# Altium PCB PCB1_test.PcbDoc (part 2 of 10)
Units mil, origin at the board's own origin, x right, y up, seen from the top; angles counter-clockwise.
Board outline 6690 x 6690 mil, 6 copper layers (Layer 1 - Top Layer, Layer 2 - GND, Layer 3 - PWR, Layer 4 - Signal, Layer 5 - GND, Layer 6 - Bottom Layer), stack 80.244 mil thick; 821 components, 458 nets, 3746 pads, 1527 vias.

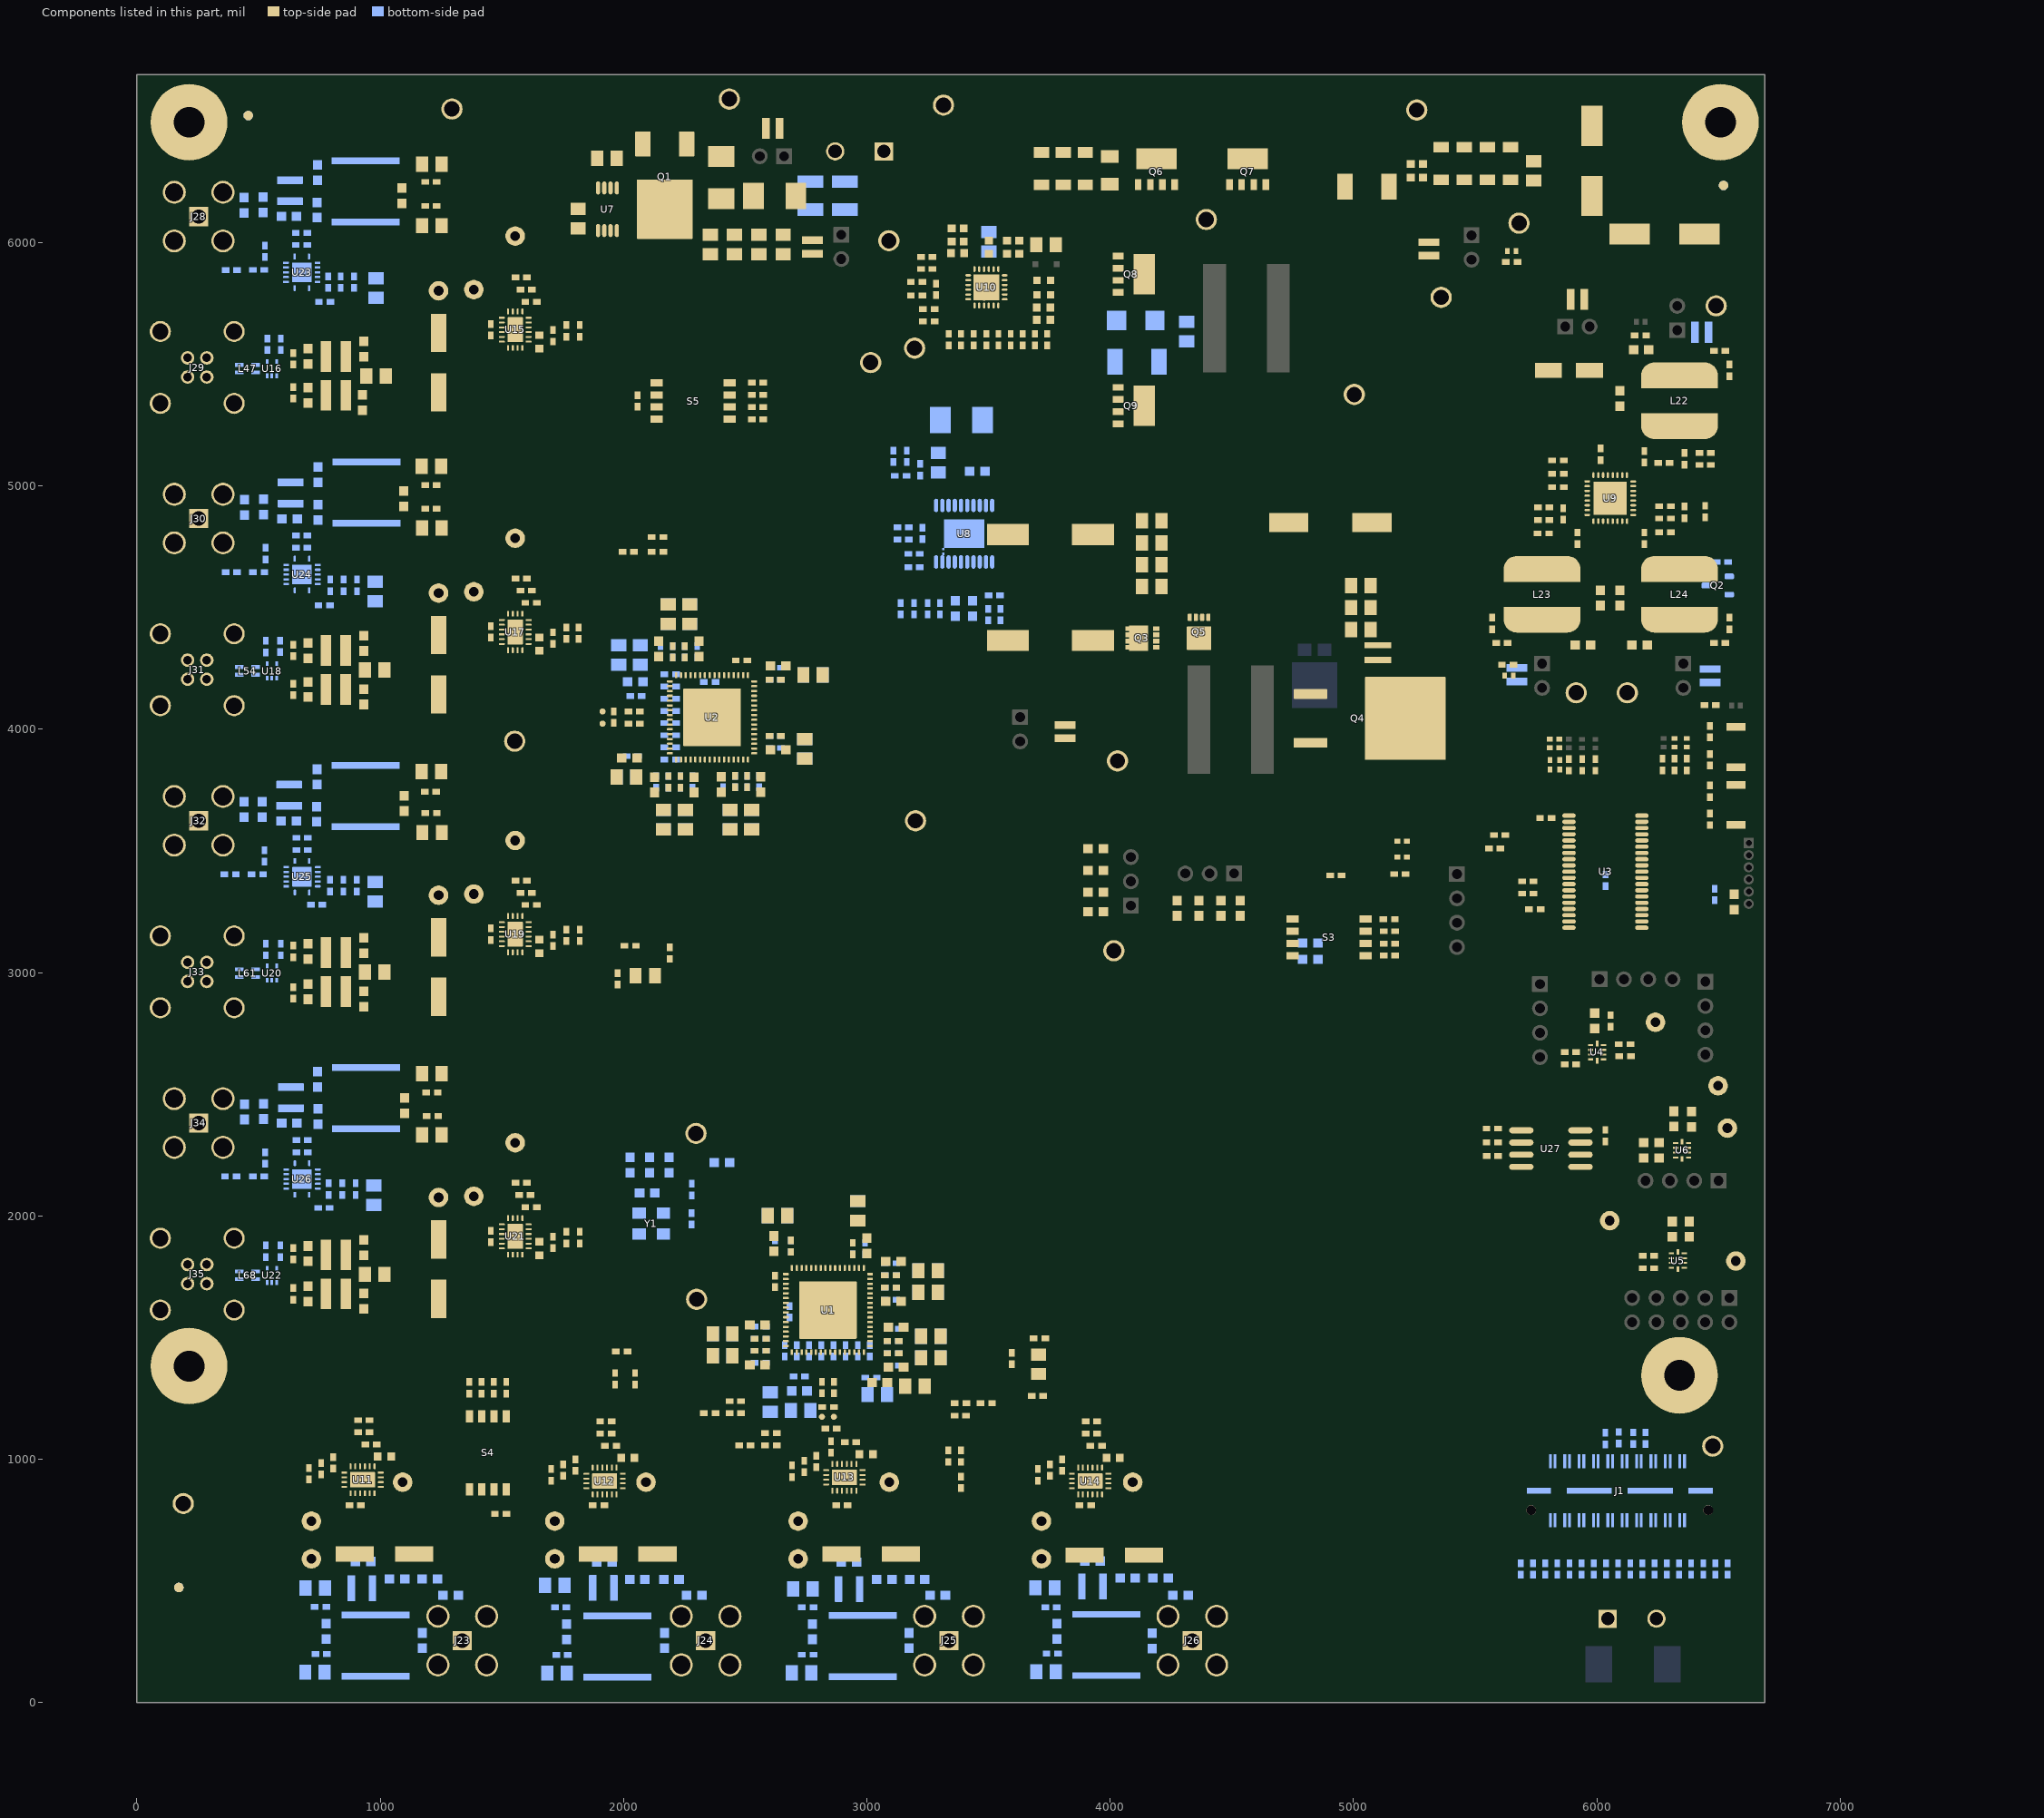
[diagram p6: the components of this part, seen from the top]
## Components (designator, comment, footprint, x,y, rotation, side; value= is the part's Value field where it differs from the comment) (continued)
L27 "MPZ1608S102ATA00" 0603 1766.93,291.41 r90 bottom value="1000 ohm"
L28 "LQH3NPZ100MJRL" LQH3NPZ_JR 925,470 r180 bottom value=10uH
L29 "LQH3NPZ100MJRL" LQH3NPZ_JR 1916.93,471.41 r180 bottom value=10uH
L30 "BLM18HE152SN1D" 0603 1069.95,508.45 r180 bottom value="1500 ohm"
L31 "BLM18HE152SN1D" 0603 2056.93,506.41 r180 bottom value="1500 ohm"
L32 "BLM18HE152SN1D" 0603 1203.94,508.45 r180 bottom value="1500 ohm"
L33 "BLM18HE152SN1D" 0603 2196.93,506.41 r180 bottom value="1500 ohm"
L34 "MPZ1608S102ATA00" 0603 2776.93,291.92 r90 bottom value="1000 ohm"
L35 "MPZ1608S102ATA00" 0603 3781.93,293.42 r90 bottom value="1000 ohm"
L36 "BLM18HE152SN1D" 0603 1290,441 r180 bottom value="1500 ohm"
L37 "BLM18HE152SN1D" 0603 2291,442 r180 bottom value="1500 ohm"
L38 "LQH3NPZ100MJRL" LQH3NPZ_JR 2926.93,466.92 r180 bottom value=10uH
L39 "LQH3NPZ100MJRL" LQH3NPZ_JR 3926.93,476.92 r180 bottom value=10uH
L40 "BLM18HE152SN1D" 0603 3071.93,506.92 r180 bottom value="1500 ohm"
L41 "BLM18HE152SN1D" 0603 4071.93,511.92 r180 bottom value="1500 ohm"
L42 "MPZ1608S102ATA00" 0603 1089,6192.5 r270 top value="1000 ohm"
L43 "BLM18HE152SN1D" 0603 3206.93,506.92 r180 bottom value="1500 ohm"
L44 "BLM18HE152SN1D" 0603 4206.93,511.92 r180 bottom value="1500 ohm"
L45 "EPL3012-103MLB" EPL3012 818,5372.38 r0 top value=10uH
L46 "EPL3012-103MLB" EPL3012 818,5532.38 r0 top value=10uH
L47 "DLW21HN900SQ2L" DLW21H 455,5482 r270 bottom
L48 "BLM18HE152SN1D" 0603 3291,441 r180 bottom value="1500 ohm"
L49 "MPZ1608S102ATA00" 0603 1097,4947.5 r270 top value="1000 ohm"
L50 "BLM18HE152SN1D" 0603 4289,442 r180 bottom value="1500 ohm"
L51 "LQH3NPZ100MJRL" LQH3NPZ_JR 629.28,6213.02 r90 bottom value=10uH
L52 "EPL3012-103MLB" EPL3012 817.91,4163.62 r0 top value=10uH
L53 "EPL3012-103MLB" EPL3012 817.91,4323.62 r0 top value=10uH
L54 "DLW21HN900SQ2L" DLW21H 455,4240 r270 bottom
L55 "BLM18HE152SN1D" 0603 625.28,6107.02 r0 bottom value="1500 ohm"
L56 "MPZ1608S102ATA00" 0603 1098.38,3695.62 r270 top value="1000 ohm"
L57 "BLM18HE152SN1D" 0603 519.28,6155.02 r270 bottom value="1500 ohm"
L58 "BLM18HE152SN1D" 0603 440.28,6154.02 r90 bottom value="1500 ohm"
L59 "EPL3012-103MLB" EPL3012 818,2922 r0 top value=10uH
L60 "EPL3012-103MLB" EPL3012 818,3082 r0 top value=10uH
L61 "DLW21HN900SQ2L" DLW21H 455,2998 r270 bottom
L62 "LQH3NPZ100MJRL" LQH3NPZ_JR 632,4970.97 r90 bottom value=10uH
L63 "MPZ1608S102ATA00" 0603 1101,2453 r270 top value="1000 ohm"
L64 "BLM18HE152SN1D" 0603 628,4864.97 r0 bottom value="1500 ohm"
L65 "BLM18HE152SN1D" 0603 521,4913.97 r270 bottom value="1500 ohm"
L66 "EPL3012-103MLB" EPL3012 818,1680 r0 top value=10uH
L67 "EPL3012-103MLB" EPL3012 818,1840 r0 top value=10uH
L68 "DLW21HN900SQ2L" DLW21H 455,1756 r270 bottom
L69 "BLM18HE152SN1D" 0603 442,4911.97 r90 bottom value="1500 ohm"
L70 "LQH3NPZ100MJRL" LQH3NPZ_JR 626.5,3729 r90 bottom value=10uH
L71 "BLM18HE152SN1D" 0603 624.5,3623 r0 bottom value="1500 ohm"
L72 "BLM18HE152SN1D" 0603 515.5,3671 r270 bottom value="1500 ohm"
L73 "BLM18HE152SN1D" 0603 441.5,3670 r90 bottom value="1500 ohm"
L74 "LQH3NPZ100MJRL" LQH3NPZ_JR 633,2486 r90 bottom value=10uH
L75 "BLM18HE152SN1D" 0603 627,2381 r0 bottom value="1500 ohm"
L76 "BLM18HE152SN1D" 0603 521,2430 r270 bottom value="1500 ohm"
L77 "BLM18HE152SN1D" 0603 442,2428 r90 bottom value="1500 ohm"
L78 "BLM18SG121TN1D" 0603 2404.92,2219.48 r0 bottom value="120 ohm"
L79 "MSS7341-104MLB" MSS7341 981,234 r270 bottom value=100uH
L80 "MSS7341-104MLB" MSS7341 1974,231 r270 bottom value=100uH
L81 "MSS7341-104MLB" MSS7341 2984,232 r270 bottom value=100uH
L82 "MSS7341-104MLB" MSS7341 3984,237 r270 bottom value=100uH
L83 "MSS7341-104MLB" MSS7341 940.28,6210.04 r90 bottom value=100uH
L84 "MSS7341-104MLB" MSS7341 944,4972.96 r90 bottom value=100uH
L85 "MSS7341-104MLB" MSS7341 939.5,3726 r90 bottom value=100uH
L86 "MSS7341-104MLB" MSS7341 943,2483.98 r90 bottom value=100uH
Logo1 "Texas Instruments" TI_Stacked_Overlay_Small 4157.12,2878.1 r0 top
Logo2 "RoHS Exempt" RoHS_Exempt 2731.09,2357.8 r0 top
Logo3 "FCC disclaimer" FCC_disclaimer 1268.88,2231.3 r0 top
NT1 "Net-Tie" Net-Tie_10mil 3481.38,5756.38 r270 top net-tie
NT2 "Net-Tie" Net-Tie_10mil 3313.84,4730.86 r90 bottom net-tie
Q1 "IPD90N04S304ATMA1" DPAK 2169.66,6271.35 r270 top value=40V
Q2 "BSS138" SOT-23 6496.55,4590.91 r180 bottom value=50V
Q3 "CSD17577Q3A" TRANS_NexFET_Q3A 4125,4375 r180 top value=30V
Q4 "CSD19536KTT" KTT0002A_N 5065,4045 r0 top value=100V
Q5 "CSD16340Q3" DQG0008A 4365,4400 r270 top value=25V
Q6 "BUK9Y21-40E,115" LFPAK56 4190,6345 r0 top value=40V
Q7 "BUK9Y21-40E,115" LFPAK56 4565,6345 r0 top value=40V
Q8 "BUK9Y21-40E,115" LFPAK56 4140,5870 r270 top value=40V
Q9 "BUK9Y21-40E,115" LFPAK56 4140,5330 r270 top value=40V
R1 "CRCW04020000Z0ED" 0402#1 5687.23,549.48 r90 bottom value=0
R2 "CRCW04020000Z0ED" 0402#1 5737.23,549.48 r270 bottom value=0
R3 "CRCW04020000Z0ED" 0402#1 5787.23,549.48 r90 bottom value=0
R4 "CRCW04020000Z0ED" 0402#1 5837.23,549.48 r270 bottom value=0
R5 "CRCW04020000Z0ED" 0402#1 5887.23,549.48 r90 bottom value=0
R6 "CRCW04020000Z0ED" 0402#1 5937.23,549.48 r270 bottom value=0
R7 "CRCW04020000Z0ED" 0402#1 5987.23,549.48 r90 bottom value=0
R8 "CRCW04020000Z0ED" 0402#1 6037.23,549.48 r270 bottom value=0
R9 "CRCW04020000Z0ED" 0402#1 6087.23,549.48 r90 bottom value=0
R10 "CRCW04020000Z0ED" 0402#1 6137.23,549.48 r270 bottom value=0
R11 "CRCW04020000Z0ED" 0402#1 6187.23,549.48 r90 bottom value=0
R12 "CRCW04020000Z0ED" 0402#1 6237.23,549.48 r270 bottom value=0
R13 "CRCW04020000Z0ED" 0402#1 6149.3,1086.63 r90 bottom value=0
R14 "CRCW04020000Z0ED" 0402#1 6199.3,1086.63 r270 bottom value=0
R15 "CRCW04020000Z0ED" 0402#1 6287.23,549.48 r90 bottom value=0
R16 "CRCW04020000Z0ED" 0402#1 6337.23,549.48 r270 bottom value=0
R17 "CRCW04020000Z0ED" 0402#1 6387.23,549.48 r90 bottom value=0
R18 "CRCW04020000Z0ED" 0402#1 6437.23,549.48 r270 bottom value=0
R19 "CRCW04020000Z0ED" 0402#1 6487.23,549.48 r90 bottom value=0
R20 "CRCW04020000Z0ED" 0402#1 6537.23,549.48 r270 bottom value=0
R21 "CRCW040213K3FKED" 0402#1 1992.56,1442.68 r0 top value=13.3k
R22 "CRCW0402487RFKED" 0402#1 3700.76,1260.96 r0 top value=487
R23 "CRCW040213K3FKED" 0402#1 1366,1293.87 r90 top value=13.3k
R24 "CRCW040282K5FKED" 0402#1 1416,1293.87 r90 top value=82.5k
R25 "CRCW040240K2FKED" 0402#1 2047.56,1330.87 r90 top value=40.2k
R26 "CRCW040210K0JNED" 0402#1 3595.36,1414.27 r90 top value=10k
R27 "CRCW040240K2FKED" 0402#1 1467.42,1293.87 r90 top value=40.2k
R28 "CRCW0402102KFKED" 0402#1 1518,1293.87 r90 top value=102k
R29 "CRCW0402100RFKED" 0402#1 2840.56,1214.49 r0 top value=100
R30 "CRCW040210K0JNED" 0402#1 3709.25,1497.08 r0 top value=10k
R31 "CRCW040210K0JNED" 0402#1 2280.09,1988.25 r90 bottom value=10k
R32 "CRCW06030000Z0EA" 0603 2027.79,2209.09 r90 bottom value=0
R33 "CRCW06030000Z0EA" 0603 2107.79,2209.09 r90 bottom value=0
R34 "CRCW0402113KFKED" 0402#1 2020,4730 r180 top value=113k
R35 "CRCW0402487RFKED" 0402#1 1976.09,2974.41 r270 top value=487
R36 "CRCW040213K3FKED" 0402#1 2551.31,5424.2 r0 top value=13.3k
R37 "CRCW040282K5FKED" 0402#1 2551.31,5374.2 r0 top value=82.5k
R38 "CRCW040288K7FKED" 0402#1 2140,4790 r180 top value=88.7k
R39 "CRCW040210K0JNED" 0402#1 2027.73,3110.22 r180 top value=10k
R40 "CRCW040240K2FKED" 0402#1 2551.31,5324.2 r0 top value=40.2k
R41 "CRCW0402102KFKED" 0402#1 2551.31,5274.2 r0 top value=102k
R42 "CRCW0402100RFKED" 0402#1 1960,4050 r270 top value=100
R43 "CRCW040210K0JNED" 0402#1 2190,3080 r90 top value=10k
R44 "CRCW0402200RJNED" 0402#1 5190,3405 r0 top value=200
R45 "CRCW0402200RJNED" 0402#1 5600,3565 r180 top value=200
R46 "CRCW0402200RJNED" 0402#1 5580,3510 r180 top value=200
R47 "CRCW0402200RJNED" 0402#1 6035,1085 r90 bottom value=200
R48 "CRCW0402200RJNED" 0402#1 6090,1088.62 r90 bottom value=200
R49 "CRCW0402200RJNED" 0402#2 5200,3475 r0 top value=200
R50 "CRCW0402200RJNED" 0402#2 5200,3540 r0 top value=200
R51 "CRCW0402220RJNED" 0402#1 5885,3853.62 r270 top value=220
R52 "CRCW040210K0JNED" 0402#1 6465,3990 r90 top value=10k
R53 "CRCW040210K0JNED" 0402#1 6465,3745 r90 top value=10k
R54 "CRCW04024K70JNED" 0402#1 6114.17,2706.06 r0 top value=4.7K
R55 "CRCW04024K70JNED" 0402#1 6115.98,2656.06 r0 top value=4.7K
R56 "CRCW04024K70JNED" 0402#1 5890.98,2672.86 r0 top value=4.7K
R57 "CRCW04024K70JNED" 0402#1 5890.98,2622.86 r0 top value=4.7K
R58 "CRCW0402487RFKED" 0402#2 5847,3854.62 r270 top value=487
R59 "CRCW0402487RFKED" 0402#2 5807,3854.62 r270 top value=487
R60 "CRCW0402220RJNED" 0402#1 5940,3853.62 r270 top value=220
R61 "CRCW0402220RJNED" 0402#1 5994,3853.62 r270 top value=220
R62 "CRCW06034K02FKEA" 0603 930,580 r180 bottom value=4.02k
R63 "CRCW04020000Z0ED" 0402#1 5716.22,3375 r0 top value=0
R64 "CRCW04020000Z0ED" 0402#1 5716.22,3325 r0 top value=0
R65 "CRCW040220K0JNED" 0402#1 6055.98,2801.56 r270 top value=20k
R66 "CRCW06030000Z0EA" 0603 6565,3290 r270 top value=0
R67 "CRCW04024K70JNED" 0402#1 6211.69,1836.33 r180 top value=4.7K
R68 "CRCW04024K70JNED" 0402#1 6211.69,1785.33 r180 top value=4.7K
R69 "CRCW06034K70JNEA" 0603 6379.69,1945.63 r270 top value=4.7k
R70 "CRCW06034K70JNEA" 0603 6389,2398 r270 top value=4.7k
R71 "CRCW06034K70JNEA" 0603 6224,2301 r180 top value=4.7k
R72 "CRCW06034K70JNEA" 0603 6223.37,2238.7 r180 top value=4.7k
R73 "CRCW0402100RFKED" 0402#1 3498.84,4470.86 r270 bottom value=100
R74 "CRCW0402100RFKED" 0402#1 3548.84,4470.86 r270 bottom value=100
R75 "CRCW06030000Z0EA" 0603 3433.84,4495.86 r270 bottom value=0
R76 "CRCW040249K9FKED" 0402#1 3300,4495 r270 bottom value=49.9k
R77 "CRCW040247K0JNED" 0402#1 3193.84,4665.86 r180 bottom value=47k
R78 "CRCW04020000Z0ED" 0402#1 3138.84,5041.69 r180 bottom value=0
R79 "CRCW040218K2FKED" 0402#1 3250,4495 r90 bottom value=18.2k
R80 "CRCW040228K7FKED" 0402#1 3138.84,4495.86 r90 bottom value=28.7k
R81 "CRCW0402107KFKED" 0402#1 3108.84,5121.69 r270 bottom value=107k
R82 "CRCW04025K23FKED" 0402#1 3193.84,4720.86 r0 bottom value=5.23k
R83 "CRCW04020000Z0ED" 0402#1 3163.84,5121.69 r270 bottom value=0
R84 "CRCW040228K0FKED" 0402#1 3148.84,4829.66 r180 bottom value=28.0k
R85 "CRCW040245K3FKED" 0402#1 6505,5555 r180 top value=45.3k
R86 "CRCW040214K0FKED" 0402#1 6444.77,5086.38 r180 top value=14.0k
R87 "CRCW040210K0JNED" 0402#1 6545,5475 r90 top value=10k
R88 "CRCW0402360RJNED" 0402#1 6179,5619 r180 top value=360
R89 "CRCW0402100KDHEDP" 0402#1 6515.59,4687.59 r180 bottom value=100k
R90 "CRCW040210R0JNED" 0402#1 5840,4995 r0 top value=10
R91 "CRCW040220K0JNED" 0402#1 5610,4355 r0 top value=20k
R92 "CRCW06034K02FKEA" 0603 1921.93,576.41 r180 bottom value=4.02k
R93 "CRCW06034K02FKEA" 0603 2926.93,576.92 r180 bottom value=4.02k
R94 "CRCW04026K98FKED" 0402#1 5861.22,4885 r270 top value=6.98k
R95 "CRCW040210K0JNED" 0402#1 5570,4435 r270 top value=10k
R96 "CRCW0402220RJNED" 0402#1 5633.35,4265 r0 top value=220
R97 "CRCW04028K25FKED" 0402#1 6505,4355 r180 top value=8.25k
R98 "CRCW04024K87FKED" 0402#1 6280,4916.65 r0 top value=4.87k
R99 "CRCW040210R0JNED" 0402#1 5840,5050 r0 top value=10
R100 "CRCW040221K5FKED" 0402#1 6445,4895 r90 top value=21.5k
R101 "CRCW040210K0JNED" 0402#1 6545,4435 r270 top value=10k
R102 "CRCW0402360RJNED" 0402#1 6465.31,4099.26 r0 top value=360
R103 "CRCW04020000Z0ED" 0402#1 3336.38,5601.38 r270 top value=0
R104 "CRCW04020000Z0ED" 0402#1 3690.95,5601.38 r270 top value=0
R105 "CRCW04020000Z0ED" 0402#1 3246.38,5941.38 r180 top value=0
R106 "CRCW04020000Z0ED" 0402#1 3640.95,5601.38 r270 top value=0
R107 "CRCW04020000Z0ED" 0402#1 3490.95,5601.38 r270 top value=0
R108 "CRCW06034R99FKEA" 0603L 3626.38,5981.38 r90 top value=4.99
R109 "CRCW06030000Z0EA" 0603L 3576.38,5981.38 r90 top value=0
R110 "CRCW04020000Z0ED" 0402#1 3386.38,5601.38 r90 top value=0
R111 "CRCW04020000Z0ED" 0402#1 3740.95,5601.38 r90 top value=0
R112 "CRCW04020000Z0ED" 0402#1 3246.38,5891.38 r0 top value=0
R113 "CRCW04020000Z0ED" 0402#1 3540.95,5601.38 r90 top value=0
R114 "CRCW06034R99FKEA" 0603L 3726.38,5682.68 r0 top value=4.99
R115 "CRCW06034R99FKEA" 0603L 3726.38,5732.68 r0 top value=4.99
R116 "CRCW06032R20JNEA" 0603L 3501.38,5981.38 r90 top value=2.2
R117 "PMR50HZPFV4L00" 2010 5055,6230 r0 top value=0.004
R118 "CRCW060349R9FKEA" 0603L 3348.03,6031.38 r90 top value=49.9
R119 "CRCW06030000Z0EA" 0603L 3398.03,6031.38 r90 top value=0
R120 "CRCW0805100KFKEA" 0805_HV 5740,6295 r270 top value=100k
R121 "CRCW04022K20JNED" 0402#1 5650,5920 r180 top value=2.2k
R122 "CRCW201010R0JNEF" 2010 4110,5510 r0 bottom value=10
R123 "CRCW040212K1FKED" 0402#1 3204.57,5783.03 r0 top value=12.1k
R124 "CRCW06034K02FKEA" 0603 3926.93,581.92 r180 bottom value=4.02k
R125 "CRCW06034K02FKEA" 0603 741.28,6134.02 r90 bottom value=4.02k
R126 "CRCW06034K02FKEA" 0603 744,4891.97 r90 bottom value=4.02k
R127 "CRCW06034K02FKEA" 0603 738.5,3651 r90 bottom value=4.02k
R128 "CRCW06030000Z0EA" 0603 4275,3265 r90 top value=0
R129 "CRCW06030000Z0EA" 0603 4365,3265 r90 top value=0
R130 "CRCW06030000Z0EA" 0603 4455,3265 r90 top value=0
R131 "CRCW06030000Z0EA" 0603 4535,3265 r90 top value=0
R132 "CRCW040249R9FKED" 0402#1 2354,1189 r0 top value=49.9
R133 "CRCW040249R9FKED" 0402#1 2499,1057 r0 top value=49.9
R134 "CRCW06032K00FKEA" 0603 1173,255 r270 bottom value=2.00k
R135 "CRCW06032K00FKEA" 0603 2169,255 r270 bottom value=2.00k
R136 "CRCW0402309KFKED" 0402#1 962.56,1060.87 r0 top value=309k
R137 "CRCW0402309KFKED" 0402#1 1947.56,1055.87 r0 top value=309k
R138 "CRCW0402100KDHEDP" 0402#1 897.56,810.87 r0 top value=100k
R139 "CRCW0402100KDHEDP" 0402#1 1897.56,810.87 r0 top value=100k
R140 "CRCW040269K8FKED" 0402#1 932.56,1110.87 r0 top value=69.8k
R141 "CRCW040269K8FKED" 0402#1 1927.56,1105.87 r0 top value=69.8k
R142 "CRCW040230K9FKED" 0402#1 932.56,1160.87 r180 top value=30.9k
R143 "CRCW040230K9FKED" 0402#1 1927.56,1155.87 r180 top value=30.9k
R144 "CRCW040244K2FKED" 0402#1 807.56,985.87 r270 top value=44.2k
R145 "CRCW040244K2FKED" 0402#1 1802.56,975.87 r270 top value=44.2k
R146 "CRCW040216K9FKED" 0402#1 707.56,940.87 r270 top value=16.9k
R147 "CRCW040216K9FKED" 0402#1 1702.56,935.87 r270 top value=16.9k
R148 "CRCW06034K02FKEA" 0603 744,2409 r90 bottom value=4.02k
R149 "CRCW040210K0JNED" 0402#1 5571,2247 r180 top value=10k
R150 "CRCW040210K0JNED" 0402#1 5570,2303 r180 top value=10k
R151 "CRCW040210K0JNED" 0402#1 5570,2359 r180 top value=10k
R152 "CRCW040249R9FKED" 0402#1 3387,905 r90 top value=49.9
R153 "CRCW040249R9FKED" 0402#1 3491,1230 r180 top value=49.9
R154 "CRCW06032K00FKEA" 0603 3173,255 r270 bottom value=2.00k
R155 "CRCW06032K00FKEA" 0603 4173,254 r270 bottom value=2.00k
R156 "CRCW0402309KFKED" 0402#1 2932.56,1070.87 r0 top value=309k
R157 "CRCW0402309KFKED" 0402#1 3942.56,1055.87 r0 top value=309k
R158 "CRCW0402100KDHEDP" 0402#1 2897.56,810.87 r0 top value=100k
R159 "CRCW0402100KDHEDP" 0402#1 3897.56,810.87 r0 top value=100k
R160 "CRCW040269K8FKED" 0402#1 2852.56,1050.87 r90 top value=69.8k
R161 "CRCW040269K8FKED" 0402#1 3922.56,1105.87 r0 top value=69.8k
R162 "CRCW040230K9FKED" 0402#1 2852.56,1125.87 r180 top value=30.9k
R163 "CRCW040230K9FKED" 0402#1 3922.56,1155.87 r180 top value=30.9k
R164 "CRCW040244K2FKED" 0402#1 2792.56,990.87 r270 top value=44.2k
R165 "CRCW040244K2FKED" 0402#1 3802.56,975.87 r270 top value=44.2k
R166 "CRCW040216K9FKED" 0402#1 2692.56,950.87 r270 top value=16.9k
R167 "CRCW040216K9FKED" 0402#1 3702.56,935.87 r270 top value=16.9k
R168 "CRCW06030000Z0EA" 0603 3940,3510 r0 top value=0
R169 "CRCW06030000Z0EA" 0603 3940,3420 r0 top value=0
R170 "CRCW06030000Z0EA" 0603 3940,3330 r0 top value=0
R171 "CRCW06030000Z0EA" 0603 3940,3250 r0 top value=0
R172 "KRL2012E-M-R010-F-T5" KRL2012 2776,5982 r270 top value=0.01
R173 "KRL2012E-M-R010-F-T5" KRL2012 2613,6470 r180 top value=0.01
R174 "CRCW06030000Z0EA" 0603 928,5342.38 r90 top value=0
R175 "CRCW06030000Z0EA" 0603 932.92,5562.38 r270 top value=0
R176 "CRCW0402309KFKED" 0402#1 1710,5617 r270 top value=309k
R177 "CRCW0402100KDHEDP" 0402#1 1455,5642 r270 top value=100k
R178 "CRCW040269K8FKED" 0402#1 1765,5637 r270 top value=69.8k
R179 "CRCW040230K9FKED" 0402#1 1820,5637 r90 top value=30.9k
R180 "CRCW040244K2FKED" 0402#1 1620,5757 r180 top value=44.2k
R181 "CRCW040216K9FKED" 0402#1 1580,5857 r180 top value=16.9k
R182 "CRCW040249R9FKED" 0402#1 643,5382.38 r90 top value=49.9
R183 "CRCW040249R9FKED" 0402#1 643,5522.38 r270 top value=49.9
R184 "CRCW040249R9FKED" 0402#1 388.28,5887.02 r0 bottom value=49.9
R185 "CRCW06032K00FKEA" 0603 743.28,6288.02 r90 bottom value=2.00k
R186 "CRCW040210K0JNED" 0402#1 6484.12,3321.27 r270 bottom value=10k
R187 "KRL2012E-M-R010-F-T5" KRL2012 3815,3990 r270 top value=0.01
R188 "CRCW06030000Z0EA" 0603 932.91,4133.62 r90 top value=0
R189 "CRCW06030000Z0EA" 0603 932.91,4353.62 r270 top value=0
R190 "CRCW0402309KFKED" 0402#1 1710,4375 r270 top value=309k
R191 "CRCW0402100KDHEDP" 0402#1 1455,4400 r270 top value=100k
R192 "CRCW040269K8FKED" 0402#1 1765,4395 r270 top value=69.8k
R193 "CRCW040230K9FKED" 0402#1 1815,4395 r90 top value=30.9k
R194 "CRCW040244K2FKED" 0402#1 1620,4520 r180 top value=44.2k
R195 "CRCW040249R9FKED" 0402#1 642.91,4163.62 r90 top value=49.9
R196 "CRCW040249R9FKED" 0402#1 642.91,4323.62 r270 top value=49.9
R197 "CRCW040216K9FKED" 0402#1 1580,4620 r180 top value=16.9k
R198 "CRCW040249R9FKED" 0402#1 389,4645.97 r0 bottom value=49.9
R199 "CRCW06032K00FKEA" 0603 745,5045.97 r90 bottom value=2.00k
R200 "KRL2012E-M-R010-F-T5" KRL2012 5920,5766.38 r0 top value=0.01
R201 "KRL2012E-M-R010-F-T5" KRL2012 6430.56,5632 r0 bottom value=0.01
R202 "CRCW06030000Z0EA" 0603 933,2892 r90 top value=0
R203 "CRCW06030000Z0EA" 0603 933,3112 r270 top value=0
R204 "CRCW0402309KFKED" 0402#1 1710,3133 r270 top value=309k
R205 "CRCW0402100KDHEDP" 0402#1 1455,3158 r270 top value=100k
R206 "CRCW040269K8FKED" 0402#1 1765,3153 r270 top value=69.8k
R207 "CRCW040230K9FKED" 0402#1 1820,3153 r90 top value=30.9k
R208 "CRCW040244K2FKED" 0402#1 1620,3278 r180 top value=44.2k
R209 "CRCW040216K9FKED" 0402#1 1580,3378 r180 top value=16.9k
R210 "CRCW040249R9FKED" 0402#1 643,2917 r90 top value=49.9
R211 "CRCW040249R9FKED" 0402#1 643,3087 r270 top value=49.9
R212 "CRCW040249R9FKED" 0402#1 383.5,3404 r0 bottom value=49.9
R213 "CRCW06032K00FKEA" 0603 741.5,3804 r90 bottom value=2.00k
R214 "KRL2012E-M-R010-F-T5" KRL2012 5671,4224.44 r270 bottom value=0.01
R215 "KRL2012E-M-R010-F-T5" KRL2012 6465,4220 r270 bottom value=0.01
R216 "CRCW06030000Z0EA" 0603 933,1650 r90 top value=0
R217 "CRCW06030000Z0EA" 0603 933,1870 r270 top value=0
R218 "CRCW0402309KFKED" 0402#1 1710,1891 r270 top value=309k
R219 "CRCW0402100KDHEDP" 0402#1 1455,1916 r270 top value=100k
R220 "CRCW040269K8FKED" 0402#1 1765,1911 r270 top value=69.8k
R221 "CRCW040230K9FKED" 0402#1 1820,1911 r90 top value=30.9k
R222 "CRCW040244K2FKED" 0402#1 1620,2036 r180 top value=44.2k
R223 "CRCW040249R9FKED" 0402#1 643,1680 r90 top value=49.9
R224 "CRCW040249R9FKED" 0402#1 643,1845 r270 top value=49.9
R225 "CRCW040216K9FKED" 0402#1 1580,2136 r180 top value=16.9k
R226 "CRCW040249R9FKED" 0402#1 386,2162 r0 bottom value=49.9
R227 "CRCW06032K00FKEA" 0603 743,2562 r90 bottom value=2.00k
R228 "CRCW0402200RJNED" 0402#1 4928,3399.49 r180 top value=200
R229 "CRCW04024K70JNED" 0402#1 676.94,6040.15 r180 bottom value=4.7k
R230 "CRCW06034K70JNEA" 0603 4822.69,3055 r180 bottom value=4.7k
R231 "CRCW04024K70JNED" 0402#1 676.94,5990.15 r0 bottom value=4.7k
R232 "CRCW04024K70JNED" 0402#1 771.94,5756.94 r180 bottom value=4.7k
R233 "CRCW06034K70JNEA" 0603 4822.69,3121.69 r180 bottom value=4.7k
R234 "CRCW04024K70JNED" 0402#1 677.56,4796.06 r180 bottom value=4.7k
R235 "CRCW0402200RJNED" 0402#1 5146.3,3220 r0 top value=200
R236 "CRCW04024K70JNED" 0402#1 677.56,4746.06 r0 bottom value=4.7k
R237 "CRCW04024K70JNED" 0402#1 770,4510 r180 bottom value=4.7k
R238 "CRCW04024K70JNED" 0402#1 5147.23,3170 r0 top value=4.7K
R239 "CRCW04024K70JNED" 0402#1 679,3554 r180 bottom value=4.7k
R240 "CRCW0402200RJNED" 0402#1 5147.67,3118.97 r0 top value=200
R241 "CRCW04024K70JNED" 0402#1 679,3504 r0 bottom value=4.7k
R242 "CRCW04024K70JNED" 0402#1 739,3279 r180 bottom value=4.7k
R243 "CRCW0402200RJNED" 0402#1 5147.67,3070 r0 top value=200
R244 "CRCW04024K70JNED" 0402#1 679,2312 r180 bottom value=4.7k
R245 "CRCW040210K0JNED" 0402#1 6035.44,3379.55 r270 bottom value=10k
R246 "CRCW04024K70JNED" 0402#1 679,2262 r0 bottom value=4.7k
R247 "CRCW04024K70JNED" 0402#1 769,2032.84 r180 bottom value=4.7k
R248 "CRCW0402487RFKED" 0402#1 6369.5,3855 r270 top value=487
R249 "CRCW0402487RFKED" 0402#1 6319.5,3855 r270 top value=487
R250 "CRCW0402220RJNED" 0402#1 6269.5,3855 r270 top value=220
R251 "CRCW06030000Z0EA" 0603 2187.79,2209.09 r90 bottom value=0
R252 "CRCW06030000Z0EA" 0603 2097.79,2094.09 r0 bottom value=0
R253 "KRL2012E-M-R010-F-T5" KRL2012 5310,5974 r270 top value=0.01
Rsense1 "PRL1632-R005-F-T1" 0612 5100,4315 r270 top value=0.005
S1 "SKRKAEE010" SW_SKRKAEE010 6570.98,3689.33 r270 top
S2 "SKRKAEE010" SW_SKRKAEE010 6570.98,3927.19 r270 top
S3 "218-4LPST" SW_218-4LPST 4899,3145.05 r0 top
S4 "218-4LPST" SW_218-4LPST 1442.56,1026.74 r90 top
S5 "218-4LPST" SW_218-4LPST 2286.31,5349.2 r0 top
TP1 "TP-025-SMT" TP_25MIL-SMT 2864.33,1174.49 r90 top value=STD
TP2 "TP-025-SMT" TP_25MIL-SMT 2815.51,1174.49 r90 top value=STD
TP3 "TP-025-SMT" TP_25MIL-SMT 1914,4023.19 r0 top value=STD
TP4 "TP-025-SMT" TP_25MIL-SMT 1914,4073.19 r0 top value=STD
TP5 "5004" Keystone5004 6240.62,2795.95 r0 top value=Yellow
TP6 "5004" Keystone5004 6536.38,2360.78 r0 top value=Yellow
TP7 "5004" Keystone5004 6571.03,1814.74 r0 top value=Yellow
TP8 "5004" Keystone5004 6052.78,1980.54 r0 top value=Yellow
TP9 "5004" Keystone5004 6498,2535 r0 top value=Yellow
TP10 "5012" Keystone5012 3015.75,5507 r0 top
TP11 "5012" Keystone5012 3196.38,5566.38 r0 top
TP12 "GND" Keystone5011 3315,6565 r0 top value=Black
TP13 "SW" Keystone5012 4395,6095 r0 top value=White
TP14 "+VOUT" Keystone5010 5680,6080 r0 top value=Red
TP15 "GND" Keystone5011 5260,6545 r0 top value=Black
TP16 "5000" Keystone5000 1092.56,905.87 r90 top value=Red
TP17 "5000" Keystone5000 2092.56,905.87 r0 top value=Red
TP18 "5004" Keystone5004 717.56,590.87 r90 top value=Yellow
TP19 "5004" Keystone5004 1717.56,590.87 r0 top value=Yellow
TP20 "5004" Keystone5004 717.56,745.87 r90 top value=Yellow
TP21 "5004" Keystone5004 1717.56,745.87 r0 top value=Yellow
TP22 "5000" Keystone5000 3092.56,905.87 r0 top value=Red
TP23 "5000" Keystone5000 4092.56,905.87 r0 top value=Red
TP24 "5004" Keystone5004 2717.56,590.87 r0 top value=Yellow
TP25 "5004" Keystone5004 3717.56,590.87 r0 top value=Yellow
TP26 "5004" Keystone5004 2717.56,745.87 r0 top value=Yellow
TP27 "5004" Keystone5004 3717.56,745.87 r0 top value=Yellow
TP28 "5000" Keystone5000 1240,5802 r0 top value=Red
TP29 "5004" Keystone5004 1385,5807 r0 top value=Yellow
TP30 "5004" Keystone5004 1555,6027 r0 top value=Yellow
TP31 "5000" Keystone5000 1240,4560 r0 top value=Red
TP32 "5004" Keystone5004 1385,4565 r0 top value=Yellow
TP33 "5004" Keystone5004 1555,4785 r0 top value=Yellow
TP34 "5000" Keystone5000 1240,3318 r0 top value=Red
TP35 "5004" Keystone5004 1385,3323 r0 top value=Yellow
TP36 "5004" Keystone5004 1555,3543 r0 top value=Yellow
TP37 "5000" Keystone5000 1240,2076 r0 top value=Red
TP38 "5004" Keystone5004 1385,2081 r0 top value=Yellow
TP39 "5004" Keystone5004 1555,2301 r0 top value=Yellow
TP40 "GND" Keystone5011 191,818 r90 top value=Black
TP41 "GND" Keystone5011 1295,6549 r90 top value=Black
TP42 "GND" Keystone5011 6476,1054 r90 top value=Black
TP43 "GND" Keystone5011 3200,3624 r90 top value=Black
TP44 "GND" Keystone5011 2300.43,1657.48 r90 top value=Black
TP45 "V_bat" Keystone5011 2435,6590 r90 top value=Black
TP46 "5V" Keystone5011 5360,5775 r90 top value=Black
TP47 "12V" Keystone5011 4030,3870 r90 top value=Black
TP48 "1V8" Keystone5011 5915,4150 r90 top value=Black
TP49 "3V3" Keystone5011 6490,5740 r90 top value=Black
TP50 "1V1" Keystone5011 6125,4150 r90 top value=Black
TP51 "Vin_protect" Keystone5011 3090.55,6007.87 r90 top value=Black
TP52 "GND" Keystone5011 1553,3951 r90 top value=Black
TP53 "GND" Keystone5011 5003,5376 r90 top value=Black
TP54 "GND" Keystone5011 4015,3090 r90 top value=Black
TP55 "CLK" Keystone5011 2297.79,2339.09 r90 top value=Black
U1 "DS90UB960TRGCRQ1" RGC0064G 2840.12,1613.31 r180 top
U2 "DS90UB960TRGCRQ1" RGC0064G 2364,4049 r90 top
U3 "MSP430F2272TDAQ1" DA0038A_N 6035,3415 r0 top
U4 "TS3USB221AQRSERQ1" RSE0010A 6000.98,2672.86 r0 top
U5 "TS3USB221AQRSERQ1" RSE0010A 6332.69,1816.63 r0 top
U6 "TS3USB221AQRSERQ1" RSE0010A 6350,2270 r0 top
U7 "LM74610QDGKRQ1" DGK0008A_N 1934.03,6137.11 r270 top
U8 "LM5121MH/NOPB" PWP0020A_N 3399.84,4803.86 r90 bottom
U9 "TPS65263QRHBRQ1" RHB0032E 6055,4950 r0 top
U10 "LM5141QRGERQ1" RGE0024H 3491.38,5816.38 r90 top
U11 "TPS25940ARVCR" RVC0020A 927.56,915.87 r90 top
U12 "TPS25940ARVCR" RVC0020A 1922.56,910.87 r90 top
U13 "TPS25940ARVCR" RVC0020A 2907.56,925.87 r90 top
U14 "TPS25940ARVCR" RVC0020A 3917.56,910.87 r90 top
U15 "TPS25940ARVCR" RVC0020A 1555,5642 r0 top
U16 "TPD2E001DRLR" DRL0005A 555,5482 r90 bottom
U17 "TPS25940ARVCR" RVC0020A 1555,4400 r0 top
U18 "TPD2E001DRLR" DRL0005A 555,4240 r90 bottom
U19 "TPS25940ARVCR" RVC0020A 1555,3158 r0 top
U20 "TPD2E001DRLR" DRL0005A 555,2998 r90 bottom
U21 "TPS25940ARVCR" RVC0020A 1555,1916 r0 top
U22 "TPD2E001DRLR" DRL0005A 555,1756 r90 bottom
U23 "HD3SS3411IRWARQ1" RWA0014A 678,5878 r180 bottom
U24 "HD3SS3411IRWARQ1" RWA0014A 678.94,4636.06 r180 bottom
U25 "HD3SS3411IRWARQ1" RWA0014A 679,3394 r180 bottom
U26 "HD3SS3411IRWARQ1" RWA0014A 679,2152 r180 bottom
U27 "CAT24C256WI-GT3" so8-25x75-295 5810.97,2276.71 r270 top
Y1 "7C-25.000MCB-T" TXC_7C 2114.1,1968.71 r90 bottom
ZZ1 "This Assembly Note is for PCB labels only" AssemblyNoteLabel -1465,7348 r0 top
ZZ2 "These assemblies are ESD sensitive, ESD precautions shall be observed." AssemblyNote -1465,7239.11 r0 top
ZZ3 "These assemblies must be clean and free from flux and all contaminants. Use of no clean flux is not acceptable." AssemblyNote -1465,7150.56 r0 top
ZZ4 "These assemblies must comply with workmanship standards IPC-A-610 Class 2, unless otherwise specified." AssemblyNote -1465,7062 r0 top

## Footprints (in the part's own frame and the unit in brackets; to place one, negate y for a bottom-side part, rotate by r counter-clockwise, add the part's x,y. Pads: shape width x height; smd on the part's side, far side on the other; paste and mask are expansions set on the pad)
0402#1 [mm] "0402 from SM-752 data"
  rect 0.8x0.6 smd: 1(-0.6,0) 2(0.6,0)
  silkscreen extent -1.22,-0.52 1.22,0.52, body extent -0.55,-0.3 0.55,0.3, height 0.6
0402#2 [mm] "Chip Capacitor, Body 1.0x0.5mm, IPC High Density"
  rect 0.6x0.5 smd: 1(-0.5,0) 2(0.5,0)
  body extent -0.55,-0.3 0.55,0.3, height 1.3
0603 [mm] "0603 from SM-752 data"
  rect 1x0.95 smd: 1(-0.8,0) 2(0.8,0)
  silkscreen extent -1.52,-0.69 1.52,0.69, body extent -0.87,-0.47 0.87,0.47, height 1
0603_HV [mil] "Ernesto recommended land pattern.  26 mil between pads."
  rect 30x30 smd: 1(-28,0) 2(28,0)
  silkscreen extent -52,-24 52,24, body extent -34,-19 34,19, height 39
0603L [mm] "0603 from SM-752 data"
  rect 0.8x0.85 smd: 1(-0.7,0) 2(0.7,0)
  silkscreen extent -0.07,-0.33 0.07,0.33, body extent -0.87,-0.47 0.87,0.47, height 1
0612 [mm] "Panasonic recommended land pattern, fb97d03ed01.pdf dated April 2008"
  rect 0.65x2.75 smd: 1(-0.775,0) 2(0.775,0)
  silkscreen extent -1.1,-1.9 1.1,1.9, body extent -0.9,-1.7 0.9,1.7, height 0.85
0805_HV [mil] "0805 with 30mil clearance between pads"
  rect 50x63 smd: 1(-40,0) 2(40,0)
  silkscreen extent -74,-40 74,40, body extent -43,-29 43,29, height 57
1206 [mm] "1206 from SM-752 data"
  rect 1.3x1.85 smd: 1(-1.45,0) 2(1.45,0)
  silkscreen extent -2.4,-1.21 2.4,1.21, body extent -1.7,-0.9 1.7,0.9, height 1.35
1206_180 [mm] "1206_180"
  rect 1.1x1.6 smd: 1(-1.7,0) 2(1.7,0)
  silkscreen extent -0.9,-1 0.9,1, body extent -1.75,-0.95 1.75,0.95, height 1.8
1206_190 [mm] "1206_190"
  rect 1.1x1.6 smd: 1(-1.7,0) 2(1.7,0)
  silkscreen extent -0.9,-1 0.9,1, body extent -1.75,-0.95 1.75,0.95, height 1.9
1210_220 [mm] "1210"
  rect 1.3x2.7 smd: 1(-1.45,0) 2(1.45,0)
  silkscreen extent -2.32,-1.57 2.32,1.57, body extent -1.7,-1.35 1.7,1.35, height 2.2
2010 [mm] "Chip Capacitor, Body 5.08x2.54mm, IPC Medium Density"
  rect 1.6x2.7 smd: 1(-2.3,0) 2(2.3,0)
  silkscreen extent -3.42,-1.65 3.42,1.65, body extent -2.73,-1.45 2.73,1.45, height 1.66
AssemblyNote [mil] "Assembly Note"
AssemblyNoteLabel [mil] "Assembly Note for PCB Labels"
CAPSMT_62_H70 [mm] "8 x 6.7mm:  Chemi-Con H70"
  rect 4.2x2.2 smd: 1(-3.638,0.012) 2(3.662,0.012)
  silkscreen extent -4.24,-4.24 4.26,4.26, body extent -4.24,-4.24 4.26,4.26, height 7
CAPSMT_62_JC0 [mm] "10 x 12.2mm:  Chemi-Con JC0"
  rect 4.4x2.2 smd: 1(-4.45,0) 2(4.45,0)
  silkscreen extent -5.25,-5.25 5.25,5.25, body extent -5.25,-5.25 5.25,5.25, height 12.7
DA0038A_N [mm] "TSOP, 38-Leads, Body 12.6x6.2mm (max), Pitch 0.65mm, IPC Medium Density"
  oval 1.4x0.45 smd: 1(-3.8,5.85) 2(-3.8,5.2) 3(-3.8,4.55) 4(-3.8,3.9) 5(-3.8,3.25) 6(-3.8,2.6) 7(-3.8,1.95) 8(-3.8,1.3) 9(-3.8,0.65) 10(-3.8,0) 11(-3.8,-0.65) 12(-3.8,-1.3) 13(-3.8,-1.95) 14(-3.8,-2.6) 15(-3.8,-3.25) 16(-3.8,-3.9) 17(-3.8,-4.55) 18(-3.8,-5.2) 19(-3.8,-5.85) 20(3.8,-5.85) 21(3.8,-5.2) 22(3.8,-4.55) 23(3.8,-3.9) 24(3.8,-3.25) 25(3.8,-2.6) 26(3.8,-1.95) 27(3.8,-1.3) 28(3.8,-0.65) 29(3.8,0) 30(3.8,0.65) 31(3.8,1.3) 32(3.8,1.95) 33(3.8,2.6) 34(3.8,3.25) 35(3.8,3.9) 36(3.8,4.55) 37(3.8,5.2) 38(3.8,5.85)
  silkscreen extent -4.45,-6.3 2.45,6.48, body extent -4.06,-6.25 4.06,6.25, height 1.2
DGK0008A_N [mm] "TSOP, 8-Leads, Body 3x3mm, Pitch 0.65mm, IPC Medium Density"
  oval 1.35x0.45 smd: 1(-2.225,0.975) 2(-2.225,0.325) 3(-2.225,-0.325) 4(-2.225,-0.975) 5(2.225,-0.975) 6(2.225,-0.325) 7(2.225,0.325) 8(2.225,0.975)
  silkscreen extent -2.75,-1.55 0.95,1.55, body extent -2.45,-1.5 2.45,1.5, height 0.96
DLW21H [mm] "muRata"
  rect 0.4x0.9 smd: 1(-0.4,0.85) 2(-0.4,-0.85) 3(0.4,-0.85) 4(0.4,0.85)
  silkscreen extent -0.96,0.88 -0.92,0.92, body extent -0.7,-1.1 0.7,1.1, height 1.41
DPAK [mm] "D-PAK, 3-Pads, Body 6.22x6.73mm (max), TO-252AA using nominal STEP model"
  rrect6% 2.6x1.6 smd: 1(-3.4,2.28) 3(-3.4,-2.28)
  rrect2% 6.2x5.8 smd paste-2.9: 4(3.4,0)
  silkscreen extent -4.5,-3.3 4.7,3.28, body extent -3.86,-3.29 5.84,3.29, height 2.48
DQG0008A [mm] "SMD, 8-Leads, Body 3.3x3.3mm, Pitch 0.65mm"
  rrect45% 0.75x0.44 smd paste-0.05 mask-0.05: 1(-1.525,0.975) 2(-1.525,0.325) 3(-1.525,-0.325) 4(-1.525,-0.975) 5(1.525,-0.975) 6(1.525,-0.325) 7(1.525,0.325) 8(1.525,0.975)
  rrect15% 0.676x1.125 on Top Paste: 9(-0.212,0.662) 9(-0.212,-0.662) 9(0.664,0.662) 9(0.664,-0.662)
  rrect6% 1.775x2.45 on Top Solder: 9(0.328,0)
  rrect8% 2.5x2.55 smd paste-1.5 mask-1.5: 9(0.65,0)
  rrect29% 0.5x0.34 on Top Solder: 9(1.175,0.975) 9(1.175,-0.325) 9(1.175,0.325) 9(1.175,-0.975)
  silkscreen extent -1.8,-1.8 1.8,1.8, body extent -1.65,-1.65 1.65,1.65, height 1.1
DRL0005A [mm] "SOTFL, 5-Flat Leads, Body 1.2x1.6x0.6mm, Pitch 0.5mm, TI recommended"
  rect 0.5x0.3 smd: 1(-0.75,0.5) 2(-0.75,0) 3(-0.75,-0.5) 4(0.75,-0.5) 5(0.75,0.5)
  silkscreen extent -0.9,-0.95 0.9,0.95, body extent -0.85,-0.85 0.85,0.85, height 0.62
EPL3012 [mm] "COILCRAFT"
  rect 1.12x3.2 smd: 1(-1.04,0) 2(1.04,0)
  silkscreen extent -0.22,-1.68 0.23,1.65, body extent -1.6,-1.6 1.6,1.6, height 1.3
FCC_disclaimer [mil]
Fiducial10-20 [mm]
  round 1 smd mask+0.5: 1(0,0)
  Layer 1 - Top Layer keep-out circle w1.178: c0,0 r0.5
Keystone5000 [mil] "For Keystone 500x miniature loop terminals"
  round 80 hole 40: 1(0,0)
  silkscreen extent -58,-58 58,58, body extent -49,-49 49,49, height 182
Keystone5004 [mil] "For Keystone 500x miniature loop terminals"
  round 80 hole 40: 1(0,0)
  silkscreen extent -58,-58 58,58, body extent -49,-49 49,49, height 182
Keystone5010 [mil] "Keystone Multipurpose loops"
  round 87 hole 63: 1(0,0)
  silkscreen extent -70,-70 70,70, body extent -63,-63 63,62, height 319
Keystone5011 [mil] "Keystone Multipurpose loops"
  round 87 hole 63: 1(0,0)
  silkscreen extent -70,-70 70,70, body extent -63,-63 63,62, height 319
Keystone5012 [mil] "Keystone Multipurpose loops"
  round 87 hole 63: 1(0,0)
  silkscreen extent -70,-70 70,70, body extent -63,-63 63,62, height 319
Keystone_1902C [mil] "Hex Standoff, 4-40 threaded, nylon"
  round 1 on Mech4: 0(0,0)
  body extent -145,-126 146,126, height 501
KRL2012 [mm] "SUSUMU"
  rect 0.8x2.2 smd: 1(-0.7,0) 2(0.7,0)
  silkscreen extent -0.2,-1.35 0.2,1.35, body extent -0.72,-1.1 0.72,1.1, height 0.7
KTT0002A_N [mm] "D2-PAK, 2-Leads, Body 9x10.1mm, Pitch 2.54mm, Lead Span 15.1mm, IPC Medium Density"
  rrect10% 3.5x1 smd: 1(-6.15,2.54) 3(-6.15,-2.54)
  rrect1% 8.4x8.65 smd paste-4.2: 2(3.75,0)
  silkscreen extent -7.75,-5.07 -1.78,5.07, body extent -6.68,-5.08 7.62,5.08, height 4.72
LED_SMLP12_ORANGE [mm] "Rohm Semiconductor"
  rect 0.5x0.6 smd mask+0.08: 1(-0.45,0) 2(0.45,0)
  silkscreen extent 0.93,-0.3 0.93,0.3, body extent -0.55,-0.35 0.55,0.35, height 0.25
LED_SMLP12_Yellow [mm] "Rohm Semiconductor"
  rect 0.5x0.6 smd mask+0.08: 1(-0.45,0) 2(0.45,0)
  silkscreen extent 0.93,-0.3 0.93,0.3, body extent -0.55,-0.35 0.55,0.35, height 0.25
LFPAK56 [mm] "NXP Semiconductor"
  rect 0.7x1.15 smd paste-0.05: 1(-1.905,-2.725) 2(-0.635,-2.725) 3(0.635,-2.725) 4(1.905,-2.725)
  rect 4.2x2.2 smd paste-1.52: 5(0,0)
  Layer 1 - Top Layer region: -2.1,0.65 2.1,0.65 2.1,2 -2.1,2
  Layer 1 - Top Layer region: -2.1,1.8 -2.1,2 -2.35,2 -2.35,3.5 2.35,3.5 2.35,2 2.1,2 2.1,1.8
  silkscreen extent -2.5,-3.3 -2.5,-1.8, body extent -2.43,-3.14 2.47,3.29, height 1.18
LQH3NPZ_JR [mm] "SMD, 2-Leads, Body 3x3mm"
  rrect12% 0.8x2.7 smd: 1(-1.1,0) 2(1.1,0)
  silkscreen extent -0.5,-1.6 0.5,1.6, body extent -1.6,-1.6 1.6,1.6, height 1.2
MSS7341 [mm] "Coilcraft recommended land pattern Document 383-2 1/3/11"
  rect 0.7x7.1 smd: 1(-3.2,0) 2(3.2,0)
  Layer 1 - Top Layer region: 1.05,3.55 3.55,3.55 3.55,-3.55 1.05,-3.55 1.05,-2.623 2.135,-1.85 2.745,-0.666 2.745,0.666 2.135,1.85 1.05,2.623 1.05,2.623
  Layer 1 - Top Layer region: -1.05,3.55 -3.55,3.55 -3.55,-3.55 -1.05,-3.55 -1.05,-2.623 -2.135,-1.85 -2.745,-0.666 -2.745,0.666 -2.135,1.85 -1.05,2.623 -1.05,2.623
  silkscreen extent -3.8,-3.8 3.8,3.8, body extent -3.78,-3.78 3.78,3.78, height 4.12
Net-Tie_10mil [mil] "10mil net tie, no solder mask opening, no solder paste"
  rect 10x10 smd paste-5 mask-5: 1(-10,0) 2(10,0)
  Layer 1 - Top Layer region: -6,5 6,5 6,-5 -6,-5
"NY PMS 440 0025 PH"#1 [mm] "4-40 nylon screw and mounting hole"
  round 8 hole 3.2: 1(-0.457,3.432)
  body extent -3.3,-3.3 3.3,3.3, height 2.69
"NY PMS 440 0025 PH"#2 [mm] "4-40 nylon screw and mounting hole"
  round 8 hole 3.2: 1(0.516,-0.835)
  body extent -3.3,-3.3 3.3,3.3, height 2.69
"NY PMS 440 0025 PH"#3 [mm] "4-40 nylon screw and mounting hole"
  round 8 hole 3.2: 1(1.467,3.435)
  body extent -3.3,-3.3 3.3,3.3, height 2.69
"NY PMS 440 0025 PH"#4 [mm] "4-40 nylon screw and mounting hole"
  round 8 hole 3.2: 1(0.502,-0.835)
  body extent -3.3,-3.3 3.3,3.3, height 2.69
Panasonic_G [mm] "SMD, 2-Leads, Dia 10mm"
  rect 4.1x2 smd: 1(-4.35,0) 2(4.35,0)
  silkscreen extent -5.25,-5.25 5.25,5.25, body extent -5.25,-5.25 5.25,5.25, height 10.51
PHOENIX_1757242 [mm] "Header, 5.08 mm, 2x1, R/A, TH"
  rect 1.9x1.9 hole 1.4: 1(0,0)
  round 1.9 hole 1.4: 2(-5.08,0)
  silkscreen extent -8.62,-2.47 3.54,10, body extent -8.64,-1.98 3.52,10.02, height 8.6
PWP0020A_N [mm] "TSOP, 20-Leads, Body 6.5x4.4mm, Pitch 0.65mm, Exposed Pad, IPC Medium Density"
  rrect100% 1.4x0.45 smd: 1(-2.95,2.925) 2(-2.95,2.275) 3(-2.95,1.625) 4(-2.95,0.975) 5(-2.95,0.325) 6(-2.95,-0.325) 7(-2.95,-0.975) 8(-2.95,-1.625) 9(-2.95,-2.275) 10(-2.95,-2.925) 11(2.95,-2.925) 12(2.95,-2.275) 13(2.95,-1.625) 14(2.95,-0.975) 15(2.95,-0.325) 16(2.95,0.325) 17(2.95,0.975) 18(2.95,1.625) 19(2.95,2.275) 20(2.95,2.925)
  rrect3% 3x4.2 smd: 21(0,0)
  silkscreen extent -3.55,-3.3 1.5,3.4, body extent -3.21,-3.25 3.21,3.25, height 1
RGC0064G [mm] "Texas Instruments"
  rrect42% 0.6x0.24 smd: 1(-4.4,3.75) 2(-4.4,3.25) 3(-4.4,2.75) 4(-4.4,2.25) 5(-4.4,1.75) 6(-4.4,1.25) 7(-4.4,0.75) 8(-4.4,0.25) 9(-4.4,-0.25) 10(-4.4,-0.75) 11(-4.4,-1.25) 12(-4.4,-1.75) 13(-4.4,-2.25) 14(-4.4,-2.75) 15(-4.4,-3.25) 16(-4.4,-3.75) 33(4.4,-3.75) 34(4.4,-3.25) 35(4.4,-2.75) 36(4.4,-2.25) 37(4.4,-1.75) 38(4.4,-1.25) 39(4.4,-0.75) 40(4.4,-0.25) 41(4.4,0.25) 42(4.4,0.75) 43(4.4,1.25) 44(4.4,1.75) 45(4.4,2.25) 46(4.4,2.75) 47(4.4,3.25) 48(4.4,3.75)
  rrect42% 0.24x0.6 smd: 17(-3.751,-4.4) 18(-3.251,-4.4) 19(-2.751,-4.4) 20(-2.251,-4.4) 21(-1.75,-4.4) 22(-1.25,-4.4) 23(-0.75,-4.4) 24(-0.25,-4.4) 25(0.25,-4.4) 26(0.75,-4.4) 27(1.25,-4.4) 28(1.75,-4.4) 29(2.251,-4.4) 30(2.751,-4.4) 31(3.251,-4.4) 32(3.751,-4.4) 49(3.751,4.4) 50(3.251,4.4) 51(2.751,4.4) 52(2.251,4.4) 53(1.75,4.4) 54(1.25,4.4) 55(0.75,4.4) 56(0.25,4.4) 57(-0.25,4.4) 58(-0.75,4.4) 59(-1.25,4.4) 60(-1.75,4.4) 61(-2.251,4.4) 62(-2.751,4.4) 63(-3.251,4.4) 64(-3.751,4.4)
  rrect2% 6x6 smd paste-3: 65(0,0)
  silkscreen extent -5.1,-5.1 5.1,5.1, body extent -4.57,-4.57 4.57,4.57, height 1.01
RGE0024H [mm] "QFN, 24-Leads, Body 4x4mm, Pitch 0.5mm, Thermal Pad 2.7x2.7mm, TI Recommended"
  oval 0.6x0.24 smd: 1(-1.9,1.25) 2(-1.9,0.75) 3(-1.9,0.25) 4(-1.9,-0.25) 5(-1.9,-0.75) 6(-1.9,-1.25) 13(1.9,-1.25) 14(1.9,-0.75) 15(1.9,-0.25) 16(1.9,0.25) 17(1.9,0.75) 18(1.9,1.25)
  oval 0.24x0.6 smd: 7(-1.25,-1.9) 8(-0.75,-1.9) 9(-0.25,-1.9) 10(0.25,-1.9) 11(0.75,-1.9) 12(1.25,-1.9) 19(1.25,1.9) 20(0.75,1.9) 21(0.25,1.9) 22(-0.25,1.9) 23(-0.75,1.9) 24(-1.25,1.9)
  rect 2.7x2.7 smd paste-1.35: 25(0,0)
  silkscreen extent -2.22,-2.22 2.22,2.22, body extent -2.07,-2.07 2.07,2.07, height 1.01
RHB0032E [mm] "QFN, 32-Leads, Body 5x5mm, Pitch 0.5mm, Thermal Pad 3.45x3.45mm, TI Recommended"
  oval 0.6x0.24 smd: 1(-2.4,1.75) 2(-2.4,1.25) 3(-2.4,0.75) 4(-2.4,0.25) 5(-2.4,-0.25) 6(-2.4,-0.75) 7(-2.4,-1.25) 8(-2.4,-1.75) 17(2.4,-1.75) 18(2.4,-1.25) 19(2.4,-0.75) 20(2.4,-0.25) 21(2.4,0.25) 22(2.4,0.75) 23(2.4,1.25) 24(2.4,1.75)
  oval 0.24x0.6 smd: 9(-1.75,-2.4) 10(-1.25,-2.4) 11(-0.75,-2.4) 12(-0.25,-2.4) 13(0.25,-2.4) 14(0.75,-2.4) 15(1.25,-2.4) 16(1.75,-2.4) 25(1.75,2.4) 26(1.25,2.4) 27(0.75,2.4) 28(0.25,2.4) 29(-0.25,2.4) 30(-0.75,2.4) 31(-1.25,2.4) 32(-1.75,2.4)
  rect 3.45x3.45 smd paste-1.725: 33(0,0)
  silkscreen extent -2.73,-2.73 2.73,2.73, body extent -2.57,-2.57 2.58,2.58, height 1.01
RoHS_Exempt [mil]
Rosenberger_59S20X-400L5 [mm] "Rosenberger"
  rect 2x2 hole 1.5 paste+0: 1(-4.55,0)
  round 2.4 hole 1.9 paste+0: MH1(-7.09,2.54) MH2(-2.01,2.54) MH3(-2.01,-2.54) MH4(-7.09,-2.54)
  silkscreen extent -8.3,-4.25 8.3,4.25, body extent -8.3,-4.25 8.3,4.25, height 11.61
Rosenberger_D4S20L-40MA5 [mm] "Rosenberger"
  round 1.4 hole 0.9: 1(-1,7.307) 2(-1,5.307) 3(1,5.307) 4(1,7.307)
  round 2.2 hole 1.7: MH(-3.75,10.157) MH(-3.75,2.457) MH(3.75,10.157) MH(3.75,2.457)
  Layer 1 - Top Layer region: 1.756,9.007 1.731,9.203 1.655,9.385 1.535,9.542 1.378,9.662 1.196,9.738 1,9.763 1,9.757 1,7.766 1.176,7.731 1.324,7.631 1.424,7.483 1.459,7.307 1.424,7.131 1.324,6.983 1.176,6.883 1,6.848 1,6.857 1,6.551 1.196,6.576 1.378,6.652 1.535,6.772 1.655,6.929 1.731,7.111 1.756,7.307 1.75,7.307
  Layer 1 - Top Layer region: 0.244,9.007 0.269,9.203 0.345,9.385 0.465,9.542 0.622,9.662 0.804,9.738 1,9.763 1,9.757 1,7.766 0.824,7.731 0.676,7.631 0.576,7.483 0.541,7.307 0.576,7.131 0.676,6.983 0.824,6.883 1,6.848 1,6.857 1,6.551 0.804,6.576 0.622,6.652 0.465,6.772 0.345,6.929 0.269,7.111 0.244,7.307 0.25,7.307
  Layer 1 - Top Layer region: 0.244,3.607 0.269,3.411 0.345,3.229 0.465,3.072 0.622,2.952 0.804,2.876 1,2.851 1,2.857 1,4.848 0.824,4.883 0.676,4.983 0.576,5.131 0.541,5.307 0.576,5.483 0.676,5.631 0.824,5.731 1,5.766 1,5.757 1,6.063 0.804,6.038 0.622,5.962 0.465,5.842 0.345,5.685 0.269,5.503 0.244,5.307 0.25,5.307
  Layer 1 - Top Layer region: 1.756,3.607 1.731,3.411 1.655,3.229 1.535,3.072 1.378,2.952 1.196,2.876 1,2.851 1,2.857 1,4.848 1.176,4.883 1.324,4.983 1.424,5.131 1.459,5.307 1.424,5.483 1.324,5.631 1.176,5.731 1,5.766 1,5.757 1,6.063 1.196,6.038 1.378,5.962 1.535,5.842 1.655,5.685 1.731,5.503 1.756,5.307 1.75,5.307
  Layer 1 - Top Layer region: -0.244,3.607 -0.269,3.411 -0.345,3.229 -0.465,3.072 -0.622,2.952 -0.804,2.876 -1,2.851 -1,2.857 -1,4.848 -0.824,4.883 -0.676,4.983 -0.576,5.131 -0.541,5.307 -0.576,5.483 -0.676,5.631 -0.824,5.731 -1,5.766 -1,5.757 -1,6.063 -0.804,6.038 -0.622,5.962 -0.465,5.842 -0.345,5.685 -0.269,5.503 -0.244,5.307 -0.25,5.307
  Layer 1 - Top Layer region: -1.756,3.607 -1.731,3.411 -1.655,3.229 -1.535,3.072 -1.378,2.952 -1.196,2.876 -1,2.851 -1,2.857 -1,4.848 -1.176,4.883 -1.324,4.983 -1.424,5.131 -1.459,5.307 -1.424,5.483 -1.324,5.631 -1.176,5.731 -1,5.766 -1,5.757 -1,6.063 -1.196,6.038 -1.378,5.962 -1.535,5.842 -1.655,5.685 -1.731,5.503 -1.756,5.307 -1.75,5.307
  Layer 1 - Top Layer region: -0.244,9.007 -0.269,9.203 -0.345,9.385 -0.465,9.542 -0.622,9.662 -0.804,9.738 -1,9.763 -1,9.757 -1,7.766 -0.824,7.731 -0.676,7.631 -0.576,7.483 -0.541,7.307 -0.576,7.131 -0.676,6.983 -0.824,6.883 -1,6.848 -1,6.857 -1,6.551 -0.804,6.576 -0.622,6.652 -0.465,6.772 -0.345,6.929 -0.269,7.111 -0.244,7.307 -0.25,7.307
  Layer 1 - Top Layer region: -1.756,9.007 -1.731,9.203 -1.655,9.385 -1.535,9.542 -1.378,9.662 -1.196,9.738 -1,9.763 -1,9.757 -1,7.766 -1.176,7.731 -1.324,7.631 -1.424,7.483 -1.459,7.307 -1.424,7.131 -1.324,6.983 -1.176,6.883 -1,6.848 -1,6.857 -1,6.551 -1.196,6.576 -1.378,6.652 -1.535,6.772 -1.655,6.929 -1.731,7.111 -1.756,7.307 -1.75,7.307
  Layer 1 - Top Layer region: 5.1,6.307 3.75,6.307 3.75,3.314 3.972,3.285 4.179,3.199 4.356,3.063 4.492,2.886 4.578,2.679 4.607,2.457 4.578,2.235 4.492,2.028 4.356,1.851 4.179,1.715 3.972,1.629 3.75,1.6 3.75,1.607 3.75,1.3 4.044,1.329 4.327,1.414 4.587,1.554 4.816,1.741 5.003,1.97 5.103,2.156 5.102,2.156 5.1,2.156
  Layer 1 - Top Layer region: 3.75,1.3 3.456,1.329 3.173,1.414 2.913,1.554 2.684,1.741 2.497,1.97 2.397,2.156 2.398,2.156 2.4,2.156 2.4,5.899 2.556,5.93 2.688,6.019 2.777,6.151 2.808,6.307 2.8,6.307 3.75,6.307 3.75,3.314 3.528,3.285 3.321,3.199 3.144,3.063 3.008,2.886 2.922,2.679 2.893,2.457 2.922,2.235 3.008,2.028 3.144,1.851 3.321,1.715 3.528,1.629 3.75,1.6 3.75,1.607
  Layer 1 - Top Layer region: -3.75,1.3 -3.456,1.329 -3.173,1.414 -2.913,1.554 -2.684,1.741 -2.497,1.97 -2.397,2.156 -2.398,2.156 -2.4,2.156 -2.4,5.899 -2.556,5.93 -2.688,6.019 -2.777,6.151 -2.808,6.307 -2.8,6.307 -3.75,6.307 -3.75,3.314 -3.528,3.285 -3.321,3.199 -3.144,3.063 -3.008,2.886 -2.922,2.679 -2.893,2.457 -2.922,2.235 -3.008,2.028 -3.144,1.851 -3.321,1.715 -3.528,1.629 -3.75,1.6 -3.75,1.607
  Layer 1 - Top Layer region: -5.1,6.307 -3.75,6.307 -3.75,3.314 -3.972,3.285 -4.179,3.199 -4.356,3.063 -4.492,2.886 -4.578,2.679 -4.607,2.457 -4.578,2.235 -4.492,2.028 -4.356,1.851 -4.179,1.715 -3.972,1.629 -3.75,1.6 -3.75,1.607 -3.75,1.3 -4.044,1.329 -4.327,1.414 -4.587,1.554 -4.816,1.741 -5.003,1.97 -5.103,2.156 -5.102,2.156 -5.1,2.156
  Layer 1 - Top Layer region: -3.75,11.314 -3.456,11.285 -3.173,11.2 -2.913,11.06 -2.684,10.873 -2.497,10.644 -2.397,10.458 -2.398,10.458 -2.4,10.458 -2.4,6.715 -2.556,6.684 -2.688,6.595 -2.777,6.463 -2.808,6.307 -2.8,6.307 -3.75,6.307 -3.75,9.3 -3.528,9.329 -3.321,9.415 -3.144,9.551 -3.008,9.728 -2.922,9.935 -2.893,10.157 -2.922,10.379 -3.008,10.586 -3.144,10.763 -3.321,10.899 -3.528,10.985 -3.75,11.014 -3.75,11.007
  Layer 1 - Top Layer region: -5.1,6.307 -3.75,6.307 -3.75,9.3 -3.972,9.329 -4.179,9.415 -4.356,9.551 -4.492,9.728 -4.578,9.935 -4.607,10.157 -4.578,10.379 -4.492,10.586 -4.356,10.763 -4.179,10.899 -3.972,10.985 -3.75,11.014 -3.75,11.007 -3.75,11.314 -4.044,11.285 -4.327,11.2 -4.587,11.06 -4.816,10.873 -5.003,10.644 -5.103,10.458 -5.102,10.458 -5.1,10.458
  Layer 1 - Top Layer region: 3.75,11.314 3.456,11.285 3.173,11.2 2.913,11.06 2.684,10.873 2.497,10.644 2.397,10.458 2.398,10.458 2.4,10.458 2.4,6.715 2.556,6.684 2.688,6.595 2.777,6.463 2.808,6.307 2.8,6.307 3.75,6.307 3.75,9.3 3.528,9.329 3.321,9.415 3.144,9.551 3.008,9.728 2.922,9.935 2.893,10.157 2.922,10.379 3.008,10.586 3.144,10.763 3.321,10.899 3.528,10.985 3.75,11.014 3.75,11.007
  Layer 1 - Top Layer region: 5.1,6.307 3.75,6.307 3.75,9.3 3.972,9.329 4.179,9.415 4.356,9.551 4.492,9.728 4.578,9.935 4.607,10.157 4.578,10.379 4.492,10.586 4.356,10.763 4.179,10.899 3.972,10.985 3.75,11.014 3.75,11.007 3.75,11.314 4.044,11.285 4.327,11.2 4.587,11.06 4.816,10.873 5.003,10.644 5.103,10.458 5.102,10.458 5.1,10.458
  silkscreen extent -4.5,0.2 4.5,11.51, body extent -6,-15.79 6,11.51, height 10.95
RSE0010A [mm] "QFN, 10-Leads, Body 1.5x2mm, Pitch 0.5mm, TI Recommended"
  rect 0.55x0.2 smd: 1(-0.675,0.75) 2(-0.675,0.25) 3(-0.675,-0.25) 4(-0.675,-0.75) 6(0.675,-0.75) 7(0.675,-0.25) 8(0.675,0.25) 9(0.675,0.75)
  rect 0.3x0.6 smd: 5(0,-0.9) 10(0,0.9)
  silkscreen extent -1.07,-1.18 0.78,1.18, body extent -0.77,-1.02 0.78,1.03, height 0.61
RVC0020A [mm] "TI"
  rrect50% 0.6x0.2 smd: 1(-1.4,1.25) 2(-1.4,0.75) 3(-1.4,0.25) 4(-1.4,-0.25) 5(-1.4,-0.75) 6(-1.4,-1.25) 11(1.4,-1.25) 12(1.4,-0.75) 13(1.4,-0.25) 14(1.4,0.25) 15(1.4,0.75) 16(1.4,1.25)
  rrect50% 0.2x0.6 smd: 7(-0.75,-1.9) 8(-0.25,-1.9) 9(0.25,-1.9) 10(0.75,-1.9) 17(0.75,1.9) 18(0.25,1.9) 19(-0.25,1.9) 20(-0.75,1.9)
  rrect9% 1.47x1.15 on Top Paste: 21(0,0.675) 21(0,-0.675)
  rrect6% 1.6x2.6 smd paste-1: 21(0,0)
  silkscreen extent -1.67,-2.15 1.65,2.18, body extent -1.55,-2.05 1.55,2.05, height 0.8
RWA0014A [mm] "QFN, 14-Leads, Body 3.5x3.5mm, Pitch 0.5mm, Thermal Pad 2.05x2.05mm, TI Recommended"
  rrect42% 0.24x0.6 smd: 1(-0.75,1.65) 7(-0.75,-1.65) 8(0.75,-1.65) 14(0.75,1.65)
  rrect42% 0.6x0.24 smd: 2(-1.65,1) 3(-1.65,0.5) 4(-1.65,0) 5(-1.65,-0.5) 6(-1.65,-1) 9(1.65,-1) 10(1.65,-0.5) 11(1.65,0) 12(1.65,0.5) 13(1.65,1)
  rrect5% 2.05x2.05 smd paste-1.025: 15(0,0)
  silkscreen extent -1.98,-1.97 1.98,1.97, body extent -1.83,-1.83 1.82,1.82, height 0.81
SAMTEC_QTH-020-01-L-D-DP-A [mm] "Receptacle, Differential, 0.5mm, 10x2, SMT"
  rect 0.3x1.45 smd: 1(7.245,-3.085) 2(7.245,3.085) 3(6.745,-3.085) 4(6.745,3.085) 5(5.745,-3.085) 6(5.745,3.085) 7(5.245,-3.085) 8(5.245,3.085) 9(4.245,-3.085) 10(4.245,3.085) 11(3.745,-3.085) 12(3.745,3.085) 13(2.745,-3.085) 14(2.745,3.085) 15(2.245,-3.085) 16(2.245,3.085) 17(1.245,-3.085) 18(1.245,3.085) 19(0.745,-3.085) 20(0.745,3.085) 21(-0.255,-3.085) 22(-0.255,3.085) 23(-0.755,-3.085) 24(-0.755,3.085) 25(-1.755,-3.085) 26(-1.755,3.085) 27(-2.255,-3.085) 28(-2.255,3.085) 29(-3.255,-3.085) 30(-3.255,3.085) 31(-3.755,-3.085) 32(-3.755,3.085) 33(-4.755,-3.085) 34(-4.755,3.085) 35(-5.255,-3.085) 36(-5.255,3.085) 37(-6.255,-3.085) 38(-6.255,3.085) 39(-6.755,-3.085) 40(-6.755,3.085)
  round 1.02 hole 1.02 unplated mask+0: MH1(9.235,-2.035) MH2(-9.235,-2.035)
  rect 2.54x0.64 smd: MP1(8.435,-0.005) MP4(-8.455,-0.005)
  rect 4.7x0.64 smd: MP2(3.165,-0.005) MP3(-3.185,-0.005)
  silkscreen extent -10,-3.31 10,2.98, body extent -10.01,-3.56 10,3.55, height 4.32
SDR0805 [mm] "Bourns recommended land pattern"
  oval 2.7x8 smd: 1(-2.65,0) 2(2.65,0)
  rect 1.5x1.5 smd: 1(-2.05,3.25) 1(-2.05,-3.25) 2(2.05,3.25) 2(2.05,-3.25)
  silkscreen extent -4.3,-4.35 4.3,4.35, body extent -3.88,-3.9 3.89,3.89, height 5.3
SM_RADIAL_C [mm] "5 x 5.8mm:  Panasonic C"
  rect 2.8x1.6 smd: 1(-2.15,0) 2(2.15,0)
  silkscreen extent -2.75,-2.75 2.75,2.75, body extent -2.75,-2.75 2.75,2.75, height 6.1
SM_RADIAL_E [mm] "8 x 6.2mm:  Panasonic E"
  rect 4x1.6 smd: 1(-3.1,0) 2(3.1,0)
  silkscreen extent -4.25,-4.25 4.25,4.25, body extent -4.25,-4.25 4.25,4.25, height 6.5
SMA [mm] "Molded Diode, 2-Leads, Body 4.3x2.6mm, IPC Medium Density, based on OnSemi component dimensions and land pattern"
  rect 2x2 smd: 1(-2,0) 2(2,0)
  silkscreen extent -3.66,-1.57 2.79,1.57, body extent -2.6,-1.3 2.6,1.3, height 2.42
SMB [mil] "Molded Diode, 2-Leads, Body 5.4x3.6mm, IPC Medium Density, based on OnSemi component dimensions"
  rect 85x107.99 smd: 1(-87.01,0) 2(87.01,0)
  silkscreen extent -155,-82 125,82, body extent -106,-71 106,71, height 91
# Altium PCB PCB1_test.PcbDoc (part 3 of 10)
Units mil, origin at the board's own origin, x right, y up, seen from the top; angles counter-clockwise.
Board outline 6690 x 6690 mil, 6 copper layers (Layer 1 - Top Layer, Layer 2 - GND, Layer 3 - PWR, Layer 4 - Signal, Layer 5 - GND, Layer 6 - Bottom Layer), stack 80.244 mil thick; 821 components, 458 nets, 3746 pads, 1527 vias.

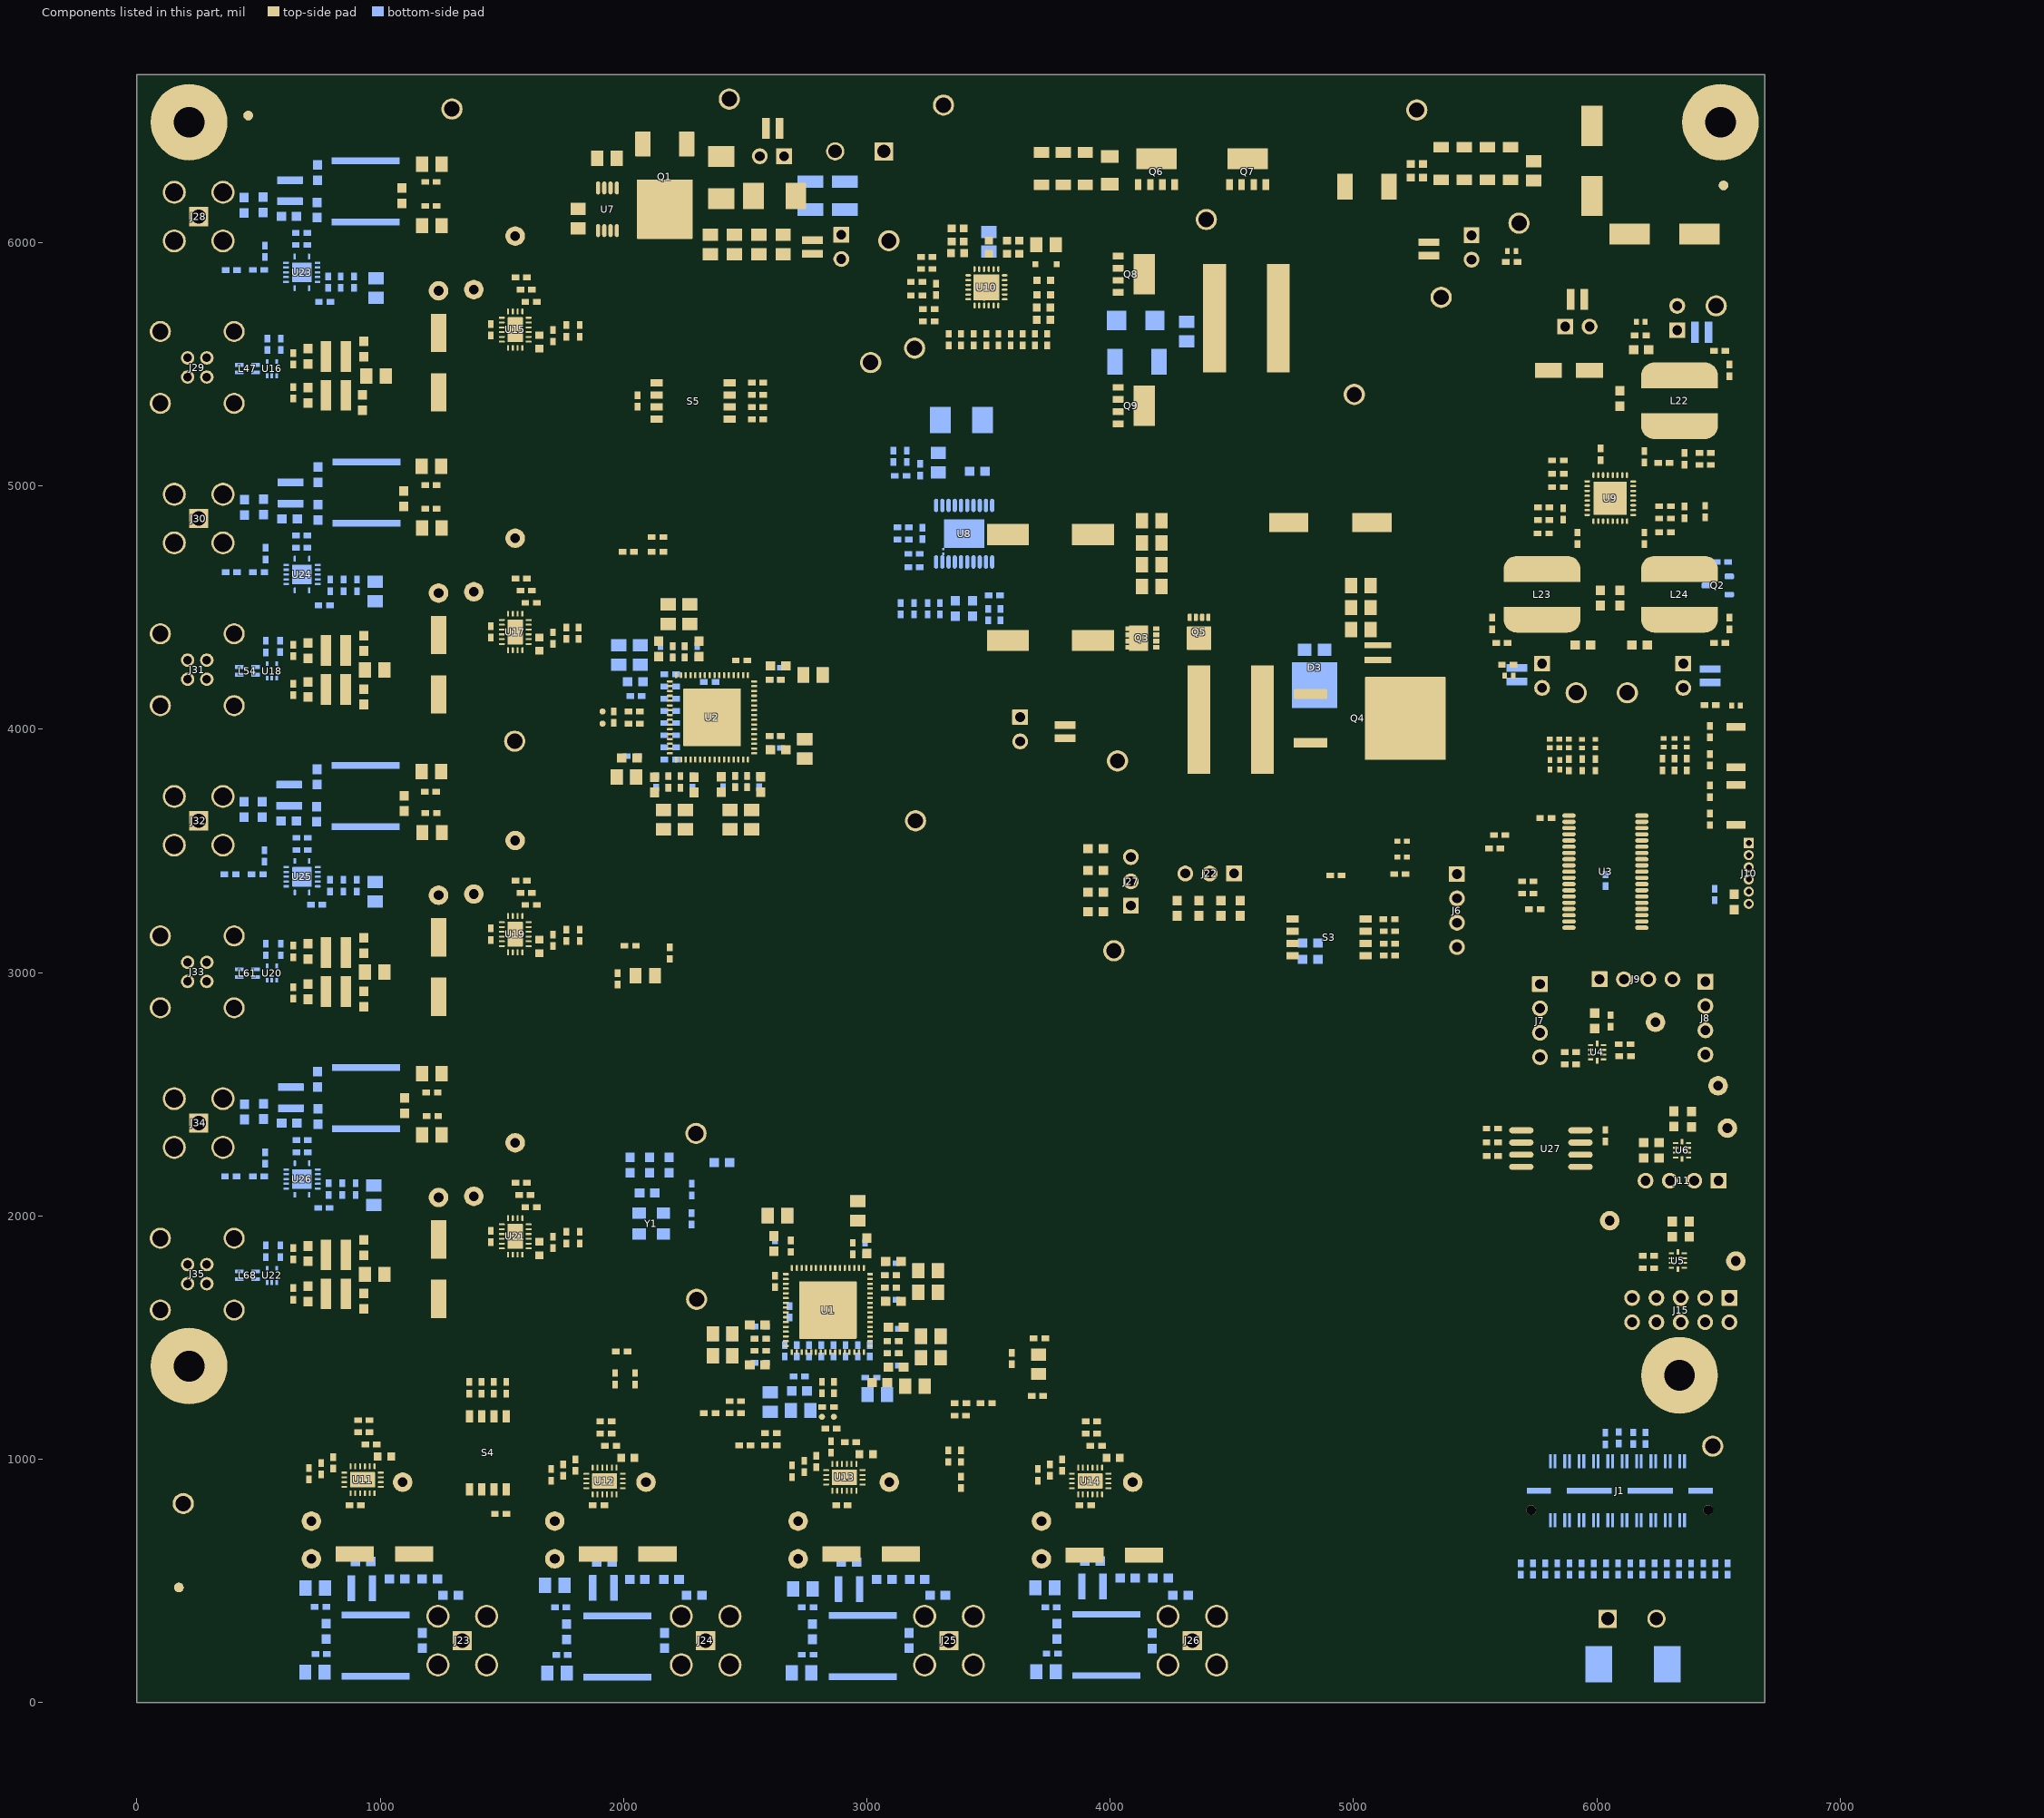
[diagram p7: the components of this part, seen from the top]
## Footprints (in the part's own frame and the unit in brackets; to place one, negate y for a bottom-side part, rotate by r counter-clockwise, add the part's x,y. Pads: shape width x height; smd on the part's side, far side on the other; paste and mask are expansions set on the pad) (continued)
SMC [mil] "Molded Diode, 2-Leads, Body 6.9x5.8mm, IPC Medium Density, based on OnSemi component dimensions and land patterns"
  rect 110x150 smd: 1(-140.49,0) 2(140.49,0)
  silkscreen extent -221,-123 189,124, body extent -156,-116 156,116, height 91
SML-P1_GREEN [mm] "ROHM"
  rect 0.5x0.6 smd: 1(-0.45,0) 2(0.45,0)
  silkscreen extent -0.95,-0.3 -0.95,0.3, body extent -0.53,-0.33 0.53,0.33, height 0.25
SML-P1_YELLOW-GREEN [mm] "Rohm Semiconductor"
  rect 0.5x0.6 smd: 1(-0.45,0) 2(0.45,0)
  silkscreen extent -0.62,-0.61 1.33,0.61, body extent -0.55,-0.35 0.55,0.35, height 0.25
so8-25x75-295 [mil] "SO8-25X75-295"
  oval 25x100 smd: 1(-75,-121.5) 2(-25,-121.5) 3(25,-121.5) 4(75,-121.5) 5(75,121.5) 6(25,121.5) 7(-25,121.5) 8(-75,121.5)
  silkscreen extent -125,-60 125,60, body extent -135,-190 135,200, height 150
SOD-323F [mm] "NXP recommended land pattern"
  rect 0.6x0.6 smd paste-0.05: 1(-1.1,0) 2(1.1,0)
  silkscreen extent -2.06,-0.86 1.53,0.86, body extent -1.35,-0.67 1.35,0.68, height 0.79
SOT-23 [mm] "SOT23, 3-Leads, Body 2.9x1.3mm, Pitch 0.95mm, Lead Span 2.5mm, IPC Medium Density"
  rrect50% 1x0.6 smd: 1(-1.2,0.95) 2(-1.2,-0.95) 3(1.2,0)
  silkscreen extent -1.62,-1.5 0.7,1.5, body extent -1.16,-1.45 1.21,1.45, height 1
SULLINS_LPPB061NGCN-RC [mm] "SULLINS"
  rect 1.05x1.05 hole 0.61: 1(3.175,2.54)
  round 1.05 hole 0.61: 2(1.905,2.54) 3(0.635,2.54) 4(-0.635,2.54) 5(-1.905,2.54) 6(-3.175,2.54)
  silkscreen extent -4,-2.37 4.03,2, body extent -4,-2.36 4,2.59, height 2.16
SW_218-4LPST [mil] "CTS Components"
  rect 50x30 smd: 1(-150,75) 2(-150,25) 3(-150,-25) 4(-150,-75) 5(150,-75) 6(150,-25) 7(150,25) 8(150,75)
  silkscreen extent -114,-123 114,123, body extent -166,-123 166,123, height 104
SW_SKRKAEE010 [mm] "Alps recommended land pattern"
  rect 0.8x2 smd: 1(-2.1,0) 2(2.1,0)
  silkscreen extent -1.9,-1.44 1.92,1.44, body extent -2.4,-1.45 2.4,1.45, height 1.96
TI_Stacked_Overlay_Small [mil]
  silkscreen extent -418,-98 418,98
TO-277A [mm] "Vishay"
  rect 1.4x1.27 smd: 1(-1.04,1.83) 2(1.04,1.83)
  rect 4.72x4.8 smd: 3(0,-1.883)
  silkscreen extent -2.7,1.45 -2.4,1.75, body extent -2.35,-4.2 2.4,2.45, height 1.2
TP_25MIL-SMT [mil]
  round 25 smd mask-2.5: 1(0,0)
TRANS_NexFET_Q3A [mm] "TI"
  rect 0.68x0.5 smd paste-1 mask+0.076: 1(-1.625,0.975) 2(-1.625,0.325) 3(-1.625,-0.325) 4(-1.625,-0.975)
  rect 0.41x0.5 smd paste-1 mask+0.076: 5(1.385,-0.975) 6(1.385,-0.325) 7(1.385,0.325) 8(1.385,0.975)
  rect 1.96x2.65 smd paste-3 mask+0.076: 9(0.205,0)
  Layer 1 - Top Layer region: 1,-1.325 1.24,-1.325 1.24,-1.1 1,-1.1
  Layer 1 - Top Layer region: 1,1.1 1.24,1.1 1.24,1.325 1,1.325
  silkscreen extent -1.82,-1.7 1.42,1.7, body extent -1.85,-1.65 1.45,1.66, height 0.91
TSW-102-07-G-S [mm] "Samtec 100mil, 1x2, 230 mil above insulator"
  rrect6% 1.65x1.65 hole 1.016: 1(-1.27,0)
  round 1.65 hole 1.016: 2(1.27,0)
  silkscreen extent -2.54,-1.27 2.54,1.65, body extent -2.54,-1.27 2.54,1.27, height 8.38
TSW-103-07-G-S [mm] "Samtec 100mil, 1x3, 230 mil above insulator"
  rect 1.65x1.65 hole 1.016: 1(-2.54,0)
  round 1.65 hole 1.016: 2(0,0) 3(2.54,0)
  silkscreen extent -3.81,-1.27 3.81,1.65, body extent -3.81,-1.27 3.81,1.27, height 8.38
TSW-104-07-G-S [mm] "Samtec 100mil, 1x4, 230 mil above insulator"
  rrect6% 1.65x1.65 hole 1.016: 1(-3.81,0)
  round 1.65 hole 1.016: 2(-1.27,0) 3(1.27,0) 4(3.81,0)
  silkscreen extent -5.16,-1.27 5.08,1.65, body extent -5.08,-1.27 5.08,1.27, height 8.38
TSW-105-07-G-D [mm] "Samtec 100mil, 2x5, 230 mil above insulator"
  rrect6% 1.65x1.65 hole 1.016: 1(-5.08,-1.27)
  round 1.65 hole 1.016: 2(-5.08,1.27) 3(-2.54,-1.27) 4(-2.54,1.27) 5(0,-1.27) 6(0,1.27) 7(2.54,-1.27) 8(2.54,1.27) 9(5.08,-1.27) 10(5.08,1.27)
  silkscreen extent -7.38,-2.54 6.35,2.54, body extent -6.35,-2.54 6.35,2.54, height 8.38
TXC_7C [mm] "TXC"
  rect 1.2x1.4 smd: 1(-1.1,1.27) 2(-1.1,-1.27) 3(1.1,-1.27) 4(1.1,1.27)
  silkscreen extent -2.32,-2.62 1.73,2.62, body extent -1.7,-2.6 1.7,2.6, height 1.4
XAL1010 [mm] "COILCRAFT"
  rect 2.38x11.31 smd: 1(-3.325,0) 2(3.325,0)
  silkscreen extent -5.3,-6 5.3,6, body extent -5.25,-5.9 5.25,5.9, height 10

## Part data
C1 C2 C7 C8 C13 C14 C21 C22 C27 C28 C36 C37 C42 C43 C47 C48 C52 C53 C57 C58 C62 C63 C68 C69 C74 C75 C80 C81 C87 C88 C96 C97 C103 C104 C108 C109 C113 C114 C118 C119 C243 C258 C273 C288 C296 C300 C304 C308: "CAP, CERM, 10 µF, 25 V, +/- 10%, X5R, 0805", Cap_Case=0805, Manufacturer=Samsung, Supplier Part Number 1=1276-2890-1-ND, TempCo=X5R, Tolerance_%=10, Value1=Unknown, Value2=25V, ValueDisplayed=10µF
C3 C9 C15 C23 C29 C38 C44 C49 C54 C59 C64 C70 C76 C82 C89 C98 C105 C110 C115 C120 C167 C297 C301 C305 C309 C_VIN1: "CAP, CERM, 1 µF, 35 V, +/- 10%, JB, 0402", Cap_Case=0402, Manufacturer=TDK, Supplier Part Number 1=445-11014-1-ND, TempCo=JB, Tolerance_%=10, Value1=Unknown, Value2=35V, ValueDisplayed=1µF
C4 C10 C16 C19 C24 C26 C30 C39 C45 C50 C55 C60 C65 C71 C77 C83 C85 C90 C95 C99 C106 C111 C116 C121 C126 C150 C176 C196 C198 C200 C202 C204 C205 C216 C218 C220 C222 C224 C225 C236 C238 C241 C244 C245 C251 C253 C256 C259 C260 C266 C268 C271 C274 C275 C281 C283 C286 C289 C290 C298 C302 C306 C310 C312 C313: "CAP, CERM, 0.1 µF, 50 V, +/- 10%, X7R, AEC-Q200 Grade 1, 0402", Cap_Case=0402, Manufacturer=MuRata, Supplier Part Number 1=490-10672-1-ND, TempCo=X7R, Tolerance_%=10, Value1=Unknown, Value2=50V, ValueDisplayed=0.1µF
C5 C6 C11 C12 C17 C18 C25 C31 C32 C33 C34 C40 C46 C51 C56 C61 C66 C67 C72 C73 C78 C79 C84 C91 C92 C93 C94 C100 C107 C112 C117 C122 C193 C299 C303 C307 C311: "CAP, CERM, 0.01uF, 50V, +/-10%, C0G/NP0, 0402", Cap_Case=0402, Manufacturer=MuRata, Supplier Part Number 1=490-4762-1-ND, TempCo=C0G/NP0, Tolerance_%=10, Value1=Unknown, Value2=50V, ValueDisplayed=0.01µF
C20 C86 C144 C145 C146 C147: "CAP, CERM, 10 µF, 25 V, +/- 10%, X5R, 0805", Cap_Case=0805, Manufacturer="Samsung Electro-Mechanics", TempCo=X5R, Tolerance_%=10, Value1=Unknown, Value2=25V, ValueDisplayed=10µF
C35 C41 C101 C102: "CAP, CERM, 0.033 µF, 50 V, +/- 10%, X7R, AEC-Q200 Grade 1, 0402", Cap_Case=0402, Manufacturer=TDK, Supplier Part Number 1=445-6896-1-ND, TempCo=X7R, Tolerance_%=10, Value1=Unknown, Value2=50V, ValueDisplayed=0.033µF
C123 C128 C129: "CAP, CERM, 0.1uF, 16V, +/-5%, X7R, 0603", Cap_Case=0603, Manufacturer=AVX, Supplier Part Number 1=478-3726-1-ND, TempCo=X7R, Tolerance_%=5, Value1="0.039 ohm", Value2=16V, ValueDisplayed=0.1µF
C124 C127 C162: "CAP, CERM, 2200 pF, 10 V, +/- 10%, X5R, 0402", Cap_Case=0402, Manufacturer=MuRata, Supplier Part Number 1=GRM155R61A222KA01D-ND, TempCo=X5R, Tolerance_%=10, Value1=Unknown, Value2=10V, ValueDisplayed=2200pF
C125: "CAP, CERM, 4.7 µF, 10 V, +/- 20%, X5R, 0402", Cap_Case=0402, Manufacturer=MuRata, TempCo=X5R, Tolerance_%=20, Value1=Unknown, Value2=10V, ValueDisplayed=4.7µF
C130 C131: "CAP, CERM, 4.7 µF, 100 V, +/- 10%, X7S, 1210", Cap_Case=1210_220, Manufacturer=TDK, Supplier Part Number 1=445-6042-1-ND, TempCo=X7S, Tolerance_%=10, Value1="0.004236 ohm", Value2=100V, ValueDisplayed=4.7µF
C132: "CAP, CERM, 100 pF, 50 V, +/- 5%, C0G/NP0, 0805", Cap_Case=0805, Manufacturer=AVX, Supplier Part Number 1=478-1316-1-ND, TempCo=C0G/NP0, Tolerance_%=5, Value1="0.356 ohm", Value2=50V, ValueDisplayed=100pF
C133: "CAP, CERM, 1 µF, 50 V, +/- 10%, X7R, 0805", Cap_Case=0805, Manufacturer=MuRata, Supplier Part Number 1=490-4736-1-ND, TempCo=X7R, Tolerance_%=10, Value1=Unknown, Value2=50V, ValueDisplayed=1µF
C134 C135 C136 C152: "CAP, CERM, 4.7 µF, 50 V, +/- 10%, X7S, 0805", Cap_Case=0805, Manufacturer=MuRata, Supplier Part Number 1=GRM21BC71H475KE11K-ND, TempCo=X7S, Tolerance_%=10, Value1=Unknown, Value2=50V, ValueDisplayed=4.7µF
C137: "CAP, CERM, 2.2 µF, 50 V, +/- 10%, X5R, 0805", Cap_Case=0805, Manufacturer=TDK, Supplier Part Number 1=445-5976-1-ND, TempCo=X5R, Tolerance_%=10, Value1=Unknown, Value2=50V, ValueDisplayed=2.2µF
C138: "CAP, AL, 560 µF, 25 V, +/- 20%, 0.08 ohm, AEC-Q200 Grade 2, SMD", Cap_Case=10x10.2mm, Manufacturer=Panasonic, Supplier Part Number 1=PCE4441CT-ND, Tolerance_%=20, Value1="0.08 ohm", Value2=25V, ValueDisplayed=560µF
C139 C140 C141: "CAP, CERM, 3.3 µF, 25 V, +/- 10%, X6S, 0805", Cap_Case=0805, Manufacturer=MuRata, Supplier Part Number 1=GRM21BC81E335KA73L-ND, TempCo=X6S, Tolerance_%=10, Value1=Unknown, Value2=25V, ValueDisplayed=3.3µF
C142 C143: "CAP, Aluminum Polymer, 470 µF, 16 V, +/- 20%, 0.01 ohm, JC0 SMD", Manufacturer=Panasonic, Tolerance_%=20, Value1="0.01 ohm", Value2=16V, ValueDisplayed=470µF
C148: "CAP, CERM, 4.7 µF, 25 V, +/- 10%, X5R, 0603", Cap_Case=0603, Manufacturer=MuRata, Supplier Part Number 1=490-7203-1-ND, TempCo=X5R, Tolerance_%=10, Value1=Unknown, Value2=25V, ValueDisplayed=4.7µF
C149: "CAP, CERM, 100 pF, 50 V, +/- 5%, C0G/NP0, 0402", Cap_Case=0402, Manufacturer=MuRata, Supplier Part Number 1=81-GRM1555C1H101JA1D, TempCo=C0G/NP0, Tolerance_%=5, Value1=Unknown, Value2=50V, ValueDisplayed=100pF
C151: "CAP, CERM, 0.15 µF, 10 V, +/- 10%, X5R, 0402", Cap_Case=0402, Manufacturer=MuRata, Supplier Part Number 1=GRM155R61A154KE19-ND, TempCo=X5R, Tolerance_%=10, Value1=Unknown, Value2=10V, ValueDisplayed=0.15µF
C153 C157: "CAP, CERM, 1500 pF, 50 V, +/- 10%, X7R, 0402", Cap_Case=0402, Manufacturer=MuRata, Supplier Part Number 1=490-3245-1-ND, TempCo=X7R, Tolerance_%=10, Value1=Unknown, Value2=50V, ValueDisplayed=1500pF
C154: "CAP, CERM, 0.015 µF, 50 V, +/- 10%, X7R, AEC-Q200 Grade 1, 0402", Cap_Case=0402, Manufacturer=TDK, Supplier Part Number 1=445-6894-1-ND, TempCo=X7R, Tolerance_%=10, Value1="0.2162 ohm", Value2=50V, ValueDisplayed=0.015µF
C155 C160 C164: "CAP, CERM, 0.047 µF, 6.3 V, +/- 10%, X5R, 0402", Cap_Case=0402, Manufacturer=MuRata, Supplier Part Number 1=GRM155R60J473KA01D-ND, TempCo=X5R, Tolerance_%=10, Value1=Unknown, Value2=6.3V, ValueDisplayed=0.047µF
C156 C161 C165: "CAP, CERM, 22 µF, 10 V, +/- 20%, X5R, 0603", Cap_Case=0603, Manufacturer=MuRata, Supplier Part Number 1=490-10476-1-ND, TempCo=X5R, Tolerance_%=20, Value1=Unknown, Value2=10V, ValueDisplayed=22µF
C158: "CAP, AL, 47 µF, 6.3 V, +/- 20%, 1.8 ohm, SMD", Cap_Case=C, Manufacturer=Panasonic, Supplier Part Number 1=PCE3987CT-ND, Tolerance_%=20, Value1="1.8 ohm", Value2=6.3V, ValueDisplayed=47µF
C159: "CAP, CERM, 18 pF, 50 V, +/- 5%, C0G/NP0, 0402", Cap_Case=0402, Manufacturer=MuRata, Supplier Part Number 1=81-GRM1555C1H180JA1D, TempCo=C0G/NP0, Tolerance_%=5, Value1=Unknown, Value2=50V, ValueDisplayed=18pF
C163: "CAP, CERM, 51 pF, 50 V, +/- 5%, C0G/NP0, 0402", Cap_Case=0402, Manufacturer=MuRata, Supplier Part Number 1=81-GRM1555C1H510JA1D, TempCo=C0G/NP0, Tolerance_%=5, Value1=Unknown, Value2=50V
C166: "CAP, CERM, 2700 pF, 50 V, +/- 10%, X7R, 0402", Cap_Case=0402, Manufacturer=MuRata, Supplier Part Number 1=490-1306-1-ND, TempCo=X7R, Tolerance_%=10, Value1=Unknown, Value2=50V, ValueDisplayed=2700pF
C168 C169 C170: "Cap, Cer-X7R, 10000pF, 16V, 10%, 0402", Cap_Case=0402, Manufacturer=MuRata, Supplier Part Number 1=490-1313-1-ND, TempCo=X7R, Tolerance_%=10, Value1=Unknown, Value2=16V, ValueDisplayed=0.01µF
C171: "CAP, CERM, 91 pF, 50 V, +/- 5%, C0G/NP0, 0402", Cap_Case=0402, Manufacturer=MuRata, Supplier Part Number 1=81-GRM1555C1H910JA1D, TempCo=C0G/NP0, Tolerance_%=5, Value1=Unknown, Value2=50V, ValueDisplayed=91pF
C172 C173 C174: "CAP, CERM, 10 µF, 50 V, +/- 10%, X5R, 1206_190", Cap_Case=1206, Manufacturer=TDK, Supplier Part Number 1=445-7886-1-ND, TempCo=X5R, Tolerance_%=10, Value1=Unknown, Value2=50V, ValueDisplayed=10µF
C175: library part CL31B225KCHSNNE, "CAP CER 2.2UF 100V 10% X7R 1206", Alternate Manufacturer=-, Manufacturer="Samsung Electro-Mechanics America, Inc", Operating Temperature="-55°C ~ 125°C", Supplier Part Number=1276-3138-1-ND, TempCo=X7R, Tolerance_%=±10%
C177: "CAP, CERM, 47 pF, 25 V, +/- 5%, C0G/NP0, 0402", Cap_Case=0402, Manufacturer=MuRata, Supplier Part Number 1=81-GRM1555C1E470JA1D, TempCo=C0G/NP0, Tolerance_%=5, Value1=Unknown, Value2=25V, ValueDisplayed=47pF
C178: "CAP, CERM, 0.33 µF, 100 V, +/- 10%, X7R, 0805", Cap_Case=0805, Manufacturer=MuRata, Supplier Part Number 1=GRM21AR72A334KAC5-ND, TempCo=X7R, Tolerance_%=10, Value1=Unknown, Value2=100V, ValueDisplayed=0.33µF
C179: "CAP, CERM, 0.47uF, 100V, +/-10%, X7R, 0805", Cap_Case=0805, Manufacturer=MuRata, Supplier Part Number 1=490-3326-1-ND, TempCo=X7R, Tolerance_%=10, Value1=Unknown, Value2=100V, ValueDisplayed=0.47µF
C180 C181: "CAP, CERM, 2.2 µF, 10 V, +/- 20%, X5R, 0603", Cap_Case=0603, Manufacturer=Kemet, Supplier Part Number 1=399-4912-1-ND, TempCo=X5R, Tolerance_%=20, Value1=Unknown, Value2=10V, ValueDisplayed=2.2µF
C182: "CAP, CERM, 470 pF, 100 V, +/- 5%, C0G/NP0, 0805", Cap_Case=0805, Manufacturer=AVX, Supplier Part Number 1=478-1288-1-ND, TempCo=C0G/NP0, Tolerance_%=5, Value1="0.159 ohm", Value2=100V, ValueDisplayed=470pF
C183 C187 C188 C189: "CAP, CERM, 47 µF, 10 V, +/- 10%, X5R, 1206", Cap_Case=1206, Manufacturer=MuRata, Supplier Part Number 1=81-GRM31CR61A476KE5L, TempCo=X5R, Tolerance_%=10, Value1=Unknown, Value2=10V, ValueDisplayed=47µF
C184 C185: "CAP, AL, 220 µF, 6.3 V, +/- 20%, 0.025 ohm, SMD", Cap_Case=H70, Manufacturer=Chemi-Con, Supplier Part Number 1=565-3114-1-ND, Tolerance_%=20, Value1="0.025 ohm", Value2=6.3V, ValueDisplayed=220µF
C186 C190 C210 C211 C230 C231 C240 C255 C270 C285: "CAP, CERM, 0.1uF, 100V, +/-10%, X7R, 0603", Cap_Case=0603, Manufacturer=MuRata, Supplier Part Number 1=490-3285-1-ND, TempCo=X7R, Tolerance_%=10, Value1=Unknown, Value2=100V, ValueDisplayed=0.1µF
C191: "CAP, CERM, 33 pF, 100 V, +/- 5%, C0G/NP0, 0603", Cap_Case=0603, Manufacturer=AVX, Supplier Part Number 1=478-1143-1-ND, TempCo=C0G/NP0, Tolerance_%=5, Value1="0.209 ohm", Value2=100V, ValueDisplayed=33pF
C192: "CAP, CERM, 0.22 µF, 10 V, +/- 10%, X5R, 0402", Cap_Case=0402, Manufacturer=MuRata, Supplier Part Number 1=490-3910-1-ND, TempCo=X5R, Tolerance_%=10, Value1=Unknown, Value2=10V, ValueDisplayed=0.22µF
C194: "CAP, CERM, 470 pF, 25 V, +/- 5%, C0G/NP0, 0402", Cap_Case=0402, Manufacturer=MuRata, Supplier Part Number 1=GRM1555C1E471JA01D-ND, TempCo=C0G/NP0, Tolerance_%=5, Value1=Unknown, Value2=25V, ValueDisplayed=470pF
C195: "CAP, CERM, 0.022 µF, 16 V, +/- 10%, X7R, 0402", Cap_Case=0402, Manufacturer=MuRata, Supplier Part Number 1=490-3256-1-ND, TempCo=X7R, Tolerance_%=10, Value1=Unknown, Value2=16V, ValueDisplayed=0.022µF
C197 C199 C201 C203 C217 C219 C221 C223 C237 C239 C252 C254 C267 C269 C282 C284: "CAP, CERM, 10 µF, 25 V, +/- 10%, X5R, 0805", Cap_Case=0805, Manufacturer="Taiyo Yuden", Supplier Part Number 1=587-2985-1-ND, TempCo=X5R, Tolerance_%=10, Value1=Unknown, Value2=25V, ValueDisplayed=10µF
C206 C207 C226 C227 C249 C264 C279 C294: "CAP, CERM, 0.047 µF, 50 V, +/- 10%, X7R, AEC-Q200 Grade 1, 0402", Cap_Case=0402, Manufacturer=TDK, Supplier Part Number 1=445-6897-1-ND, TempCo=X7R, Tolerance_%=10, Value1="0.06407 ohm", Value2=50V, ValueDisplayed=0.047µF
C212 C213 C232 C233 C242 C257 C272 C287: "CAP, AL, 100 µF, 16 V, +/- 20%, 0.4 ohm, SMD", Cap_Case=E, Manufacturer=Panasonic, Supplier Part Number 1=PCE3996CT-ND, Tolerance_%=20, Value1="0.4 ohm", Value2=16V, ValueDisplayed=100µF
C214 C215 C234 C235 C246 C261 C276 C291: "CAP, CERM, 1000 pF, 50 V, +/- 10%, X7R, AEC-Q200 Grade 1, 0402", Cap_Case=0402, Manufacturer=MuRata, Supplier Part Number 1=490-4761-1-ND, TempCo=X7R, Tolerance_%=10, Value1=Unknown, Value2=50V, ValueDisplayed=1000pF
C247 C248 C262 C263 C277 C278 C292 C293 Cbst1: "CAP, CERM, 0.1 µF, 100 V, +/- 10%, X7R, 0603", Cap_Case=0603, Manufacturer=MuRata, Supplier Part Number 1=490-3285-1-ND, TempCo=X7R, Tolerance_%=10, Value1=Unknown, Value2=100V, ValueDisplayed=0.1µF
C_PVIN1 C_PVIN2 C_PVIN3: "CAP, CERM, 10 µF, 10 V, +/- 20%, X6S, AEC-Q200 Grade 2, 0603", Cap_Case=0603, Manufacturer=MuRata, Supplier Part Number 1=490-12283-1-ND, TempCo=X6S, Tolerance_%=20, Value1=Unknown, Value2=10V, ValueDisplayed=10µF
D1: "Diode, TVS, Uni, 28 V, 600 W, SMB", Manufacturer="Diodes Inc.", Power_W=5, Supplier Part Number 1=SMBJ28A-FDICT-ND, Value1=5W
D2: "Diode, TVS, Uni, 14 V, 600 W, SMB", Manufacturer="Diodes Inc.", Power_W=5, Supplier Part Number 1=SMBJ14A-FDICT-ND, Value1=5W
D3: "Diode, Schottky, 100 V, 20 A, AEC-Q101, TO-277A", Manufacturer="Fairchild Semiconductor", Supplier Part Number 1=FSV20100VCT-ND, Value1=20A, Value2=0.66V
D4: "Diode, Schottky, 30 V, 2 A, SMB", Manufacturer="Diodes Inc.", Supplier Part Number 1=B230-FDICT-ND, Value1=2A, Value2=0.5V
D5: "LED, Yellow/green, SMD", Color=yellow/green, Manufacturer=Rohm, Supplier Part Number 1=511-1591-1-ND, Value1=W, Value2=2.2V
D6 D11 D16: "LED, Yellow, SMD", Color=yellow, Manufacturer=Rohm, Supplier Part Number 1=511-1595-1-ND, Value1=W, Value2=2.1V
D7 D13 D15 D18 D19: "LED, Green, SMD", Color=green, Manufacturer=Rohm, Supplier Part Number 1=511-1592-1-ND, Value1=W, Value2=2.2V
D8: "Diode, Schottky, 70V, 1A, SMA", Manufacturer="Diodes Inc.", Supplier Part Number 1=B170-FDICT-ND, Value1=1A, Value2=0.79V
D9: "Diode, Schottky, 60 V, 1 A, SOD-323F", Manufacturer="NXP Semiconductor", Supplier Part Number 1=568-4138-1-ND, Value1=1A, Value2=0.66V
D10 D12 D17: "LED, Orange, SMD", Color=orange, Manufacturer=Rohm, Supplier Part Number 1=511-1590-1-ND, Value1=W, Value2=2.1V
D14: "Diode, Schottky, 100 V, 3 A, AEC-Q101, SMC", Manufacturer=Vishay-Semiconductor, Supplier Part Number 1=VS-30BQ100HM3/9AT-ND, Value1=3A, Value2=0.79V
FID1 FID2 FID3 FID4 FID5 FID6: "Fiducial mark.  There is nothing to buy or mount.", Manufacturer=N/A
H1 H2 H3 H4: "Machine Screw, Round, #4-40 x 1/4, Nylon, Philips panhead", DigiKeyPartNumber=H542-ND, Manufacturer="B&F Fastener Supply"
H5 H6 H7 H8: "Standoff, Hex, 0.5\"L #4-40 Nylon", Alternate Manufacturer=-, Manufacturer=Keystone, Supplier Part Number 1=1902CK-ND
J1: "Male, Differential, 0.5mm, 10 pair x2, Gold, SMT", Manufacturer=Samtec, Supplier Part Number 1=QTH-020-01-L-D-DP-A-ND
J6 J7 J8 J9 J11: "Header, 100mil, 4x1, Gold, TH", Manufacturer=Samtec, Supplier Part Number 1=SAM1029-04-ND
J10: "Receptacle, 50mil, 6x1, Gold, R/A, TH", Manufacturer="Sullins Connector Solutions", Supplier Part Number 1=S9010E-06-ND
J12 J13 J16 J17 J18 J19 J20 J21: "Header, 100mil, 2x1, Gold, TH", Color=Black, Current_A=6.3, Manufacturer=Samtec, Supplier Part Number 1=SAM1029-02-ND, Voltage_V=550
J14 J40: "Header (Shrouded), 5.08 mm, 2x1, Tin, R/A, TH", Manufacturer="Phoenix Contact", Supplier Part Number 1=277-1106-ND
J15: "Header, 100mil, 5x2, Gold, TH", Manufacturer=Samtec, Supplier Part Number 1=SAM1028-05-ND
J22 J27: "Header, 100mil, 3x1, Gold, TH", Color=Black, Current_A=6.3, Manufacturer=Samtec, Supplier Part Number 1=SAM1029-03-ND, Voltage_V=550
J23 J24 J25 J26 J28 J30 J32 J34: "RIGHT ANGLE PLUG FOR PCB", Manufacturer=Rosenberger
J29 J31 J33 J35: "Right Angle Plug for PCB, TH", Manufacturer=Rosenberger
L1 L2 L3 L5 L6 L7 L8 L9 L11 L12 L13 L15 L16 L17 L18 L19 L78: library part BLM18SG331TN1D, "1.5A Ferrite Bead, 330 ohm @ 100MHz, SMD", Manufacturer=MuRata, Supplier Part Number 1=490-3996-1-ND, Value1="25 milliohm", Value2=3A
L4 L10 L14 L20: "Ferrite Bead, 120 ohm @ 100 MHz, 3 A, 0603", Manufacturer=MuRata, Supplier Part Number 1=490-3996-1-ND, Value1="0.025 ohm", Value2=3A
L21: "Inductor, Shielded, Composite, 6.8 µH, 18.5 A, 0.01 ohm, SMD", Manufacturer=Coilcraft, Supplier Part Number 1=994-XAL1010-682MEB, Value1="0.01 ohm", Value2=18.5A, ValueDisplayed=6.8µH
L22 L23 L24: "Inductor, Drum Core, Ferrite, 4.7 µH, 3.7 A, 0.03 ohm, SMD", Manufacturer=Bourns, Supplier Part Number 1=652-SDR0805-4R7ML, Value1="0.03 ohm", Value2=3.7A, ValueDisplayed=4.7µH
L25: "Inductor, Shielded, Composite, 2.2 µH, 32 A, 0.00255 ohm, SMD", Manufacturer=Coilcraft, Supplier Part Number 1=994-XAL1010-222MEB, Value1="0.00255 ohm", Value2=32A, ValueDisplayed=2.2µH
L26 L27 L34 L35 L42 L49 L56 L63: "Ferrite Bead, 1000 ohm @ 100 MHz, 0.8 A, 0603", Manufacturer=TDK, Supplier Part Number 1=445-8694-1-ND, Value1="0.3 ohm", Value2=0.8A
L28 L29 L38 L39 L51 L62 L70 L74: "Inductor, Wirewound, Ferrite, 10 µH, 0.81 A, 0.288 ohm, AEC-Q200 Grade 1, SMD", Manufacturer=MuRata, Supplier Part Number 1=81-LQH3NPZ100MJRL, Value1="0.288 ohm", Value2=0.81A, ValueDisplayed=10µH
L30 L31 L32 L33 L36 L37 L40 L41 L43 L44 L48 L50 L55 L57 L58 L64 L65 L69 L71 L72 L73 L75 L76 L77: "Ferrite Bead, 1500 ohm @ 100 MHz, 0.5 A, 0603", Manufacturer=MuRata, Supplier Part Number 1=490-5216-1-ND, Value1="0.5 ohm", Value2=0.5A, ValueDisplayed="1500 ohm"
L45 L46 L52 L53 L59 L60 L66 L67: "Inductor, Shielded, Ferrite, 10 µH, 0.79 A, 0.32 ohm, SMD", Manufacturer=Coilcraft, Value1="0.32 ohm", Value2=0.79A, ValueDisplayed=10µH
L47 L54 L61 L68: "Coupled inductor, 0.33 A, 0.35 ohm, SMD", Manufacturer=MuRata, Supplier Part Number 1=490-1064-1-ND
L79 L80 L81 L82 L83 L84 L85 L86: "Inductor, Shielded Drum Core, Ferrite, 100 µH, 0.71 A, 0.36 ohm, SMD", Manufacturer=Coilcraft, Value1="0.36 ohm", Value2=0.71A, ValueDisplayed=100µH
Logo1: library part TI_Logo, "Texas Instrument Corporate Signature"
Logo2: library part RoHS_Exempt, "RoHS_Exempt"
Logo3: library part FCC_disclaimer, "FCC_disclaimer"
NT1 NT2: "Single point connection between nets."
Q1: "MOSFET, N-CH, 40 V, 90 A, AEC-Q101, DPAK", Alternate Manufacturer=None, Manufacturer="Infineon Technologies", Supplier Part Number 1=IPD90N04S304ATMA1TR-ND, Value1="? ohm", Value2="60 nC"
Q2: "MOSFET, N-CH, 50 V, 0.22 A, SOT-23", Alternate Manufacturer=None, Manufacturer="Fairchild Semiconductor", Supplier Part Number 1=BSS138CT-ND, Value1="6 ohm", Value2="1.7 nC"
Q3: "MOSFET, N-CH, 30 V, 19 A, SON 3.3x3.3mm", Alternate Manufacturer=None, Manufacturer="Texas Instruments", Supplier Part Number 1=296-39995-1-ND, Value1="0.0064 ohm", Value2="13 nC"
Q4: "MOSFET, N-CH, 100 V, 200 A, TO-263-2", Alternate Manufacturer=None, Manufacturer="Texas Instruments", Supplier Part Number 1=296-41136-1-ND, Value1="? ohm", Value2="118 nC"
Q5: "MOSFET, N-CH, 25 V, 60 A, DQG0008A", Alternate Manufacturer=None, Manufacturer="Texas Instruments", Supplier Part Number 1=296-25646-1-ND, Value1="0.0043 ohm", Value2="6.5 nC"
Q6 Q7 Q8 Q9: "MOSFET, N-CH, 40 V, 33 A, AEC-Q101, SOT669", Alternate Manufacturer=None, Manufacturer="NXP Semiconductor", Supplier Part Number 1=568-10278-1-ND, Value1="? ohm", Value2="7 nC"
R1 R2 R3 R4 R5 R6 R7 R8 R9 R10 R11 R12 R13 R14 R15 R16 R17 R18 R19 R20 R78 R83 R103 R104 R105 R106 R107 R110 R111 R112 R113: "RES, 0, 5%, 0.063 W, 0402", Manufacturer=Vishay-Dale, Power_W=0.063, Supplier Part Number 1=541-0.0JCT-ND, TempCo="200 ppm/C", Tolerance_%=5, Value1=5%, Value2=0.063W, Value_Code=0000, ValueDisplayed=0
R21 R23 R36: "RES, 13.3 k, 1%, 0.063 W, 0402", Manufacturer=Vishay-Dale, Power_W=0.063, Supplier Part Number 1=541-13.3KLCT-ND, TempCo="100 ppm/C", Tolerance_%=1, Value1=1%, Value2=0.063W, Value_Code=13k3, ValueDisplayed=13.3k
R22 R35: "RES, 487, 1%, 0.063 W, 0402", Manufacturer=Vishay-Dale, Power_W=0.063, Supplier Part Number 1=541-487LCT-ND, TempCo="100 ppm/C", Tolerance_%=1, Value1=1%, Value2=0.063W, Value_Code=487R, ValueDisplayed=487
R24 R37: "RES, 82.5 k, 1%, 0.063 W, 0402", Manufacturer=Vishay-Dale, Power_W=0.063, Supplier Part Number 1=541-82.5KLCT-ND, TempCo="100 ppm/C", Tolerance_%=1, Value1=1%, Value2=0.063W, Value_Code=82k5, ValueDisplayed=82.5k
R25 R27 R40: "RES, 40.2 k, 1%, 0.063 W, 0402", Manufacturer=Vishay-Dale, Power_W=0.063, Supplier Part Number 1=541-40.2KLCT-ND, TempCo="100 ppm/C", Tolerance_%=1, Value1=1%, Value2=0.063W, Value_Code=40k2, ValueDisplayed=40.2k
R26 R30 R31 R39 R43 R52 R53 R87 R95 R101 R149 R150 R151 R186 R245: "RES, 10 k, 5%, 0.063 W, 0402", Manufacturer=Vishay-Dale, Power_W=0.063, Supplier Part Number 1=541-10KJCT-ND, TempCo="200 ppm/C", Tolerance_%=5, Value1=5%, Value2=0.063W, Value_Code=10k0, ValueDisplayed=10k
R28 R41: "RES, 102 k, 1%, 0.063 W, 0402", Manufacturer=Vishay-Dale, Power_W=0.063, Supplier Part Number 1=541-102KLCT-ND, TempCo="100 ppm/C", Tolerance_%=1, Value1=1%, Value2=0.063W, Value_Code=102k
R29 R42 R73 R74: "RES, 100, 1%, 0.063 W, 0402", Manufacturer=Vishay-Dale, Power_W=0.063, Supplier Part Number 1=541-100LCT-ND, TempCo="100 ppm/C", Tolerance_%=1, Value1=1%, Value2=0.063W, Value_Code=100R, ValueDisplayed=100
R32 R33 R75 R109 R119 R174 R175 R188 R189 R202 R203 R216 R217 R251 R252: "RES, 0, 5%, 0.1 W, 0603", Manufacturer=Vishay-Dale, Power_W=0.1, Supplier Part Number 1=541-0.0GCT-ND, TempCo="200 ppm/C", Tolerance_%=5, Value1=5%, Value2=0.1W, Value_Code=0000, ValueDisplayed=0
R34: "RES, 113 k, 1%, 0.063 W, 0402", Manufacturer=Vishay-Dale, Power_W=0.063, Supplier Part Number 1=541-113KLCT-ND, TempCo="100 ppm/C", Tolerance_%=1, Value1=1%, Value2=0.063W, Value_Code=113k
R38: "RES, 88.7 k, 1%, 0.063 W, 0402", Manufacturer=Vishay-Dale, Power_W=0.063, Supplier Part Number 1=541-88.7KLCT-ND, TempCo="100 ppm/C", Tolerance_%=1, Value1=1%, Value2=0.063W, Value_Code=88k7, ValueDisplayed=88.7k
R44 R45 R46 R47 R48 R49 R50 R228 R235 R240 R243: "RES, 200, 5%, 0.063 W, 0402", Manufacturer=Vishay-Dale, Power_W=0.063, Supplier Part Number 1=541-200JCT-ND, TempCo="200 ppm/C", Tolerance_%=5, Value1=5%, Value2=0.063W, Value_Code=200R, ValueDisplayed=200
R51 R60 R61 R96 R250: "RES, 220, 5%, 0.063 W, 0402", Manufacturer=Vishay-Dale, Power_W=0.063, Supplier Part Number 1=541-220JCT-ND, TempCo="200 ppm/C", Tolerance_%=5, Value1=5%, Value2=0.063W, Value_Code=220R, ValueDisplayed=220
R54 R55 R56 R57 R67 R68 R238: "Res, Chip, 4.7K, 1/16W, 5%, 0402", Manufacturer=Vishay-Dale, PART Name=SCH_LIB\RES, Power_W=0.063, Supplier Part Number 1=71-CRCW0402J-4.7K-E3, TempCo="200 ppm/C", Tolerance_%=5, Value1=5%, Value2=0.063W, Value_Code=4k70
R58 R59 R248 R249: "RES, 487 ohm, 1%, 0.063W, 0402", Alternate Manufacturer=Any, Alternate PartNumber=Equivalent, Manufacturer=Vishay-Dale, Power_W=0.063, Supplier Part Number 1=541-487LCT-ND, TempCo="100 ppm/C", Tolerance_%=1, Value1=1%, Value2=0.063W, Value_Code=487R
R62 R92 R93 R124 R125 R126 R127 R148: "RES, 4.02 k, 1%, 0.1 W, 0603", Manufacturer=Vishay-Dale, Power_W=0.1, Supplier Part Number 1=541-4.02KHCT-ND, TempCo="100 ppm/C", Tolerance_%=1, Value1=1%, Value2=0.1W, Value_Code=4k02, ValueDisplayed=4.02k
R63 R64: "RES, 0 ohm, 5%, 0.063W, 0402", Manufacturer=Vishay-Dale, Power_W=0.063, Supplier Part Number 1=541-0.0JCT-ND, TempCo="200 ppm/C", Tolerance_%=5, Value1=5%, Value2=0.063W, Value_Code=0000
R65 R91: "RES, 20 k, 5%, 0.063 W, 0402", Manufacturer=Vishay-Dale, Power_W=0.063, Supplier Part Number 1=541-20KJCT-ND, TempCo="200 ppm/C", Tolerance_%=5, Value1=5%, Value2=0.063W, Value_Code=20k0, ValueDisplayed=20k
R66 R128 R129 R130 R131 R168 R169 R170 R171: "RES, 0 ohm, 5%, 0.1W, 0603", Manufacturer=Vishay-Dale, Power_W=0.1, Supplier Part Number 1=541-0.0GCT-ND, TempCo="200 ppm/C", Tolerance_%=5, Value1=5%, Value2=0.1W, Value_Code=0000
R69 R70 R71 R72 R230 R233: "RES, 4.7k ohm, 5%, 0.1W, 0603", Manufacturer=Vishay-Dale, Power_W=0.1, Supplier Part Number 1=71-CRCW0603J-4.7K-E3, TempCo="200 ppm/C", Tolerance_%=5, Value1=5%, Value2=0.1W, Value_Code=4k70
R76: "RES, 49.9 k, 1%, 0.063 W, 0402", Manufacturer=Vishay-Dale, Power_W=0.063, Supplier Part Number 1=541-49.9KLCT-ND, TempCo="100 ppm/C", Tolerance_%=1, Value1=1%, Value2=0.063W, Value_Code=49k9, ValueDisplayed=49.9k
R77: "RES, 47 k, 5%, 0.063 W, 0402", Manufacturer=Vishay-Dale, Power_W=0.063, Supplier Part Number 1=541-47KJCT-ND, TempCo="200 ppm/C", Tolerance_%=5, Value1=5%, Value2=0.063W, Value_Code=47k0, ValueDisplayed=47k
R79: "RES, 18.2 k, 1%, 0.063 W, 0402", Manufacturer=Vishay-Dale, Power_W=0.063, Supplier Part Number 1=541-18.2KLCT-ND, TempCo="100 ppm/C", Tolerance_%=1, Value1=1%, Value2=0.063W, Value_Code=18k2, ValueDisplayed=18.2k
R80: "RES, 28.7 k, 1%, 0.063 W, 0402", Manufacturer=Vishay-Dale, Power_W=0.063, Supplier Part Number 1=541-28.7KLCT-ND, TempCo="100 ppm/C", Tolerance_%=1, Value1=1%, Value2=0.063W, Value_Code=28k7, ValueDisplayed=28.7k
R81: "RES, 107 k, 1%, 0.063 W, 0402", Manufacturer=Vishay-Dale, Power_W=0.063, Supplier Part Number 1=541-107KLCT-ND, TempCo="100 ppm/C", Tolerance_%=1, Value1=1%, Value2=0.063W, Value_Code=107k
R82: "RES, 5.23 k, 1%, 0.063 W, 0402", Manufacturer=Vishay-Dale, Power_W=0.063, Supplier Part Number 1=541-5.23KLCT-ND, TempCo="100 ppm/C", Tolerance_%=1, Value1=1%, Value2=0.063W, Value_Code=5k23, ValueDisplayed=5.23k
R84: "RES, 28.0 k, 1%, 0.063 W, 0402", Manufacturer=Vishay-Dale, Power_W=0.063, Supplier Part Number 1=541-28.0KLCT-ND, TempCo="100 ppm/C", Tolerance_%=1, Value1=1%, Value2=0.063W, Value_Code=28k0, ValueDisplayed=28.0k
R85: "RES, 45.3 k, 1%, 0.063 W, 0402", Manufacturer=Vishay-Dale, Power_W=0.063, Supplier Part Number 1=541-45.3KLCT-ND, TempCo="100 ppm/C", Tolerance_%=1, Value1=1%, Value2=0.063W, Value_Code=45k3, ValueDisplayed=45.3k
R86: "RES, 14.0 k, 1%, 0.063 W, 0402", Manufacturer=Vishay-Dale, Power_W=0.063, Supplier Part Number 1=541-14.0KLCT-ND, TempCo="100 ppm/C", Tolerance_%=1, Value1=1%, Value2=0.063W, Value_Code=14k0, ValueDisplayed=14.0k
R88 R102: "RES, 360, 5%, 0.063 W, 0402", Manufacturer=Vishay-Dale, Power_W=0.063, Supplier Part Number 1=541-360JCT-ND, TempCo="200 ppm/C", Tolerance_%=5, Value1=5%, Value2=0.063W, Value_Code=360R, ValueDisplayed=360
R89 R138 R139 R158 R159 R177 R191 R205 R219: "RES, 100 k, 0.5%, 0.063 W, 0402", Manufacturer=Vishay-Dale, Power_W=0.063, Supplier Part Number 1=541-100KAVCT-ND, TempCo="50 ppm/C", Tolerance_%=0.5, Value1=0.5%, Value2=0.063W, Value_Code=100k
R90 R99: "RES, 10, 5%, 0.063 W, 0402", Manufacturer=Vishay-Dale, Power_W=0.063, Supplier Part Number 1=541-10JCT-ND, TempCo="200 ppm/C", Tolerance_%=5, Value1=5%, Value2=0.063W, Value_Code=10R0, ValueDisplayed=10
R94: "RES, 6.98 k, 1%, 0.063 W, 0402", Manufacturer=Vishay-Dale, Power_W=0.063, Supplier Part Number 1=541-6.98KLCT-ND, TempCo="100 ppm/C", Tolerance_%=1, Value1=1%, Value2=0.063W, Value_Code=6k98, ValueDisplayed=6.98k
R97: "RES, 8.25 k, 1%, 0.063 W, 0402", Manufacturer=Vishay-Dale, Power_W=0.063, Supplier Part Number 1=541-8.25KLCT-ND, TempCo="100 ppm/C", Tolerance_%=1, Value1=1%, Value2=0.063W, Value_Code=8k25, ValueDisplayed=8.25k
R98: "RES, 4.87 k, 1%, 0.063 W, 0402", Manufacturer=Vishay-Dale, Power_W=0.063, Supplier Part Number 1=541-4.87KLCT-ND, TempCo="100 ppm/C", Tolerance_%=1, Value1=1%, Value2=0.063W, Value_Code=4k87, ValueDisplayed=4.87k
R100: "RES, 21.5 k, 1%, 0.063 W, 0402", Manufacturer=Vishay-Dale, Power_W=0.063, Supplier Part Number 1=541-21.5KLCT-ND, TempCo="100 ppm/C", Tolerance_%=1, Value1=1%, Value2=0.063W, Value_Code=21k5, ValueDisplayed=21.5k
R108 R114 R115: "RES, 4.99, 1%, 0.1 W, 0603", Manufacturer=Vishay-Dale, Power_W=0.1, Supplier Part Number 1=541-4.99HHCT-ND, TempCo="100 ppm/C", Tolerance_%=1, Value1=1%, Value2=0.1W, Value_Code=4R99, ValueDisplayed=4.99
R116: "RES, 2.2, 5%, 0.1 W, 0603", Manufacturer=Vishay-Dale, Power_W=0.1, Supplier Part Number 1=541-2.2GCT-ND, TempCo="200 ppm/C", Tolerance_%=5, Value1=5%, Value2=0.1W, Value_Code=2R20, ValueDisplayed=2.2
R117: library part Resistor, "RES, 0.004 ohm, 1%, 1W, 2010, AEC-Q200 Qualified", Manufacturer="Rohm Semiconductor"
R118: "RES, 49.9, 1%, 0.1 W, 0603", Manufacturer=Vishay-Dale, Power_W=0.1, Supplier Part Number 1=541-49.9HCT-ND, TempCo="100 ppm/C", Tolerance_%=1, Value1=1%, Value2=0.1W, Value_Code=49R9, ValueDisplayed=49.9
R120: "RES, 100 k, 1%, 0.125 W, 0805", Manufacturer=Vishay-Dale, Power_W=0.125, Supplier Part Number 1=541-100KCCT-ND, TempCo="100 ppm/C", Tolerance_%=1, Value1=1%, Value2=0.125W, Value_Code=100k
R121: "RES, 2.2 k, 5%, 0.063 W, 0402", Manufacturer=Vishay-Dale, Power_W=0.063, Supplier Part Number 1=541-2.2KJCT-ND, TempCo="200 ppm/C", Tolerance_%=5, Value1=5%, Value2=0.063W, Value_Code=2k20, ValueDisplayed=2.2k
R122: "RES, 10, 5%, 0.75 W, 2010", Manufacturer=Vishay-Dale, Power_W=0.75, Supplier Part Number 1=541-10.0WCT-ND, TempCo="200 ppm/C", Tolerance_%=5, Value1=5%, Value2=0.75W, Value_Code=10R0, ValueDisplayed=10
R123: "RES, 12.1 k, 1%, 0.063 W, 0402", Manufacturer=Vishay-Dale, Power_W=0.063, Supplier Part Number 1=541-12.1KLCT-ND, TempCo="100 ppm/C", Tolerance_%=1, Value1=1%, Value2=0.063W, Value_Code=12k1, ValueDisplayed=12.1k
R132 R133 R152 R153 R182 R183 R184 R195 R196 R198 R210 R211 R212 R223 R224 R226: "RES, 49.9, 1%, 0.063 W, 0402", Manufacturer=Vishay-Dale, Power_W=0.063, Supplier Part Number 1=541-49.9LCT-ND, TempCo="100 ppm/C", Tolerance_%=1, Value1=1%, Value2=0.063W, Value_Code=49R9, ValueDisplayed=49.9
R134 R135 R154 R155 R185 R199 R213 R227: "RES, 2.00 k, 1%, 0.1 W, 0603", Manufacturer=Vishay-Dale, Power_W=0.1, Supplier Part Number 1=541-2.00KHCT-ND, TempCo="100 ppm/C", Tolerance_%=1, Value1=1%, Value2=0.1W, Value_Code=2k00, ValueDisplayed=2.00k
R136 R137 R156 R157 R176 R190 R204 R218: "RES, 309 k, 1%, 0.063 W, 0402", Manufacturer=Vishay-Dale, Power_W=0.063, Supplier Part Number 1=541-309KLCT-ND, TempCo="100 ppm/C", Tolerance_%=1, Value1=1%, Value2=0.063W, Value_Code=309k
R140 R141 R160 R161 R178 R192 R206 R220: "RES, 69.8 k, 1%, 0.063 W, 0402", Manufacturer=Vishay-Dale, Power_W=0.063, Supplier Part Number 1=541-69.8KLCT-ND, TempCo="100 ppm/C", Tolerance_%=1, Value1=1%, Value2=0.063W, Value_Code=69k8, ValueDisplayed=69.8k
R142 R143 R162 R163 R179 R193 R207 R221: "RES, 30.9 k, 1%, 0.063 W, 0402", Manufacturer=Vishay-Dale, Power_W=0.063, Supplier Part Number 1=541-30.9KLCT-ND, TempCo="100 ppm/C", Tolerance_%=1, Value1=1%, Value2=0.063W, Value_Code=30k9, ValueDisplayed=30.9k
R144 R145 R164 R165 R180 R194 R208 R222: "RES, 44.2 k, 1%, 0.063 W, 0402", Manufacturer=Vishay-Dale, Power_W=0.063, Supplier Part Number 1=541-44.2KLCT-ND, TempCo="100 ppm/C", Tolerance_%=1, Value1=1%, Value2=0.063W, Value_Code=44k2, ValueDisplayed=44.2k
R146 R147 R166 R167 R181 R197 R209 R225: "RES, 16.9 k, 1%, 0.063 W, 0402", Manufacturer=Vishay-Dale, Power_W=0.063, Supplier Part Number 1=541-16.9KLCT-ND, TempCo="100 ppm/C", Tolerance_%=1, Value1=1%, Value2=0.063W, Value_Code=16k9, ValueDisplayed=16.9k
R172 R173 R187 R200 R201 R214 R215 R253: "RES, 0.01, 1%, 1 W, AEC-Q200 Grade 0, 0508", Manufacturer="Susumu Co Ltd", Power_W=1, TempCo="25 ppm/C", Value1=1%, Value2=1W, Value_Code=R010, ValueDisplayed=0.01
R229 R231 R232 R234 R236 R237 R239 R241 R242 R244 R246 R247: "RES, 4.7 k, 5%, 0.063 W, 0402", Manufacturer=Vishay-Dale, Power_W=0.063, Supplier Part Number 1=541-4.7KJCT-ND, TempCo="200 ppm/C", Tolerance_%=5, Value1=5%, Value2=0.063W, Value_Code=4k70, ValueDisplayed=4.7k
Rsense1: "RES, 0.005, 1%, 1 W, 0612", Manufacturer="Susumu Co Ltd", Power_W=1, Supplier Part Number 1=PRL1632.005FCT-ND, TempCo="350 ppm/C", Value1=1%, Value2=1W, Value_Code=5L000, ValueDisplayed=0.005
S1 S2: "Switch, Push Button, SMD", CurrentRating_mA=50, Manufacturer=Alps, Supplier Part Number 1=688-SKRKAE
S3 S4 S5: "Switch, Slide, SPST 4 poles, SMT", CurrentRating_mA=25, Manufacturer="CTS Electrocomponents", Supplier Part Number 1=CT2184LPST-ND
TP1 TP2 TP3 TP4: "Test Point, O.025\"", Manufacturer=STD
TP5 TP6 TP7 TP8 TP9 TP18 TP19 TP20 TP21 TP24 TP25 TP26 TP27 TP29 TP30 TP32 TP33 TP35 TP36 TP38 TP39: "Test Point, Miniature, Yellow, TH", Manufacturer=Keystone, Supplier Part Number 1=5004K-ND
TP10 TP11: "Test Point, Multipurpose, White, TH", Color=White, Manufacturer=Keystone, Supplier Part Number 1=36-5012-ND
TP12 TP15 TP40 TP41 TP42 TP43 TP44 TP45 TP46 TP47 TP48 TP49 TP50 TP51 TP52 TP53 TP54 TP55: library part 5011, "Test Point, Multipurpose, Black, TH", Manufacturer=Keystone, Supplier Part Number 1=5011K-ND
TP13: library part 5012, "Test Point, Multipurpose, White, TH", Manufacturer=Keystone, Supplier Part Number 1=5012K-ND
TP14: library part 5010, "Test Point, Multipurpose, Red, TH", Manufacturer=Keystone, Supplier Part Number 1=5010K-ND
TP16 TP17 TP22 TP23 TP28 TP31 TP34 TP37: "Test Point, Miniature, Red, TH", Manufacturer=Keystone, Supplier Part Number 1=5000K-ND
U1 U2: "FPD-Link III Camera Hub Deserializer, RGC0064G", Alternate Manufacturer="Texas Instruments", Alternate PartNumber=DS90UB960TRGCTQ1
U3: "16 MHz Mixed Signal Microcontroller with 32 KB Flash, 1024 B SARM and 32 GPIOs, -40 to 105 degC, 38-pin SOP (DA)", Alternate Manufacturer="Texas Instruments", Alternate PartNumber=Equivalent, Frequency(MHz)=16, Pin/Package="38TSSOP, 40VQFN", Temp Sensor=Yes
U4 U5 U6: "Automotive Catalog ESD Protected, High-Speed USB 2.0 (480-Mbps) 1:2 Multiplexer / Demultiplexer Switch, 16 ohm RON, 2.5 to 3.3V, -40 to 125 degC, 10-Pin UQFN (RSE), Green (RoHS & no Sb/Br)", Alternate Manufacturer="Texas Instruments", Alternate PartNumber=Equivalent, Supplier Part Number 1=296-27719-2-ND
U7: "Smart Diode Controller, DGK0008A", Alternate Manufacturer="Texas Instruments"
U8: "Wide Input Synchronous Boost Controller with Disconnection Switch Control, PWP0020A", Alternate Manufacturer="Texas Instruments"
U9: library part TPS65263RHBR-Q1, "4.5V to 18V Input Voltage, 3A/2A/2A Output Current Step-Down Converter with I2C controlled DVS., RHB0032E (VQFN-32)", Alternate Manufacturer="Texas Instruments", Alternate PartNumber=TPS65263QRHBTQ1
U10: "Wide Input Range Buck Controller, RGE0024H", Alternate Manufacturer="Texas Instruments"
U11 U12 U13 U14 U15 U17 U19 U21: "2.7 – 18V eFuse with True Reverse Blocking and DevSleep Support for SSDs, RVC0020A", Alternate Manufacturer="Texas Instruments", Alternate PartNumber=TPS25940ARVCT
U16 U18 U20 U22: "Low-Capacitance + / - 15 kV ESD-Protection Array for High-Speed Data Interfaces, 2 Channels, -40 to +85 degC, 5-pin SOT (DRL), Green (RoHS & no Sb/Br)", Alternate Manufacturer="Texas Instruments", Alternate PartNumber=Equivalent, Breakdown Voltage(Min)(V)=11, IO Capacitance(Typ)(pF)=1.5, IO Leakage Current(nA)=1, Supplier Part Number 1=296-21883-2-ND
U23 U24 U25 U26: "One Channel Differential 2:1 Mux/Demux, RWA0014A", Alternate Manufacturer="Texas Instruments", Alternate PartNumber=HD3SS3411IRWAQ1
U27: library part 24WC256, Manufacturer="Catalyst Semiconductor"
Y1: "XO, 25.000MHz, 2.5V, SMD", Frequency=25MHz, Frequency Stability=±50ppm, Manufacturer="TXC Corporation"
ZZ1: library part AssemblyNoteLabel, Alternate Manufacturer=-
ZZ2 ZZ3 ZZ4: library part AssemblyNote, Alternate Manufacturer=-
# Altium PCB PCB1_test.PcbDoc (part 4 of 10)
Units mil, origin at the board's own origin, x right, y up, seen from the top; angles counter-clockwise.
Board outline 6690 x 6690 mil, 6 copper layers (Layer 1 - Top Layer, Layer 2 - GND, Layer 3 - PWR, Layer 4 - Signal, Layer 5 - GND, Layer 6 - Bottom Layer), stack 80.244 mil thick; 821 components, 458 nets, 3746 pads, 1527 vias.

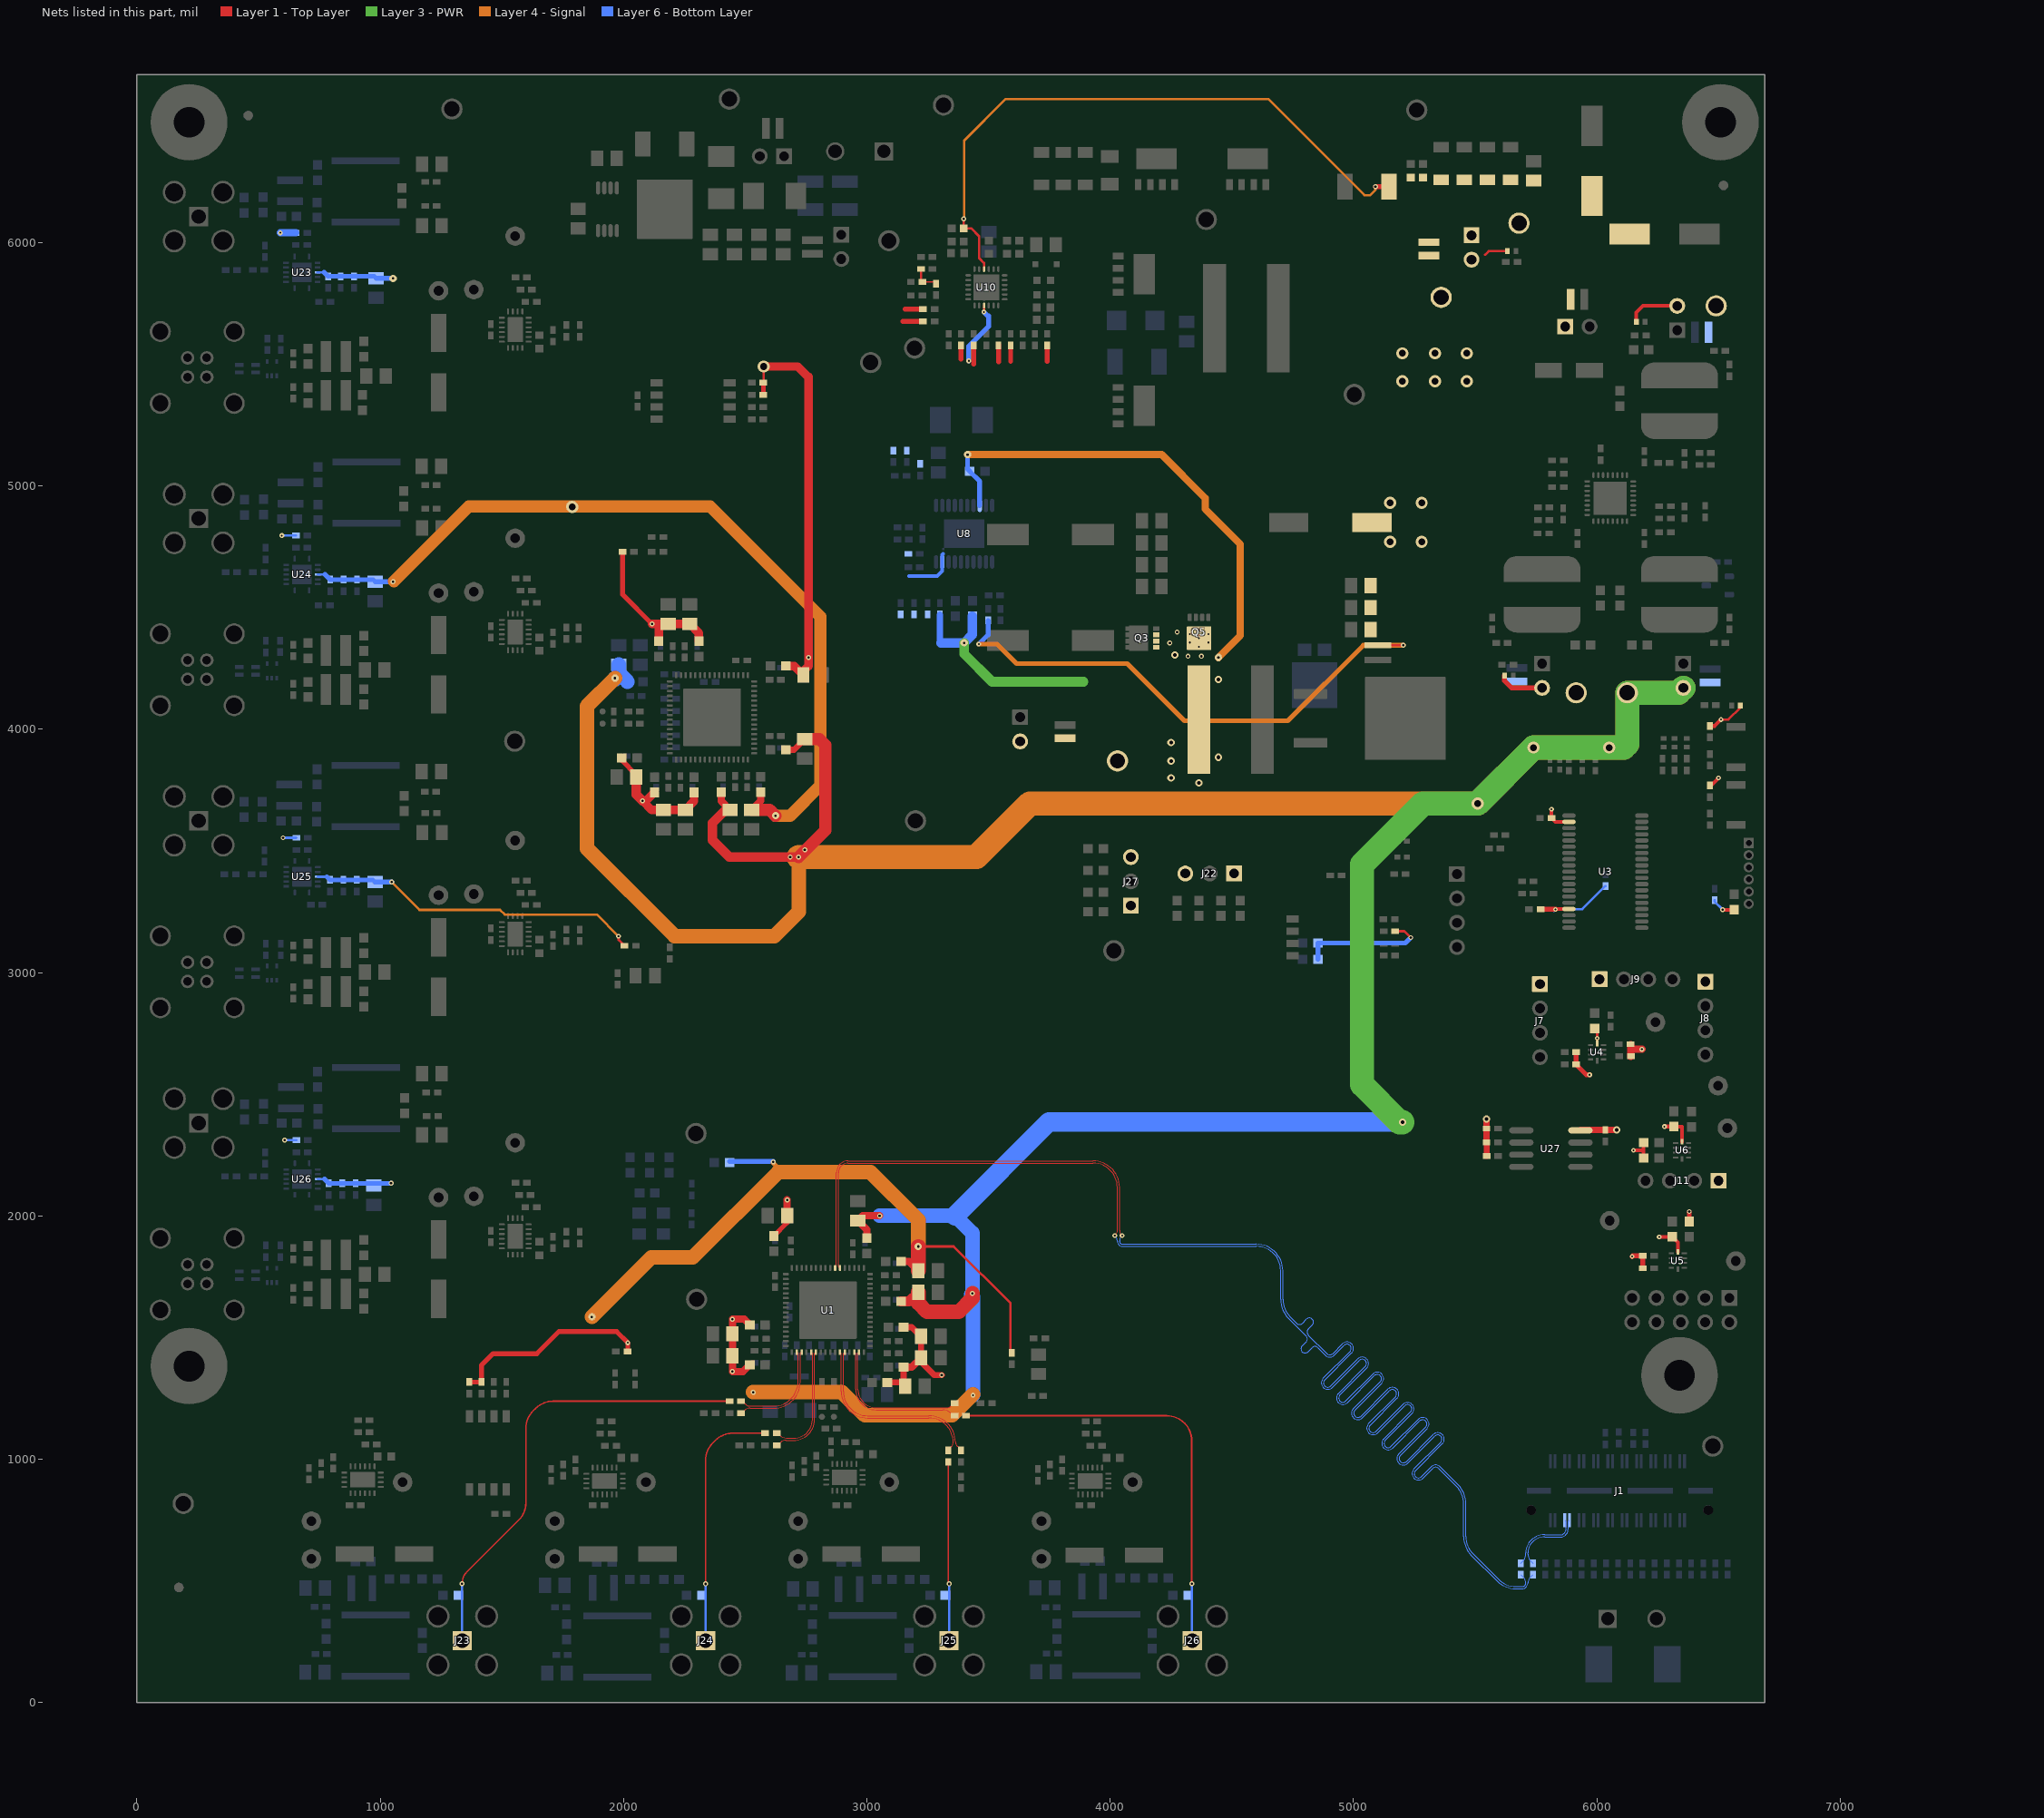
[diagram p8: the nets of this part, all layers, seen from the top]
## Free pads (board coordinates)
  round 40 on Mech16: 1(74.88,530) 1(74.88,650) 1(104.88,530) 1(104.88,650) 1(359.88,250) 1(359.88,370) 1(389.88,250) 1(389.88,370)
  round 54 on Mech16: 1(89.88,590) 1(374.88,310) 1(1910.88,1264.1) 1(3974.88,4905) 1(4224.88,5705)
  round 25 on Mech16: 1(274.88,1776) 1(274.88,1851) 1(274.88,2019) 1(274.88,2094) 1(324.88,1776) 1(324.88,1851) 1(324.88,2019) 1(324.88,2094) 1(374.88,1776) 1(374.88,1851) 1(374.88,2019) 1(374.88,2094) 1(424.88,1776) 1(424.88,1851) 1(424.88,2019) 1(424.88,2094)
  round 70 on Mech16: 1(437.71,6468.15) 1(437.71,6528.15) 1(574.88,6222.56) 1(589.38,6458.78) 1(640.38,6458.78) 1(654.88,6222.56) 1(792.05,6468.15) 1(792.05,6528.15)
  round 35 on Mech16: 1(592.38,4267) 1(592.38,4343) 1(617.38,4267) 1(617.38,4343) 1(654.88,4120) 1(654.88,4180) 1(664.88,4120) 1(664.88,4180) 1(854.88,290) 1(854.88,350) 1(864.88,290) 1(864.88,350) 1(904.88,4350) 1(904.88,4360) 1(954.88,4120) 1(954.88,4180) 1(964.88,4120) 1(964.88,4180) 1(964.88,4350) 1(964.88,4360) 1(1739.88,3575) 1(1739.88,3585) 1(1799.88,3575) 1(1799.88,3585) 1(1879.88,3640) 1(1879.88,3650) 1(1879.88,3720) 1(1879.88,3780) 1(1889.88,3720) 1(1889.88,3780) 1(1939.88,3640) 1(1939.88,3650) 1(2459.88,80) 1(2459.88,90) 1(2519.88,80) 1(2519.88,90) 1(2759.88,80) 1(2759.88,90) 1(2819.88,80) 1(2819.88,90) 1(2854.88,5620) 1(2854.88,5680) 1(2864.88,5620) 1(2864.88,5680) 1(2929.88,5620) 1(2929.88,5680) 1(2939.88,5620) 1(2939.88,5680) 1(3009.88,5620) 1(3009.88,5680) 1(3009.88,5790) 1(3009.88,5850) 1(3019.88,5620) 1(3019.88,5680) 1(3019.88,5790) 1(3019.88,5850) 1(3024.88,80) 1(3024.88,90) 1(3084.88,80) 1(3084.88,90) 1(3324.88,80) 1(3324.88,90) 1(3384.88,80) 1(3384.88,90) 1(3414.88,4715) 1(3414.88,4725) 1(3414.88,5065) 1(3414.88,5075) 1(3474.88,4715) 1(3474.88,4725) 1(3474.88,5065) 1(3474.88,5075) 1(3664.88,5515) 1(3664.88,5525) 1(3664.88,5865) 1(3664.88,5875) 1(3724.88,5515) 1(3724.88,5525) 1(3724.88,5865) 1(3724.88,5875) 1(4439.88,5780) 1(4439.88,5790) 1(4439.88,5905) 1(4439.88,5915) 1(4499.88,5780) 1(4499.88,5790) 1(4499.88,5905) 1(4499.88,5915) 1(4629.88,5325) 1(4629.88,5335) 1(4639.88,5210) 1(4639.88,5220) 1(4689.88,5325) 1(4689.88,5335) 1(4699.88,5210) 1(4699.88,5220) 1(5469.88,6485) 1(5469.88,6545) 1(5479.88,6485) 1(5479.88,6545) 1(6239.88,4295) 1(6239.88,4305) 1(6239.88,4360) 1(6239.88,4370) 1(6239.88,4425) 1(6239.88,4435) 1(6239.88,4495) 1(6239.88,4505) 1(6239.88,4565) 1(6239.88,4575) 1(6239.88,4630) 1(6239.88,4640) 1(6299.88,4295) 1(6299.88,4305) 1(6299.88,4360) 1(6299.88,4370) 1(6299.88,4425) 1(6299.88,4435) 1(6299.88,4495) 1(6299.88,4505) 1(6299.88,4565) 1(6299.88,4575) 1(6299.88,4630) 1(6299.88,4640) 1(6474.88,5355) 1(6474.88,5365) 1(6519.88,3885) 1(6519.88,3945) 1(6524.88,4720) 1(6524.88,4780) 1(6529.88,3885) 1(6529.88,3945) 1(6534.88,4720) 1(6534.88,4780) 1(6534.88,5355) 1(6534.88,5365) 1(6589.88,4110) 1(6589.88,4170) 1(6589.88,4720) 1(6589.88,4780) 1(6599.88,4110) 1(6599.88,4170) 1(6599.88,4720) 1(6599.88,4780) 1(6634.88,3895) 1(6634.88,3955) 1(6644.88,3895) 1(6644.88,3955) 1(6659.88,4720) 1(6659.88,4780) 1(6669.88,4720) 1(6669.88,4780) 1(6884.88,4245) 1(6884.88,4255) 1(6884.88,4310) 1(6884.88,4320) 1(6884.88,4550) 1(6884.88,4560) 1(6884.88,4610) 1(6884.88,4620) 1(6889.88,6575) 1(6889.88,6585) 1(6944.88,4245) 1(6944.88,4255) 1(6944.88,4310) 1(6944.88,4320) 1(6944.88,4550) 1(6944.88,4560) 1(6944.88,4610) 1(6944.88,4620) 1(6949.88,6575) 1(6949.88,6585) 1(7519.88,985) 1(7519.88,995) 1(7554.88,915) 1(7554.88,925) 1(7579.88,985) 1(7579.88,995) 1(7614.88,915) 1(7614.88,925) 1(7644.88,660) 1(7644.88,720) 1(7654.88,660) 1(7654.88,720)
  round 14 on Mech16: 1(1796.88,1009.2) 1(1796.88,1034.8) 1(1796.88,1060.4) 1(1796.88,1086) 1(1796.88,1111.6) 1(1796.88,1137.2) 1(1796.88,1162.8) 1(1796.88,1188.4) 1(1796.88,1214) 1(1796.88,1239.6) 1(1796.88,1265.2) 1(1796.88,1290.8) 1(1852.88,1009.2) 1(1852.88,1034.8) 1(1852.88,1060.4) 1(1852.88,1086) 1(1852.88,1111.6) 1(1852.88,1137.2) 1(1852.88,1162.8) 1(1852.88,1188.4) 1(1852.88,1214) 1(1852.88,1239.6) 1(1852.88,1265.2) 1(1852.88,1290.8) 1(2026.88,1009.2) 1(2026.88,1034.8) 1(2026.88,1060.4) 1(2026.88,1086) 1(2026.88,1111.6) 1(2026.88,1137.2) 1(2026.88,1162.8) 1(2026.88,1188.4) 1(2026.88,1214) 1(2026.88,1239.6) 1(2026.88,1265.2) 1(2026.88,1290.8) 1(2082.88,1009.2) 1(2082.88,1034.8) 1(2082.88,1060.4) 1(2082.88,1086) 1(2082.88,1111.6) 1(2082.88,1137.2) 1(2082.88,1162.8) 1(2082.88,1188.4) 1(2082.88,1214) 1(2082.88,1239.6) 1(2082.88,1265.2) 1(2082.88,1290.8) 1(2194.28,1175.4) 1(2194.28,1201) 1(2194.28,1226.6) 1(2194.28,1252.2) 1(2194.28,1277.8) 1(2194.28,1303.4) 1(2194.28,1329) 1(2194.28,1354.6) 1(2194.28,1415.4) 1(2194.28,1441) 1(2194.28,1466.6) 1(2194.28,1492.2) 1(2194.28,1517.8) 1(2194.28,1543.4) 1(2194.28,1569) 1(2194.28,1594.6) 1(2194.28,1655.4) 1(2194.28,1681) 1(2194.28,1706.6) 1(2194.28,1732.2) 1(2194.28,1757.8) 1(2194.28,1783.4) 1(2194.28,1809) 1(2194.28,1834.6) 1(2237.38,2000) 1(2237.38,2056) 1(2237.38,2214) 1(2237.38,2270) 1(2250.28,1175.4) 1(2250.28,1201) 1(2250.28,1226.6) 1(2250.28,1252.2) 1(2250.28,1277.8) 1(2250.28,1303.4) 1(2250.28,1329) 1(2250.28,1354.6) 1(2250.28,1415.4) 1(2250.28,1441) 1(2250.28,1466.6) 1(2250.28,1492.2) 1(2250.28,1517.8) 1(2250.28,1543.4) 1(2250.28,1569) 1(2250.28,1594.6) 1(2250.28,1655.4) 1(2250.28,1681) 1(2250.28,1706.6) 1(2250.28,1732.2) 1(2250.28,1757.8) 1(2250.28,1783.4) 1(2250.28,1809) 1(2250.28,1834.6) 1(2262.38,2000) 1(2262.38,2056) 1(2262.38,2214) 1(2262.38,2270) 1(2287.38,2000) 1(2287.38,2056) 1(2287.38,2214) 1(2287.38,2270) 1(2312.38,2000) 1(2312.38,2056) 1(2312.38,2214) 1(2312.38,2270) 1(2337.38,2000) 1(2337.38,2056) 1(2337.38,2214) 1(2337.38,2270) 1(2362.38,2000) 1(2362.38,2056) 1(2362.38,2214) 1(2362.38,2270) 1(2387.38,2000) 1(2387.38,2056) 1(2387.38,2214) 1(2387.38,2270) 1(2412.38,2000) 1(2412.38,2056) 1(2412.38,2214) 1(2412.38,2270) 1(2429.48,1175.4) 1(2429.48,1201) 1(2429.48,1226.6) 1(2429.48,1252.2) 1(2429.48,1277.8) 1(2429.48,1303.4) 1(2429.48,1329) 1(2429.48,1354.6) 1(2429.48,1415.4) 1(2429.48,1441) 1(2429.48,1466.6) 1(2429.48,1492.2) 1(2429.48,1517.8) 1(2429.48,1543.4) 1(2429.48,1569) 1(2429.48,1594.6) 1(2429.48,1655.4) 1(2429.48,1681) 1(2429.48,1706.6) 1(2429.48,1732.2) 1(2429.48,1757.8) 1(2429.48,1783.4) 1(2429.48,1809) 1(2429.48,1834.6) 1(2437.38,2000) 1(2437.38,2056) 1(2437.38,2214) 1(2437.38,2270) 1(2462.38,2000) 1(2462.38,2056) 1(2462.38,2214) 1(2462.38,2270) 1(2485.48,1175.4) 1(2485.48,1201) 1(2485.48,1226.6) 1(2485.48,1252.2) 1(2485.48,1277.8) 1(2485.48,1303.4) 1(2485.48,1329) 1(2485.48,1354.6) 1(2485.48,1415.4) 1(2485.48,1441) 1(2485.48,1466.6) 1(2485.48,1492.2) 1(2485.48,1517.8) 1(2485.48,1543.4) 1(2485.48,1569) 1(2485.48,1594.6) 1(2485.48,1655.4) 1(2485.48,1681) 1(2485.48,1706.6) 1(2485.48,1732.2) 1(2485.48,1757.8) 1(2485.48,1783.4) 1(2485.48,1809) 1(2485.48,1834.6) 1(4841.48,5154.5) 1(4841.48,5210.5) 1(4841.48,5299.6) 1(4841.48,5355.6) 1(4867.08,5154.5) 1(4867.08,5210.5) 1(4867.08,5299.6) 1(4867.08,5355.6) 1(4892.68,5154.5) 1(4892.68,5210.5) 1(4892.68,5299.6) 1(4892.68,5355.6) 1(4918.28,5154.5) 1(4918.28,5210.5) 1(4918.28,5299.6) 1(4918.28,5355.6) 1(5350.28,3834.4) 1(5350.28,3890.4) 1(5350.28,4069.6) 1(5350.28,4125.6) 1(5375.88,3834.4) 1(5375.88,3890.4) 1(5375.88,4069.6) 1(5375.88,4125.6) 1(5401.48,3834.4) 1(5401.48,3890.4) 1(5401.48,4069.6) 1(5401.48,4125.6) 1(5427.08,3834.4) 1(5427.08,3890.4) 1(5427.08,4069.6) 1(5427.08,4125.6) 1(5452.68,3834.4) 1(5452.68,3890.4) 1(5452.68,4069.6) 1(5452.68,4125.6) 1(5478.28,3834.4) 1(5478.28,3890.4) 1(5478.28,4069.6) 1(5478.28,4125.6) 1(5503.88,3834.4) 1(5503.88,3890.4) 1(5503.88,4069.6) 1(5503.88,4125.6) 1(5529.48,3834.4) 1(5529.48,3890.4) 1(5529.48,4069.6) 1(5529.48,4125.6) 1(5809.28,1785.4) 1(5809.28,1811) 1(5809.28,1836.6) 1(5809.28,1862.2) 1(5809.28,1887.8) 1(5809.28,1913.4) 1(5809.28,1939) 1(5809.28,1964.6) 1(5865.28,1785.4) 1(5865.28,1811) 1(5865.28,1836.6) 1(5865.28,1862.2) 1(5865.28,1887.8) 1(5865.28,1913.4) 1(5865.28,1939) 1(5865.28,1964.6) 1(6044.48,1785.4) 1(6044.48,1811) 1(6044.48,1836.6) 1(6044.48,1862.2) 1(6044.48,1887.8) 1(6044.48,1913.4) 1(6044.48,1939) 1(6044.48,1964.6) 1(6100.48,1785.4) 1(6100.48,1811) 1(6100.48,1836.6) 1(6100.48,1862.2) 1(6100.48,1887.8) 1(6100.48,1913.4) 1(6100.48,1939) 1(6100.48,1964.6) 1(7299.68,1424.4) 1(7299.68,1480.4) 1(7299.68,1659.6) 1(7299.68,1715.6) 1(7325.28,1424.4) 1(7325.28,1480.4) 1(7325.28,1659.6) 1(7325.28,1715.6) 1(7350.88,1424.4) 1(7350.88,1480.4) 1(7350.88,1659.6) 1(7350.88,1715.6) 1(7376.48,1424.4) 1(7376.48,1480.4) 1(7376.48,1659.6) 1(7376.48,1715.6) 1(7402.08,1424.4) 1(7402.08,1480.4) 1(7402.08,1659.6) 1(7402.08,1715.6) 1(7427.68,1424.4) 1(7427.68,1480.4) 1(7427.68,1659.6) 1(7427.68,1715.6) 1(7453.28,1424.4) 1(7453.28,1480.4) 1(7453.28,1659.6) 1(7453.28,1715.6) 1(7478.88,1424.4) 1(7478.88,1480.4) 1(7478.88,1659.6) 1(7478.88,1715.6) 1(7504.48,1424.4) 1(7504.48,1480.4) 1(7504.48,1659.6) 1(7504.48,1715.6) 1(7530.08,1424.4) 1(7530.08,1480.4) 1(7530.08,1659.6) 1(7530.08,1715.6)
  round 16 on Mech16: 1(1939.88,3585) 1(1944.88,3585) 1(2874.88,5730) 1(2879.88,5730) 1(3254.88,2725) 1(3259.88,2725) 1(4524.88,6115) 1(4529.88,6115) 1(4714.88,5540) 1(4719.88,5540) 1(6314.88,3970) 1(6314.88,3975)
  round 26 on Mech16: 1(1944.88,3585) 1(2874.88,5730) 1(3254.88,2725) 1(3259.88,2725) 1(4529.88,6115) 1(4719.88,5540) 1(6314.88,3975)
  round 12 on Mech16: 1(2024.18,2558) 1(2024.18,2626) 1(2024.18,2844) 1(2024.18,2912) 1(2024.18,3278) 1(2024.18,3346) 1(2024.18,3564) 1(2024.18,3632) 1(2024.18,3943) 1(2024.18,4011) 1(2024.18,4229) 1(2024.18,4297) 1(2043.88,2558) 1(2043.88,2626) 1(2043.88,2844) 1(2043.88,2912) 1(2043.88,3278) 1(2043.88,3346) 1(2043.88,3564) 1(2043.88,3632) 1(2043.88,3943) 1(2043.88,4011) 1(2043.88,4229) 1(2043.88,4297) 1(2063.58,2558) 1(2063.58,2626) 1(2063.58,2844) 1(2063.58,2912) 1(2063.58,3278) 1(2063.58,3346) 1(2063.58,3564) 1(2063.58,3632) 1(2063.58,3943) 1(2063.58,4011) 1(2063.58,4229) 1(2063.58,4297) 1(2083.28,2558) 1(2083.28,2626) 1(2083.28,2844) 1(2083.28,2912) 1(2083.28,3278) 1(2083.28,3346) 1(2083.28,3564) 1(2083.28,3632) 1(2083.28,3943) 1(2083.28,4011) 1(2083.28,4229) 1(2083.28,4297) 1(2095.88,4984.3) 1(2095.88,5004) 1(2095.88,5023.7) 1(2095.88,5043.4) 1(2095.88,5063) 1(2095.88,5082.7) 1(2095.88,5102.4) 1(2095.88,5122.1) 1(2095.88,5141.8) 1(2095.88,5161.4) 1(2095.88,5181.1) 1(2095.88,5200.8) 1(2095.88,5220.5) 1(2095.88,5240.2) 1(2095.88,5259.8) 1(2095.88,5279.5) 1(2095.88,5299.2) 1(2095.88,5318.9) 1(2095.88,5338.6) 1(2095.88,5358.2) 1(2095.88,5377.9) 1(2095.88,5397.6) 1(2095.88,5417.3) 1(2095.88,5437) 1(2095.88,5456.6) 1(2095.88,5476.3) 1(2095.88,5496) 1(2095.88,5515.7) 1(2102.88,2558) 1(2102.88,2626) 1(2102.88,2844) 1(2102.88,2912) 1(2102.88,3278) 1(2102.88,3346) 1(2102.88,3564) 1(2102.88,3632) 1(2102.88,3943) 1(2102.88,4011) 1(2102.88,4229) 1(2102.88,4297) 1(2122.58,2558) 1(2122.58,2626) 1(2122.58,2844) 1(2122.58,2912) 1(2122.58,3278) 1(2122.58,3346) 1(2122.58,3564) 1(2122.58,3632) 1(2122.58,3943) 1(2122.58,4011) 1(2122.58,4229) 1(2122.58,4297) 1(2142.28,2558) 1(2142.28,2626) 1(2142.28,2844) 1(2142.28,2912) 1(2142.28,3278) 1(2142.28,3346) 1(2142.28,3564) 1(2142.28,3632) 1(2142.28,3943) 1(2142.28,4011) 1(2142.28,4229) 1(2142.28,4297) 1(2158.88,4984.3) 1(2158.88,5004) 1(2158.88,5023.7) 1(2158.88,5043.4) 1(2158.88,5063) 1(2158.88,5082.7) 1(2158.88,5102.4) 1(2158.88,5122.1) 1(2158.88,5141.8) 1(2158.88,5161.4) 1(2158.88,5181.1) 1(2158.88,5200.8) 1(2158.88,5220.5) 1(2158.88,5240.2) 1(2158.88,5259.8) 1(2158.88,5279.5) 1(2158.88,5299.2) 1(2158.88,5318.9) 1(2158.88,5338.6) 1(2158.88,5358.2) 1(2158.88,5377.9) 1(2158.88,5397.6) 1(2158.88,5417.3) 1(2158.88,5437) 1(2158.88,5456.6) 1(2158.88,5476.3) 1(2158.88,5496) 1(2158.88,5515.7) 1(2161.98,2558) 1(2161.98,2626) 1(2161.98,2844) 1(2161.98,2912) 1(2161.98,3278) 1(2161.98,3346) 1(2161.98,3564) 1(2161.98,3632) 1(2161.98,3943) 1(2161.98,4011) 1(2161.98,4229) 1(2161.98,4297) 1(2181.68,2558) 1(2181.68,2626) 1(2181.68,2844) 1(2181.68,2912) 1(2181.68,3278) 1(2181.68,3346) 1(2181.68,3564) 1(2181.68,3632) 1(2181.68,3943) 1(2181.68,4011) 1(2181.68,4229) 1(2181.68,4297) 1(2201.28,2558) 1(2201.28,2626) 1(2201.28,2844) 1(2201.28,2912) 1(2201.28,3278) 1(2201.28,3346) 1(2201.28,3564) 1(2201.28,3632) 1(2201.28,3943) 1(2201.28,4011) 1(2201.28,4229) 1(2201.28,4297) 1(2220.98,2558) 1(2220.98,2626) 1(2220.98,2844) 1(2220.98,2912) 1(2220.98,3278) 1(2220.98,3346) 1(2220.98,3564) 1(2220.98,3632) 1(2220.98,3943) 1(2220.98,4011) 1(2220.98,4229) 1(2220.98,4297) 1(2240.68,2558) 1(2240.68,2626) 1(2240.68,2844) 1(2240.68,2912) 1(2240.68,3278) 1(2240.68,3346) 1(2240.68,3564) 1(2240.68,3632) 1(2240.68,3943) 1(2240.68,4011) 1(2240.68,4229) 1(2240.68,4297) 1(2260.38,2558) 1(2260.38,2626) 1(2260.38,2844) 1(2260.38,2912) 1(2260.38,3278) 1(2260.38,3346) 1(2260.38,3564) 1(2260.38,3632) 1(2260.38,3943) 1(2260.38,4011) 1(2260.38,4229) 1(2260.38,4297) 1(2280.08,2558) 1(2280.08,2626) 1(2280.08,2844) 1(2280.08,2912) 1(2280.08,3278) 1(2280.08,3346) 1(2280.08,3564) 1(2280.08,3632) 1(2280.08,3943) 1(2280.08,4011) 1(2280.08,4229) 1(2280.08,4297) 1(2299.68,2558) 1(2299.68,2626) 1(2299.68,2844) 1(2299.68,2912) 1(2299.68,3278) 1(2299.68,3346) 1(2299.68,3564) 1(2299.68,3632) 1(2299.68,3943) 1(2299.68,4011) 1(2299.68,4229) 1(2299.68,4297) 1(2319.38,2558) 1(2319.38,2626) 1(2319.38,2844) 1(2319.38,2912) 1(2319.38,3278) 1(2319.38,3346) 1(2319.38,3564) 1(2319.38,3632) 1(2319.38,3943) 1(2319.38,4011) 1(2319.38,4229) 1(2319.38,4297) 1(2339.08,2558) 1(2339.08,2626) 1(2339.08,2844) 1(2339.08,2912) 1(2339.08,3278) 1(2339.08,3346) 1(2339.08,3564) 1(2339.08,3632) 1(2339.08,3943) 1(2339.08,4011) 1(2339.08,4229) 1(2339.08,4297) 1(2358.78,2558) 1(2358.78,2626) 1(2358.78,2844) 1(2358.78,2912) 1(2358.78,3278) 1(2358.78,3346) 1(2358.78,3564) 1(2358.78,3632) 1(2358.78,3943) 1(2358.78,4011) 1(2358.78,4229) 1(2358.78,4297) 1(2378.48,2558) 1(2378.48,2626) 1(2378.48,2844) 1(2378.48,2912) 1(2378.48,3278) 1(2378.48,3346) 1(2378.48,3564) 1(2378.48,3632) 1(2378.48,3943) 1(2378.48,4011) 1(2378.48,4229) 1(2378.48,4297) 1(2398.08,2558) 1(2398.08,2626) 1(2398.08,2844) 1(2398.08,2912) 1(2398.08,3278) 1(2398.08,3346) 1(2398.08,3564) 1(2398.08,3632) 1(2398.08,3943) 1(2398.08,4011) 1(2398.08,4229) 1(2398.08,4297) 1(2417.78,2558) 1(2417.78,2626) 1(2417.78,2844) 1(2417.78,2912) 1(2417.78,3278) 1(2417.78,3346) 1(2417.78,3564) 1(2417.78,3632) 1(2417.78,3943) 1(2417.78,4011) 1(2417.78,4229) 1(2417.78,4297) 1(2437.48,2558) 1(2437.48,2626) 1(2437.48,2844) 1(2437.48,2912) 1(2437.48,3278) 1(2437.48,3346) 1(2437.48,3564) 1(2437.48,3632) 1(2437.48,3943) 1(2437.48,4011) 1(2437.48,4229) 1(2437.48,4297) 1(2457.18,2558) 1(2457.18,2626) 1(2457.18,2844) 1(2457.18,2912) 1(2457.18,3278) 1(2457.18,3346) 1(2457.18,3564) 1(2457.18,3632) 1(2457.18,3943) 1(2457.18,4011) 1(2457.18,4229) 1(2457.18,4297) 1(2476.88,2558) 1(2476.88,2626) 1(2476.88,2844) 1(2476.88,2912) 1(2476.88,3278) 1(2476.88,3346) 1(2476.88,3564) 1(2476.88,3632) 1(2476.88,3943) 1(2476.88,4011) 1(2476.88,4229) 1(2476.88,4297) 1(2496.48,2558) 1(2496.48,2626) 1(2496.48,2844) 1(2496.48,2912) 1(2496.48,3278) 1(2496.48,3346) 1(2496.48,3564) 1(2496.48,3632) 1(2496.48,3943) 1(2496.48,4011) 1(2496.48,4229) 1(2496.48,4297) 1(2516.18,2558) 1(2516.18,2626) 1(2516.18,2844) 1(2516.18,2912) 1(2516.18,3278) 1(2516.18,3346) 1(2516.18,3564) 1(2516.18,3632) 1(2516.18,3943) 1(2516.18,4011) 1(2516.18,4229) 1(2516.18,4297) 1(2535.88,2558) 1(2535.88,2626) 1(2535.88,2844) 1(2535.88,2912) 1(2535.88,3278) 1(2535.88,3346) 1(2535.88,3564) 1(2535.88,3632) 1(2535.88,3943) 1(2535.88,4011) 1(2535.88,4229) 1(2535.88,4297) 1(2555.58,2558) 1(2555.58,2626) 1(2555.58,2844) 1(2555.58,2912) 1(2555.58,3278) 1(2555.58,3346) 1(2555.58,3564) 1(2555.58,3632) 1(2555.58,3943) 1(2555.58,4011) 1(2555.58,4229) 1(2555.58,4297) 1(2870.88,4984.3) 1(2870.88,5004) 1(2870.88,5023.7) 1(2870.88,5043.4) 1(2870.88,5063) 1(2870.88,5082.7) 1(2870.88,5102.4) 1(2870.88,5122.1) 1(2870.88,5141.8) 1(2870.88,5161.4) 1(2870.88,5181.1) 1(2870.88,5200.8) 1(2870.88,5220.5) 1(2870.88,5240.2) 1(2870.88,5259.8) 1(2870.88,5279.5) 1(2870.88,5299.2) 1(2870.88,5318.9) 1(2870.88,5338.6) 1(2870.88,5358.2) 1(2870.88,5377.9) 1(2870.88,5397.6) 1(2870.88,5417.3) 1(2870.88,5437) 1(2870.88,5456.6) 1(2870.88,5476.3) 1(2870.88,5496) 1(2870.88,5515.7) 1(2933.88,4984.3) 1(2933.88,5004) 1(2933.88,5023.7) 1(2933.88,5043.4) 1(2933.88,5063) 1(2933.88,5082.7) 1(2933.88,5102.4) 1(2933.88,5122.1) 1(2933.88,5141.8) 1(2933.88,5161.4) 1(2933.88,5181.1) 1(2933.88,5200.8) 1(2933.88,5220.5) 1(2933.88,5240.2) 1(2933.88,5259.8) 1(2933.88,5279.5) 1(2933.88,5299.2) 1(2933.88,5318.9) 1(2933.88,5338.6) 1(2933.88,5358.2) 1(2933.88,5377.9) 1(2933.88,5397.6) 1(2933.88,5417.3) 1(2933.88,5437) 1(2933.88,5456.6) 1(2933.88,5476.3) 1(2933.88,5496) 1(2933.88,5515.7) 1(3149.18,3268) 1(3149.18,3336) 1(3149.18,3554) 1(3149.18,3622) 1(3168.88,3268) 1(3168.88,3336) 1(3168.88,3554) 1(3168.88,3622) 1(3188.58,3268) 1(3188.58,3336) 1(3188.58,3554) 1(3188.58,3622) 1(3208.28,3268) 1(3208.28,3336) 1(3208.28,3554) 1(3208.28,3622) 1(3227.88,3268) 1(3227.88,3336) 1(3227.88,3554) 1(3227.88,3622) 1(3247.58,3268) 1(3247.58,3336) 1(3247.58,3554) 1(3247.58,3622) 1(3267.28,3268) 1(3267.28,3336) 1(3267.28,3554) 1(3267.28,3622) 1(3286.98,3268) 1(3286.98,3336) 1(3286.98,3554) 1(3286.98,3622) 1(3306.68,3268) 1(3306.68,3336) 1(3306.68,3554) 1(3306.68,3622) 1(3326.28,3268) 1(3326.28,3336) 1(3326.28,3554) 1(3326.28,3622) 1(3345.98,3268) 1(3345.98,3336) 1(3345.98,3554) 1(3345.98,3622) 1(3365.68,3268) 1(3365.68,3336) 1(3365.68,3554) 1(3365.68,3622) 1(3385.38,3268) 1(3385.38,3336) 1(3385.38,3554) 1(3385.38,3622) 1(3405.08,3268) 1(3405.08,3336) 1(3405.08,3554) 1(3405.08,3622) 1(3424.68,3268) 1(3424.68,3336) 1(3424.68,3554) 1(3424.68,3622) 1(3444.38,3268) 1(3444.38,3336) 1(3444.38,3554) 1(3444.38,3622) 1(3464.08,3268) 1(3464.08,3336) 1(3464.08,3554) 1(3464.08,3622) 1(3483.78,3268) 1(3483.78,3336) 1(3483.78,3554) 1(3483.78,3622) 1(3503.48,3268) 1(3503.48,3336) 1(3503.48,3554) 1(3503.48,3622) 1(3523.08,3268) 1(3523.08,3336) 1(3523.08,3554) 1(3523.08,3622) 1(3542.78,3268) 1(3542.78,3336) 1(3542.78,3554) 1(3542.78,3622) 1(3562.48,3268) 1(3562.48,3336) 1(3562.48,3554) 1(3562.48,3622) 1(3582.18,3268) 1(3582.18,3336) 1(3582.18,3554) 1(3582.18,3622) 1(3584.88,4622.4) 1(3584.88,4642.08) 1(3584.88,4661.76) 1(3584.88,4681.44) 1(3584.88,4701.12) 1(3584.88,4720.8) 1(3584.88,4740.48) 1(3584.88,4760.16) 1(3584.88,4779.84) 1(3584.88,4799.52) 1(3584.88,4819.2) 1(3584.88,4838.88) 1(3584.88,4858.56) 1(3584.88,4878.24) 1(3584.88,4897.92) 1(3584.88,4917.6) 1(3601.88,3268) 1(3601.88,3336) 1(3601.88,3554) 1(3601.88,3622) 1(3621.48,3268) 1(3621.48,3336) 1(3621.48,3554) 1(3621.48,3622) 1(3641.18,3268) 1(3641.18,3336) 1(3641.18,3554) 1(3641.18,3622) 1(3642.88,4622.4) 1(3642.88,4642.08) 1(3642.88,4661.76) 1(3642.88,4681.44) 1(3642.88,4701.12) 1(3642.88,4720.8) 1(3642.88,4740.48) 1(3642.88,4760.16) 1(3642.88,4779.84) 1(3642.88,4799.52) 1(3642.88,4819.2) 1(3642.88,4838.88) 1(3642.88,4858.56) 1(3642.88,4878.24) 1(3642.88,4897.92) 1(3642.88,4917.6) 1(3660.88,3268) 1(3660.88,3336) 1(3660.88,3554) 1(3660.88,3622) 1(3680.58,3268) 1(3680.58,3336) 1(3680.58,3554) 1(3680.58,3622) 1(3692.28,4515) 1(3692.28,4573) 1(3692.28,4967) 1(3692.28,5025) 1(3711.96,4515) 1(3711.96,4573) 1(3711.96,4967) 1(3711.96,5025) 1(3731.64,4515) 1(3731.64,4573) 1(3731.64,4967) 1(3731.64,5025) 1(3751.32,4515) 1(3751.32,4573) 1(3751.32,4967) 1(3751.32,5025) 1(3771,4515) 1(3771,4573) 1(3771,4967) 1(3771,5025) 1(3790.68,4515) 1(3790.68,4573) 1(3790.68,4967) 1(3790.68,5025) 1(3799.18,3268) 1(3799.18,3336) 1(3799.18,3554) 1(3799.18,3622) 1(3810.36,4515) 1(3810.36,4573) 1(3810.36,4967) 1(3810.36,5025) 1(3818.88,3268) 1(3818.88,3336) 1(3818.88,3554) 1(3818.88,3622) 1(3830.04,4515) 1(3830.04,4573) 1(3830.04,4967) 1(3830.04,5025) 1(3834.88,5422.4) 1(3834.88,5442.08) 1(3834.88,5461.76) 1(3834.88,5481.44) 1(3834.88,5501.12) 1(3834.88,5520.8) 1(3834.88,5540.48) 1(3834.88,5560.16) 1(3834.88,5579.84) 1(3834.88,5599.52) 1(3834.88,5619.2) 1(3834.88,5638.88) 1(3834.88,5658.56) 1(3834.88,5678.24) 1(3834.88,5697.92) 1(3834.88,5717.6) 1(3838.58,3268) 1(3838.58,3336) 1(3838.58,3554) 1(3838.58,3622) 1(3849.72,4515) 1(3849.72,4573) 1(3849.72,4967) 1(3849.72,5025) 1(3858.28,3268) 1(3858.28,3336) 1(3858.28,3554) 1(3858.28,3622) 1(3869.4,4515) 1(3869.4,4573) 1(3869.4,4967) 1(3869.4,5025) 1(3877.88,3268) 1(3877.88,3336) 1(3877.88,3554) 1(3877.88,3622) 1(3889.08,4515) 1(3889.08,4573) 1(3889.08,4967) 1(3889.08,5025) 1(3892.88,5422.4) 1(3892.88,5442.08) 1(3892.88,5461.76) 1(3892.88,5481.44) 1(3892.88,5501.12) 1(3892.88,5520.8) 1(3892.88,5540.48) 1(3892.88,5560.16) 1(3892.88,5579.84) 1(3892.88,5599.52) 1(3892.88,5619.2) 1(3892.88,5638.88) 1(3892.88,5658.56) 1(3892.88,5678.24) 1(3892.88,5697.92) 1(3892.88,5717.6) 1(3897.58,3268) 1(3897.58,3336) 1(3897.58,3554) 1(3897.58,3622) 1(3908.76,4515) 1(3908.76,4573) 1(3908.76,4967) 1(3908.76,5025) 1(3917.28,3268) 1(3917.28,3336) 1(3917.28,3554) 1(3917.28,3622) 1(3928.44,4515) 1(3928.44,4573) 1(3928.44,4967) 1(3928.44,5025) 1(3936.98,3268) 1(3936.98,3336) 1(3936.98,3554) 1(3936.98,3622) 1(3942.28,5315) 1(3942.28,5373) 1(3942.28,5767) 1(3942.28,5825) 1(3948.12,4515) 1(3948.12,4573) 1(3948.12,4967) 1(3948.12,5025) 1(3956.68,3268) 1(3956.68,3336) 1(3956.68,3554) 1(3956.68,3622) 1(3961.96,5315) 1(3961.96,5373) 1(3961.96,5767) 1(3961.96,5825) 1(3967.8,4515) 1(3967.8,4573) 1(3967.8,4967) 1(3967.8,5025) 1(3976.28,3268) 1(3976.28,3336) 1(3976.28,3554) 1(3976.28,3622) 1(3981.64,5315) 1(3981.64,5373) 1(3981.64,5767) 1(3981.64,5825) 1(3987.48,4515) 1(3987.48,4573) 1(3987.48,4967) 1(3987.48,5025) 1(3995.98,3268) 1(3995.98,3336) 1(3995.98,3554) 1(3995.98,3622) 1(4001.32,5315) 1(4001.32,5373) 1(4001.32,5767) 1(4001.32,5825) 1(4015.68,3268) 1(4015.68,3336) 1(4015.68,3554) 1(4015.68,3622) 1(4021,5315) 1(4021,5373) 1(4021,5767) 1(4021,5825) 1(4035.38,3268) 1(4035.38,3336) 1(4035.38,3554) 1(4035.38,3622) 1(4036.88,4622.4) 1(4036.88,4642.08) 1(4036.88,4661.76) 1(4036.88,4681.44) 1(4036.88,4701.12) 1(4036.88,4720.8) 1(4036.88,4740.48) 1(4036.88,4760.16) 1(4036.88,4779.84) 1(4036.88,4799.52) 1(4036.88,4819.2) 1(4036.88,4838.88) 1(4036.88,4858.56) 1(4036.88,4878.24) 1(4036.88,4897.92) 1(4036.88,4917.6) 1(4040.68,5315) 1(4040.68,5373) 1(4040.68,5767) 1(4040.68,5825) 1(4055.08,3268) 1(4055.08,3336) 1(4055.08,3554) 1(4055.08,3622) 1(4060.36,5315) 1(4060.36,5373) 1(4060.36,5767) 1(4060.36,5825) 1(4074.68,3268) 1(4074.68,3336) 1(4074.68,3554) 1(4074.68,3622) 1(4080.04,5315) 1(4080.04,5373) 1(4080.04,5767) 1(4080.04,5825) 1(4094.38,3268) 1(4094.38,3336) 1(4094.38,3554) 1(4094.38,3622) 1(4094.88,4622.4) 1(4094.88,4642.08) 1(4094.88,4661.76) 1(4094.88,4681.44) 1(4094.88,4701.12) 1(4094.88,4720.8) 1(4094.88,4740.48) 1(4094.88,4760.16) 1(4094.88,4779.84) 1(4094.88,4799.52) 1(4094.88,4819.2) 1(4094.88,4838.88) 1(4094.88,4858.56) 1(4094.88,4878.24) 1(4094.88,4897.92) 1(4094.88,4917.6) 1(4099.72,5315) 1(4099.72,5373) 1(4099.72,5767) 1(4099.72,5825) 1(4114.08,3268) 1(4114.08,3336) 1(4114.08,3554) 1(4114.08,3622) 1(4119.4,5315) 1(4119.4,5373) 1(4119.4,5767) 1(4119.4,5825) 1(4133.78,3268) 1(4133.78,3336) 1(4133.78,3554) 1(4133.78,3622) 1(4139.08,5315) 1(4139.08,5373) 1(4139.08,5767) 1(4139.08,5825) 1(4153.48,3268) 1(4153.48,3336) 1(4153.48,3554) 1(4153.48,3622) 1(4158.76,5315) 1(4158.76,5373) 1(4158.76,5767) 1(4158.76,5825) 1(4173.08,3268) 1(4173.08,3336) 1(4173.08,3554) 1(4173.08,3622) 1(4178.44,5315) 1(4178.44,5373) 1(4178.44,5767) 1(4178.44,5825) 1(4192.78,3268) 1(4192.78,3336) 1(4192.78,3554) 1(4192.78,3622) 1(4198.12,5315) 1(4198.12,5373) 1(4198.12,5767) 1(4198.12,5825) 1(4212.48,3268) 1(4212.48,3336) 1(4212.48,3554) 1(4212.48,3622) 1(4217.8,5315) 1(4217.8,5373) 1(4217.8,5767) 1(4217.8,5825) 1(4232.18,3268) 1(4232.18,3336) 1(4232.18,3554) 1(4232.18,3622) 1(4237.48,5315) 1(4237.48,5373) 1(4237.48,5767) 1(4237.48,5825) 1(4251.88,3268) 1(4251.88,3336) 1(4251.88,3554) 1(4251.88,3622) 1(4271.48,3268) 1(4271.48,3336) 1(4271.48,3554) 1(4271.48,3622) 1(4286.88,5422.4) 1(4286.88,5442.08) 1(4286.88,5461.76) 1(4286.88,5481.44) 1(4286.88,5501.12) 1(4286.88,5520.8) 1(4286.88,5540.48) 1(4286.88,5560.16) 1(4286.88,5579.84) 1(4286.88,5599.52) 1(4286.88,5619.2) 1(4286.88,5638.88) 1(4286.88,5658.56) 1(4286.88,5678.24) 1(4286.88,5697.92) 1(4286.88,5717.6) 1(4291.18,3268) 1(4291.18,3336) 1(4291.18,3554) 1(4291.18,3622) 1(4310.88,3268) 1(4310.88,3336) 1(4310.88,3554) 1(4310.88,3622) 1(4330.58,3268) 1(4330.58,3336) 1(4330.58,3554) 1(4330.58,3622) 1(4344.88,5422.4) 1(4344.88,5442.08) 1(4344.88,5461.76) 1(4344.88,5481.44) 1(4344.88,5501.12) 1(4344.88,5520.8) 1(4344.88,5540.48) 1(4344.88,5560.16) 1(4344.88,5579.84) 1(4344.88,5599.52) 1(4344.88,5619.2) 1(4344.88,5638.88) 1(4344.88,5658.56) 1(4344.88,5678.24) 1(4344.88,5697.92) 1(4344.88,5717.6)
  round 36 on Mech16: 1(3259.88,2725)
  round 20 on Mech16: 1(4474.88,6450) 1(7539.88,3170)
  round 42 on Mech16: 1(5531.52,3345) 1(5531.52,3395) 1(5531.52,3495) 1(5531.52,3545) 1(5549.52,3345) 1(5549.52,3395) 1(5549.52,3495) 1(5549.52,3545) 1(5590.88,3295) 1(5590.88,3445) 1(5590.88,3595) 1(5608.88,3295) 1(5608.88,3445) 1(5608.88,3595)

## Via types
v1: diameter 20, hole 10, Layer 1 - Top Layer to Layer 6 - Bottom Layer, tented both sides, 491 vias
v2: diameter 20, hole 10, Layer 1 - Top Layer to Layer 6 - Bottom Layer, 310 vias
v3: diameter 19.68, hole 7.87, Layer 1 - Top Layer to Layer 6 - Bottom Layer, 282 vias
v4: diameter 19.68, hole 7.87, Layer 1 - Top Layer to Layer 6 - Bottom Layer, tented both sides, 211 vias
v5: diameter 50, hole 28, Layer 1 - Top Layer to Layer 6 - Bottom Layer, 101 vias
v6: diameter 30, hole 15, Layer 1 - Top Layer to Layer 6 - Bottom Layer, 73 vias
v7: diameter 22, hole 10, Layer 1 - Top Layer to Layer 6 - Bottom Layer, 36 vias
v8: diameter 30, hole 10, Layer 1 - Top Layer to Layer 6 - Bottom Layer, 14 vias
v9: diameter 19.68, hole 7.87, Layer 1 - Top Layer to Layer 6 - Bottom Layer, tented bottom, 4 vias
v10: diameter 30, hole 10, Layer 1 - Top Layer to Layer 6 - Bottom Layer, tented both sides, 2 vias
v11: diameter 40, hole 10, Layer 1 - Top Layer to Layer 6 - Bottom Layer, 1 vias
v12: diameter 23.62, hole 7.87, Layer 1 - Top Layer to Layer 6 - Bottom Layer, tented both sides, 1 vias
v13: diameter 23.62, hole 7.87, Layer 1 - Top Layer to Layer 6 - Bottom Layer, 1 vias

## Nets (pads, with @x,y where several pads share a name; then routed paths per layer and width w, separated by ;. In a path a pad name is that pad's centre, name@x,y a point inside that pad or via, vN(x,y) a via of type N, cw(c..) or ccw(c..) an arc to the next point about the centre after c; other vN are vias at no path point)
1V1: C1.1 C7.1 C13.1 C62.1 C68.1 C74.1 J20.2 L1.1 L2.1 L3.1 L11.1 L12.1 L13.1 R215.2 TP50.1 | length 15185.5
  Layer 1 - Top Layer w25: L12.1@2667.5,3916 2701,3916 C68.1@2745,3960
  Layer 1 - Top Layer w30: L11.1@2402,3741.5 2402,3705 C62.1@2438,3669 C62.1@2419.41,3669 ; L2.1@2999.56,1909.36 2999.56,1943.87 C7.1@2962.56,1980.87 2982.56,2000.87 v2(3052.56,2000.87)
  Layer 1 - Top Layer w40: C62.1@2419.41,3669 2365,3614.59 2365,3545 2435,3475 v2(2685,3475) v2(2720,3475) ; L1.1@3141.05,1648.87 3173.56,1648.87 C1.1@3211.56,1686.87
  Layer 1 - Top Layer w50: v2(2720,3475) 2830,3585 2830,3935 2805,3960 C68.1@2745,3960
  Layer 1 - Top Layer w60: C1.1@3211.56,1686.87 3211.56,1641.87 3247.56,1605.87 3377.56,1605.87 3433.78,1662.09 v2(3433.78,1682.09)
  Layer 3 - PWR w100: v6(5200.79,2385.83) 5189.17,2385.83 5035,2540 5035,3445 5285,3695 v5(5510,3695) v5(5740,3925) v5(6050,3925) 6110,3925 6125,3940 TP50.1@6125,4150 6335,4150 J20.2@6355,4170
  Layer 4 - Signal w60: v8(1965,4210) 1850,4095 1850,3510 2210,3150 2620,3150 2720,3250 v2(2720,3475) ; v2(2532.56,1275.87) 2897.56,1275.87 2992.56,1180.87 3350.16,1180.87 v4@3436.02,1266.73
  Layer 4 - Signal w100: v2(2720,3475) 3450,3475 3670,3695 v5(5510,3695) v5(5740,3925) v5(6050,3925) 6110,3925 6125,3940 TP50.1@6125,4150 6335,4150 J20.2@6355,4170
  Layer 6 - Bottom Layer w30: v2(2532.56,1275.87) C13.1@2602.56,1275.87 ; C13.1@2607.56,1280.87 L3.1@2691.06,1280.87
  Layer 6 - Bottom Layer w60: v8@1965,4205 v8(1965,4210) ; C74.1@1980,4266 1980,4232.5 1983.75,4228.75 ; 1986.25,4226.25 L13.1@2016.5,4196 ; v2(3052.56,2000.87) 3362.56,2000.87 3433.78,1929.65 v2(3433.78,1682.09) 3428.15,1676.46 3436.02,1668.58 v4(3436.02,1263.78)
  Layer 6 - Bottom Layer w80: 3362.56,2000.87 3747.71,2386.02 3747.91,2385.83 v6(5200.79,2385.83)
  other v2: 2745,3505
1V8: C21.1 C27.1 C36.1 C42.1 C47.1 C52.1 C80.1 C87.1 C96.1 C103.1 C108.1 C113.1 D6.1 J19.2 L4.1 L5.1 L6.1 L7.1 L8.1 L9.1 L14.1 L15.1 L16.1 L17.1 L18.1 L19.1 R21.2 R23.2 R24.2 R34.2 R36.2 R37.2 R214.2 TP48.1 | length 4933.8
  Layer 1 - Top Layer w10: R21.2@2016.18,1442.68 ccw(c2016.18,1444.05) R21.2@2017.56,1444.05 ; R36.2@2572.44,5417.12 2574.93,5419.62 2576.16,5420.85 v5(2576.16,5490.89)
  Layer 1 - Top Layer w20: R23.2@1366,1317.49 R24.2@1416,1317.49 1416,1385.87 1464.13,1434 1644,1434 1735,1525 1971.45,1525 v4(2017.56,1478.9) R21.2@2017.56,1444.05 ; L15.1@1992.85,3882.7 1992.85,3872.15 2052,3813 C87.1@2052,3804 ; R34.2@1996.76,4731.38 1996.76,4553.24 v2(2117,4433) ; R37.2@2574.93,5374.2 R36.2@2574.93,5419.62 ; L4.1@2617.56,1917.36 2672.56,1972.36 C21.1@2672.56,2000.87 ; D6.1@5620.63,4220 5620.63,4199.37 5650,4170 J19.2@5775,4170
  Layer 1 - Top Layer w25: L5.1@3084.05,1315.87 3142.56,1315.87 3151.05,1324.36 L8.1@3151.05,1378.87 ; L9.1@3151.05,1542.87 3184.56,1542.87 C52.1@3222.56,1504.87 C47.1@3222.56,1416.87 3222.56,1400.87 3277.56,1345.87 v2(3307.56,1345.87)
  Layer 1 - Top Layer w30: L6.1@2519.06,1388.87 2491.06,1360.87 v2(2447.56,1360.87) C42.1@2447.56,1425.87 C36.1@2447.56,1515.87 v2(2447.56,1575.87) 2496.06,1575.87 L7.1@2519.06,1552.87 ; C21.1@2672.56,2000.87 v2(2672.56,2065.87) ; L8.1@3151.05,1378.87 3184.56,1378.87 C47.1@3222.56,1416.87
  Layer 1 - Top Layer w35: v2(2117,4433) C96.1@2183,4433 C103.1@2272,4433 2310,4395 L17.1@2310,4361.5 ; L18.1@2127,3740.5 2092.5,3706 v2(2078,3706) 2115,3669 C113.1@2164,3669 C108.1@2254,3669 2290,3705 L19.1@2290,3740.5 ; L16.1@2145,4361.5 2145,4428.55 ; v5(2576.16,5490.89) 2715.51,5490.89 2757.24,5449.16 ; L14.1@2667.5,4260 2702,4260 C80.1@2739,4223 2739,4239 2760,4260 v2(2760,4295) 2760,5449.16
  Layer 1 - Top Layer w40: C87.1@2052,3804 2052,3732 v2(2078,3706)
3V3: C57.1 C118.1 C123.1 C125.1 C126.1 C128.1 C129.1 C296.1 C297.1 C298.1 C299.1 C300.1 C301.1 C302.1 C303.1 C304.1 C305.1 C306.1 C307.1 C308.1 C309.1 C310.1 C311.1 C312.1 D5.1 D7.2 J7.1 J8.1 J9.1 J11.1 J18.2 L10.1 L20.1 L78.2 R26.2 R39.2 R52.2 R53.2 R54.2 R55.2 R56.2 R57.2 R66.2 R67.2 R68.2 R69.1 R71.2 R72.2 R149.2 R150.2 R151.2 R186.2 R201.2 R229.2 R230.1 R233.1 R234.2 R238.2 R239.2 R244.2 R245.2 TP49.1 U3.2 U3.16 U4.10 U5.10 U6.10 U23.4 U24.4 U25.4 U26.4 U27.8 | length 11152.8
  Layer 1 - Top Layer w10: v4@1980.26,3139.93 1980.26,3134.07 R39.2@2004.11,3110.22 ; v8(3211.56,1874.87) 3356.96,1874.87 3590.46,1641.37 3590.46,1451.93 R26.2@3594.8,1447.59 ; R238.2@5170.85,3170 5209,3170 v2(5235,3144) ; U4.10@6000.98,2708.29 v4(6000.98,2730) C123.1@6000.98,2760.06 ; v3(6510,4040) 6540.26,4040 D7.2@6590.03,4089.76
  Layer 1 - Top Layer w15: v4(5813.62,3671.38) C125.1@5813.62,3635 5828.9,3619.72 U3.2@5885.39,3619.72 ; v3(5830,3260) 5831.46,3261.46 U3.16@5885.39,3261.46 ; v4(6150,2270) 6191.87,2270 ; D5.1@6162.28,5674.76 6162.28,5712.28 6190,5740 J18.2@6330,5740 ; R72.2@6191.87,2238.7 6191.87,2270 ; R71.2@6191.87,2303.7 6191.87,2270 ; v3(6256.19,1914.14) C128.1@6309.69,1914.14 6332.69,1891.14 U5.10@6332.69,1852.07 ; R53.2@6465,3768.62 6468.62,3768.62 v3(6500,3800) ; R52.2@6465,4013.62 6483.62,4013.62 v3(6510,4040) ; v3(6516.5,3258.5) R66.2@6565,3258.5
  Layer 1 - Top Layer w16: v3(6277.82,2367.18) 6277.87,2367.13 C129.1@6316,2367.13 6316.51,2366.62 6350,2366.62 U6.10@6350,2305.43
  Layer 1 - Top Layer w20: C126.1@5768.62,3260 v3(5830,3260) ; R56.2@5914.6,2672.86 R57.2@5914.6,2622.86 5957.46,2580 v3(5970,2580) ; v4(6144.69,1833.33) 6147.69,1836.33 R67.2@6188.07,1836.33 R68.2@6188.07,1785.33 ; R69.1@6379.69,1977.13 v2(6379.69,2018.33)
  Layer 1 - Top Layer w25: R150.2@5546.38,2303 R151.2@5546.38,2359 v6(5546.38,2398.62) ; R149.2@5547.38,2247 R150.2@5547.38,2302 ; U27.8@5932.12,2353.62 C312.1@6035,2353.62 v6(6081.38,2353.62)
  Layer 1 - Top Layer w30: C118.1@2527,3669 2564,3706 L20.1@2564,3741.5 ; L10.1@3141.05,1812.87 3173.56,1812.87 C57.1@3211.56,1774.87 ; R55.2@6139.6,2656.06 6139.6,2680.16 ; R54.2@6139.6,2704.25 6139.6,2680.16 ; v3(6185,2685) 6144.44,2685 6139.6,2680.16
  Layer 1 - Top Layer w50: C118.1@2527,3669 2601,3669 v8(2625,3645)
  Layer 1 - Top Layer w60: C57.1@3211.56,1774.87 v8(3211.56,1874.87)
  Layer 4 - Signal w10: v2@1044.55,3375 1161.66,3257.89 1492.5,3257.89 1511.82,3238.57 1890.48,3238.57 v4(1979.34,3149.7) ; v2@2615.15,2217.42 v2(2615.15,2222.82)
  Layer 4 - Signal w20: v2@2615.15,2217.42 2630.01,2202.56
  Layer 4 - Signal w50: v2@1056.12,4607.94 1311.59,4863.41 1364.19,4916 1789.75,4916 2355.73,4916 2809.25,4462.48 2809.25,3769.25 2685,3645 v8(2625,3645)
  Layer 4 - Signal w60: v8(1870,1585) 2115,1830 2285,1830 2635,2180 3015,2180 3211.56,1983.44 v8(3211.56,1874.87)
  Layer 6 - Bottom Layer w10: v4(596.06,4796.06) R234.2@653.94,4796.06 ; v2(601,3554) R239.2@655.38,3554 ; v2(608,2312) R244.2@655.38,2312 ; U23.4@742.96,5878 769.63,5878 ; U24.4@743.9,4636.06 773.94,4636.06 ; U26.4@743.96,2152 770.93,2152 ; U25.4@743.96,3394 780.93,3394 ; v3@5823.7,3254.09 5830.42,3260.81 5940.31,3260.81 R245.2@6035.44,3355.93 ; R186.2@6484.12,3297.65 6484.12,3291.51 v3@6517.01,3258.63
  Layer 6 - Bottom Layer w20: 769.63,5878 C299.1@786,5861.62 ; 770.93,2152 C311.1@789,2133.93 C310.1@844,2133.93 C309.1@899,2133.93 1043.93,2133.93 v2(1045,2135) ; 773.94,4636.06 C303.1@795,4615 C302.1@850,4615 C301.1@905,4615 C300.1@971.38,4615 ; 780.93,3394 C307.1@794,3380.93 C306.1@849,3380.93 C305.1@904,3380.93 C304.1@970.38,3380.93 ; 798,5861.62 C298.1@838,5861.62 C297.1@893,5861.62 C296.1@974.38,5861.62 ; C304.1@979,3372.31 v2(1047.31,3372.31) ; C300.1@980,4606.38 v2(1053.62,4606.38) ; C296.1@983,5853 v8(1053,5853) ; L78.2@2436.06,2223.47 v2@2615.37,2223.47 ; R230.1@4854.19,3055 R233.1@4854.19,3121.69 5212.69,3121.69 v2(5235,3144)
  Layer 6 - Bottom Layer w30: v4(590.15,6040.15) R229.2@653.32,6040.15
  other v5: 1789.75,4913.48
5V: C138.1 C139.1 C140.1 C141.1 D10.1 J17.1 J21.2 J22.1 J27.1 R73.2 R75.2 R76.2 R200.1 R253.2 Rsense1.1 TP46.1 | length 3271.8
  Layer 1 - Top Layer w10: Rsense1.1@5060.51,4345.51 Rsense1.1@5100,4345.51 v2(5204.49,4345.51) ; 5540,5950 5555,5965 D10.1@5632.28,5965
  Layer 3 - PWR w40: v8(3400,4355) 3400,4310 3515,4195 3890,4195
  Layer 4 - Signal w20: v4(3460,4350) 3535,4350 3615,4270 4070,4270 4305,4035 4730,4035 5040.51,4345.51 v2(5204.49,4345.51)
  Layer 6 - Bottom Layer w20: v4(3460,4350) 3498.84,4388.84 R73.2@3498.84,4447.24
  Layer 6 - Bottom Layer w25: 3300,4360 R76.2@3300,4471.38
  Layer 6 - Bottom Layer w40: 3305,4355 v8(3400,4355) 3433.84,4388.84 R75.2@3433.84,4464.36
  other v5: 5150,4770 5280,4770 5150,4930 5280,4930 5200,5430 5335,5430 5465,5430 5200,5545 5335,5545 5465,5545
5V_OUT: C183.1 C184.1 C185.1 C186.2 C187.1 C188.1 C189.1 C190.2 J21.1 R117.2 R119.2 R120.2 R253.1 TP14.1 U10.16 | length 2581.6
  Layer 1 - Top Layer w10: v2(3398.03,6098.03) R119.2@3398.03,6058.94 3428.82,6058.94 3461.38,6026.38 3461.38,5936.38 3481.54,5916.22 U10.16@3481.54,5891.18
  Layer 1 - Top Layer w20: v2(5090,6230) R117.2@5145.55,6230
  Layer 4 - Signal w10: v2@3400,6100 3400,6420 3570,6590 4649.72,6590 5044.72,6195 5068.8,6195 5090,6216.2 v2(5090,6230)
12V: J16.2 J22.3 J27.3 R187.2 TP47.1
AGND: C176.2 C177.1 C192.2 C193.2 C194.1 C195.2 NT1.2 R110.1 R111.1 R112.1 R113.1 U10.3 | length 865.5
  Layer 1 - Top Layer w5: C195.2@3228.19,5838.03 C194.1@3278.19,5838.03
  Layer 1 - Top Layer w10: R112.1@3212.01,5891.38 R112.1@3222.76,5891.38 C195.2@3222.76,5843.47 ; v4@3481.54,5716.54 U10.3@3481.54,5741.57
  Layer 1 - Top Layer w20: 3148.62,5676.38 C193.2@3230.94,5676.38 ; 3157.38,5726.38 C192.2@3230.94,5726.38 ; 3386.38,5521.29 R110.1@3386.38,5577.76 ; 3439.57,5500.02 C176.2@3439.57,5577.76 ; 3540.95,5511.05 R113.1@3540.95,5577.76 ; 3590.95,5512.05 C177.1@3590.95,5577.76 ; 3740.95,5512.05 R111.1@3740.95,5577.76
  Layer 6 - Bottom Layer w20: v4(3419,5514) 3419,5574 3500,5655 3500,5698.07 3497.93,5698.07 v4(3481,5715)
AGND2: C150.2 C151.2 NT2.1 R79.1 R80.1 R81.1 R82.1 R83.1 U8.9 | length 216.7
  Layer 6 - Bottom Layer w15: 3173.84,4629.48 3288.84,4629.48 3310.28,4650.91 U8.9@3310.28,4687.72 3310.28,4717.29 NT2.1@3313.84,4720.86
BOOST_SW: Cbst1.1 L21.2 Q3.1 Q3.2 Q3.3 Q5.5 Q5.6 Q5.7 Q5.8 Q5.9@4365,4374.41 U8.18 | length 2032.1
  Layer 4 - Signal w30: v8(3413.84,5128.84) 4211.16,5128.84 4390,4950 4390,4905 4535,4760 4535,4385 v10(4445,4295)
  Layer 6 - Bottom Layer w20: v8(3413.84,5128.84) 3413.84,5069.36 Cbst1.1@3422.35,5060.86 3463.82,5019.39 U8.18@3463.82,4920
  other v2: 4320,4300 4375,4300 4245,4355 4275,4400
  other v3: 4326.61,4356.61 4403.39,4356.61 4365,4373.86 4326.61,4391.1 4403.39,4391.1 4365,4408.35
  other v4: 4365,4339.37
  other v6: 4365,3780 4250,3800 4250,3870 4445,3885 4250,3945 4445,4205 4265,4305
CAM_0_N: C206.2 U1.51 | length 419.5
  Layer 1 - Top Layer w3.94: C206.2@2497,1200 2497.83,1200.83 cw(c2520,1178.66) 2520,1210.01 2617.45,1209.92 ccw(c2617.45,1318.98) 2726.5,1318.98 2726.5,1438.11 2727.07,1438.11 ccw(c2727.07,1444.83) U1.51@2731.82,1440.08
CAM_0_P: C204.1 U1.50 | length 405.2
  Layer 1 - Top Layer w3.94: C204.1@2498,1230 2503.06,1224.94 ccw(c2517.45,1239.32) 2517.45,1218.98 2617.45,1218.98 ccw(c2617.45,1318.98) 2717.45,1318.98 2717.45,1438.11 2716.88,1438.11 cw(c2716.88,1444.83) U1.50@2712.13,1440.08
cam_0_se: C204.2 J23.1 L36.1 | length 1885.4
  Layer 1 - Top Layer w3.94: v2@1338,484 v2@1338,493.66
  Layer 1 - Top Layer w6.2: v2@1338,493.66 cw(c1399.18,493.66) 1355.92,536.92 1569.71,750.71 ccw(c1499,821.42) 1599,821.42 1599,1127.58 cw(c1699,1127.58) 1628.29,1198.29 1639.71,1209.71 cw(c1710.42,1139) 1710.42,1239 C204.2@2436.38,1239
  Layer 6 - Bottom Layer w10: J23.1@1332,255 1337,260 v2(1337,489) ; J23.1@1335,247 ccw(c1330.17,251.83) J23.1@1337,251.83
CAM_1_N: C207.2 U1.54 | length 473.9
  Layer 1 - Top Layer w3.94: C207.2@2642,1067 cw(c2667.68,1041.32) 2667.68,1077.64 2698.97,1077.64 ccw(c2698.97,1164.24) 2785.57,1164.24 2785.57,1434.76 U1.54@2790.89,1440.08
CAM_1_P: C205.1 U1.53 | length 468.5
  Layer 1 - Top Layer w3.94: C205.1@2635,1104 ccw(c2676.78,1145.78) 2676.78,1086.69 2698.97,1086.69 ccw(c2698.97,1164.24) 2776.52,1164.24 2776.52,1434.76 U1.53@2771.2,1440.08
cam_1_se: C205.2 J24.1 L37.1 | length 1047.2
  Layer 1 - Top Layer w6.2: v2@2337,490 2337,995.58 cw(c2437,995.58) 2366.29,1066.29 2377.71,1077.71 cw(c2448.42,1007) 2448.42,1107 C205.2@2582.38,1107
  Layer 6 - Bottom Layer w10: J24.1@2337,254 2338,255 v2(2338,488)
CAM_2_N: C226.2 U1.60 | length 773.2
  Layer 1 - Top Layer w3.94: U1.60@2909.03,1440.08 2903.71,1434.76 2903.71,1278.82 ccw(c3003.71,1278.82) 3003.71,1178.82 3255.03,1178.82 cw(c3255.03,1069.76) 3364.08,1069.76 ccw(c3380.62,1069.76) 3368.93,1058.07 C226.2@3381,1046
CAM_2_P: C224.1 U1.59 | length 774.6
  Layer 1 - Top Layer w3.94: U1.59@2889.34,1440.08 2894.66,1434.76 2894.66,1278.82 ccw(c3003.71,1278.82) 3003.71,1169.76 3255.03,1169.76 cw(c3255.03,1069.76) 3355.03,1069.76 cw(c3331.53,1069.76) 3348.15,1053.15 C224.1@3339,1044
cam_2_se: C224.2 J25.1 L48.1 | length 753.9
  Layer 1 - Top Layer w3.94: v2@3334.56,493.73 ccw(c3349.73,493.73) v2@3339,483
  Layer 1 - Top Layer w6.2: v2@3334.56,493.73 C224.2@3334.56,989.24
  Layer 6 - Bottom Layer w10: J25.1@3331,249 J25.1@3338,256 ; J25.1@3336,253 3338,255 J25.1@3338,256 ; v2(3338,488) J25.1@3338,256 ; J25.1@3338.56,256.56 J25.1@3338,256
CAM_3_N: C227.2 U1.63 | length 582.6
  Layer 1 - Top Layer w3.94: U1.63@2968.1,1440.08 2962.78,1434.76 2962.78,1288.27 ccw(c3038.97,1288.27) 3038.97,1212.08 3329.3,1212.08 ccw(c3329.3,1235.7) C227.2@3346,1219
CAM_3_P: C225.1 U1.62 | length 598.7
  Layer 1 - Top Layer w3.94: U1.62@2948.41,1440.08 2953.73,1434.76 2953.73,1288.27 ccw(c3038.97,1288.27) 3038.97,1203.03 3312.13,1203.03 cw(c3312.13,1155.13) C225.1@3346,1189
cam_3_se: C225.2 J26.1 L50.1 | length 1806
  Layer 1 - Top Layer w3.94: 4304.29,1149.71 4305.71,1148.29
  Layer 1 - Top Layer w6.2: C225.2@3407.62,1179 4233.58,1179 cw(c4233.58,1079) 4304.29,1149.71 ; 4305.71,1148.29 cw(c4235,1077.58) 4335,1077.58 v2@4335,491
  Layer 6 - Bottom Layer w10: v2(4336,489) 4336,256 J26.1@4337,255
CAM_CLK_N: J1.7 R2.1 | length 308.7
  Layer 6 - Bottom Layer w3.94: R2.1@5737.23,573.1 5728.38,581.96 cw(c5756.42,610) 5716.76,610 5716.76,615.97 cw(c5779.03,615.97) 5735,660 cw(c5785.57,609.43) 5785.57,680.94 5852.93,680.94 ccw(c5852.93,707.07) 5871.4,688.6 5871.92,689.11 ccw(c5847.42,713.61) 5882.07,713.61 5882.07,744.23 J1.7@5887.38,749.54
CAM_CLK_P: J1.5 R1.2 | length 308.7
  Layer 6 - Bottom Layer w3.94: R1.2@5687.23,573.1 5696.09,581.96 ccw(c5668.05,610) 5707.71,610 5707.71,615.97 cw(c5779.03,615.97) 5728.6,666.4 cw(c5785.57,609.43) 5785.57,690 5852.93,690 ccw(c5852.93,707.07) 5865,695 5865.52,695.52 ccw(c5847.42,713.61) 5873.01,713.61 5873.01,744.23 J1.5@5867.7,749.54
CAM_CSI0_CLK_N: R2.2 U1.22 | length 7007.2
  Layer 1 - Top Layer w3.94: U1.22@2889.34,1786.53 2884.02,1791.85 2884.02,2178.43 cw(c2922.6,2178.43) 2922.6,2217 3929.53,2217 cw(c3929.53,2117) 4029.53,2117 4029.53,1938.01 cw(c4005.73,1938.01) 4022.57,1921.19 v3@4020.67,1919.29
  Layer 6 - Bottom Layer w3.94: v3@4020.67,1919.29 cw(c3999.7,1898.36) 4029.33,1898.36 4029.33,1896.65 ccw(c4050.98,1896.65) 4050.98,1875 4600.59,1875 cw(c4600.59,1775) 4700.59,1775 4700.59,1656.59 ccw(c4809.65,1656.59) 4732.53,1579.48 4805.49,1506.51 cw(c4793.49,1494.52) 4805.49,1482.52 4788.92,1465.95 ccw(c4800.92,1453.95) 4788.92,1441.95 ccw(c4800.92,1453.95) 4812.92,1441.95 4829.49,1458.52 cw(c4841.49,1446.52) 4853.49,1458.52 4883.87,1428.14 ccw(c4902.59,1446.89) 4921.32,1428.14 4960.97,1467.79 cw(c4973.3,1455.46) 4985.64,1467.79 cw(c4973.3,1455.46) 4990.75,1455.46 cw(c4973.3,1455.46) 4985.64,1443.13 4875.28,1332.77 ccw(c4894.02,1314.04) 4875.28,1295.3 ccw(c4894.02,1314.04) 4912.75,1295.3 5023.11,1405.66 cw(c5035.44,1393.32) 5047.77,1405.66 cw(c5035.44,1393.32) 5052.88,1393.32 cw(c5035.44,1393.32) 5047.77,1380.99 4937.41,1270.63 ccw(c4956.16,1251.9) 4937.42,1233.17 ccw(c4956.16,1251.9) 4974.88,1233.16 5085.24,1343.52 cw(c5097.58,1331.19) 5109.91,1343.52 cw(c5097.58,1331.19) 5115.02,1331.19 cw(c5097.58,1331.19) 5109.91,1318.85 4999.55,1208.49 ccw(c5018.29,1189.77) 4999.56,1171.03 ccw(c5018.29,1189.77) 5037.02,1171.02 5147.38,1281.38 cw(c5159.71,1269.05) 5172.05,1281.38 cw(c5159.71,1269.05) 5177.15,1269.05 cw(c5159.71,1269.05) 5172.05,1256.72 5061.69,1146.36 ccw(c5080.43,1127.63) 5061.69,1108.89 ccw(c5080.43,1127.63) 5099.16,1108.89 5209.52,1219.25 cw(c5221.85,1206.91) 5234.18,1219.25 cw(c5221.85,1206.91) 5239.29,1206.91 cw(c5221.85,1206.91) 5234.18,1194.58 5123.82,1084.22 ccw(c5142.56,1065.49) 5123.83,1046.76 ccw(c5142.56,1065.49) 5161.29,1046.75 5271.65,1157.11 cw(c5283.99,1144.78) 5296.32,1157.11 cw(c5283.99,1144.78) 5301.43,1144.78 cw(c5283.99,1144.78) 5296.32,1132.45 5185.96,1022.09 ccw(c5204.7,1003.36) 5185.97,984.62 ccw(c5204.7,1003.36) 5223.43,984.61 5333.79,1094.97 cw(c5346.12,1082.64) 5358.45,1094.97 cw(c5346.12,1082.64) 5363.56,1082.64 cw(c5346.12,1082.64) 5358.45,1070.31 5248.09,959.95 ccw(c5266.84,941.22) 5248.1,922.48 ccw(c5266.84,941.22) 5285.57,922.48 5325.22,962.13 cw(c5337.55,949.79) 5349.88,962.13 5423.27,888.74 cw(c5352.56,818.03) 5452.56,818.03 5452.56,682.17 ccw(c5561.61,682.17) 5484.5,605.06 5589.31,500.25 ccw(c5666.42,577.36) 5666.42,468.31 5692.94,468.31 ccw(c5692.94,492.13) 5716.76,492.13 cw(c5748.77,492.13) 5726.13,514.76 R2.2@5737.23,525.86
  other v3: 4019,1919
CAM_CSI0_CLK_P: R1.1 U1.23 | length 7007
  Layer 1 - Top Layer w3.94: U1.23@2869.65,1786.53 2874.97,1791.85 2874.97,2178.43 cw(c2922.6,2178.43) 2922.6,2226.06 3929.53,2226.06 cw(c3929.53,2117) 4038.58,2117 4038.58,1940.2 ccw(c4068.15,1940.2) v3@4047.24,1919.29
  Layer 6 - Bottom Layer w3.94: v3@4047.24,1919.29 ccw(c4068.63,1897.91) 4038.39,1897.91 4038.39,1896.65 ccw(c4050.98,1896.65) 4050.98,1884.06 4600.59,1884.06 cw(c4600.59,1775) 4709.65,1775 4709.65,1656.59 ccw(c4809.65,1656.59) 4738.94,1585.88 4765.76,1559.06 ccw(c4777.76,1571.05) 4789.76,1559.06 4806.37,1575.67 cw(c4818.37,1563.67) 4830.37,1575.67 cw(c4818.37,1563.67) 4830.37,1551.67 4813.75,1535.06 ccw(c4825.75,1523.06) 4813.75,1511.06 4890.26,1434.55 ccw(c4902.59,1446.89) 4914.93,1434.55 4954.57,1474.2 cw(c4973.3,1455.46) 4992.04,1474.2 cw(c4973.3,1455.46) 4999.8,1455.46 cw(c4973.3,1455.46) 4992.04,1436.72 4881.69,1326.37 ccw(c4894.02,1314.04) 4881.69,1301.71 ccw(c4894.02,1314.04) 4906.35,1301.71 5016.71,1412.06 cw(c5035.44,1393.32) 5054.18,1412.06 cw(c5035.44,1393.32) 5061.94,1393.32 cw(c5035.44,1393.32) 5054.18,1374.59 4943.82,1264.23 ccw(c4956.16,1251.9) 4943.82,1239.57 ccw(c4956.16,1251.9) 4968.49,1239.57 5078.85,1349.93 cw(c5097.58,1331.19) 5116.31,1349.92 cw(c5097.58,1331.19) 5124.07,1331.19 cw(c5097.58,1331.19) 5116.31,1312.45 5005.96,1202.1 ccw(c5018.29,1189.77) 5005.96,1177.43 ccw(c5018.29,1189.77) 5030.62,1177.43 5140.98,1287.79 cw(c5159.71,1269.05) 5178.45,1287.79 cw(c5159.71,1269.05) 5186.21,1269.05 cw(c5159.71,1269.05) 5178.45,1250.32 5068.1,1139.96 ccw(c5080.43,1127.63) 5068.1,1115.3 ccw(c5080.43,1127.63) 5092.76,1115.3 5203.12,1225.66 cw(c5221.85,1206.91) 5240.59,1225.65 cw(c5221.85,1206.91) 5248.35,1206.91 cw(c5221.85,1206.91) 5240.59,1188.18 5130.23,1077.83 ccw(c5142.56,1065.49) 5130.23,1053.16 ccw(c5142.56,1065.49) 5154.9,1053.16 5265.26,1163.52 cw(c5283.99,1144.78) 5302.72,1163.51 cw(c5283.99,1144.78) 5310.48,1144.78 cw(c5283.99,1144.78) 5302.72,1126.04 5192.37,1015.69 ccw(c5204.7,1003.36) 5192.37,991.02 ccw(c5204.7,1003.36) 5217.03,991.02 5327.39,1101.38 cw(c5346.12,1082.64) 5364.86,1101.38 cw(c5346.12,1082.64) 5372.62,1082.64 cw(c5346.12,1082.64) 5364.86,1063.91 5254.5,953.55 ccw(c5266.84,941.22) 5254.5,928.89 ccw(c5266.84,941.22) 5279.17,928.89 5318.82,968.54 cw(c5337.55,949.79) 5356.28,968.54 5429.67,895.14 cw(c5352.56,818.03) 5461.61,818.03 5461.61,682.17 ccw(c5561.61,682.17) 5490.9,611.46 5595.71,506.65 ccw(c5666.42,577.36) 5666.42,477.36 5692.94,477.36 ccw(c5692.94,492.13) 5707.71,492.13 ccw(c5675.7,492.13) 5698.33,514.76 R1.1@5687.23,525.86
  other v3: 4049,1919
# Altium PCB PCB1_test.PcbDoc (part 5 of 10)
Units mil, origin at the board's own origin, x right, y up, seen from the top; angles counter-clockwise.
Board outline 6690 x 6690 mil, 6 copper layers (Layer 1 - Top Layer, Layer 2 - GND, Layer 3 - PWR, Layer 4 - Signal, Layer 5 - GND, Layer 6 - Bottom Layer), stack 80.244 mil thick; 821 components, 458 nets, 3746 pads, 1527 vias.

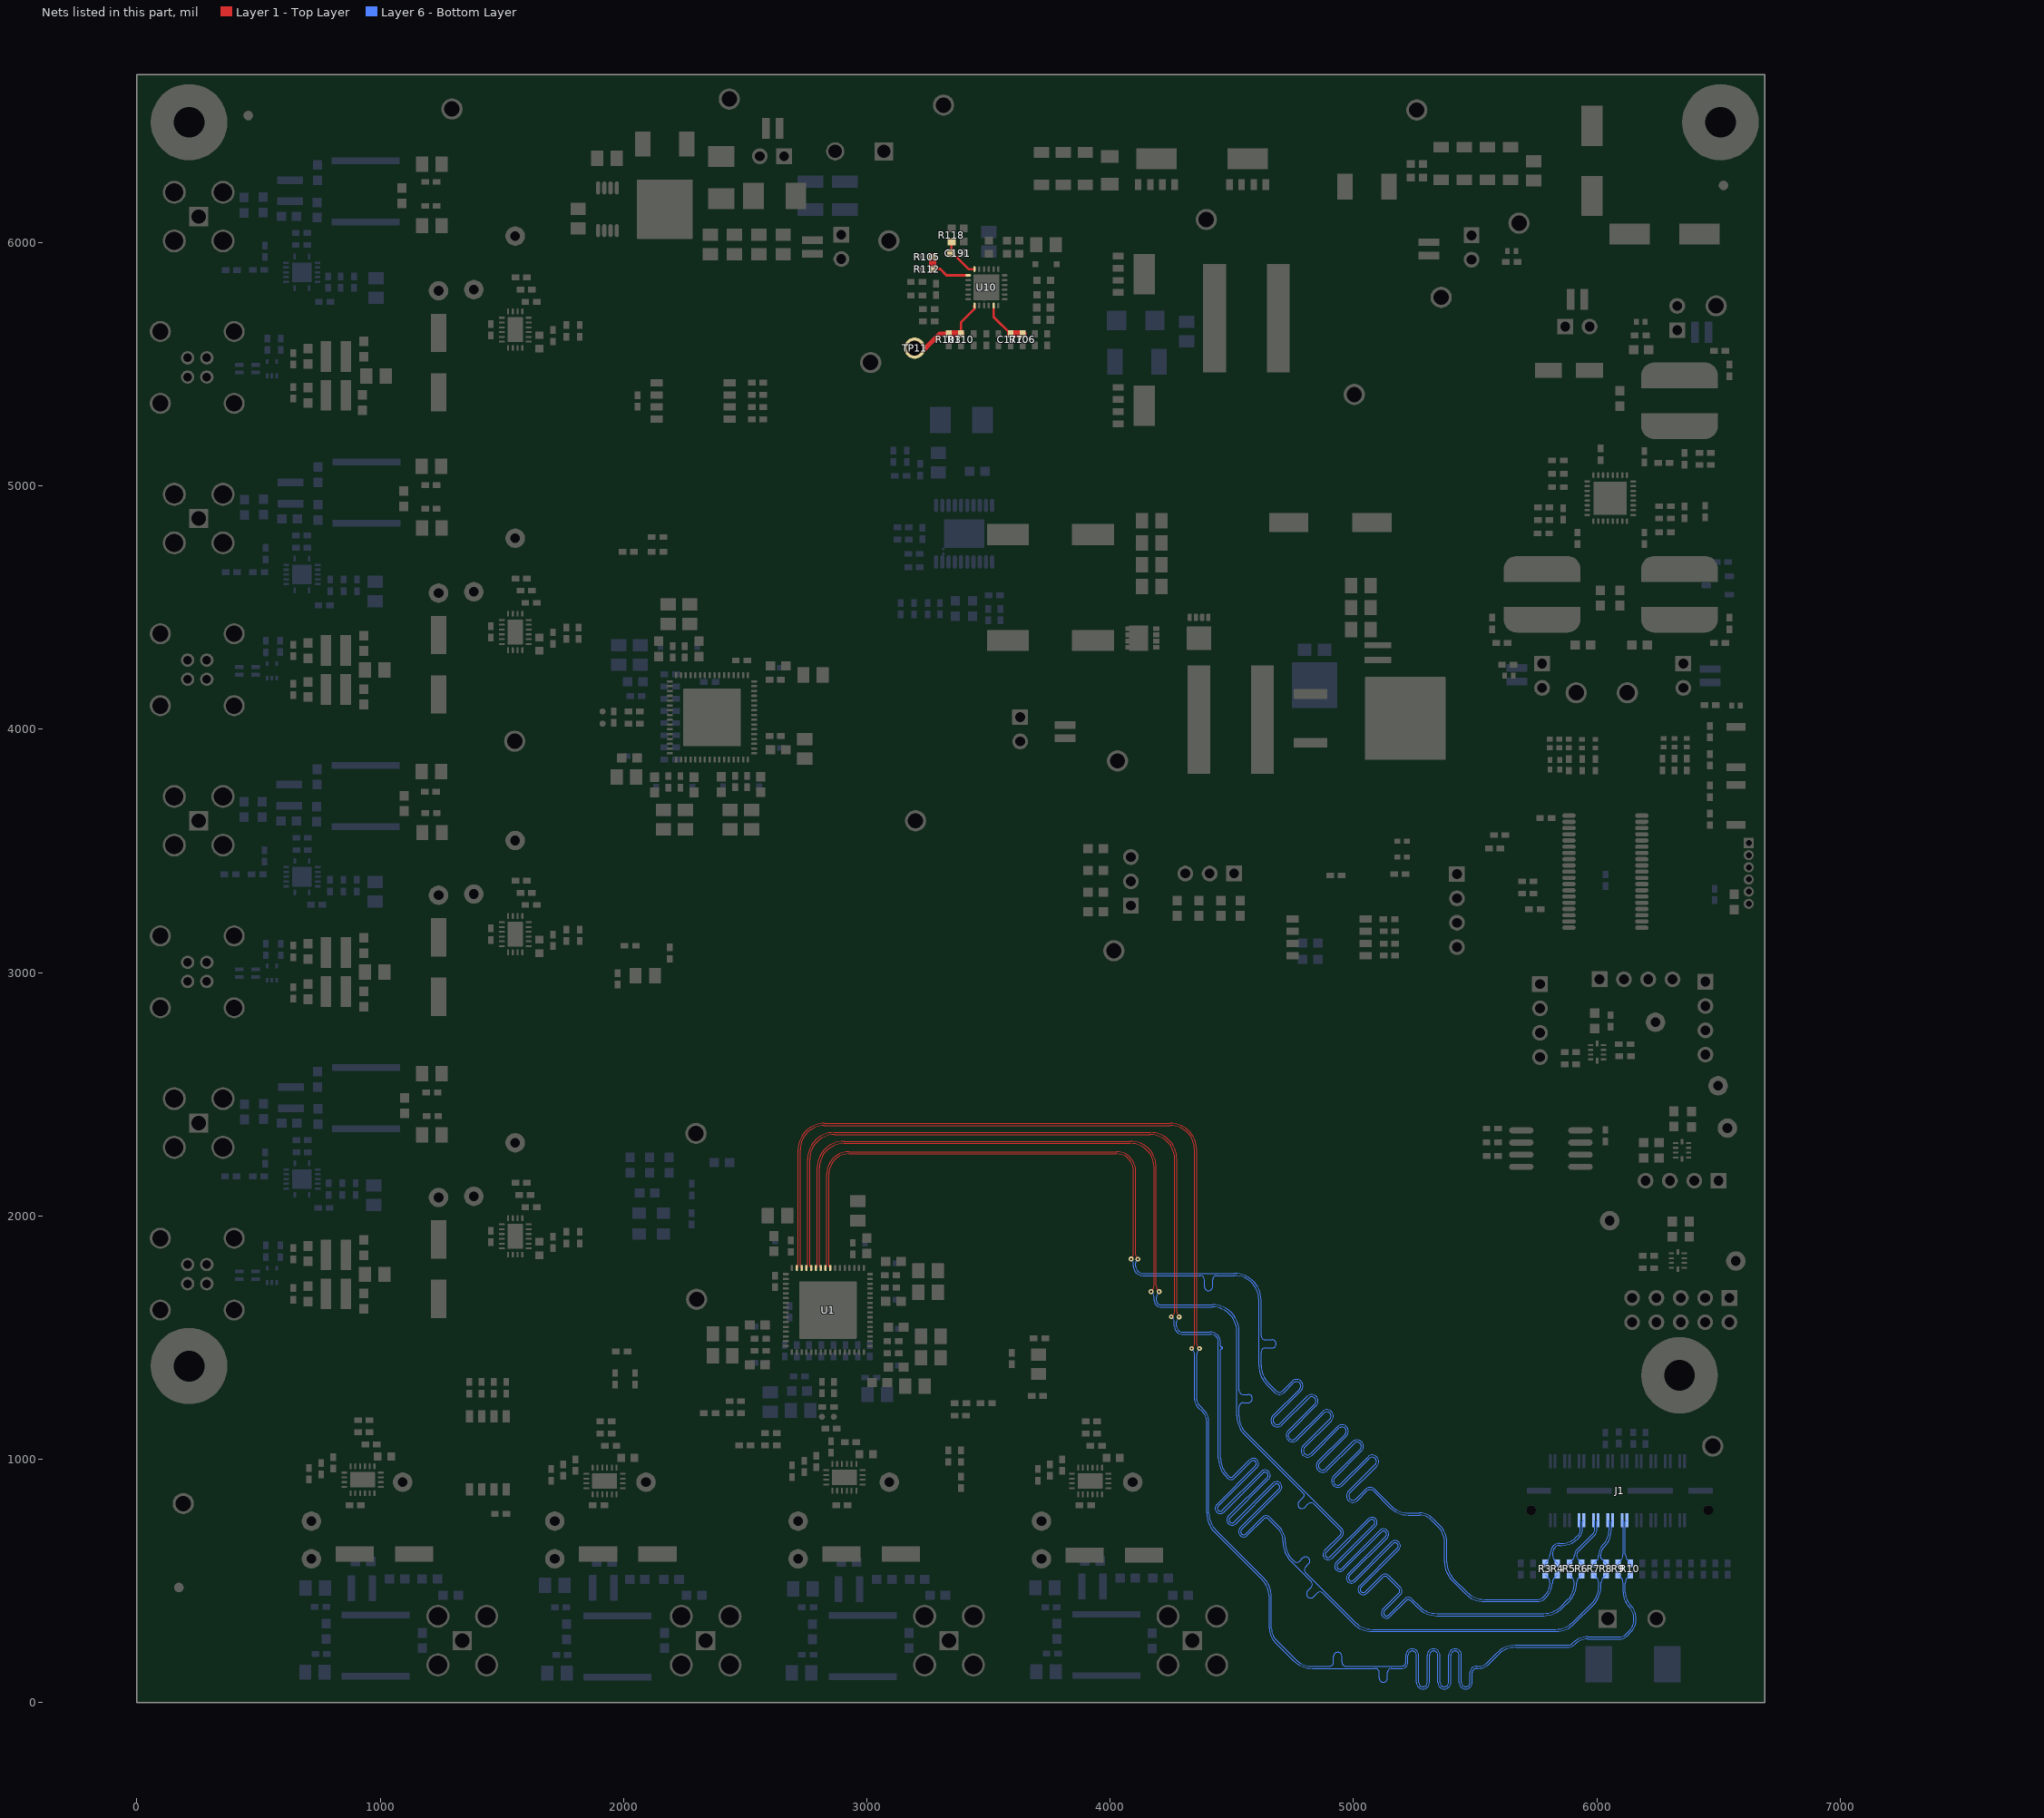
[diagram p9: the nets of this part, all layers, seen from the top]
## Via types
v1: diameter 20, hole 10, Layer 1 - Top Layer to Layer 6 - Bottom Layer, tented both sides, 491 vias
v2: diameter 20, hole 10, Layer 1 - Top Layer to Layer 6 - Bottom Layer, 310 vias
v3: diameter 19.68, hole 7.87, Layer 1 - Top Layer to Layer 6 - Bottom Layer, 282 vias
v4: diameter 19.68, hole 7.87, Layer 1 - Top Layer to Layer 6 - Bottom Layer, tented both sides, 211 vias
v5: diameter 50, hole 28, Layer 1 - Top Layer to Layer 6 - Bottom Layer, 101 vias
v6: diameter 30, hole 15, Layer 1 - Top Layer to Layer 6 - Bottom Layer, 73 vias
v7: diameter 22, hole 10, Layer 1 - Top Layer to Layer 6 - Bottom Layer, 36 vias
v8: diameter 30, hole 10, Layer 1 - Top Layer to Layer 6 - Bottom Layer, 14 vias
v9: diameter 19.68, hole 7.87, Layer 1 - Top Layer to Layer 6 - Bottom Layer, tented bottom, 4 vias
v10: diameter 30, hole 10, Layer 1 - Top Layer to Layer 6 - Bottom Layer, tented both sides, 2 vias
v11: diameter 40, hole 10, Layer 1 - Top Layer to Layer 6 - Bottom Layer, 1 vias
v12: diameter 23.62, hole 7.87, Layer 1 - Top Layer to Layer 6 - Bottom Layer, tented both sides, 1 vias
v13: diameter 23.62, hole 7.87, Layer 1 - Top Layer to Layer 6 - Bottom Layer, 1 vias

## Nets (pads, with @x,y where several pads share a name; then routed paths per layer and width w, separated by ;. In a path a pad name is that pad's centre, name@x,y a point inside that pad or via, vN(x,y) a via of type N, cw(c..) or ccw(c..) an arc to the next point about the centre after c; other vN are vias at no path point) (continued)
CAM_CSI0_D0_N: R4.2 U1.24 | length 7029.1
  Layer 1 - Top Layer w3.94: U1.24@2849.96,1786.53 2844.64,1791.85 2844.64,2173.64 cw(c2926,2173.64) 2926,2255 4026.3,2255 cw(c4026.3,2186.02) 4095.28,2186.02 4095.28,1840.55 cw(c4073.41,1840.55) 4088.87,1825.09 v3@4086.61,1822.83
  Layer 6 - Bottom Layer w3.94: v3@4086.61,1822.83 v3@4089.57,1819.88 ; v3@4089.57,1819.87 cw(c4075.79,1806.1) 4095.28,1806.1 4095.28,1794.29 ccw(c4134.65,1794.29) 4134.65,1754.92 4370.12,1754.92 cw(c4370.12,1737.95) 4387.09,1737.95 4387.09,1709.84 ccw(c4404.06,1709.84) 4404.06,1692.87 ccw(c4404.06,1709.84) 4421.02,1709.84 4421.02,1737.95 cw(c4437.99,1737.95) 4437.99,1754.92 4511.02,1754.92 cw(c4511.02,1654.92) 4611.02,1654.92 4611.02,1384.93 ccw(c4720.08,1384.93) 4642.97,1307.81 4676.67,1274.1 ccw(c4695.4,1292.84) 4714.13,1274.1 4753.78,1313.75 cw(c4766.11,1301.42) 4778.45,1313.75 cw(c4766.11,1301.42) 4783.56,1301.42 cw(c4766.11,1301.42) 4778.45,1289.09 4668.09,1178.73 ccw(c4686.83,1160) 4668.09,1141.26 ccw(c4686.83,1160) 4705.56,1141.26 4815.92,1251.62 cw(c4828.25,1239.28) 4840.58,1251.62 cw(c4828.25,1239.28) 4845.69,1239.28 cw(c4828.25,1239.28) 4840.58,1226.95 4730.22,1116.59 ccw(c4748.97,1097.86) 4730.23,1079.13 ccw(c4748.97,1097.86) 4767.69,1079.12 4878.05,1189.48 cw(c4890.39,1177.15) 4902.72,1189.48 cw(c4890.39,1177.15) 4907.83,1177.15 cw(c4890.39,1177.15) 4902.72,1164.81 4792.36,1054.45 ccw(c4811.1,1035.72) 4792.37,1016.99 ccw(c4811.1,1035.72) 4829.83,1016.98 4940.19,1127.34 cw(c4952.52,1115.01) 4964.86,1127.34 cw(c4952.52,1115.01) 4969.96,1115.01 cw(c4952.52,1115.01) 4964.86,1102.68 4854.5,992.32 ccw(c4873.24,973.59) 4854.5,954.85 ccw(c4873.24,973.59) 4891.97,954.85 5002.33,1065.21 cw(c5014.66,1052.87) 5026.99,1065.21 cw(c5014.66,1052.87) 5032.1,1052.87 cw(c5014.66,1052.87) 5026.99,1040.54 4916.63,930.18 ccw(c4935.37,911.45) 4916.64,892.72 ccw(c4935.37,911.45) 4954.1,892.71 5064.46,1003.07 cw(c5076.8,990.74) 5089.13,1003.07 cw(c5076.8,990.74) 5094.24,990.74 cw(c5076.8,990.74) 5089.13,978.4 4978.77,868.04 ccw(c4997.51,849.32) 4978.78,830.58 ccw(c4997.51,849.32) 5016.24,830.57 5055.89,870.22 cw(c5068.22,857.89) 5080.55,870.22 5148.17,802.61 ccw(c5225.28,879.72) 5225.28,770.67 5271.37,770.67 cw(c5271.37,703.46) 5318.9,750.98 5347.93,721.95 cw(c5285.42,659.45) 5373.82,659.45 5373.82,578.82 ccw(c5482.87,578.82) 5405.76,501.71 5460.37,447.1 ccw(c5537.48,524.21) 5537.48,415.16 5758.55,415.16 ccw(c5758.55,451.1) 5783.96,425.68 5793.67,435.39 ccw(c5737.92,491.14) 5816.76,491.14 cw(c5851.15,491.14) 5826.83,515.46 R4.2@5837.23,525.86
  other v3: 4086,1823
CAM_CSI0_D0_P: R3.1 U1.25 | length 7029.1
  Layer 1 - Top Layer w3.94: U1.25@2830.27,1786.53 2835.59,1791.85 2835.59,2173.64 cw(c2926,2173.64) 2926,2264.06 4026.3,2264.06 cw(c4026.3,2186.02) 4104.33,2186.02 4104.33,1840.55 ccw(c4128.09,1840.55) 4111.29,1823.75 v3@4113.19,1821.85
  Layer 6 - Bottom Layer w3.94: v3@4113.19,1821.85 4109.2,1817.86 ccw(c4120.96,1806.1) 4104.33,1806.1 4104.33,1794.29 ccw(c4134.65,1794.29) 4134.65,1763.98 4511.02,1763.98 cw(c4511.02,1654.92) 4620.08,1654.92 4620.08,1508.07 ccw(c4637.05,1508.07) 4637.05,1491.1 4665.1,1491.1 cw(c4665.1,1474.13) 4682.07,1474.13 cw(c4665.1,1474.13) 4665.1,1457.17 4637.05,1457.17 ccw(c4637.05,1440.2) 4620.08,1440.2 4620.08,1384.93 ccw(c4720.08,1384.93) 4649.37,1314.21 4683.07,1280.51 ccw(c4695.4,1292.84) 4707.74,1280.51 4747.38,1320.15 cw(c4766.11,1301.42) 4784.85,1320.15 cw(c4766.11,1301.42) 4792.61,1301.42 cw(c4766.11,1301.42) 4784.85,1282.68 4674.5,1172.33 ccw(c4686.83,1160) 4674.5,1147.66 ccw(c4686.83,1160) 4699.16,1147.66 4809.52,1258.02 cw(c4828.25,1239.28) 4846.99,1258.02 cw(c4828.25,1239.28) 4854.75,1239.28 cw(c4828.25,1239.28) 4846.99,1220.55 4736.63,1110.19 ccw(c4748.97,1097.86) 4736.63,1085.53 ccw(c4748.97,1097.86) 4761.3,1085.53 4871.66,1195.89 cw(c4890.39,1177.15) 4909.12,1195.88 cw(c4890.39,1177.15) 4916.88,1177.15 cw(c4890.39,1177.15) 4909.12,1158.41 4798.77,1048.06 ccw(c4811.1,1035.72) 4798.77,1023.39 ccw(c4811.1,1035.72) 4823.43,1023.39 4933.79,1133.75 cw(c4952.52,1115.01) 4971.26,1133.75 cw(c4952.52,1115.01) 4979.02,1115.01 cw(c4952.52,1115.01) 4971.26,1096.27 4860.91,985.92 ccw(c4873.24,973.59) 4860.91,961.26 ccw(c4873.24,973.59) 4885.57,961.26 4995.93,1071.62 cw(c5014.66,1052.87) 5033.39,1071.61 cw(c5014.66,1052.87) 5041.16,1052.87 cw(c5014.66,1052.87) 5033.39,1034.14 4923.04,923.78 ccw(c4935.37,911.45) 4923.04,899.12 ccw(c4935.37,911.45) 4947.71,899.12 5058.07,1009.48 cw(c5076.8,990.74) 5095.53,1009.47 cw(c5076.8,990.74) 5103.29,990.74 cw(c5076.8,990.74) 5095.53,972 4985.18,861.65 ccw(c4997.51,849.32) 4985.18,836.98 ccw(c4997.51,849.32) 5009.84,836.98 5049.49,876.63 cw(c5068.22,857.89) 5086.95,876.63 5154.57,809.01 ccw(c5225.28,879.72) 5225.28,779.72 5271.37,779.72 cw(c5271.37,703.46) 5325.3,757.39 5354.33,728.36 cw(c5285.42,659.45) 5382.87,659.45 5382.87,578.82 ccw(c5482.87,578.82) 5412.16,508.11 5466.77,453.5 ccw(c5537.48,524.21) 5537.48,424.21 5758.55,424.21 ccw(c5758.55,451.1) 5777.56,432.09 5787.27,441.79 ccw(c5737.92,491.14) 5807.71,491.14 ccw(c5773.32,491.14) 5797.63,515.46 R3.1@5787.23,525.86
  other v3: 4114,1822
CAM_CSI0_D1_N: R6.2 U1.26 | length 7046.8
  Layer 1 - Top Layer w3.94: U1.26@2810.58,1786.53 2805.26,1791.85 2805.26,2198 cw(c2905.26,2198) 2905.26,2298 4082.91,2298 cw(c4082.91,2200.79) 4180.12,2200.79 4180.12,1715.11 cw(c4143.15,1715.11) v3@4169.29,1688.98
  Layer 6 - Bottom Layer w3.94: v3@4169.29,1688.98 cw(c4141.25,1660.94) 4180.91,1660.94 4180.91,1651.57 ccw(c4206.5,1651.57) 4206.5,1625.98 4420.47,1625.98 cw(c4420.47,1525.98) 4520.47,1525.98 4520.47,1178.23 ccw(c4629.53,1178.23) 4552.41,1101.12 4794.29,859.25 cw(c4786.97,851.94) 4794.29,844.62 4776.07,826.41 ccw(c4788.07,814.41) 4776.07,802.41 ccw(c4788.07,814.41) 4800.07,802.41 4813.6,815.94 cw(c4825.59,803.94) 4837.59,815.94 4946.28,707.25 cw(c4937.48,698.45) 4949.93,698.45 cw(c4937.48,698.45) 4946.28,689.66 4880.55,623.93 ccw(c4895.75,608.73) 4910.95,593.53 5066.41,748.98 cw(c5075.2,740.18) 5084,748.98 ; 5084.02,748.96 cw(c5075.2,740.18) 5087.64,740.18 cw(c5075.2,740.18) 5084,731.39 4928.55,575.94 ccw(c4943.75,560.74) 4958.95,545.54 5114.4,700.99 cw(c5123.2,692.19) 5131.98,701.01 cw(c5123.2,692.19) 5135.64,692.19 cw(c5123.2,692.19) 5131.99,683.39 4976.54,527.94 ccw(c4991.74,512.74) 5006.94,497.54 5162.39,652.99 cw(c5171.19,644.2) 5179.99,652.99 ; 5180.01,652.97 cw(c5171.19,644.2) 5183.63,644.2 cw(c5171.19,644.2) 5179.99,635.4 5024.54,479.95 ccw(c5039.74,464.75) 5054.94,449.55 5120.66,515.27 cw(c5129.46,506.48) 5138.26,515.27 5186.25,467.28 cw(c5177.46,458.48) 5189.9,458.48 cw(c5177.46,458.48) 5186.25,449.69 5120.53,383.96 ccw(c5135.73,368.76) 5150.93,353.56 5216.65,419.29 cw(c5225.45,410.49) 5234.25,419.29 5264.5,389.03 ccw(c5341.62,466.14) 5341.62,357.09 5781.41,357.09 ccw(c5781.41,466.14) 5858.53,389.03 5885.73,416.24 ccw(c5810.83,491.14) 5916.76,491.14 cw(c5951.15,491.14) 5926.83,515.46 R6.2@5937.23,525.86
  other v3: 4168,1689
CAM_CSI0_D1_P: R5.1 U1.27 | length 7046.8
  Layer 1 - Top Layer w3.94: U1.27@2790.89,1786.53 2796.21,1791.85 2796.21,2198 cw(c2905.26,2198) 2905.26,2307.06 4082.91,2307.06 cw(c4082.91,2200.79) 4189.17,2200.79 4189.17,1714.64 ccw(c4225.47,1714.64) v3@4199.8,1688.98
  Layer 6 - Bottom Layer w3.94: v3@4199.8,1688.98 ccw(c4223.56,1665.21) 4189.96,1665.21 4189.96,1651.57 ccw(c4206.5,1651.57) 4206.5,1635.04 4420.47,1635.04 cw(c4420.47,1525.98) 4529.53,1525.98 4529.53,1283.46 ccw(c4546.5,1283.46) 4546.5,1266.5 4567.34,1266.5 cw(c4567.34,1249.53) 4584.31,1249.53 cw(c4567.34,1249.53) 4567.34,1232.56 4546.5,1232.56 ccw(c4546.5,1215.59) 4529.53,1215.59 4529.53,1178.23 ccw(c4629.53,1178.23) 4558.82,1107.52 4952.68,713.65 cw(c4937.48,698.45) 4958.98,698.45 cw(c4937.48,698.45) 4952.68,683.25 4886.96,617.53 ccw(c4895.75,608.73) 4886.94,599.95 ccw(c4895.75,608.73) 4904.55,599.93 5060,755.38 cw(c5075.2,740.18) 5096.7,740.18 cw(c5075.2,740.18) 5090.4,724.98 4934.95,569.53 ccw(c4943.75,560.74) 4934.95,551.94 ; 4934.97,551.92 ccw(c4943.75,560.74) 4952.55,551.94 5108,707.39 cw(c5123.2,692.19) 5144.69,692.19 cw(c5123.2,692.19) 5138.4,676.99 4982.95,521.54 ccw(c4991.74,512.74) 4982.95,503.94 ccw(c4991.74,512.74) 5000.54,503.94 5155.99,659.4 cw(c5171.19,644.2) 5192.69,644.2 cw(c5171.19,644.2) 5186.39,629 5030.94,473.54 ccw(c5039.74,464.75) 5030.94,455.95 ccw(c5039.74,464.75) 5048.53,455.95 5114.26,521.68 cw(c5129.46,506.48) 5144.66,521.68 5192.66,473.68 cw(c5177.46,458.48) 5198.95,458.48 cw(c5177.46,458.48) 5192.66,443.28 5126.93,377.56 ccw(c5135.73,368.76) 5126.93,359.96 ccw(c5135.73,368.76) 5144.52,359.96 5210.25,425.69 cw(c5225.45,410.49) 5240.65,425.69 5270.91,395.43 ccw(c5341.62,466.14) 5341.62,366.14 5781.41,366.14 ccw(c5781.41,466.14) 5852.12,395.43 5879.33,422.64 ccw(c5810.83,491.14) 5907.71,491.14 ccw(c5873.32,491.14) 5897.63,515.46 R5.1@5887.23,525.86
  other v3: 4201,1689
CAM_CSI0_D2_N: R8.2 U1.28 | length 7062.6
  Layer 1 - Top Layer w3.94: U1.28@2771.2,1786.53 2765.88,1791.85 2765.88,2234 cw(c2865.88,2234) 2865.88,2334 4164.76,2334 cw(c4164.76,2234) 4264.76,2234 4264.76,1606.3 cw(c4245.75,1606.3) 4259.2,1592.86 v3@4251.97,1585.63
  Layer 6 - Bottom Layer w3.94: v3@4251.97,1585.63 4257.18,1580.42 cw(c4241.72,1564.96) 4263.58,1564.96 4263.58,1548.23 ccw(c4298.03,1548.23) 4298.03,1513.78 4411.22,1513.78 cw(c4411.22,1480.32) 4444.69,1480.32 4444.69,1005.01 ccw(c4553.74,1005.01) 4476.63,927.9 4481.22,923.31 ccw(c4496.42,938.51) 4511.62,923.31 4579.55,991.24 cw(c4588.35,982.44) 4597.14,991.24 ; 4597.16,991.22 cw(c4588.35,982.44) 4600.79,982.44 cw(c4588.35,982.44) 4597.14,973.64 4437.29,813.79 ccw(c4452.49,798.59) 4467.69,783.39 4627.54,943.24 cw(c4636.34,934.44) 4645.14,943.24 ; 4645.16,943.22 cw(c4636.34,934.44) 4648.78,934.44 cw(c4636.34,934.44) 4645.14,925.65 4485.28,765.79 ccw(c4500.48,750.59) 4515.68,735.39 4675.54,895.25 cw(c4684.33,886.45) 4693.13,895.25 cw(c4684.33,886.45) 4696.77,886.45 cw(c4684.33,886.45) 4693.13,877.65 4533.28,717.8 ccw(c4548.48,702.6) 4563.68,687.4 4631.61,755.33 cw(c4640.4,746.53) 4649.2,755.33 4688.72,715.81 cw(c4636.3,663.39) 4710.43,663.39 4710.43,658.55 ccw(c4819.49,658.55) 4742.37,581.43 4826.15,497.66 cw(c4814.15,485.66) 4826.15,473.66 4811.62,459.12 ccw(c4823.62,447.13) 4811.62,435.13 ccw(c4823.62,447.13) 4835.61,435.13 4850.15,449.66 cw(c4862.15,437.66) 4874.15,449.66 4999.74,324.07 ccw(c5076.85,401.18) 5076.85,292.13 5830.63,292.13 ccw(c5830.63,401.18) 5907.74,324.07 5984.82,401.15 ccw(c5907.71,478.26) 6016.76,478.26 6016.76,492.13 cw(c6048.77,492.13) 6026.14,514.76 R8.2@6037.23,525.86
  other v3: 4251,1586
CAM_CSI0_D2_P: R7.1 U1.29 | length 7062.6
  Layer 1 - Top Layer w3.94: U1.29@2751.51,1786.53 2756.83,1791.85 2756.83,2234 cw(c2865.88,2234) 2865.88,2343.06 4164.76,2343.06 cw(c4164.76,2234) 4273.82,2234 4273.82,1605.56 ccw(c4303.39,1605.56) v3@4282.48,1584.65
  Layer 6 - Bottom Layer w3.94: v3@4282.48,1584.65 4279.6,1581.76 ccw(c4296.4,1564.96) 4272.64,1564.96 4272.64,1548.23 ccw(c4298.03,1548.23) 4298.03,1522.83 4411.22,1522.83 cw(c4411.22,1480.32) 4453.74,1480.32 4453.74,1465.55 ccw(c4457.68,1465.55) 4457.68,1461.61 cw(c4457.68,1457.68) 4461.61,1457.68 cw(c4457.68,1457.68) 4457.68,1453.74 ccw(c4457.68,1449.8) 4453.74,1449.8 4453.74,1005.01 ccw(c4553.74,1005.01) 4483.03,934.3 4487.62,929.71 ccw(c4496.42,938.51) 4505.22,929.71 4573.15,997.64 cw(c4588.35,982.44) 4609.84,982.44 cw(c4588.35,982.44) 4603.55,967.24 4443.69,807.39 ccw(c4452.49,798.59) 4443.67,789.81 ; 4443.69,789.79 ccw(c4452.49,798.59) 4461.29,789.79 4621.14,949.64 cw(c4636.34,934.44) 4657.84,934.44 cw(c4636.34,934.44) 4651.54,919.24 4491.69,759.39 ccw(c4500.48,750.59) 4491.69,741.8 ccw(c4500.48,750.59) 4509.28,741.8 4669.13,901.65 cw(c4684.33,886.45) 4705.83,886.45 cw(c4684.33,886.45) 4699.53,871.25 4539.68,711.4 ccw(c4548.48,702.6) 4539.66,693.82 ; 4539.68,693.8 ccw(c4548.48,702.6) 4557.27,693.8 4625.2,761.73 cw(c4640.4,746.53) 4655.6,761.73 4695.12,722.21 cw(c4636.3,663.39) 4719.49,663.39 4719.49,658.55 ccw(c4819.49,658.55) 4748.78,587.84 4754.92,581.69 ccw(c4766.92,593.69) 4778.92,581.69 4791.33,594.1 cw(c4803.33,582.11) 4815.33,594.1 cw(c4803.33,582.11) 4815.33,570.11 4802.92,557.7 ccw(c4814.91,545.7) 4802.92,533.7 5006.14,330.47 ccw(c5076.85,401.18) 5076.85,301.18 5830.63,301.18 ccw(c5830.63,401.18) 5901.34,330.47 5978.42,407.55 ccw(c5907.71,478.26) 6007.71,478.26 6007.71,492.13 ccw(c5975.7,492.13) 5998.33,514.76 R7.1@5987.23,525.86
  other v3: 4283,1585
CAM_CSI0_D3_N: R10.2 U1.30 | length 7072.8
  Layer 1 - Top Layer w3.94: U1.30@2731.82,1786.53 2726.5,1791.85 2726.5,2272 cw(c2826.5,2272) 2826.5,2372 4246.46,2372 cw(c4246.46,2272) 4346.46,2272 4346.46,1474.41 cw(c4325.07,1474.41) 4340.19,1459.29 v3@4335.63,1454.72
  Layer 6 - Bottom Layer w3.94: v3@4335.63,1454.72 cw(c4307.59,1426.69) 4347.24,1426.69 4347.24,1245.93 ccw(c4391.6,1245.93) 4360.23,1214.58 ; 4360.24,1214.57 4380.31,1194.49 cw(c4341.33,1155.51) 4396.46,1155.51 4396.46,778.63 ccw(c4505.51,778.63) 4428.4,701.51 4624.25,505.66 cw(c4553.54,434.95) 4653.54,434.95 4653.54,306.1 ccw(c4734.36,306.1) 4677.21,248.96 4753.68,172.49 ccw(c4830.79,249.61) 4830.79,140.55 5088.62,140.55 cw(c5088.62,123.58) 5105.59,123.58 5105.59,100.46 ccw(c5122.56,100.46) 5122.56,83.49 ccw(c5122.56,100.46) 5139.53,100.46 5139.53,123.58 cw(c5156.5,123.58) 5156.5,140.55 5197.41,140.55 ccw(c5197.41,167.05) 5223.9,167.05 5223.9,194.7 cw(c5241.35,194.7) 5258.79,194.7 5258.79,82.46 ccw(c5285.28,82.46) 5311.78,82.46 5311.78,194.7 cw(c5329.22,194.7) 5346.66,194.7 5346.66,82.46 ccw(c5373.16,82.46) 5399.65,82.46 5399.65,194.7 cw(c5417.09,194.7) 5434.53,194.7 5434.53,82.46 ccw(c5461.03,82.46) 5487.53,82.46 5487.53,123.11 cw(c5504.97,123.11) 5504.97,140.55 5511.46,140.55 ccw(c5511.46,205.07) 5557.08,159.44 5595.51,197.88 cw(c5666.22,127.17) 5666.22,227.17 5879.48,227.17 ccw(c5879.48,268.16) 5908.46,239.17 cw(c5962.64,185) 5962.64,261.61 6094.35,261.61 ccw(c6094.35,304.27) 6124.51,274.11 6140.58,290.17 ; R10.2@6137.23,525.86 6126.83,515.46 ccw(c6151.15,491.14) 6116.76,491.14 6116.76,453.75 ccw(c6191.94,453.75) 6138.78,400.59 cw(c6086.03,347.84) 6160.63,347.84 6160.63,338.58 cw(c6092.17,338.58) 6140.59,290.18
  other v3: 4335,1455
CAM_CSI0_D3_P: R9.1 U1.31 | length 7072.8
  Layer 1 - Top Layer w3.94: U1.31@2712.13,1786.53 2717.45,1791.85 2717.45,2272 cw(c2826.5,2272) 2826.5,2381.06 4246.46,2381.06 cw(c4246.46,2272) 4355.51,2272 4355.51,1474.41 ccw(c4377.37,1474.41) 4361.91,1458.96 v3@4366.14,1454.72
  Layer 6 - Bottom Layer w3.94: v3@4366.14,1454.72 ccw(c4389.9,1430.96) 4356.3,1430.96 4356.3,1245.93 ccw(c4391.6,1245.93) 4366.64,1220.97 4386.71,1200.9 cw(c4341.33,1155.51) 4405.51,1155.51 4405.51,778.63 ccw(c4505.51,778.63) 4434.8,707.92 4630.66,512.06 cw(c4553.54,434.95) 4662.6,434.95 4662.6,306.1 ccw(c4734.36,306.1) 4683.62,255.36 4760.08,178.9 ccw(c4830.79,249.61) 4830.79,149.61 4901.1,149.61 ccw(c4901.1,166.57) 4918.07,166.57 4918.07,190 cw(c4935.04,190) 4935.04,206.97 cw(c4935.04,190) 4952.01,190 4952.01,166.57 ccw(c4968.98,166.57) 4968.98,149.61 5002.91,149.61 5036.5,149.61 5197.41,149.61 ccw(c5197.41,167.05) 5214.85,167.05 5214.85,194.7 cw(c5241.35,194.7) 5267.84,194.7 5267.84,82.46 ccw(c5285.28,82.46) 5302.72,82.46 5302.72,194.7 cw(c5329.22,194.7) 5355.72,194.7 5355.72,82.46 ccw(c5373.16,82.46) 5390.6,82.46 5390.6,194.7 cw(c5417.09,194.7) 5443.59,194.7 5443.59,82.46 ccw(c5461.03,82.46) 5478.47,82.46 5478.47,123.11 cw(c5504.97,123.11) 5504.97,149.61 5511.46,149.61 ccw(c5511.46,205.07) 5550.68,165.85 5589.11,204.28 cw(c5666.22,127.17) 5666.22,236.22 5879.48,236.22 ccw(c5879.48,268.16) 5902.06,245.58 cw(c5962.64,185) 5962.64,270.67 6094.35,270.67 ccw(c6094.35,304.27) 6118.11,280.51 6134.18,296.58 ccw(c6092.17,338.58) 6151.57,338.58 6151.57,347.84 ccw(c6086.03,347.84) 6132.38,394.19 cw(c6191.94,453.75) 6107.71,453.75 6107.71,491.14 ccw(c6073.32,491.14) 6097.63,515.46 R9.1@6087.23,525.86
  other v3: 4367,1455
CAM_D0_N: J1.11 R4.1 | length 262.5
  Layer 6 - Bottom Layer w3.94: R4.1@5837.23,573.1 5828.38,581.96 cw(c5856.42,610) 5816.76,610 cw(c5857.23,610) 5828.61,638.61 cw(c5846.31,620.91) 5846.31,645.94 5854.67,645.94 ccw(c5854.67,740.31) 5921.39,673.58 5931.4,683.59 ccw(c5907.91,707.08) 5941.12,707.08 5941.12,744.23 J1.11@5946.44,749.54
CAM_D0_P: J1.9 R3.2 | length 262.8
  Layer 6 - Bottom Layer w3.94: R3.2@5787.23,573.1 5796.09,581.96 ccw(c5768.05,610) 5807.71,610 cw(c5857.23,610) 5822.21,645.02 cw(c5846.31,620.91) 5846.31,655 5857.39,655 ccw(c5857.39,733.72) 5913.06,678.06 5925,690 ccw(c5907.94,707.06) 5932.07,707.06 5932.07,744.23 J1.9@5926.75,749.54
CAM_D1_N: J1.15 R6.1 | length 218.2
  Layer 6 - Bottom Layer w3.94: R6.1@5937.23,573.1 5924.84,585.5 cw(c5944.34,605) 5916.76,605 cw(c5938.38,605) 5923.09,620.29 5991.11,688.31 ccw(c5969.22,710.19) 6000.18,710.19 6000.18,744.23 J1.15@6005.49,749.54
CAM_D1_P: J1.13 R5.2 | length 218.2
  Layer 6 - Bottom Layer w3.94: R5.2@5887.23,573.1 5899.63,585.5 ccw(c5880.12,605) 5907.71,605 cw(c5938.38,605) 5916.68,626.68 5984.71,694.71 ccw(c5969.22,710.19) 5991.12,710.19 5991.12,744.23 J1.13@5985.81,749.54
CAM_D2_N: J1.19 R8.1 | length 198.9
  Layer 6 - Bottom Layer w3.94: 6018.36,591.97 R8.1@6037.23,573.1 ; 6018.36,591.98 cw(c6025.09,598.69) 6015.58,598.69 6015.58,603.31 cw(c6070.64,603.31) 6031.71,642.25 ccw(c5965.26,708.7) 6059.23,708.7 6059.23,744.23 J1.19@6064.55,749.54
CAM_D2_P: J1.17 R7.2 | length 197.6
  Layer 6 - Bottom Layer w3.94: R7.2@5987.23,573.1 6002.07,587.94 ccw(c5991.31,598.69) 6006.52,598.69 6006.52,603.31 cw(c6070.64,603.31) 6025.31,648.65 ccw(c5965.26,708.7) 6050.18,708.7 6050.18,744.23 J1.17@6044.86,749.54
CAM_D3_N: J1.23 R10.1 | length 186
  Layer 6 - Bottom Layer w3.94: J1.23@6123.6,749.54 6116.76,742.7 6116.76,610 ccw(c6156.42,610) 6128.38,581.96 R10.1@6137.23,573.1
CAM_D3_P: J1.21 R9.2 | length 184.8
  Layer 6 - Bottom Layer w3.94: R9.2@6087.23,573.1 6096.09,581.96 ccw(c6068.05,610) 6107.71,610 6107.71,745.76 J1.21@6103.92,749.54
CS: C191.2 R118.1 U10.18 | length 167.1
  Layer 1 - Top Layer w10: R118.1@3348.03,6003.82 3348.03,5958.94 3350.51,5958.94 3418.27,5891.18 U10.18@3442.17,5891.18
DEMB: R103.1 R110.2 TP11.1 U10.1 | length 354
  Layer 1 - Top Layer w10: R110.2@3386.38,5625 3386.38,5671.38 3442.17,5727.17 U10.1@3442.17,5741.57
  Layer 1 - Top Layer w20: TP11.1@3196.38,5566.38 3241.38,5566.38 3300,5625 R103.1@3336.38,5625
  Layer 1 - Top Layer w30: R103.1@3336.38,5625 R110.2@3386.38,5625
DITH: C177.2 R106.1 U10.5 | length 195.6
  Layer 1 - Top Layer w10: U10.5@3520.91,5741.57 3520.91,5695.04 C177.2@3590.95,5625
  Layer 1 - Top Layer w30: C177.2@3590.95,5625 R106.1@3640.95,5625
FB: R105.1 R112.2 U10.19 | length 207.3
  Layer 1 - Top Layer w10: R112.2@3270,5891.38 3301.38,5891.38 3327.17,5865.59 U10.19@3416.57,5865.59
  Layer 1 - Top Layer w30: R112.2@3270,5891.38 R105.1@3270,5941.38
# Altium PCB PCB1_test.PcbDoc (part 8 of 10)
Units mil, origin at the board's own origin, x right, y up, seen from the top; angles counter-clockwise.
Board outline 6690 x 6690 mil, 6 copper layers (Layer 1 - Top Layer, Layer 2 - GND, Layer 3 - PWR, Layer 4 - Signal, Layer 5 - GND, Layer 6 - Bottom Layer), stack 80.244 mil thick; 821 components, 458 nets, 3746 pads, 1527 vias.

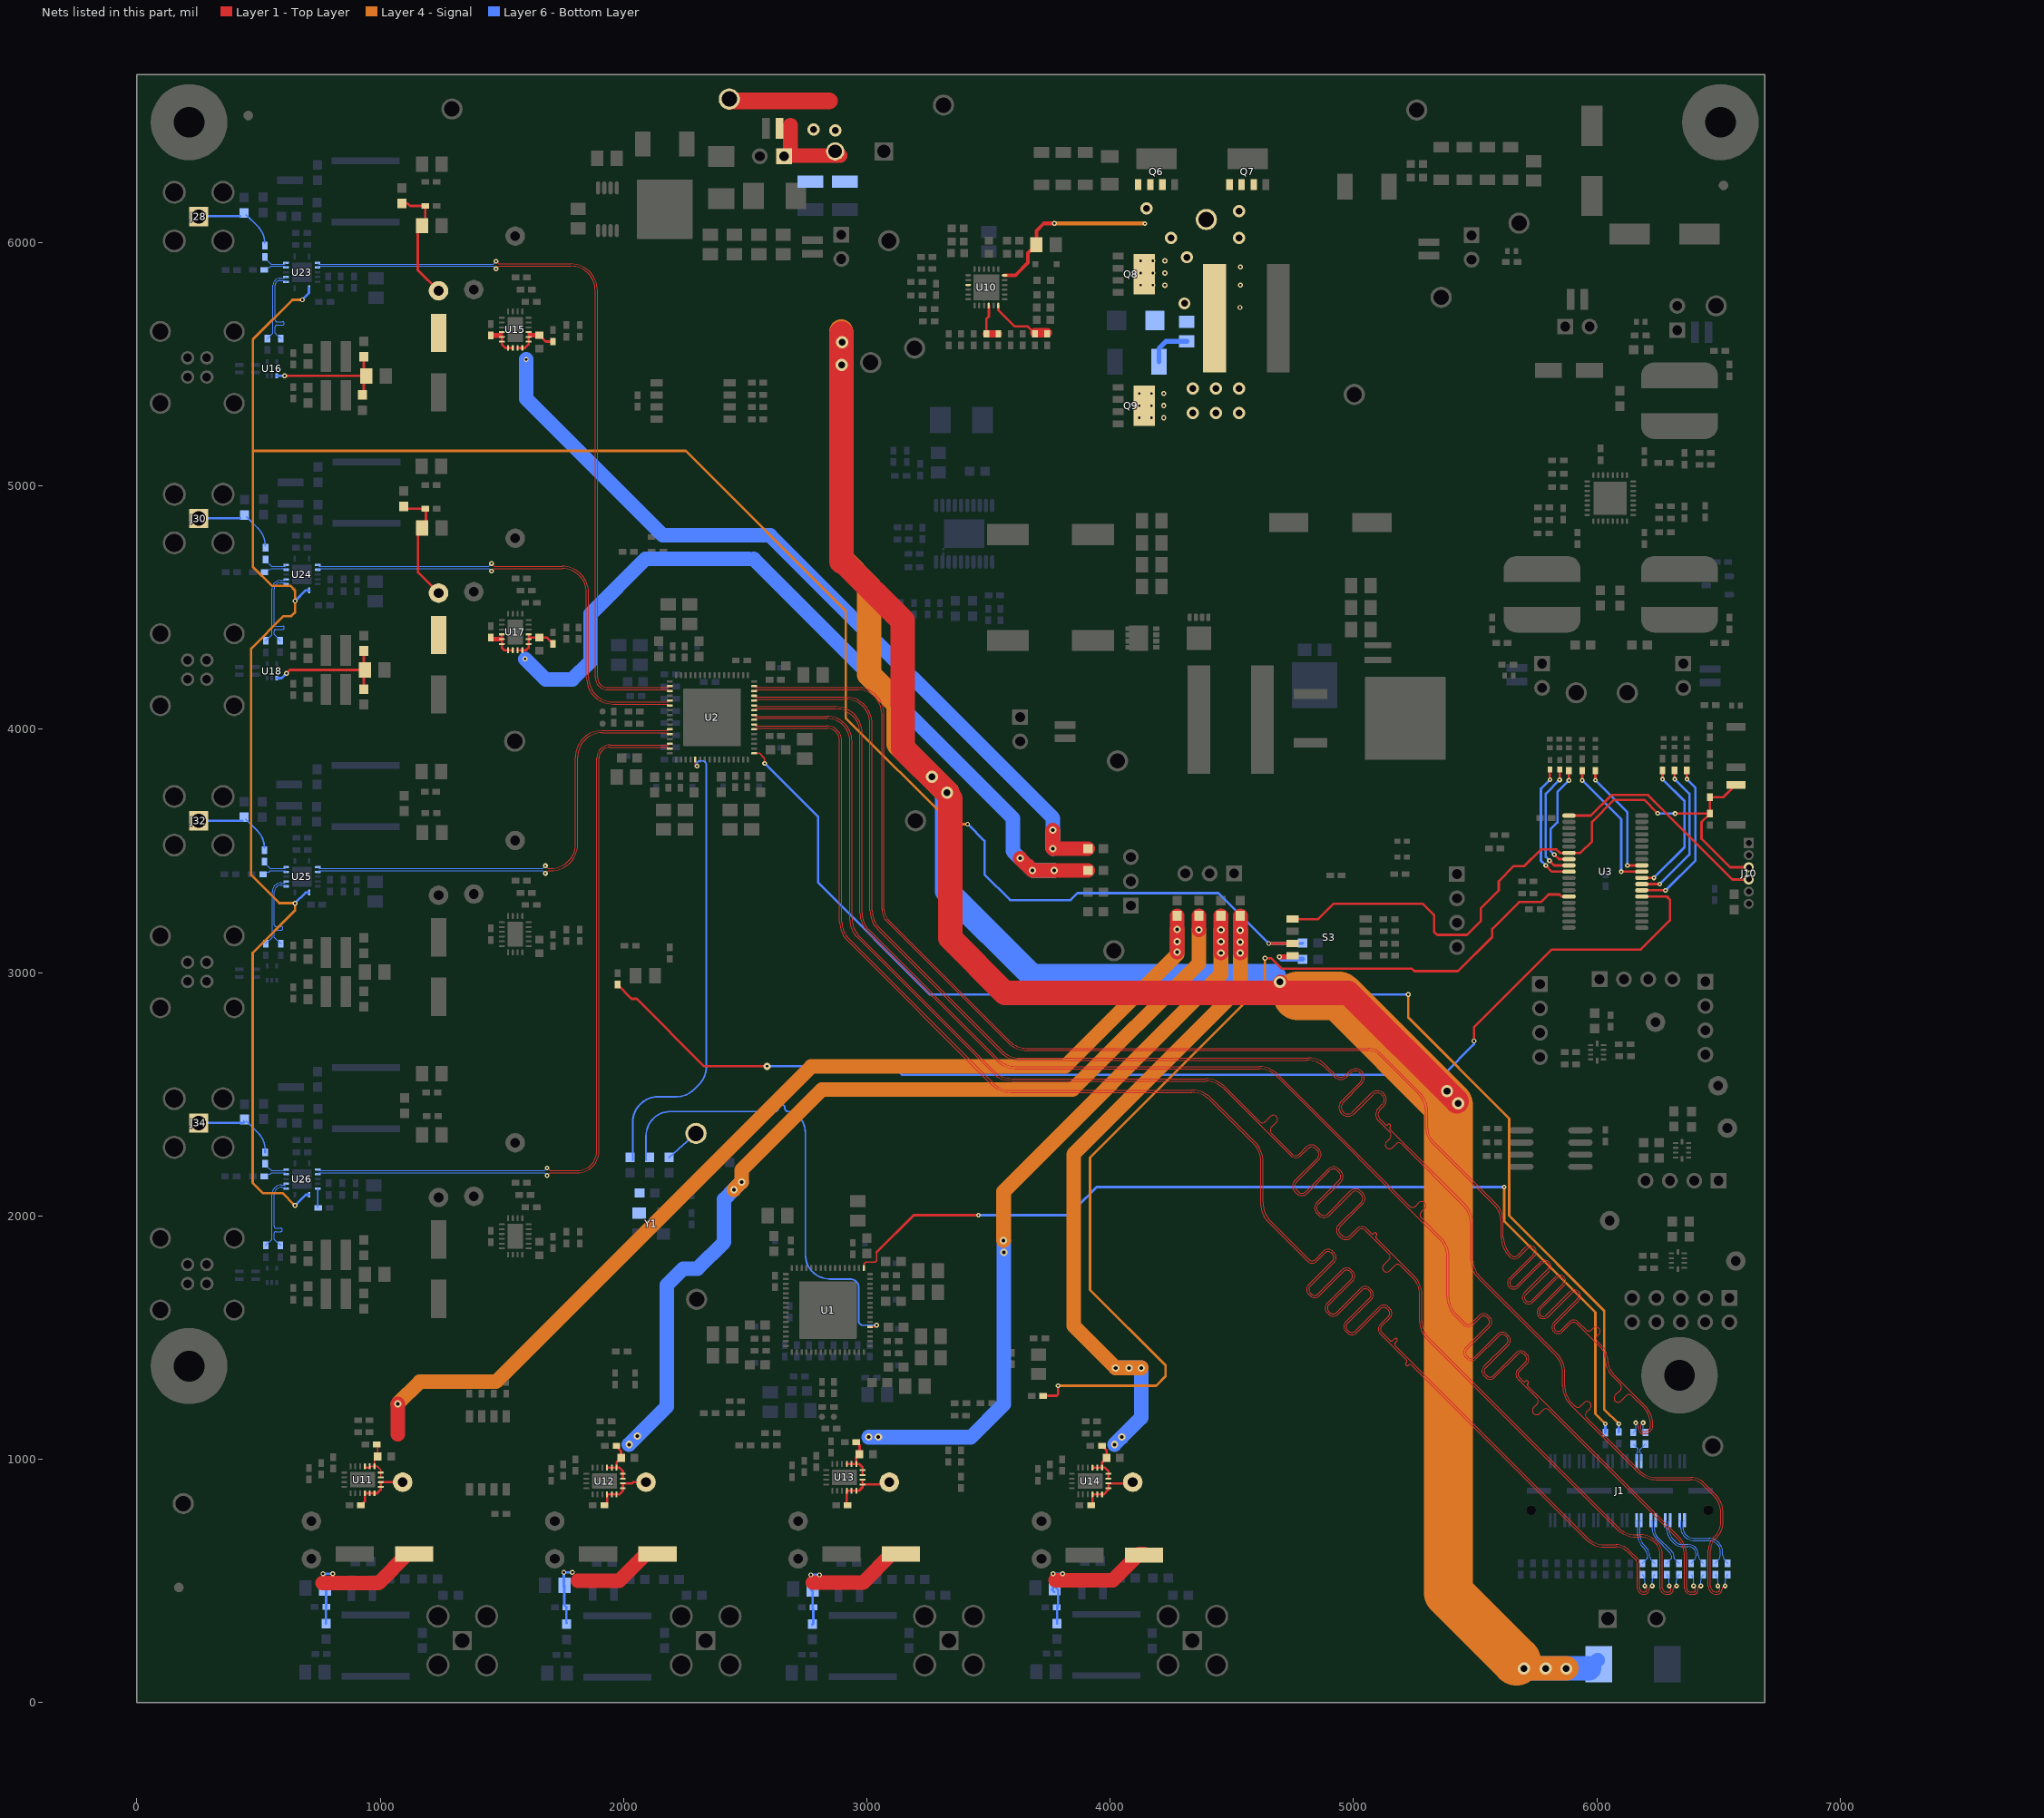
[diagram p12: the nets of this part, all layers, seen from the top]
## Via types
v1: diameter 20, hole 10, Layer 1 - Top Layer to Layer 6 - Bottom Layer, tented both sides, 491 vias
v2: diameter 20, hole 10, Layer 1 - Top Layer to Layer 6 - Bottom Layer, 310 vias
v3: diameter 19.68, hole 7.87, Layer 1 - Top Layer to Layer 6 - Bottom Layer, 282 vias
v4: diameter 19.68, hole 7.87, Layer 1 - Top Layer to Layer 6 - Bottom Layer, tented both sides, 211 vias
v5: diameter 50, hole 28, Layer 1 - Top Layer to Layer 6 - Bottom Layer, 101 vias
v6: diameter 30, hole 15, Layer 1 - Top Layer to Layer 6 - Bottom Layer, 73 vias
v7: diameter 22, hole 10, Layer 1 - Top Layer to Layer 6 - Bottom Layer, 36 vias
v8: diameter 30, hole 10, Layer 1 - Top Layer to Layer 6 - Bottom Layer, 14 vias
v9: diameter 19.68, hole 7.87, Layer 1 - Top Layer to Layer 6 - Bottom Layer, tented bottom, 4 vias
v10: diameter 30, hole 10, Layer 1 - Top Layer to Layer 6 - Bottom Layer, tented both sides, 2 vias
v11: diameter 40, hole 10, Layer 1 - Top Layer to Layer 6 - Bottom Layer, 1 vias
v12: diameter 23.62, hole 7.87, Layer 1 - Top Layer to Layer 6 - Bottom Layer, tented both sides, 1 vias
v13: diameter 23.62, hole 7.87, Layer 1 - Top Layer to Layer 6 - Bottom Layer, 1 vias

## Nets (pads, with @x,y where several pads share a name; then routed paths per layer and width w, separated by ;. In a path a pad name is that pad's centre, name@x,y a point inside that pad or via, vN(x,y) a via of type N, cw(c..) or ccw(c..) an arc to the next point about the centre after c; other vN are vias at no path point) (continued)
NetR247_2: R247.2 U26.6 | length 78.4
  Layer 6 - Bottom Layer w5.9: R247.2@743.96,2034.26 U26.6@743.96,2112.63
NetR251_2: R251.2 TP55.1 | length 147.7
  Layer 6 - Bottom Layer w7: R251.2@2187.79,2240.59 TP55.1@2297.79,2339.09
NetR252_1: R252.1 Y1.3
OSC: R104.1 R111.2 U10.6 | length 260
  Layer 1 - Top Layer w10: U10.6@3540.59,5741.57 3540.59,5722.17 3606.38,5656.38 3659.57,5656.38 R104.1@3690.95,5625
  Layer 1 - Top Layer w40: R104.1@3691,5630 R111.2@3741,5630
PDB_UB960_CAM: R22.2 U3.14 | length 4123.9
  Layer 1 - Top Layer w10: R22.2@3724.86,1261.51 3779.79,1261.51 3786,1267.72 v3(3786,1302.08) ; v2@4637.07,3058.97 4662.33,3058.97 4704.49,3016.81 5239.02,3016.81 5250.04,3005.79 5429.02,3005.79 5570,3146.77 5570,3180 5680,3290 5770,3290 5801.41,3321.41 5846.58,3321.41 5855.35,3312.64 U3.14@5885.39,3312.64
  Layer 4 - Signal w10: v3(3786,1302.08) 4188.77,1302.08 4227.56,1340.87 4227.56,1385.87 3917.32,1696.1 3917.32,2239.3 4635.32,2957.3 v2@4635.32,3058.97
  other v2: 4636.49,3058.97
PDB_UB960_RADAR: R35.2 U3.25 | length 4985.4
  Layer 1 - Top Layer w10: R35.2@1976.42,2949.41 2033.42,2892.41 2054.31,2892.41 2331.72,2615 v8(2590,2615) ; v2(5495,2719.12) 5495,2775 5815,3095 6180,3095 6300,3215 6300,3300 6287.36,3312.64 U3.25@6184.61,3312.64
  Layer 6 - Bottom Layer w10: v8(2590,2615) 3110,2615 3143.75,2581.25 3145.25,2581.25 ; 3145,2580 5369,2580 5495,2706 v2(5495,2719.12)
PG: U10.21
RAD_CLK_N: J1.27 R12.1 | length 197.9
  Layer 6 - Bottom Layer w3.94: J1.27@6182.66,749.54 6177.34,744.23 6177.34,686.83 ccw(c6233.56,686.83) 6193.81,647.08 6200.79,640.09 cw(c6159.39,598.69) 6217.94,598.69 ccw(c6233.15,598.69) 6222.4,587.94 R12.1@6237.23,573.1
RAD_CLK_P: J1.25 R11.2 | length 199.1
  Layer 6 - Bottom Layer w3.94: J1.25@6162.97,749.54 6168.29,744.23 6168.29,686.83 ccw(c6233.56,686.83) 6187.41,640.68 6194.39,633.69 cw(c6159.39,598.69) 6208.89,598.69 cw(c6199.39,598.69) 6206.1,591.97 R11.2@6187.23,573.1
RAD_D0_N: J1.31 R16.1 | length 216.5
  Layer 6 - Bottom Layer w3.94: J1.31@6241.71,749.54 6236.4,744.23 6236.4,711.19 ccw(c6278.85,711.19) 6248.83,681.17 6305.67,624.33 cw(c6278.81,597.48) 6316.79,597.48 ccw(c6326.28,597.48) 6319.57,590.77 R16.1@6337.23,573.1
RAD_D0_P: J1.29 R15.2 | length 216.6
  Layer 6 - Bottom Layer w3.94: J1.29@6222.03,749.54 6227.34,744.23 6227.34,711.19 ccw(c6278.85,711.19) 6242.43,674.76 6299.26,617.93 cw(c6278.81,597.48) 6307.73,597.48 cw(c6298.37,597.48) 6304.99,590.86 R15.2@6287.23,573.1
RAD_D1_N: J1.35 R18.1 | length 262.4
  Layer 6 - Bottom Layer w3.94: J1.35@6300.77,749.54 6295.45,744.23 6295.45,714.8 ccw(c6356.41,714.8) 6313.31,671.69 6325,660 ccw(c6349.14,684.14) 6349.14,650 6375,650 cw(c6375,607.01) 6405.4,637.41 cw(c6377.96,609.97) 6416.76,609.97 6416.76,605 ccw(c6444.34,605) 6424.84,585.5 R18.1@6437.23,573.1
RAD_D1_P: J1.33 R17.2 | length 262.4
  Layer 6 - Bottom Layer w3.94: J1.33@6281.08,749.54 6286.4,744.23 6286.4,714.8 ccw(c6356.41,714.8) 6306.91,665.29 6318.6,653.6 ccw(c6349.14,684.14) 6349.14,640.94 6375,640.94 cw(c6375,607.01) 6398.99,631.01 cw(c6377.96,609.97) 6407.71,609.97 6407.71,605 cw(c6380.12,605) 6399.63,585.5 R17.2@6387.23,573.1
RAD_D2_N: J1.39 R20.1 | length 304.5
  Layer 6 - Bottom Layer w3.94: J1.39@6359.82,749.54 6354.51,744.23 6354.51,715.33 ccw(c6390.33,715.33) 6365,690 ccw(c6401.21,726.21) 6401.21,675 6459.43,675 cw(c6459.43,618.58) 6499.33,658.47 6501.4,656.4 cw(c6463.94,618.94) 6516.92,618.94 6516.92,606.45 ccw(c6556.42,610) 6528.38,581.96 R20.1@6537.23,573.1
RAD_D2_P: J1.37 R19.2 | length 304.4
  Layer 6 - Bottom Layer w3.94: J1.37@6340.14,749.54 6345.45,744.23 6345.45,715.33 ccw(c6390.33,715.33) 6358.6,683.6 ccw(c6401.21,726.21) 6401.21,665.94 6459.43,665.94 cw(c6459.43,618.58) 6492.93,652.07 6495,650 cw(c6464.32,619.32) 6507.71,619.32 6507.71,610.01 cw(c6468.07,610.01) R19.2@6496.1,581.98 ; R19.2@6487.23,573.1 R19.2@6496.11,581.97
RAD_D3_N: J1.28 R14.2 | length 81.8
  Layer 6 - Bottom Layer w3.94: J1.28@6182.66,992.46 6182.66,1022.97 6177.34,1028.28 6177.34,1041.06 R14.2@6199.3,1063.01
RAD_D3_P: J1.26 R13.1 | length 80.6
  Layer 6 - Bottom Layer w3.94: R13.1@6149.3,1063.01 6168.29,1044.02 6168.29,1028.28 6162.97,1022.97 J1.26@6162.97,992.46
RADAR_0_COAX_N: C249.2 U23.12 | length 80.3
  Layer 6 - Bottom Layer w3.94: C249.2@537,5898 546,5898 551,5903 607.73,5903 U23.12@613.04,5897.68
RADAR_0_COAX_P: C245.1 U23.13 | length 84
  Layer 6 - Bottom Layer w3.94: C245.1@537,5926 550.95,5912.05 607.73,5912.05 U23.13@613.04,5917.37
radar_0_coax_se: C245.2 J28.1 L58.1 | length 332.2
  Layer 6 - Bottom Layer w5: J28.1@254.13,6093.66 J28.1@255.79,6092
  Layer 6 - Bottom Layer w6.2: L58.1@449,6115 496.71,6067.29 cw(c426,5996.58) C245.2@526,5996.58
  Layer 6 - Bottom Layer w10: J28.1@240.41,6109.02 L58.1@424.28,6109.02
RADAR_0_HSD_N: C241.2 U23.9 | length 348.6
  Layer 6 - Bottom Layer w3.94: C241.2@591.81,5605.62 568.84,5628.59 568.84,5654.09 cw(c575.81,5654.09) 575.81,5661.06 598.92,5661.06 ccw(c598.92,5668.03) 605.88,5668.03 ccw(c598.92,5668.03) 598.92,5675 575.81,5675 cw(c575.81,5681.97) 568.84,5681.97 568.84,5825.77 cw(c587.01,5825.77) 587.01,5843.94 607.72,5843.94 U23.9@613.04,5838.63
RADAR_0_HSD_P: C244.2 U23.10 | length 300.7
  Layer 6 - Bottom Layer w3.94: C244.2@536.81,5605.62 559.78,5628.59 559.78,5825.77 cw(c587.01,5825.77) 587.01,5853 607.72,5853 U23.10@613.04,5858.31
RADAR_0_N: U2.51 U23.3 | length 3137.1
  Layer 1 - Top Layer w3.94: v4(1476.18,5892.22) 1487.15,5903.2 1783.86,5903.2 cw(c1783.86,5803.2) 1883.86,5803.2 1883.86,4213.39 ccw(c1934.63,4213.39) 1934.63,4162.61 2185.45,4162.61 U2.51@2190.77,4157.3
  Layer 6 - Bottom Layer w3.94: U23.3@742.96,5897.68 748.27,5903 1465.4,5903 v4(1476.18,5892.22)
RADAR_0_P: U2.50 U23.2 | length 3137.3
  Layer 1 - Top Layer w3.94: v4(1476.18,5923.22) 1487.15,5912.25 1783.86,5912.25 cw(c1783.86,5803.2) 1892.91,5803.2 1892.91,4213.39 ccw(c1934.63,4213.39) 1934.63,4171.67 2185.45,4171.67 U2.50@2190.77,4176.99
  Layer 6 - Bottom Layer w3.94: U23.2@742.96,5917.37 748.27,5912.05 1465,5912.05 v4(1476.18,5923.22)
RADAR_1_COAX_N: C264.2 U24.12 | length 92.3
  Layer 6 - Bottom Layer w3.94: C264.2@539,4655.97 548,4655.97 553,4660.97 608.73,4660.97 ; 595.67,4661.06 608.66,4661.06 U24.12@613.98,4655.74
RADAR_1_COAX_P: C260.1 U24.13 | length 96
  Layer 6 - Bottom Layer w3.94: C260.1@539,4683.97 552.95,4670.02 608.73,4670.02 ; 595.67,4670.11 608.66,4670.11 U24.13@613.98,4675.43
radar_1_coax_se: C260.2 J30.1 L69.1 | length 329.9
  Layer 6 - Bottom Layer w6.2: L69.1@451,4872.97 498.71,4825.26 cw(c428,4754.55) C260.2@528,4754.55
  Layer 6 - Bottom Layer w10: J30.1@240.13,4866.97 L69.1@424,4866.97
RADAR_1_HSD_N: C256.2 U24.9 | length 361.2
  Layer 6 - Bottom Layer w3.94: C256.2@589,4364.62 564.03,4389.59 564.03,4403.53 cw(c571,4403.53) 571,4410.5 599.3,4410.5 ccw(c599.3,4417.47) 606.27,4417.47 ccw(c599.3,4417.47) 599.3,4424.44 571,4424.44 cw(c571,4431.41) 564.03,4431.41 564.03,4575.87 cw(c590.16,4575.87) 590.16,4602 608.66,4602 U24.9@613.98,4596.69
RADAR_1_HSD_P: C259.2 U24.10 | length 303.9
  Layer 6 - Bottom Layer w3.94: C259.2@530,4363.62 554.97,4388.59 554.97,4575.87 cw(c590.16,4575.87) 590.16,4611.06 608.66,4611.06 U24.10@613.98,4616.37
RADAR_1_N: U2.54 U24.3 | length 1928.3
  Layer 1 - Top Layer w3.94: v4(1457.45,4650.29) 1468.42,4661.26 1747.64,4661.26 cw(c1747.64,4561.26) 1847.64,4561.26 1847.64,4212.6 ccw(c1956.69,4212.6) 1956.69,4103.54 2185.45,4103.54 U2.54@2190.77,4098.23
  Layer 6 - Bottom Layer w3.94: U24.3@743.9,4655.74 749.21,4661.06 1446.68,4661.06 v4(1457.45,4650.29)
RADAR_1_P: U2.53 U24.2 | length 1928.4
  Layer 1 - Top Layer w3.94: v4(1457.45,4681.29) 1468.42,4670.31 1747.64,4670.31 cw(c1747.64,4561.26) 1856.69,4561.26 1856.69,4212.6 ccw(c1956.69,4212.6) 1956.69,4112.6 2185.45,4112.6 U2.53@2190.77,4117.92
  Layer 6 - Bottom Layer w3.94: U24.2@743.9,4675.43 749.21,4670.11 1446.28,4670.11 v4(1457.45,4681.29)
RADAR_2_COAX_N: C279.2 U25.12 | length 83.8
  Layer 6 - Bottom Layer w3.94: C279.2@534.5,3414 543.5,3414 548.5,3419 608.73,3419 U25.12@614.04,3413.68
RADAR_2_COAX_P: C275.1 U25.13 | length 87.5
  Layer 6 - Bottom Layer w3.94: C275.1@534.5,3442 548.45,3428.05 608.73,3428.05 U25.13@614.04,3433.37
radar_2_coax_se: C275.2 J32.1 L73.1 | length 329.9
  Layer 6 - Bottom Layer w6.2: L73.1@447.79,3630.71 495.5,3583 cw(c424.79,3512.29) C275.2@524.79,3512.29
  Layer 6 - Bottom Layer w10: J32.1@249.63,3624 L73.1@433.5,3624
RADAR_2_HSD_N: C271.2 U25.9 | length 350.3
  Layer 6 - Bottom Layer w3.94: C271.2@592,3118.62 565.53,3145.09 565.53,3168.27 cw(c572.5,3168.27) 572.5,3175.24 594.05,3175.24 ccw(c594.05,3182.2) 601.01,3182.2 ccw(c594.05,3182.2) 594.05,3189.17 572.5,3189.17 cw(c572.5,3196.14) 565.53,3196.14 565.53,3332.56 cw(c592.91,3332.56) 592.91,3359.94 608.72,3359.94 U25.9@614.04,3354.63
RADAR_2_HSD_P: C274.2 U25.10 | length 305.5
  Layer 6 - Bottom Layer w3.94: C274.2@530,3118.62 556.47,3145.09 556.47,3332.56 cw(c592.91,3332.56) 592.91,3369 608.72,3369 U25.10@614.04,3374.31
RADAR_2_N: U2.60 U25.3 | length 1936.7
  Layer 1 - Top Layer w3.94: v4(1679.1,3408.22) 1690.07,3419.2 1702.76,3419.2 ccw(c1702.76,3528.25) 1811.81,3528.25 1811.81,3885.4 cw(c1911.81,3885.4) 1911.81,3985.4 2185.45,3985.4 U2.60@2190.77,3980.09
  Layer 6 - Bottom Layer w3.94: U25.3@743.96,3413.68 749.27,3419 1668.33,3419 v4(1679.1,3408.22)
RADAR_2_P: U2.59 U25.2 | length 1936.9
  Layer 1 - Top Layer w3.94: v4(1679.1,3439.22) 1690.07,3428.25 1702.76,3428.25 ccw(c1702.76,3528.25) 1802.76,3528.25 1802.76,3885.4 cw(c1911.81,3885.4) 1911.81,3994.46 2185.45,3994.46 U2.59@2190.77,3999.78
  Layer 6 - Bottom Layer w3.94: U25.2@743.96,3433.37 749.27,3428.05 1667.93,3428.05 v4(1679.1,3439.22)
RADAR_3_COAX_N: C294.2 U26.12 | length 79.3
  Layer 6 - Bottom Layer w3.94: C294.2@539,2172 548,2172 553,2177 608.73,2177 U26.12@614.04,2171.68
RADAR_3_COAX_P: C290.1 U26.13 | length 83
  Layer 6 - Bottom Layer w3.94: C290.1@539,2200 552.95,2186.05 608.73,2186.05 U26.13@614.04,2191.37
radar_3_coax_se: C290.2 J34.1 L77.1 | length 351.5
  Layer 6 - Bottom Layer w3.94: L77.1@440,2384.35 L77.1@440,2393
  Layer 6 - Bottom Layer w6.2: L77.1@451,2389 498.71,2341.29 cw(c428,2270.58) C290.2@528,2270.58
  Layer 6 - Bottom Layer w10: J34.1@254.13,2382 L77.1@438,2382 ; L77.1@440,2384.35 ccw(c432.34,2395.66) 440.95,2385.05 ccw(c432.34,2395.66) L77.1@442,2386 ; C290.2@528,2261.62 C290.2@528,2270.58
  Layer 6 - Bottom Layer w30: J34.1@254.13,2382 J34.1@255.13,2383
RADAR_3_HSD_N: C286.2 U26.9 | length 344.3
  Layer 6 - Bottom Layer w3.94: C286.2@590,1878.62 564.53,1904.09 564.53,1928.9 cw(c571.5,1928.9) 571.5,1935.87 591.17,1935.87 ccw(c591.17,1942.83) 598.13,1942.83 ccw(c591.17,1942.83) 591.17,1949.8 571.5,1949.8 cw(c571.5,1956.77) 564.53,1956.77 564.53,2088.77 cw(c593.7,2088.77) 593.7,2117.94 608.72,2117.94 U26.9@614.04,2112.63
RADAR_3_HSD_P: C289.2 U26.10 | length 303.3
  Layer 6 - Bottom Layer w3.94: C289.2@530,1878.62 555.47,1904.1 555.47,2088.77 cw(c593.7,2088.77) 593.7,2127 608.72,2127 U26.10@614.04,2132.31
RADAR_3_N: U2.63 U26.3 | length 3151.6
  Layer 1 - Top Layer w3.94: v4(1686.28,2166.22) 1697.25,2177.2 1809.87,2177.2 ccw(c1809.87,2266.93) 1899.61,2266.93 1899.61,3881.5 cw(c1944.44,3881.5) 1944.44,3926.33 2185.45,3926.33 U2.63@2190.77,3921.02
  Layer 6 - Bottom Layer w3.94: U26.3@743.96,2171.68 749.27,2177 1675.5,2177 v4(1686.28,2166.22)
RADAR_3_P: U2.62 U26.2 | length 3151.8
  Layer 1 - Top Layer w3.94: v4(1686.28,2197.22) 1697.25,2186.25 1809.87,2186.25 ccw(c1809.87,2266.93) 1890.55,2266.93 1890.55,3881.5 cw(c1944.44,3881.5) 1944.44,3935.39 2185.45,3935.39 U2.62@2190.77,3940.71
  Layer 6 - Bottom Layer w3.94: U26.2@743.96,2191.37 749.27,2186.05 1675.1,2186.05 v4(1686.28,2197.22)
RADAR_COAX_SEL: R233.2 S3.3 U23.7 U24.7 U25.7 U26.7 | length 10244.9
  Layer 1 - Top Layer w10: v2(4651.51,3120) S3.3@4749.14,3120
  Layer 4 - Signal w10: v2(650,2043) 598.91,2094.09 517.91,2094.09 476,2136 476,3081 650,3255 v2(650,3285) 649,3286 585.36,3286 470,3401.36 470,4331.96 603.04,4465 635.02,4465 650.39,4480.38 v2(650.39,4527.26) 650.39,4570.12 630.52,4590 554.88,4590 477.12,4667.76 477.12,5143.97 ; v2(680,5765) 639.53,5765 477.12,5602.59 477.12,5143.97 ; v2(3413.84,3610) 3350,3610 2912.99,4047.01 2912.99,4487.01 2256.03,5143.97 477.12,5143.97
  Layer 6 - Bottom Layer w10: v2(650,2043) 694.04,2087.04 U26.7@708.53,2087.04 ; v2(650,3285) 694.04,3329.04 U25.7@708.53,3329.04 ; v2(650.39,4527.26) 694.43,4571.3 U24.7@708.93,4571.3 ; v2(680,5765) 707.53,5792.53 U23.7@707.53,5813.04 ; v2@3413.84,3609.88 v2(3413.84,3610) ; v2@3415.52,3609.88 3483.61,3541.8 3483.61,3403.43 3589.03,3298.01 3837.21,3298.01 3865.76,3326.56 4444.95,3326.56 v2(4651.51,3120) 4787.46,3120 4788.48,3118.97 R233.2@4791.2,3121.69
RADAR_CSI0_CLK_N: R12.2 U2.22 | length 7063.5
  Layer 1 - Top Layer w3.94: U2.22@2537.23,3999.78 2542.55,4005.09 2834.65,4005.09 cw(c2834.65,3951.55) 2888.19,3951.55 2888.19,3209.18 ccw(c2997.24,3209.18) 2920.13,3132.06 3512.31,2539.89 ccw(c3589.42,2617) 3589.42,2507.94 4336.46,2507.94 cw(c4336.46,2407.94) 4407.17,2478.66 4589.81,2296.02 cw(c4519.09,2225.31) 4619.09,2225.31 4619.09,2047.33 ccw(c4719.09,2047.33) 4648.38,1976.62 4811.39,1813.61 ccw(c4829.85,1832.06) 4848.31,1813.61 4883.32,1848.62 cw(c4895.37,1836.57) 4907.43,1848.62 4915.06,1840.99 cw(c4903,1828.94) 4920.05,1828.94 cw(c4903,1828.94) 4915.06,1816.88 4814.52,1716.35 ccw(c4832.98,1697.89) 4814.52,1679.43 4822.15,1671.8 ccw(c4840.6,1690.26) 4859.06,1671.8 4959.6,1772.34 cw(c4971.65,1760.29) 4983.71,1772.34 4991.33,1764.71 cw(c4979.28,1752.66) 4996.33,1752.66 cw(c4979.28,1752.66) 4991.33,1740.61 4890.8,1640.07 ccw(c4909.25,1621.61) 4890.8,1603.15 4898.43,1595.53 ccw(c4916.88,1613.98) 4935.34,1595.53 5035.88,1696.06 cw(c5047.93,1684.01) 5059.99,1696.06 5067.61,1688.44 cw(c5055.56,1676.38) 5072.61,1676.38 cw(c5055.56,1676.38) 5067.61,1664.33 4967.08,1563.79 ccw(c4985.53,1545.33) 4967.08,1526.88 4974.7,1519.25 ccw(c4993.16,1537.7) 5011.62,1519.25 5112.15,1619.78 cw(c5124.21,1607.73) 5136.26,1619.78 5143.89,1612.16 cw(c5131.84,1600.1) 5148.88,1600.1 cw(c5131.84,1600.1) 5143.89,1588.05 5108.88,1553.04 ccw(c5127.34,1534.58) 5108.88,1516.12 5217.53,1407.47 cw(c5212.6,1402.54) 5217.53,1397.61 5216.12,1396.2 ccw(c5221.05,1391.28) 5216.12,1386.35 ccw(c5221.05,1391.28) 5225.98,1386.35 5227.39,1387.76 cw(c5232.31,1382.83) 5237.24,1387.76 5953.49,671.51 ccw(c6030.61,748.62) 6030.61,639.57 6077.76,639.57 cw(c6077.76,570.18) 6126.82,619.24 6159.45,586.61 cw(c6144.65,571.81) 6165.58,571.81 6165.58,472.02 ccw(c6191.65,472.02) 6191.65,445.94 6195,445.94 ccw(c6195,465) 6214.06,465 6214.06,466.55 cw(c6227.23,466.55) v3(6227.23,479.73)
  Layer 6 - Bottom Layer w3.94: v3(6227.23,479.73) 6227.23,501.72 cw(c6261.38,501.72) R12.2@6237.23,525.86
RADAR_CSI0_CLK_P: R11.1 U2.23 | length 7063.5
  Layer 1 - Top Layer w3.94: U2.23@2537.23,4019.47 2542.55,4014.15 2834.65,4014.15 cw(c2834.65,3951.55) 2897.24,3951.55 2897.24,3209.18 ccw(c2997.24,3209.18) 2926.53,3138.47 3518.71,2546.29 ccw(c3589.42,2617) 3589.42,2517 4336.46,2517 cw(c4336.46,2407.94) 4413.57,2485.06 4596.21,2302.42 cw(c4519.09,2225.31) 4628.15,2225.31 4628.15,2054.83 ccw(c4737.2,2054.83) 4660.09,1977.71 4817.8,1820.01 ccw(c4829.85,1832.06) 4841.9,1820.01 4876.92,1855.02 cw(c4895.37,1836.57) 4913.83,1855.02 4921.46,1847.4 cw(c4903,1828.94) 4929.1,1828.94 cw(c4903,1828.94) 4921.46,1810.48 4820.92,1709.94 ccw(c4832.98,1697.89) 4820.92,1685.84 4828.55,1678.21 ccw(c4840.6,1690.26) 4852.66,1678.21 4953.2,1778.74 cw(c4971.65,1760.29) 4990.11,1778.74 4997.74,1771.12 cw(c4979.28,1752.66) 5005.38,1752.66 cw(c4979.28,1752.66) 4997.74,1734.2 4897.2,1633.67 ccw(c4909.25,1621.61) 4897.2,1609.56 4904.83,1601.93 ccw(c4916.88,1613.98) 4928.94,1601.93 5029.47,1702.47 cw(c5047.93,1684.01) 5066.39,1702.47 5074.02,1694.84 cw(c5055.56,1676.38) 5081.66,1676.38 cw(c5055.56,1676.38) 5074.02,1657.92 4973.48,1557.39 ccw(c4985.53,1545.33) 4973.48,1533.28 4981.11,1525.65 ccw(c4993.16,1537.7) 5005.21,1525.65 5105.75,1626.19 cw(c5124.21,1607.73) 5142.67,1626.19 5150.29,1618.56 cw(c5131.84,1600.1) 5157.94,1600.1 cw(c5131.84,1600.1) 5150.29,1581.65 5115.28,1546.63 ccw(c5127.34,1534.58) 5115.28,1522.52 5150.59,1487.22 ccw(c5155.52,1492.14) 5160.45,1487.22 5168.25,1495.01 cw(c5173.17,1490.09) 5178.1,1495.01 cw(c5173.17,1490.09) 5178.1,1485.16 5170.3,1477.36 ccw(c5175.23,1472.43) 5170.3,1467.51 5959.89,677.91 ccw(c6030.6,748.62) 6030.6,648.62 6077.76,648.62 cw(c6077.76,570.18) 6133.22,625.65 6165.85,593.02 cw(c6144.65,571.81) 6174.64,571.81 6174.64,472.02 ccw(c6191.65,472.02) 6191.65,455 6195,455 ccw(c6195,465) 6205,465 6205,471.96 ccw(c6197.23,471.96) v3(6197.23,479.73)
  Layer 6 - Bottom Layer w3.94: R11.1@6187.23,525.86 cw(c6163.09,501.72) 6197.23,501.72 v3(6197.23,479.73)
RADAR_CSI0_D0_N: R16.2 U2.24 | length 7049
  Layer 1 - Top Layer w3.94: U2.24@2537.23,4039.16 2542.55,4044.47 2836.22,4044.47 cw(c2836.22,3950.77) 2929.92,3950.77 2929.92,3216.69 ccw(c3029.92,3216.69) 2959.21,3145.98 3518.31,2586.89 ccw(c3595.42,2664) 3595.42,2554.94 4392.81,2554.94 cw(c4392.81,2454.94) 4463.52,2525.66 4741.23,2247.94 ccw(c4762.52,2269.23) 4783.8,2247.94 4812.64,2276.78 cw(c4827.52,2261.89) 4842.41,2276.78 4851.45,2267.73 cw(c4836.57,2252.85) 4857.61,2252.85 cw(c4836.57,2252.85) 4851.45,2237.97 4757.61,2144.13 ccw(c4778.89,2122.84) 4757.61,2101.56 4766.65,2092.51 ccw(c4787.94,2113.8) 4809.22,2092.51 4903.06,2186.36 cw(c4917.94,2171.47) 4932.83,2186.36 4941.87,2177.31 cw(c4926.99,2162.43) 4948.03,2162.43 cw(c4926.99,2162.43) 4941.87,2147.55 4848.03,2053.71 ccw(c4869.31,2032.42) 4848.03,2011.14 4857.07,2002.09 ccw(c4878.36,2023.38) 4899.64,2002.09 4993.48,2095.94 cw(c5008.36,2081.05) 5023.25,2095.94 5032.29,2086.89 cw(c5017.41,2072.01) 5038.45,2072.01 cw(c5017.41,2072.01) 5032.29,2057.13 4938.45,1963.29 ccw(c4959.73,1942) 4938.45,1920.72 4947.49,1911.67 ccw(c4968.78,1932.96) 4990.06,1911.67 5018.9,1940.51 cw(c5033.78,1925.63) 5048.66,1940.51 5145.06,1844.11 cw(c5133.06,1832.11) 5145.06,1820.12 5123.87,1798.92 ccw(c5135.87,1786.93) 5123.87,1774.93 ccw(c5135.87,1786.93) 5147.87,1774.93 5169.06,1796.12 cw(c5181.06,1784.12) 5193.05,1796.12 5242.17,1747.01 cw(c5171.46,1676.3) 5271.46,1676.3 5271.46,1568.72 ccw(c5380.51,1568.72) 5303.4,1491.6 6082.11,712.89 ccw(c6159.23,790) 6159.23,680.94 6177.36,680.94 cw(c6177.36,592.36) 6240,655 6242.32,652.68 cw(c6199.64,610) 6260,610 6260,470.94 ccw(c6285,470.94) 6285,445.94 6295,445.94 ccw(c6295,465) 6314.06,465 6314.06,466.55 cw(c6327.23,466.55) v3(6327.23,479.73)
  Layer 6 - Bottom Layer w3.94: v3(6327.23,479.73) 6327.23,501.72 cw(c6361.38,501.72) R16.2@6337.23,525.86
RADAR_CSI0_D0_P: R15.1 U2.25 | length 7049
  Layer 1 - Top Layer w3.94: U2.25@2537.23,4058.85 2542.55,4053.53 2836.22,4053.53 cw(c2836.22,3950.77) 2938.98,3950.77 2938.98,3224.2 ccw(c3048.03,3224.2) 2970.92,3147.08 3524.71,2593.29 ccw(c3595.42,2664) 3595.42,2564 4392.81,2564 cw(c4392.81,2454.94) 4469.92,2532.06 4614.18,2387.8 ccw(c4626.18,2399.79) 4638.18,2387.8 4658.94,2408.56 cw(c4670.94,2396.56) 4682.94,2408.56 cw(c4670.94,2396.56) 4682.94,2384.56 4662.18,2363.8 ccw(c4674.18,2351.8) 4662.18,2339.8 4747.64,2254.34 ccw(c4762.52,2269.23) 4777.4,2254.34 4806.24,2283.18 cw(c4827.52,2261.89) 4848.81,2283.18 4857.85,2274.14 cw(c4836.57,2252.85) 4866.67,2252.85 cw(c4836.57,2252.85) 4857.85,2231.57 4764.01,2137.72 ccw(c4778.89,2122.84) 4764.01,2107.96 4773.05,2098.92 ccw(c4787.94,2113.8) 4802.82,2098.92 4896.66,2192.76 cw(c4917.94,2171.47) 4939.23,2192.76 4948.27,2183.72 cw(c4926.99,2162.43) 4957.09,2162.43 cw(c4926.99,2162.43) 4948.27,2141.15 4854.43,2047.3 ccw(c4869.31,2032.42) 4854.43,2017.54 4863.47,2008.5 ccw(c4878.36,2023.38) 4893.24,2008.5 4987.08,2102.34 cw(c5008.36,2081.05) 5029.65,2102.34 5038.69,2093.3 cw(c5017.41,2072.01) 5047.51,2072.01 cw(c5017.41,2072.01) 5038.69,2050.72 4944.85,1956.88 ccw(c4959.73,1942) 4944.85,1927.12 4953.89,1918.08 ccw(c4968.78,1932.96) 4983.66,1918.08 5012.5,1946.91 cw(c5033.78,1925.63) 5055.07,1946.91 5073.82,1928.15 5074.81,1927.17 ccw(c5078.75,1931.11) 5082.69,1927.17 5085.02,1929.5 cw(c5088.96,1925.55) 5092.9,1929.5 5094.88,1927.53 ; 5094.88,1927.53 cw(c5090.93,1923.58) 5094.88,1919.64 5092.55,1917.31 ccw(c5096.49,1913.37) 5092.55,1909.43 5186.03,1815.95 5248.57,1753.41 cw(c5171.46,1676.3) 5280.51,1676.3 5280.51,1568.72 ccw(c5380.51,1568.72) 5309.8,1498 6088.52,719.29 ccw(c6159.23,790) 6159.23,690 6177.36,690 cw(c6177.36,592.36) 6246.4,661.4 6248.73,659.08 cw(c6199.64,610) 6269.06,610 6269.06,470.94 ccw(c6285,470.94) 6285,455 6295,455 ccw(c6295,465) 6305,465 6305,471.96 ccw(c6297.23,471.96) v3(6297.23,479.73)
  Layer 6 - Bottom Layer w3.94: R15.1@6287.23,525.86 cw(c6263.09,501.72) 6297.23,501.72 v3(6297.23,479.73)
RADAR_CSI0_D1_N: R18.2 U2.26 | length 7031.9
  Layer 1 - Top Layer w3.94: U2.26@2537.23,4078.54 2542.55,4083.85 2871.65,4083.85 cw(c2871.65,3983.85) 2971.65,3983.85 2971.65,3244.71 ccw(c3080.71,3244.71) 3003.6,3167.6 3534.13,2637.06 ccw(c3611.25,2714.17) 3611.25,2605.12 4611.33,2605.12 cw(c4611.33,2505.12) 4682.05,2575.83 5354.37,1903.5 cw(c5283.66,1832.79) 5383.66,1832.79 5383.66,1666.51 ccw(c5492.72,1666.51) 5415.6,1589.4 5453.21,1551.79 ccw(c5471.67,1570.25) 5490.12,1551.79 5522.68,1584.35 cw(c5534.74,1572.29) 5546.79,1584.35 5554.42,1576.72 cw(c5542.36,1564.67) 5559.41,1564.67 cw(c5542.36,1564.67) 5554.42,1552.61 5458.79,1456.99 ccw(c5477.25,1438.53) 5458.79,1420.07 5466.42,1412.44 ccw(c5484.88,1430.9) 5503.33,1412.44 5598.96,1508.07 cw(c5611.01,1496.02) 5623.07,1508.07 5630.7,1500.44 cw(c5618.64,1488.39) 5635.69,1488.39 cw(c5618.64,1488.39) 5630.7,1476.33 5535.07,1380.71 ccw(c5553.53,1362.25) 5535.07,1343.79 5542.7,1336.16 ccw(c5561.15,1354.62) 5579.61,1336.16 5675.24,1431.79 cw(c5687.29,1419.74) 5699.35,1431.79 5706.97,1424.16 cw(c5694.92,1412.11) 5711.97,1412.11 cw(c5694.92,1412.11) 5706.97,1400.06 5674.42,1367.5 ccw(c5692.87,1349.04) 5674.42,1330.58 5754.39,1250.61 cw(c5742.39,1238.61) 5754.39,1226.61 5739.96,1212.18 ccw(c5751.96,1200.18) 5739.96,1188.19 ccw(c5751.96,1200.18) 5763.96,1188.19 5778.39,1202.62 cw(c5790.39,1190.62) 5802.38,1202.62 6330.71,674.29 cw(c6260,603.58) 6360,603.58 6360,470.94 ccw(c6385,470.94) 6385,445.94 6400,445.94 ccw(c6400,460) 6414.06,460 6414.06,466.55 cw(c6423.69,466.55) 6423.69,476.18 v3(6427.23,479.73)
  Layer 6 - Bottom Layer w3.94: v3(6427.23,479.73) 6427.23,501.72 cw(c6461.38,501.72) R18.2@6437.23,525.86
RADAR_CSI0_D1_P: R17.1 U2.27 | length 7031.9
  Layer 1 - Top Layer w3.94: U2.27@2537.23,4098.23 2542.55,4092.91 2871.65,4092.91 cw(c2871.65,3983.85) 2980.71,3983.85 2980.71,3244.71 ccw(c3080.71,3244.71) 3010,3174 3540.54,2643.46 ccw(c3611.25,2714.17) 3611.25,2614.17 4611.33,2614.17 cw(c4611.33,2505.12) 4688.45,2582.23 5230.32,2040.36 ccw(c5242.32,2052.36) 5254.32,2040.36 5268.32,2054.36 cw(c5280.32,2042.36) 5292.31,2054.36 cw(c5280.32,2042.36) 5292.31,2030.36 5278.31,2016.36 ccw(c5290.31,2004.36) 5278.31,1992.37 5360.78,1909.9 cw(c5283.66,1832.79) 5392.72,1832.79 5392.72,1666.51 ccw(c5492.72,1666.51) 5422.01,1595.8 5459.61,1558.19 ccw(c5471.67,1570.25) 5483.72,1558.19 5516.28,1590.75 cw(c5534.74,1572.29) 5553.19,1590.75 5560.82,1583.12 cw(c5542.36,1564.67) 5568.47,1564.67 cw(c5542.36,1564.67) 5560.82,1546.21 5465.19,1450.58 ccw(c5477.25,1438.53) 5465.19,1426.47 5472.82,1418.85 ccw(c5484.88,1430.9) 5496.93,1418.85 5592.56,1514.47 cw(c5611.01,1496.02) 5629.47,1514.47 5637.1,1506.85 cw(c5618.64,1488.39) 5644.74,1488.39 cw(c5618.64,1488.39) 5637.1,1469.93 5541.47,1374.3 ccw(c5553.53,1362.25) 5541.47,1350.2 5549.1,1342.57 ccw(c5561.15,1354.62) 5573.21,1342.57 5668.84,1438.2 cw(c5687.29,1419.74) 5705.75,1438.2 5713.38,1430.57 cw(c5694.92,1412.11) 5721.02,1412.11 cw(c5694.92,1412.11) 5713.38,1393.65 5680.82,1361.09 ccw(c5692.87,1349.04) 5680.82,1336.99 5697.93,1319.88 ; 5697.93,1319.88 ccw(c5701.87,1323.82) 5705.81,1319.88 5707.66,1321.74 cw(c5711.61,1317.79) 5715.55,1321.74 5717.52,1319.76 cw(c5713.58,1315.82) 5717.52,1311.88 5715.66,1310.03 ccw(c5719.61,1306.08) 5715.66,1302.14 5774.44,1243.36 6337.11,680.69 cw(c6260,603.58) 6369.06,603.58 6369.06,470.94 ccw(c6385,470.94) 6385,455 6400,455 ccw(c6400,460) 6405,460 6405,471.96 ccw(c6397.23,471.96) v3(6397.23,479.73)
  Layer 6 - Bottom Layer w3.94: R17.1@6387.23,525.86 cw(c6363.09,501.72) 6397.23,501.72 v3(6397.23,479.73)
RADAR_CSI0_D2_N: R20.2 U2.28 | length 7010.9
  Layer 1 - Top Layer w3.94: U2.28@2537.23,4117.92 2542.55,4123.23 2912.99,4123.23 cw(c2912.99,4023.23) 3012.99,4023.23 3012.99,3254.37 ccw(c3122.05,3254.37) 3044.93,3177.26 3550.31,2671.89 ccw(c3627.42,2749) 3627.42,2639.94 4807.99,2639.94 cw(c4807.99,2530.89) 4885.11,2608 4921.26,2571.85 ccw(c4947.07,2597.66) 4972.87,2571.85 4988.36,2587.34 cw(c5007.77,2567.94) 5027.17,2587.34 ; 5027.19,2587.32 cw(c5007.77,2567.94) 5035.21,2567.94 cw(c5007.77,2567.94) 5027.17,2548.53 4950.98,2472.34 ccw(c4976.79,2446.54) 5002.59,2420.73 5078.78,2496.92 cw(c5098.19,2477.52) 5117.59,2496.92 cw(c5098.19,2477.52) 5125.63,2477.52 cw(c5098.19,2477.52) 5117.59,2458.11 5102.1,2442.62 ccw(c5127.91,2416.82) 5102.1,2391.01 5149.84,2343.27 cw(c5137.84,2331.27) 5149.84,2319.27 5135.39,2304.82 ccw(c5147.39,2292.82) 5135.39,2280.83 ccw(c5147.39,2292.82) 5159.39,2280.83 5173.84,2295.28 cw(c5185.84,2283.28) 5197.83,2295.28 5449.36,2043.75 cw(c5372.24,1966.64) 5481.3,1966.64 5481.3,1820.75 ccw(c5590.35,1820.75) 5513.24,1743.64 5829.96,1426.92 cw(c5759.25,1356.21) 5859.25,1356.21 5859.25,1301.42 ccw(c5968.31,1301.42) 5891.19,1224.31 6167.61,947.89 ccw(c6244.73,1025) 6244.73,915.94 6385,915.94 cw(c6385,845.8) 6434.6,895.4 6480.71,849.29 cw(c6410,778.58) 6510,778.58 6510,741.42 cw(c6434.14,741.42) 6487.78,687.78 6479.99,679.99 ccw(c6533.89,626.11) 6457.68,626.11 6457.68,478.27 ccw(c6490,478.27) 6490,445.94 6495,445.94 ccw(c6495,465) 6514.06,465 6514.06,466.55 cw(c6527.23,466.55) v3(6527.23,479.73)
  Layer 6 - Bottom Layer w3.94: v3(6527.23,479.73) 6527.23,501.72 cw(c6561.38,501.72) R20.2@6537.23,525.86
RADAR_CSI0_D2_P: R19.1 U2.29 | length 7010.9
  Layer 1 - Top Layer w3.94: U2.29@2537.23,4137.61 2542.55,4132.29 2912.99,4132.29 cw(c2912.99,4023.23) 3022.05,4023.23 3022.05,3254.37 ccw(c3122.05,3254.37) 3051.34,3183.66 3556.71,2678.29 ccw(c3627.42,2749) 3627.42,2649 4815.49,2649 cw(c4815.49,2549) 4886.21,2619.71 4891.51,2614.41 4927.66,2578.25 ccw(c4947.07,2597.66) 4966.47,2578.25 4981.96,2593.74 cw(c5007.77,2567.94) 5044.26,2567.94 cw(c5007.77,2567.94) 5033.57,2542.13 4957.38,2465.94 ccw(c4976.79,2446.54) 4957.36,2427.15 ; 4957.38,2427.13 ccw(c4976.79,2446.54) 4996.19,2427.13 5072.38,2503.32 cw(c5098.19,2477.52) 5134.68,2477.52 cw(c5098.19,2477.52) 5124,2451.71 5108.5,2436.22 ccw(c5127.91,2416.82) 5108.5,2397.41 5130.91,2375.01 ccw(c5135.84,2379.93) 5140.77,2375.01 5141.14,2375.38 cw(c5146.07,2370.45) 5151,2375.38 cw(c5146.07,2370.45) 5151,2365.53 5150.62,2365.15 ccw(c5155.55,2360.22) 5150.62,2355.3 5306.11,2199.81 5455.76,2050.16 5461.06,2044.85 cw(c5390.35,1974.14) 5490.35,1974.14 5490.35,1820.75 ccw(c5590.35,1820.75) 5519.64,1750.04 5836.37,1433.32 cw(c5759.25,1356.21) 5868.31,1356.21 5868.31,1301.42 ccw(c5968.31,1301.42) 5897.6,1230.71 5909.45,1218.86 ccw(c5921.45,1230.86) 5933.45,1218.86 5947.44,1232.85 cw(c5959.44,1220.85) 5971.44,1232.85 cw(c5959.44,1220.85) 5971.44,1208.85 5957.36,1194.78 ccw(c5969.28,1182.86) 5957.36,1170.94 6174.02,954.29 ccw(c6244.73,1025) 6244.73,925 6385,925 cw(c6385,845.8) 6441,901.8 6487.11,855.69 cw(c6410,778.58) 6519.06,778.58 6519.06,741.42 cw(c6434.14,741.42) 6494.18,681.38 6486.4,673.6 ccw(c6533.89,626.11) 6466.73,626.11 6466.73,478.27 ccw(c6490,478.27) 6490,455 6495,455 ccw(c6495,465) 6505,465 6505,471.96 ccw(c6497.23,471.96) v3(6497.23,479.73)
  Layer 6 - Bottom Layer w3.94: R19.1@6487.23,525.86 cw(c6463.09,501.72) 6497.23,501.72 v3(6497.23,479.73)
RADAR_CSI0_D3_N: R14.1 U2.30 | length 7148.2
  Layer 1 - Top Layer w3.94: U2.30@2537.23,4157.3 2542.55,4162.61 2961.81,4162.61 cw(c2961.81,4062.61) 3061.81,4062.61 3061.81,3260 ccw(c3133.31,3260) 3082.75,3209.44 3580.31,2711.89 ccw(c3657.42,2789) 3657.42,2679.94 5060.63,2679.94 cw(c5060.63,2616.8) 5105.28,2661.45 5266.97,2499.76 cw(c5196.26,2429.05) 5296.26,2429.05 5296.26,2361.22 ccw(c5379.45,2361.22) 5320.63,2302.4 5577.01,2046.01 cw(c5506.3,1975.3) 5606.3,1975.3 5606.3,1913.27 ccw(c5715.35,1913.27) 5638.24,1836.16 5642.83,1831.56 ccw(c5661.24,1849.97) 5679.64,1831.56 5712.88,1864.8 cw(c5724.88,1852.81) 5736.85,1864.82 cw(c5724.88,1852.81) 5741.84,1852.81 cw(c5724.88,1852.81) 5736.87,1840.81 5639.99,1743.93 ccw(c5658.4,1725.53) 5639.99,1707.13 ccw(c5658.4,1725.53) 5676.8,1707.13 5773.68,1804 cw(c5785.68,1792.01) 5797.65,1804.02 cw(c5785.68,1792.01) 5802.64,1792.01 cw(c5785.68,1792.01) 5797.67,1780.01 5700.79,1683.13 ccw(c5719.2,1664.73) 5700.79,1646.33 ccw(c5719.2,1664.73) 5737.6,1646.33 5834.48,1743.2 cw(c5846.48,1731.21) 5858.45,1743.22 cw(c5846.48,1731.21) 5863.44,1731.21 cw(c5846.48,1731.21) 5858.47,1719.21 5761.59,1622.33 ccw(c5780,1603.93) 5761.59,1585.53 ccw(c5780,1603.93) 5798.4,1585.53 5895.28,1682.4 cw(c5907.28,1670.41) 5919.27,1682.4 cw(c5907.28,1670.41) 5924.24,1670.41 cw(c5907.28,1670.41) 5919.27,1658.41 5822.39,1561.53 ccw(c5840.8,1543.13) 5822.39,1524.73 ccw(c5840.8,1543.13) 5859.2,1524.73 5892.44,1557.96 cw(c5904.44,1545.97) 5916.43,1557.96 6018.52,1455.88 cw(c5982.92,1420.28) 6033.27,1420.28 6033.27,1416.9 ccw(c6142.32,1416.9) 6065.21,1339.79 6096.32,1308.68 cw(c6084.32,1296.68) 6096.32,1284.68 6075.18,1263.54 ccw(c6087.18,1251.54) 6075.18,1239.54 ccw(c6087.18,1251.54) 6099.18,1239.54 6120.32,1260.69 cw(c6132.32,1248.69) 6144.31,1260.69 6191.66,1213.34 cw(c6120.95,1142.63) 6220.95,1142.63 6220.95,1135.84 cw(c6209.14,1135.84) 6217.49,1127.49 6205,1115 6185,1115 cw(c6199.98,1129.98) 6178.8,1129.98 6178.8,1134.63 cw(c6188.86,1134.63) 6181.74,1141.74 v3(6190,1150)
  Layer 6 - Bottom Layer w3.94: v3(6190,1150) 6190,1119.55 R14.1@6199.3,1110.25
RADAR_CSI0_D3_P: R13.2 U2.31 | length 7148.2
  Layer 1 - Top Layer w3.94: U2.31@2537.23,4176.99 2542.55,4171.67 2961.81,4171.67 cw(c2961.81,4062.61) 3070.87,4062.61 3070.87,3260 ccw(c3133.31,3260) 3089.16,3215.84 3586.71,2718.29 ccw(c3657.42,2789) 3657.42,2689 5060.63,2689 cw(c5060.63,2616.8) 5111.68,2667.85 5273.37,2506.16 cw(c5196.26,2429.05) 5305.31,2429.05 5305.31,2361.22 ccw(c5379.45,2361.22) 5327.03,2308.8 5583.41,2052.41 cw(c5506.3,1975.3) 5615.35,1975.3 5615.35,1913.27 ccw(c5715.35,1913.27) 5644.64,1842.56 5649.24,1837.97 ccw(c5661.24,1849.97) 5673.23,1837.97 5706.47,1871.21 cw(c5724.88,1852.81) 5743.28,1871.21 cw(c5724.88,1852.81) 5750.9,1852.81 cw(c5724.88,1852.81) 5743.28,1834.4 5646.4,1737.53 ccw(c5658.4,1725.53) 5646.38,1713.55 ccw(c5658.4,1725.53) 5670.39,1713.53 5767.27,1810.41 cw(c5785.68,1792.01) 5804.08,1810.41 cw(c5785.68,1792.01) 5811.7,1792.01 cw(c5785.68,1792.01) 5804.08,1773.6 5707.2,1676.73 ccw(c5719.2,1664.73) 5707.18,1652.75 ccw(c5719.2,1664.73) 5731.19,1652.73 5828.07,1749.61 cw(c5846.48,1731.21) 5864.88,1749.61 cw(c5846.48,1731.21) 5872.5,1731.21 cw(c5846.48,1731.21) 5864.88,1712.8 5768,1615.93 ccw(c5780,1603.93) 5768,1591.93 ccw(c5780,1603.93) 5791.99,1591.93 5888.87,1688.81 cw(c5907.28,1670.41) 5925.68,1688.81 cw(c5907.28,1670.41) 5933.3,1670.41 cw(c5907.28,1670.41) 5925.68,1652 5828.8,1555.13 ccw(c5840.8,1543.13) 5828.8,1531.13 ; 5828.82,1531.11 ccw(c5840.8,1543.13) 5852.79,1531.13 5886.03,1564.37 cw(c5904.44,1545.97) 5922.84,1564.37 5954.72,1532.48 ccw(c5966.72,1544.48) 5978.72,1532.48 5984.47,1538.22 ; 5984.47,1538.23 cw(c5996.46,1526.23) 6008.46,1538.23 cw(c5996.46,1526.23) 6008.46,1514.23 6000.98,1506.75 ccw(c6011.25,1496.48) 6000.98,1486.22 6024.92,1462.28 cw(c5982.92,1420.28) 6042.32,1420.28 6042.32,1416.9 ccw(c6142.32,1416.9) 6071.61,1346.19 6198.06,1219.74 cw(c6120.95,1142.63) 6230.01,1142.63 6230.01,1135.84 cw(c6209.14,1135.84) 6223.9,1121.09 6211.4,1108.6 cw(c6205,1115) 6205,1105.94 6185,1105.94 cw(c6185,1115) 6178.6,1108.6 cw(c6199.98,1129.98) 6169.74,1129.98 6169.74,1134.63 ccw(c6156.15,1134.63) 6165.76,1144.24 v3(6160,1150)
  Layer 6 - Bottom Layer w3.94: R13.2@6149.3,1110.25 6160,1120.95 v3(6160,1150)
RT: R107.1 R113.2 U10.4 | length 170.8
  Layer 1 - Top Layer w10: R107.1@3490.95,5625 3490.95,5685.95 3501.22,5696.22 U10.4@3501.22,5741.57
  Layer 1 - Top Layer w30: R107.1@3490.95,5625 R113.2@3540.95,5625
SBWTCK1: J10.4 U3.1 | length 917.5
  Layer 1 - Top Layer w10: U3.1@5885.39,3645.32 5975.32,3645.32 6060,3730 6210,3730 6557.19,3382.81 J10.4@6624.02,3382.81
SNUB: C182.1 R122.2 | length 182.2
  Layer 6 - Bottom Layer w20: R122.2@4200.55,5510 4200.55,5565.55 4230,5595 C182.1@4315,5595
SPARE1_UC: R248.2 U3.26 | length 656.1
  Layer 1 - Top Layer w10: U3.26@6184.61,3338.23 v3(6281.77,3338.23) ; R248.2@6369.5,3831.38 6369.5,3795.5 v4(6370,3795)
  Layer 6 - Bottom Layer w10: v3(6281.77,3338.23) 6405,3461.46 6405,3760 v4(6370,3795)
SPARE2_UC: R249.2 U3.27 | length 617
  Layer 1 - Top Layer w10: U3.27@6184.61,3363.82 v3(6258.82,3363.82) ; R249.2@6319.5,3831.38 6319.5,3795.5 v4(6320,3795)
  Layer 6 - Bottom Layer w10: v3(6258.82,3363.82) 6380,3485 6380,3735 v4(6320,3795)
SPARE3_UC: R250.2 U3.28 | length 581.3
  Layer 1 - Top Layer w10: U3.28@6184.61,3389.41 v3(6234.41,3389.41) ; R250.2@6269.5,3831.38 6269.5,3795.5 v4(6270,3795)
  Layer 6 - Bottom Layer w10: v3(6234.41,3389.41) 6360,3515 6360,3705 v4(6270,3795)
SPARE4_UC: R51.2 U3.8 | length 450.5
  Layer 1 - Top Layer w10: v4(5825,3485) 5843.82,3466.18 U3.8@5885.39,3466.18 ; v4(5885,3790) R51.2@5885,3830
  Layer 6 - Bottom Layer w10: v4(5825,3485) 5810,3500 5810,3589.13 5838,3617.13 5838,3743 v4(5885,3790)
SPARE5_UC: R58.2 U3.9 | length 493.2
  Layer 1 - Top Layer w10: v4(5805,3460) 5824.41,3440.59 U3.9@5885.39,3440.59 ; v4(5847,3792) R58.2@5847,3834.94
  Layer 6 - Bottom Layer w10: v4(5805,3460) 5790,3475 5790,3735 v4(5847,3792)
SPARE6_UC: R59.2 U3.10 | length 524.3
  Layer 1 - Top Layer w10: v4(5790,3440) 5815,3415 U3.10@5885.39,3415 ; v4(5807,3793) R59.2@5807,3834.94
  Layer 6 - Bottom Layer w10: v4(5790,3440) 5770,3460 5770,3756 v4(5807,3793)
SPARE7_UC: R60.2 U3.29 | length 565.9
  Layer 1 - Top Layer w10: v4(5940,3790) R60.2@5940,3830 ; v4(6100,3415) U3.29@6184.61,3415
  Layer 6 - Bottom Layer w10: v4(5940,3790) 6100,3630 v4(6100,3415)
SPARE8_UC: R61.2 U3.30 | length 504.1
  Layer 1 - Top Layer w10: v4(5994,3791) R61.2@5994,3830 ; v4(6125,3440) 6125.59,3440.59 U3.30@6184.61,3440.59
  Layer 6 - Bottom Layer w10: v4(5994,3791) 6125,3660 v4(6125,3440)
SW: C178.1 C182.2 D8.1 L25.1 Q6.1 Q6.2 Q6.3 Q7.1 Q7.2 Q7.3 Q8.5 Q9.5 TP13.1 U10.12 | length 722.5
  Layer 1 - Top Layer w15: U10.12@3566.18,5865.59 3610.59,5865.59 3662.38,5917.38 3662.38,5957.38 C178.1@3696.38,5991.38 3696.38,6048.38 3727,6079 v4(3771,6079)
  Layer 4 - Signal w15: v4(3771,6079) 4142,6079 v4(4143,6078)
  other v2: 4533,5733 4535,5825 4535,5900
  other v5: 4340,5300 4435,5300 4530,5300 4340,5400 4435,5400 4530,5400 4305,5750 4315,5940 4250,6020 4530,6020 4530,6130 4150,6140
  other v7: 4120,5280 4170,5280 4220,5280 4120,5330 4170,5330 4220,5330 4120,5380 4170,5380 4220,5380 4125,5825 4175,5825 4225,5825 4125,5875 4175,5875 4225,5875 4125,5925 4175,5925 4225,5925
SW_0: R230.2 S3.4 | length 156.5
  Layer 1 - Top Layer w20: v2(4695,3065) 4744.14,3065 S3.4@4749.14,3070
  Layer 6 - Bottom Layer w20: v2(4695,3065) 4705,3055 R230.2@4791.2,3055
SYNC_CAMERA: R47.2 U1.17 | length 3982
  Layer 1 - Top Layer w5: U1.17@2987.79,1786.53 2987.79,1802.79 2995,1810 3035,1810 3040,1815 3040,1850
  Layer 1 - Top Layer w10: 3040,1850 3192.95,2002.95 v3(3458.66,2002.95)
  Layer 4 - Signal w10: v3(5619.09,2119.09) 5619.09,1978.5 5994,1603.6 5994,1186.67 v3(6035,1145.67)
  Layer 6 - Bottom Layer w5: 3899.8,2075 3900,2074.8
  Layer 6 - Bottom Layer w10: v3(3458.66,2002.95) 3827.76,2002.95 3899.8,2075 ; 3900,2074.8 3944.29,2119.09 v3(5619.09,2119.09) ; R47.2@6035,1108.62 v3(6035,1145.67)
SYNC_RADAR: R48.2 U2.17 | length 5426.3
  Layer 1 - Top Layer w5: U2.17@2537.23,3901.33 2558.67,3901.33 2580,3880 v3(2580,3860)
  Layer 4 - Signal w5: v3@6090,1143.7 v3(6090,1145.67)
  Layer 4 - Signal w10: v3(5225,2910) 5225,2815 5639.76,2400.24 5639.76,2001.08 6030,1610.84 6030,1205.67 v3(6090,1145.67)
  Layer 6 - Bottom Layer w10: v3(2580,3860) 2800,3640 2800,3370 3260,2910 v3(5225,2910) ; R48.2@6090,1112.24 v3(6090,1145.67)
TDIO1: C124.1 J10.3 R53.1 S1.1 S3.1 U3.7 | length 2754.6
  Layer 1 - Top Layer w10: S3.1@4749.14,3220 4854.19,3220 4917.46,3283.27 5215,3283.27 ; 5216.01,3283.36 5283.38,3283.36 5331.55,3235.18 5331.55,3166.71 5343.27,3155 5466.5,3155 5523,3211.5 5523,3264.11 5597,3338.11 5597,3376 5659,3438 5702,3438 5770,3506 5834,3506 5848.23,3491.77 U3.7@5885.39,3491.77 5931.77,3491.77 5980,3540 5980,3620 6070,3710 6195,3710 v3(6250,3655) ; v4(6321.38,3653.62) C124.1@6465,3653.62 ; S1.1@6570.98,3772.01 6520.35,3721.38 R53.1@6465,3721.38 C124.1@6465,3653.62 ; J10.3@6624.02,3432.81 6547.19,3432.81 6430,3550 6430,3618.62 C124.1@6465,3653.62
  Layer 6 - Bottom Layer w10: v3(6250,3655) 6251.38,3653.62 v4(6321.38,3653.62)
UB960_CLK_CAM: R33.2 U1.5 | length 1947
  Layer 1 - Top Layer w5: U1.5@3013.35,1544.41 3033.4,1544.41 v4(3040.12,1551.13)
  Layer 6 - Bottom Layer w7: R33.2@2092.79,2229.09 2092.79,2329.09 cw(c2192.79,2329.09) 2192.79,2429.09 2622.79,2429.09 ccw(c2622.79,2442.59) 2636.29,2442.59 2636.29,2444.19 cw(c2649.79,2444.19) 2649.79,2457.69 cw(c2649.79,2444.19) 2663.29,2444.19 2663.29,2442.59 ccw(c2676.79,2442.59) 2676.79,2429.09 cw(c2676.79,2370.88) 2717.96,2412.04 2718.27,2411.73 cw(c2647.56,2341.02) 2747.56,2341.02 2747.56,1840.87 ccw(c2847.56,1840.87) 2847.56,1740.87 2932.56,1740.87 cw(c2932.56,1707.13) 2966.3,1707.13 2966.3,1568.44 ccw(c2983.61,1568.44) 2983.61,1551.13 v4(3040.12,1551.13)
UB960_CLK_RADAR: R32.2 U2.5 | length 1919.3
  Layer 1 - Top Layer w5: U2.5@2295.1,3875.77 2295.1,3855.72 v4(2301.82,3849)
  Layer 6 - Bottom Layer w7: R32.2@2037.79,2229.09 2037.79,2386.37 cw(c2137.79,2386.37) 2067.08,2457.08 2070.71,2460.71 cw(c2141.42,2390) 2141.42,2490 2218.58,2490 ccw(c2218.58,2590) 2289.29,2519.29 2310.71,2540.71 ccw(c2240,2611.42) 2340,2611.42 2340,3855 ccw(c2325,3855) 2325,3870 2314.79,3870 ccw(c2314.79,3857.03) 2301.82,3857.03 v4(2301.82,3849)
V_BAT: C130.1 C131.1 D14.1 J12.1 J14.2 R173.1 TP45.1 | length 13522.8
  Layer 1 - Top Layer w10: v5@3323.5,3733 3342.5,3714
  Layer 1 - Top Layer w60: 2686.02,6482.32 2686.02,6357.05 2845.72,6357.19 2851.03,6357.2 2870.02,6357.22 2886.64,6357.23 J14.2@2889.8,6357.23 ; 2896,4689.5 2903.52,4689.5 ; 4697.8,2917.08 4697.8,2959.08 v5@4700.2,2961.48 ; 4835.39,2917.08 4835.39,2928.83 4839.01,2932.44
  Layer 1 - Top Layer w70: TP45.1@2442.36,6582.64 2845.71,6582.64
  Layer 1 - Top Layer w100: 2896,4689.5 2896,5627.5 ; 2903.52,4689.5 3146.87,4446.15 3146.87,4102.07 ; 3148.5,4098.5 3148.5,3921.5 v5(3330,3740) ; 3342.5,3714 3342.5,3141.99 3567.41,2917.08 4697.8,2917.08 4835.39,2917.08 4978.06,2917.08 v5@5424.53,2470.61
  Layer 4 - Signal w100: 2895,5635 2895,4700 3010,4585 3010,4225 3129.77,4105.23 3129.77,3940.23 v5(3330,3740) ; v5(5699.8,140.75) v5@5874.85,140.75
  Layer 4 - Signal w200: 4770.96,2905.12 4939.85,2905.12 5389.76,2455.21 5389.76,450.79 5669.68,170.87
  Layer 6 - Bottom Layer w60: 4671.82,2985.06 v5@4698.27,2958.6 ; D14.1@5968.21,140.75 D14.1@6002.46,175
  Layer 6 - Bottom Layer w100: v5(3330,3740) 3330,3335 3679.94,2985.06 4671.82,2985.06 ; v5(5699.8,140.75) D14.1@5968.21,140.75
  other v5: 5874.46,139.23 5789.3,140.5 5429.57,2462.22 5384.25,2512.57 4697.2,2961.48 3266.97,3805.47 2896.47,5497.19 2899.01,5591.25 2871.05,6460.62 2780.81,6464.43
V_CAM0: C198.1 C199.1 C212.1 L26.2 R138.2 TP16.1 U11.4 U11.5 U11.6 U11.7 U11.8 | length 917.9
  Layer 1 - Top Layer w10: R138.2@921.18,810.87 937.4,827.09 U11.4@937.4,860.75 U11.5@957.08,860.75 U11.6@976.77,860.75 987.44,860.75 1002.36,875.67 U11.7@1002.36,886.34 U11.8@1002.36,906.02 1092.4,906.02 TP16.1@1092.56,905.87
  Layer 1 - Top Layer w60: 762.56,490.87 992.56,490.87 1112.56,610.87 C212.1@1139.61,610.87
  Layer 6 - Bottom Layer w10: C199.1@772.93,470.96 772.93,522.07 v2(765,530) v2(805,530) ; C199.1@775,470 778.27,466.73 C198.1@778.27,393.87 ; L26.2@777.34,324.68 C198.1@777.34,387.66
V_CAM0_UNPROT: C210.2 R128.1 R136.2 U11.9 U11.10 U11.11 U11.12 U11.13 | length 4530.3
  Layer 1 - Top Layer w5: U11.12@957.08,970.98 U11.11@976.77,970.98 ; R136.2@990,1057.05 C210.2@990,1010.87 976.77,997.64 U11.11@976.77,970.98 ; U11.9@1002.36,925.71 U11.10@1002.36,945.39 1002.36,956.06 987.44,970.98 U11.11@976.77,970.98
  Layer 1 - Top Layer w10: U11.13@937.87,965.87 U11.12@957.56,965.87
  Layer 1 - Top Layer w60: 1072.08,1102.36 v6(1072.08,1228.35) ; v6(4275,3084) v6(4275,3128) v6(4275,3178) R128.1@4275,3233.5
  Layer 4 - Signal w60: v6(1072.08,1228.35) 1162.64,1318.9 1475.63,1318.9 2770.9,2614.17 3814.37,2614.17 v6@4275,3074.8 ; v6(4275,3084) v6(4275,3128) v6(4275,3178)
V_CAM1: C202.1 C203.1 C213.1 L27.2 R139.2 TP17.1 U12.4 U12.5 U12.6 U12.7 U12.8 | length 871.3
  Layer 1 - Top Layer w10: R139.2@1921.18,810.87 1932.4,822.09 U12.4@1932.4,855.75 U12.5@1952.09,855.75 U12.6@1971.77,855.75 1982.44,855.75 1997.36,870.67 U12.7@1997.36,881.34 U12.8@1997.36,901.03 2034.8,901.03 2039.64,905.87 TP17.1@2092.56,905.87
  Layer 1 - Top Layer w60: 1812.01,500.32 1982.01,500.32 2092.56,610.87 C213.1@2139.61,610.87
  Layer 6 - Bottom Layer w10: C203.1@1755,475 v2(1755,535) ; C203.1@1756.93,481.41 1756.93,401.41 C202.1@1766.93,391.41 ; v2@1760,535 v2(1790,535) ; C202.1@1765.56,391.41 1765.56,327.79 L27.2@1766.93,326.41
V_CAM1_UNPROT: C211.2 R129.1 R137.2 U12.9 U12.10 U12.11 U12.12 U12.13 | length 4031.6
  Layer 1 - Top Layer w10: U12.13@1932.4,965.99 U12.12@1952.09,965.99 U12.11@1971.77,965.99 ; R137.2@1971.18,1055.87 1971.18,1052.24 1990,1033.43 C211.2@1990,1005.87 1971.77,987.64 U12.11@1971.77,965.99 ; U12.9@1997.36,920.71 U12.10@1997.36,940.39 1997.36,951.06 1982.44,965.99 U12.11@1971.77,965.99
  Layer 1 - Top Layer w60: v6(4365,3175) R129.1@4365,3233.5
  Layer 4 - Signal w60: v6(2453.78,2108.07) v6(2485.27,2139.57) 2485.27,2188.78 2816.18,2519.69 3845.31,2519.69 4365,3039.37 v6(4365,3175)
  Layer 6 - Bottom Layer w60: v6(2022.56,1060.87) v6(2057.56,1095.87) 2177.56,1215.87 2177.56,1715.71 2245.31,1783.46 2304.37,1783.46 2413.62,1892.72 2413.62,2067.91 v6(2453.78,2108.07) v6(2485.27,2139.57)
V_CAM2: C218.1 C219.1 C232.1 L34.2 R158.2 TP22.1 U13.4 U13.5 U13.6 U13.7 U13.8 | length 926.5
  Layer 1 - Top Layer w10: R158.2@2917.4,814.65 U13.4@2917.4,870.75 U13.5@2937.09,870.75 U13.6@2956.77,870.75 2967.44,870.75 2982.36,885.67 U13.7@2982.36,896.34 ; U13.8@2982.36,916.02 U13.7@2982.36,896.34 ; TP22.1@3092.56,905.87 3083.03,896.34 U13.7@2982.36,896.34
  Layer 1 - Top Layer w60: 2779.29,492.6 2984.29,492.6 3102.56,610.87 C232.1@3139.61,610.87
  Layer 6 - Bottom Layer w10: L34.2@2775,320 2780,325 2780,380 2776.93,383.07 C219.1@2776.93,460 ; C219.1@2775,460 2770,465 v2(2770,525) v2(2805,525)
V_CAM2_UNPROT: C230.2 R130.1 R156.2 U13.9 U13.10 U13.11 U13.12 U13.13 | length 3285.2
  Layer 1 - Top Layer w10: U13.13@2917.4,980.98 U13.12@2937.09,980.98 U13.11@2956.77,980.98 ; R156.2@2956.18,1070.87 2970,1057.05 C230.2@2970,1020.87 2956.77,1007.64 U13.11@2956.77,980.98 ; U13.9@2982.36,935.71 U13.10@2982.36,955.39 2982.36,966.06 2967.44,980.98 U13.11@2956.77,980.98
  Layer 1 - Top Layer w60: v6(4455,3081) v6(4455,3127) v6(4455,3175) R130.1@4455,3233.5
  Layer 4 - Signal w60: v6(3562.01,1899.61) 3562.01,2100.16 4455,2993.15 v6(4455,3081) v6(4455,3127) v6(4455,3175)
  Layer 6 - Bottom Layer w60: v6(3007.56,1090.87) v6(3047.56,1090.87) 3427.56,1090.87 3562.56,1225.87 v6(3562.56,1850.39) 3562.56,1898.28 ccw(c3560.68,1898.28) v6(3562.01,1899.61)
V_CAM3: C222.1 C223.1 C233.1 L35.2 R159.2 TP23.1 U14.4 U14.5 U14.6 U14.7 U14.8 | length 920.4
  Layer 1 - Top Layer w10: R159.2@3927.4,817.09 U14.4@3927.4,855.75 U14.5@3947.09,855.75 U14.6@3966.77,855.75 3972.44,855.75 3992.36,875.67 U14.7@3992.36,881.34 U14.8@3992.36,901.02 4087.72,901.02 TP23.1@4092.56,905.87
  Layer 1 - Top Layer w60: 3775,503 4011,503 4118.87,610.87 C233.1@4139.61,610.87
  Layer 6 - Bottom Layer w10: C223.1@3760,465 C223.1@3770,455 ; C223.1@3765,467 v2(3765,530) v2@3804,530 ; C223.1@3776.93,471.92 3785.56,463.3 C222.1@3785.56,391.92 ; L35.2@3781.93,324.91 C222.1@3781.93,396.92
  other v2: 3805,530
V_CAM3_UNPROT: C231.2 R131.1 R157.2 U14.9 U14.10 U14.11 U14.12 U14.13 | length 3084.3
  Layer 1 - Top Layer w10: U14.13@3927.4,965.98 U14.12@3947.09,965.98 U14.11@3966.77,965.98 ; R157.2@3966.18,1055.87 3985,1037.05 C231.2@3985,1005.87 3966.77,987.64 U14.11@3966.77,965.98 ; U14.9@3992.36,920.71 U14.10@3992.36,940.39 3992.36,951.06 3977.44,965.98 U14.11@3966.77,965.98
  Layer 1 - Top Layer w60: v6(4535,3080) v6(4535,3126) v6(4535,3174) R131.1@4535,3233.5
  Layer 4 - Signal w60: v6(4127.56,1375.87) v6(4077.56,1375.87) v6(4022.56,1375.87) 3849.76,1548.66 3849.76,2254.06 4535,2939.29 v6(4535,3080) v6(4535,3126) v6(4535,3174)
  Layer 6 - Bottom Layer w60: v6(4017.56,1060.87) v6(4047.56,1090.87) 4127.56,1170.87 v6(4127.56,1375.87) v6(4077.56,1375.87) v6(4022.56,1375.87)
V_RADAR0: C238.1 C239.1 C242.1 C243.1 L42.2 R174.2 R175.2 R177.2 TP28.1 U15.4 U15.5 U15.6 U15.7 U15.8 U16.1 | length 1120.4
  Layer 1 - Top Layer w10: v1(607.53,5452.47) C243.1@932.92,5452.47 ; R174.2@932.92,5378.8 C243.1@932.92,5452.47 ; R175.2@932.92,5530.88 C243.1@932.92,5452.47 ; C243.1@942.91,5452.47 C243.1@932.92,5452.47 ; L42.2@1089,6161 1112.5,6161 1123,6150.5 C238.1@1185,6150.5 ; C239.1@1155,6057 1155,5887 TP28.1@1240,5802 ; C239.1@1178,6084.5 1185.38,6091.88 C238.1@1185.38,6150.5 ; U15.4@1499.88,5632.16 U15.5@1499.88,5612.47 U15.6@1499.88,5592.79 1499.88,5582.12 1514.8,5567.2 U15.7@1525.47,5567.2 U15.8@1545.16,5567.2
  Layer 1 - Top Layer w20: R177.2@1455,5618.38 1493.98,5618.38
  Layer 6 - Bottom Layer w10: U16.1@574.69,5452.47 v1(607.53,5452.47)
V_RADAR0_UNPROT: C240.2 R168.1 R176.2 U15.9 U15.10 U15.11 U15.12 U15.13 | length 3592.2
  Layer 1 - Top Layer w10: U15.9@1564.84,5567.2 U15.10@1584.53,5567.2 1595.2,5567.2 1610.12,5582.12 U15.11@1610.12,5592.79 U15.12@1610.12,5612.47 U15.13@1610.12,5632.16 ; 1614.76,5622 1617.2,5619.56 ; C240.2@1655,5619.56 1681.18,5593.38 R176.2@1710,5593.38
  Layer 1 - Top Layer w20: 1617.2,5619.56 C240.2@1655,5619.56
  Layer 1 - Top Layer w60: v6(3765,3585) v6(3765,3510) R168.1@3908.5,3510
  Layer 6 - Bottom Layer w60: v2(1600,5520) 1600,5359 2162,4797 2603,4797 3765,3635 v6(3765,3585) v6(3765,3510)
V_RADAR1: C253.1 C254.1 C257.1 C258.1 L49.2 R188.2 R189.2 R191.2 TP31.1 U17.4 U17.5 U17.6 U17.7 U17.8 U18.1 | length 1167.4
  Layer 1 - Top Layer w10: v4(615,4230) 628.62,4243.62 C258.1@932.91,4243.62 ; R188.2@932.91,4165.12 C258.1@932.91,4243.62 ; R189.2@932.91,4322.13 C258.1@932.91,4243.62 ; C258.1@937.91,4243.62 C258.1@932.91,4243.62 ; L49.2@1105,4915.5 1114,4906.5 C253.1@1185.38,4906.5 ; C254.1@1156,4826 1156,4644 TP31.1@1240,4560 ; C254.1@1173,4827.5 1188,4842.5 C253.1@1188,4906.5 ; U17.4@1499.88,4390.16 U17.5@1499.88,4370.47 U17.6@1499.88,4350.79 1499.88,4335.12 1509.8,4325.2 U17.7@1525.47,4325.2 ; U17.7@1525.47,4325.2 1525.39,4325.28 1545.08,4325.28 U17.8@1545.16,4325.2 U17.7@1525.47,4325.2
  Layer 1 - Top Layer w20: R191.2@1460.9,4370.47 U17.5@1499.88,4370.47
  Layer 6 - Bottom Layer w10: U18.1@574.69,4210.47 595.47,4210.47 v4(615,4230)
V_RADAR1_UNPROT: C255.2 R169.1 R190.2 U17.9 U17.10 U17.11 U17.12 U17.13 | length 3634.6
  Layer 1 - Top Layer w10: U17.9@1564.84,4325.2 U17.10@1584.53,4325.2 1600.2,4325.2 1610.12,4335.12 U17.11@1610.12,4350.79 U17.12@1610.12,4370.47 ; U17.13@1610.12,4390.16 U17.12@1610.12,4370.47 ; R190.2@1710,4351.38 1683.82,4377.56 C255.2@1655,4377.56 1617.2,4377.56 U17.12@1610.12,4370.47
  Layer 1 - Top Layer w60: v6(3630,3470) v6(3680,3420) v6(3770,3420) R169.1@3908.5,3420
  Layer 6 - Bottom Layer w60: v2(1596,4289) 1680,4205 1790,4205 1865,4280 1865,4475 2090,4700 2515,4700 ; 2535,4700 3600,3635 3600,3500 v6(3630,3470) v6(3680,3420) v6(3770,3420)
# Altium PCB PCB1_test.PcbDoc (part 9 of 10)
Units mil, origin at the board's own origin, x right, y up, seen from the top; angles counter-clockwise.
Board outline 6690 x 6690 mil, 6 copper layers (Layer 1 - Top Layer, Layer 2 - GND, Layer 3 - PWR, Layer 4 - Signal, Layer 5 - GND, Layer 6 - Bottom Layer), stack 80.244 mil thick; 821 components, 458 nets, 3746 pads, 1527 vias.

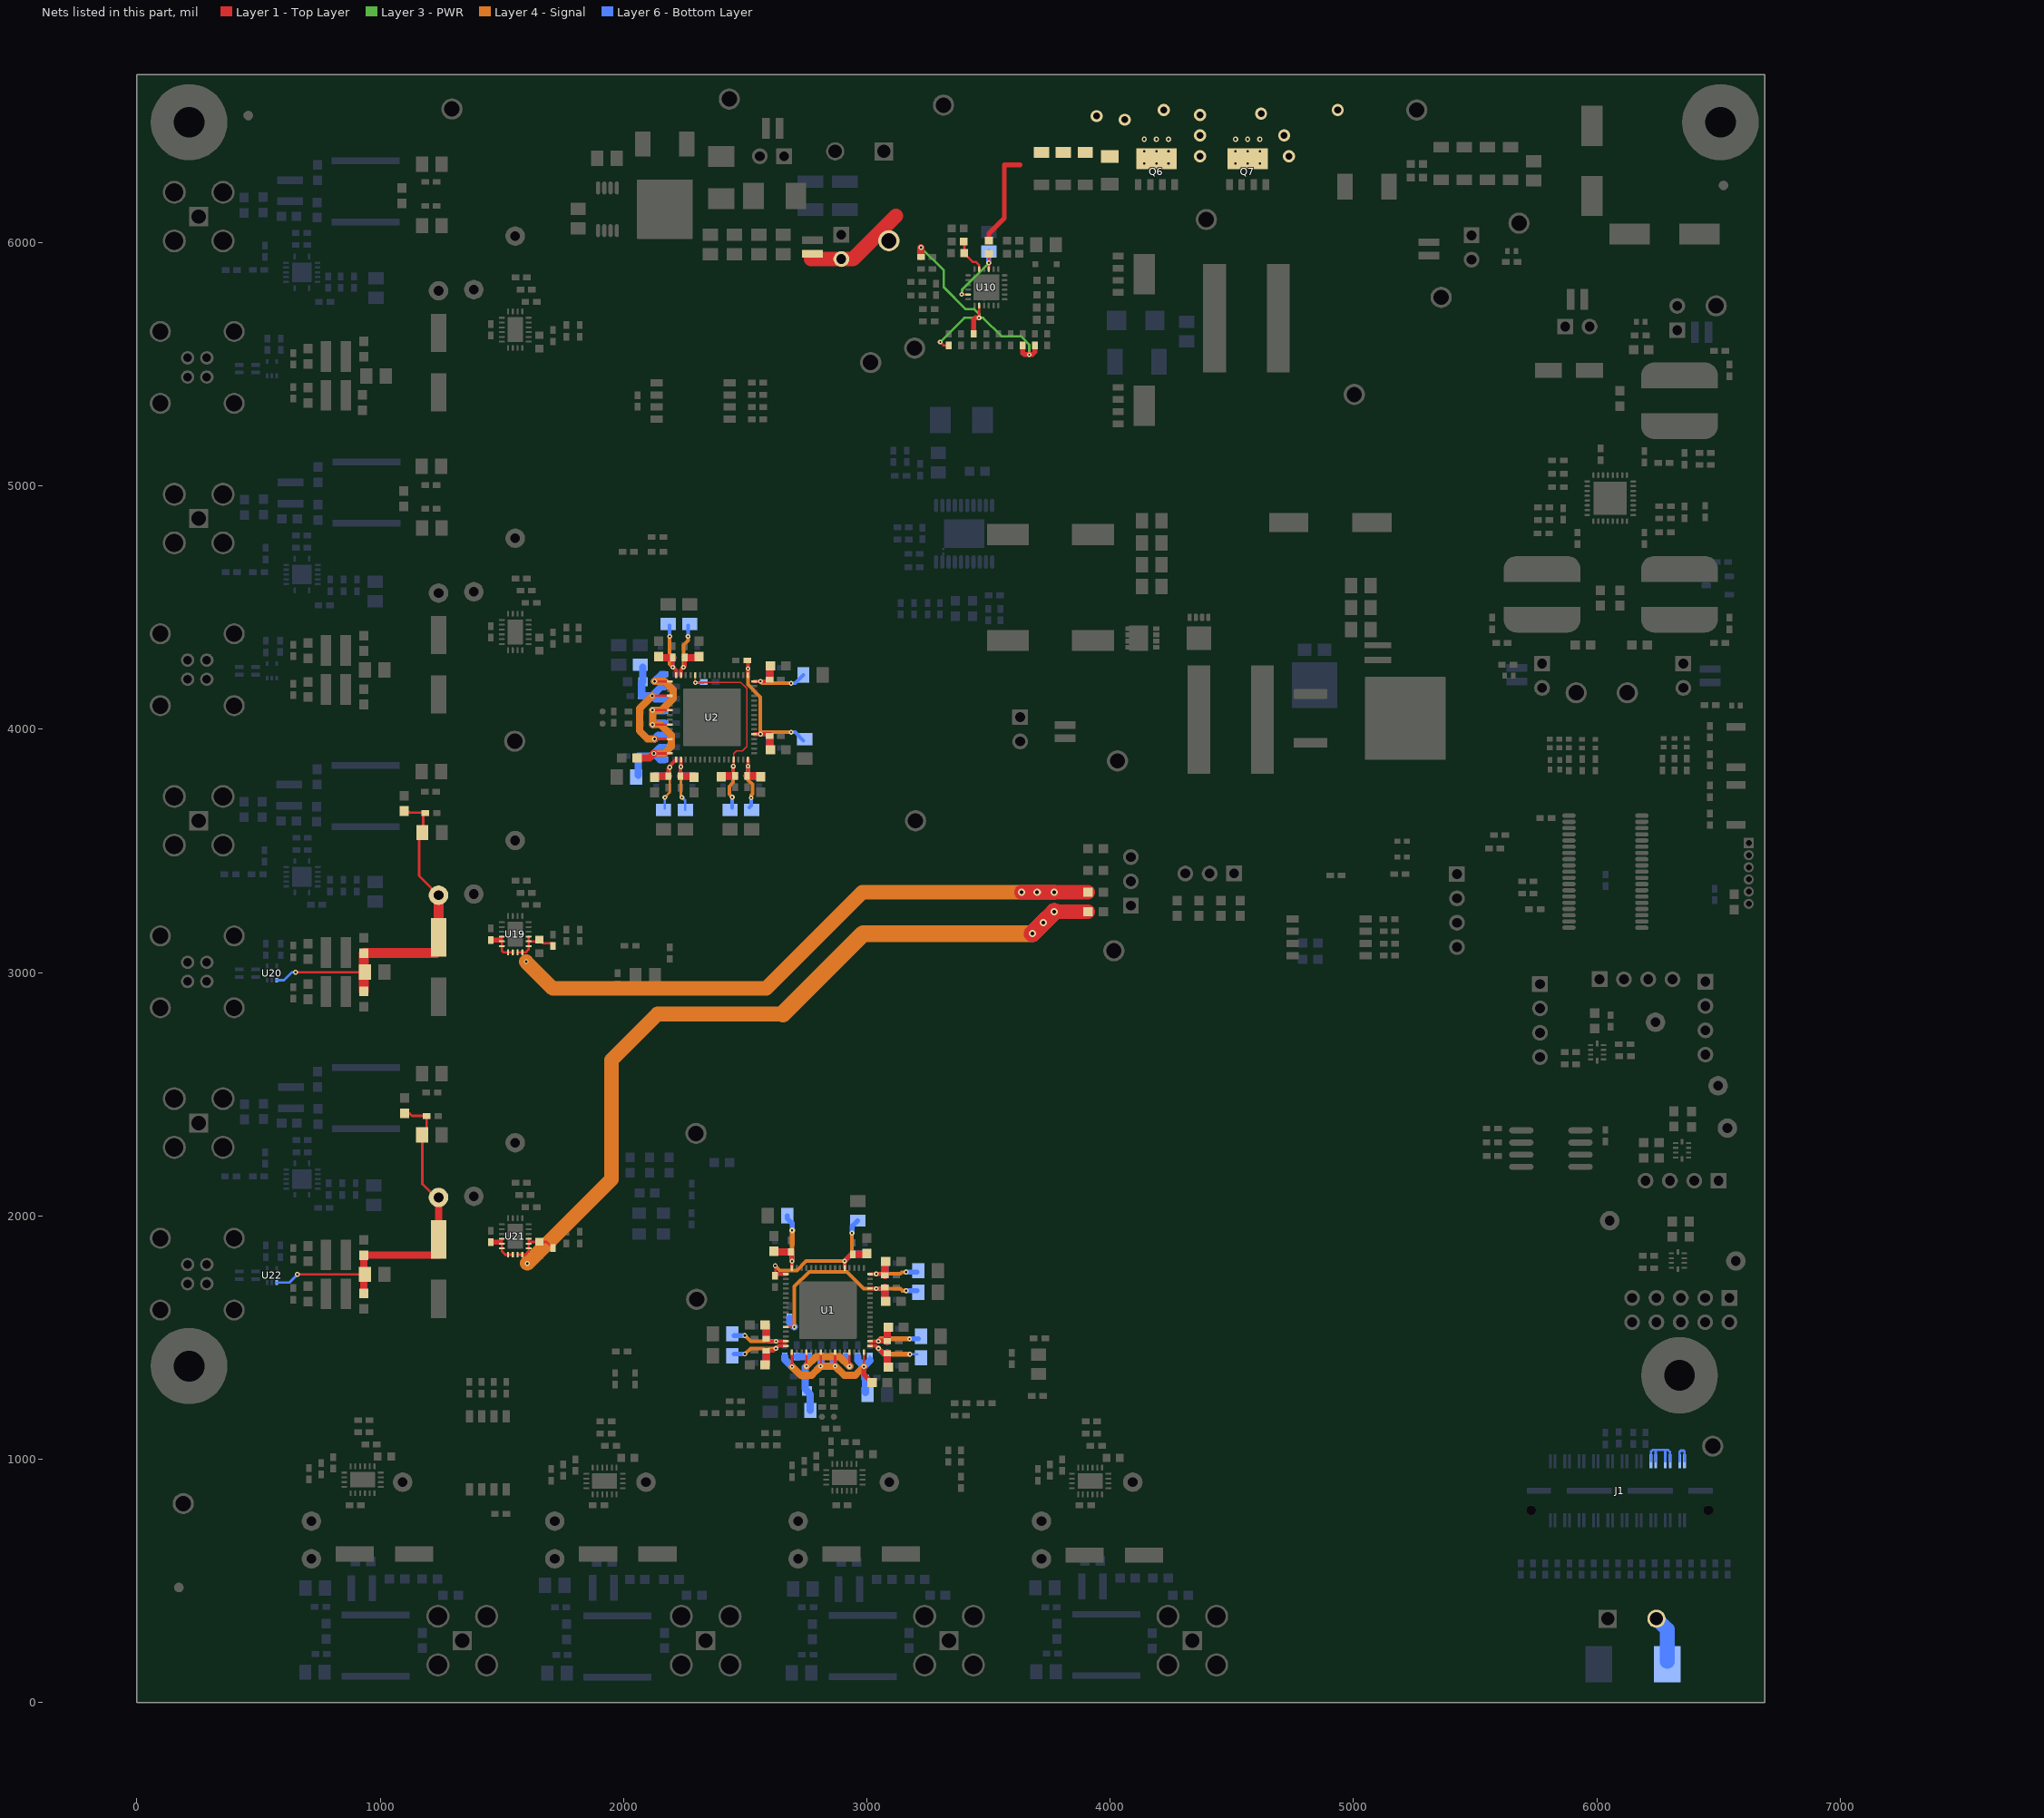
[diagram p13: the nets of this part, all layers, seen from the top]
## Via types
v1: diameter 20, hole 10, Layer 1 - Top Layer to Layer 6 - Bottom Layer, tented both sides, 491 vias
v2: diameter 20, hole 10, Layer 1 - Top Layer to Layer 6 - Bottom Layer, 310 vias
v3: diameter 19.68, hole 7.87, Layer 1 - Top Layer to Layer 6 - Bottom Layer, 282 vias
v4: diameter 19.68, hole 7.87, Layer 1 - Top Layer to Layer 6 - Bottom Layer, tented both sides, 211 vias
v5: diameter 50, hole 28, Layer 1 - Top Layer to Layer 6 - Bottom Layer, 101 vias
v6: diameter 30, hole 15, Layer 1 - Top Layer to Layer 6 - Bottom Layer, 73 vias
v7: diameter 22, hole 10, Layer 1 - Top Layer to Layer 6 - Bottom Layer, 36 vias
v8: diameter 30, hole 10, Layer 1 - Top Layer to Layer 6 - Bottom Layer, 14 vias
v9: diameter 19.68, hole 7.87, Layer 1 - Top Layer to Layer 6 - Bottom Layer, tented bottom, 4 vias
v10: diameter 30, hole 10, Layer 1 - Top Layer to Layer 6 - Bottom Layer, tented both sides, 2 vias
v11: diameter 40, hole 10, Layer 1 - Top Layer to Layer 6 - Bottom Layer, 1 vias
v12: diameter 23.62, hole 7.87, Layer 1 - Top Layer to Layer 6 - Bottom Layer, tented both sides, 1 vias
v13: diameter 23.62, hole 7.87, Layer 1 - Top Layer to Layer 6 - Bottom Layer, 1 vias

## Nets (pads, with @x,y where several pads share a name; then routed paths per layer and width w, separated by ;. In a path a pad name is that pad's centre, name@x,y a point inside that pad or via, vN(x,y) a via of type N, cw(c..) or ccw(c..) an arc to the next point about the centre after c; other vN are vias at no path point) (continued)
V_RADAR2: C268.1 C269.1 C272.1 C273.1 L56.2 R202.2 R203.2 R205.2 TP34.1 U19.4 U19.5 U19.6 U19.7 U19.8 U20.1 | length 1636
  Layer 1 - Top Layer w10: v2(652,3002) 933,3002 C273.1@938,3002 ; L56.2@1098.38,3664.13 1113.87,3664.13 1120.38,3657.62 C268.1@1182.38,3657.62 ; C269.1@1160,3552 1160,3398 TP34.1@1240,3318 ; C269.1@1177.38,3594.62 1177.38,3647.24 C268.1@1185.76,3655.62 ; U19.4@1499.88,3148.16 U19.5@1499.88,3128.47 U19.6@1499.88,3108.79 1499.88,3090.12 1506.8,3083.2 U19.7@1525.47,3083.2 U19.8@1545.16,3083.2
  Layer 1 - Top Layer w20: R205.2@1455,3134.38 1493.35,3134.38
  Layer 1 - Top Layer w40: R202.2@933,2923.5 933,3002 R203.2@933,3080.5 1230.5,3080.5 1240,3090 C272.1@1240,3145.05 TP34.1@1240,3318
  Layer 6 - Bottom Layer w10: U20.1@574.69,2968.47 604.47,2968.47 638,3002 v2(652,3002)
V_RADAR2_UNPROT: C270.2 R170.1 R204.2 U19.9 U19.10 U19.11 U19.12 U19.13 | length 2866.5
  Layer 1 - Top Layer w10: U19.9@1564.84,3083.2 U19.10@1584.53,3083.2 1598.2,3083.2 1610.12,3095.12 U19.11@1610.12,3108.79 U19.12@1610.12,3128.47 ; U19.13@1610.12,3148.16 U19.12@1610.12,3128.47 ; C270.2@1647.91,3128.47 U19.12@1610.12,3128.47 ; C270.2@1655,3135.56 1669.37,3121.19 1710,3121.19 R204.2@1710,3109.38
  Layer 1 - Top Layer w60: v6(3635,3330) v6(3700,3330) v6(3770,3330) R170.1@3908.5,3330
  Layer 4 - Signal w60: v2(1600,3045) 1710,2935 2585.82,2935 2980.82,3330 v6(3635,3330) v6(3700,3330) v6(3770,3330)
V_RADAR3: C283.1 C284.1 C287.1 C288.1 L63.2 R216.2 R217.2 R219.2 TP37.1 U21.4 U21.5 U21.6 U21.7 U21.8 U22.1 | length 1682.6
  Layer 1 - Top Layer w10: v2(660,1760) 933,1760 C288.1@938,1760 ; L63.2@1101,2421.5 1121.1,2421.5 1131,2411.61 C283.1@1190,2411.61 ; C284.1@1168.7,2337.3 1191.38,2359.99 C283.1@1191.38,2411 ; C284.1@1173,2333 1173,2131 TP37.1@1235,2069 ; U21.4@1499.88,1906.16 U21.5@1499.88,1886.47 U21.6@1499.88,1866.79 1499.88,1855.12 1513.8,1841.2 U21.7@1525.47,1841.2 U21.8@1545.16,1841.2
  Layer 1 - Top Layer w20: R219.2@1455,1892.38 1493.98,1892.38
  Layer 1 - Top Layer w30: R216.2@933,1681.5 933,1760 R217.2@933,1838.5 1133.5,1838.5 ; 1135,1840 1240,1840 C287.1@1240,1903.05 TP37.1@1240,2076
  Layer 6 - Bottom Layer w10: U22.1@574.68,1726.47 626.47,1726.47 v2(660,1760)
V_RADAR3_UNPROT: C285.2 R171.1 R218.2 U21.9 U21.10 U21.11 U21.12 U21.13 | length 3522.1
  Layer 1 - Top Layer w10: U21.9@1564.84,1841.2 U21.10@1584.53,1841.2 1596.2,1841.2 1610.12,1855.12 U21.11@1610.12,1866.79 U21.12@1610.12,1886.47 U21.13@1610.12,1906.16 ; 1617.21,1893.56 C285.2@1655,1893.56 1683.82,1893.56 R218.2@1710,1867.38
  Layer 1 - Top Layer w60: v6(3770,3250) R171.1@3908.5,3250
  Layer 1 - Top Layer w70: v6(3680,3160) v6(3725,3205) v6(3770,3250)
  Layer 4 - Signal w60: v2(1605,1805) 1950,2150 1950,2640 2139.82,2829.82 2654.82,2829.82
  Layer 4 - Signal w70: 2654.82,2829.82 2985,3160 v6(3680,3160) v6(3725,3205) v6(3770,3250)
VDD18_P0_CAM: C37.1 C38.1 C39.1 C40.1 L6.2 U1.48 | length 417.8
  Layer 1 - Top Layer w15: C40.1@2586.18,1445.87 2616.56,1445.87 v4(2626.56,1455.87) 2636.36,1465.67 U1.48@2666.89,1465.67
  Layer 1 - Top Layer w30: L6.2@2586.18,1392.99 C40.1@2586.18,1445.87
  Layer 4 - Signal w15: v2(2498.56,1432.87) 2499.56,1432.87 2522.56,1455.87 v4(2626.56,1455.87)
  Layer 6 - Bottom Layer w15: C39.1@2586.18,1445.87 2616.56,1445.87 v4(2626.56,1455.87)
  Layer 6 - Bottom Layer w20: C37.1@2454.56,1432.87 v2(2498.56,1432.87)
  Layer 6 - Bottom Layer w30: C38.1@2586.18,1395.87 C39.1@2586.18,1445.87
VDD18_P0_RADAR: C97.1 C98.1 C99.1 C100.1 L16.2 U2.48 | length 395.2
  Layer 1 - Top Layer w15: v4@2202.21,4255.79 C100.1@2202.21,4294.38 ; v4(2203,4255) 2216.36,4241.64 U2.48@2216.36,4222.23
  Layer 1 - Top Layer w30: L16.2@2149.13,4294.38 C100.1@2202.21,4294.38
  Layer 4 - Signal w15: v4(2190,4382) 2190,4268 v4(2203,4255)
  Layer 6 - Bottom Layer w15: v4(2190,4382) C97.1@2190,4426 ; v4(2203,4255) C99.1@2203,4293.59
  Layer 6 - Bottom Layer w30: C98.1@2152,4294.38 C99.1@2202.21,4294.38
VDD18_P1_CAM: C43.1 C44.1 C45.1 C46.1 L7.2 U1.47 | length 415.4
  Layer 1 - Top Layer w15: C46.1@2586.18,1495.87 2596.69,1485.35 v4(2627.05,1485.35) U1.47@2666.89,1485.35
  Layer 1 - Top Layer w30: C46.1@2586.18,1495.87 L7.2@2586.18,1548.74
  Layer 4 - Signal w15: v2(2498.56,1508.87) 2522.07,1485.35 v4(2627.05,1485.35)
  Layer 6 - Bottom Layer w15: C45.1@2586.18,1495.87 2596.69,1485.35 v4(2627.05,1485.35)
  Layer 6 - Bottom Layer w20: C43.1@2454.56,1508.87 v2(2498.56,1508.87)
  Layer 6 - Bottom Layer w30: C45.1@2586.18,1495.87 C44.1@2586.18,1545.87
VDD18_P1_RADAR: C104.1 C105.1 C106.1 C107.1 L17.2 U2.47 | length 403.8
  Layer 1 - Top Layer w15: U2.47@2236.05,4222.23 2236.05,4244.66 v4(2246.38,4255) 2252.21,4260.82 C107.1@2252.21,4294.38
  Layer 1 - Top Layer w30: C107.1@2252.21,4294.38 L17.2@2305.87,4294.38
  Layer 4 - Signal w15: v4(2246.38,4255) 2246.38,4346.38 2265,4365 v4(2265,4382)
  Layer 6 - Bottom Layer w15: v4(2246.38,4255) 2252.21,4260.82 C106.1@2252.21,4294.38 ; v4(2265,4382) C104.1@2265,4426
  Layer 6 - Bottom Layer w30: C106.1@2252.21,4294.38 C105.1@2303,4294.38
VDD18_P2_CAM: C48.1 C49.1 C50.1 C51.1 L8.2 U1.1 | length 400.4
  Layer 1 - Top Layer w15: U1.1@3013.35,1465.67 3037.76,1465.67 v4(3047.56,1455.87)
  Layer 1 - Top Layer w20: v4(3047.56,1455.87) 3067.56,1435.87 C51.1@3083.94,1435.87
  Layer 1 - Top Layer w30: L8.2@3083.94,1382.99 C51.1@3083.94,1435.87
  Layer 4 - Signal w20: v4(3047.56,1455.87) 3071.56,1431.87 v4(3176.56,1431.87)
  Layer 6 - Bottom Layer w10: v4(3176.56,1431.87) C48.1@3207.56,1431.87
  Layer 6 - Bottom Layer w20: v4(3047.56,1455.87) 3067.56,1435.87 C50.1@3083.94,1435.87
  Layer 6 - Bottom Layer w30: C49.1@3083.94,1385.87 C50.1@3083.94,1435.87
VDD18_P2_RADAR: C109.1 C110.1 C111.1 C112.1 L18.2 U2.1 | length 400.6
  Layer 1 - Top Layer w15: C112.1@2184,3807.62 2184,3838 v4(2190,3844) 2190,3849.41 U2.1@2216.36,3875.77
  Layer 1 - Top Layer w30: L18.2@2131.13,3807.62 C112.1@2184,3807.62
  Layer 4 - Signal w10: v4(2170,3720) 2190,3740 v4(2190,3844)
  Layer 6 - Bottom Layer w10: C109.1@2170,3675 v4(2170,3720) ; C111.1@2184,3807.62 2184,3838 v4(2190,3844)
  Layer 6 - Bottom Layer w30: C110.1@2134,3807.62 C111.1@2184,3807.62
VDD18_P3_CAM: C53.1 C54.1 C55.1 C56.1 L9.2 U1.2 | length 378
  Layer 1 - Top Layer w15: U1.2@3013.35,1485.35 v4(3047.45,1485.35)
  Layer 1 - Top Layer w20: v4@3047.96,1485.87 C56.1@3083.94,1485.87
  Layer 1 - Top Layer w30: C56.1@3083.94,1485.87 L9.2@3083.94,1538.74
  Layer 4 - Signal w20: v4(3047.45,1485.35) 3056.96,1494.87 v4(3175.56,1494.87)
  Layer 6 - Bottom Layer w20: v4(3047.45,1485.35) C55.1@3083.42,1485.35 ; v4(3175.56,1494.87) C53.1@3212.56,1494.87
  Layer 6 - Bottom Layer w30: C55.1@3083.94,1485.87 C54.1@3083.94,1535.87
VDD18_P3_RADAR: C114.1 C115.1 C116.1 C117.1 L19.2 U2.2 | length 393.6
  Layer 1 - Top Layer w15: C117.1@2234,3807.62 2234,3844 v4(2236.05,3846.05) U2.2@2236.05,3875.77
  Layer 1 - Top Layer w30: C117.1@2234,3807.62 L19.2@2285.87,3807.62
  Layer 4 - Signal w10: v4(2236.05,3846.05) 2236.05,3723.95 v4(2240,3720)
  Layer 6 - Bottom Layer w10: C116.1@2234,3807.62 2234,3844 v4(2236.05,3846.05) ; v4(2240,3720) 2254,3706 C114.1@2254,3669
  Layer 6 - Bottom Layer w30: C116.1@2234,3807.62 C115.1@2283,3807.62
VDD18A_CAM: C22.1 C23.1 C24.1 C25.1 L4.2 U1.32 | length 422.6
  Layer 1 - Top Layer w15: U1.32@2692.44,1786.53 C25.1@2692.44,1847.36
  Layer 1 - Top Layer w30: L4.2@2619.68,1852.24 C25.1@2687.56,1852.24
  Layer 4 - Signal w20: v4(2692.56,1813.87) v12(2693.05,1940.87)
  Layer 6 - Bottom Layer w20: C22.1@2672.56,2000.87 2672.56,1990.87 2693.05,1970.38 v12(2693.05,1940.87) ; v4(2692.56,1813.87) C24.1@2692.56,1847.24
  Layer 6 - Bottom Layer w30: C23.1@2622.56,1852.24 C24.1@2687.56,1852.24
VDD18A_RADAR: C81.1 C82.1 C83.1 C84.1 L14.2 U2.32 | length 383.6
  Layer 1 - Top Layer w15: U2.32@2537.23,4196.68 C84.1@2593.05,4196.68
  Layer 1 - Top Layer w30: C84.1@2600.38,4204 L14.2@2600.38,4255.87
  Layer 4 - Signal w10: v4@2561.32,4196.68 v4@2561.65,4197
  Layer 4 - Signal w15: v4@2561.65,4197 2569.65,4189 v4(2689,4189)
  Layer 6 - Bottom Layer w15: v4@2561.32,4196.68 C83.1@2593.05,4196.68 ; v4(2689,4189) 2705,4189 C81.1@2739,4223
  Layer 6 - Bottom Layer w30: C83.1@2600.38,4204 C82.1@2600.38,4253
  other v4: 2563,4197
VDDA: C176.1 R103.2 R104.2 R105.2 R106.2 U10.2 | length 1232.2
  Layer 1 - Top Layer w10: v4(3301.38,5591.38) 3315,5577.76 R103.2@3336.38,5577.76 ; v4(3461,5691) 3461,5740.72 U10.2@3461.85,5741.57
  Layer 1 - Top Layer w20: C176.1@3439.57,5625 3439.57,5684.57 3446,5691 v4(3461,5691) ; R106.2@3640.95,5577.76 3640.95,5546.54 3647.76,5539.72 v4(3667.76,5539.72) 3679.13,5539.72 3690.95,5551.54 R104.2@3690.95,5577.76
  Layer 1 - Top Layer w30: R105.2@3222.76,5941.38 v4(3222.76,5980)
  Layer 3 - PWR w10: v4(3222.76,5980) 3316.38,5886.38 3316.38,5816.18 3406.18,5726.38 3442.32,5726.38 3461,5707.7 v4(3461,5691) ; v4(3301.38,5591.38) 3401,5691 v4(3461,5691) ; v4(3667.76,5539.72) 3667.76,5580.67 3633.27,5615.16 3553.54,5615.16 3477.7,5691 v4(3461,5691)
VDDCSI_1V1_CAM: C8.1 C9.1 C10.1 C11.1 C12.1 L2.2 U1.21 U1.33 | length 785.7
  Layer 1 - Top Layer w10: C11.1@2624.83,1752.69 v2@2624.83,1792.53
  Layer 1 - Top Layer w15: C11.1@2629.01,1760.94 U1.33@2666.89,1760.94 ; U1.21@2909.03,1786.53 v4(2909.03,1814.39)
  Layer 1 - Top Layer w20: v4(2909.03,1814.39) C12.1@2936.88,1842.24
  Layer 1 - Top Layer w30: C12.1@2942.56,1842.24 L2.2@2995.43,1842.24
  Layer 4 - Signal w15: v2@2622.98,1794.9 2641.88,1776 2712.69,1776 2751.08,1814.39 v4(2909.03,1814.39) 2939.03,1844.39 v4(2939.03,1929.39)
  Layer 6 - Bottom Layer w20: v4(2909.03,1814.39) C10.1@2936.88,1842.24 ; v4(2939.03,1929.39) 2939.03,1957.34 C8.1@2962.56,1980.87
  Layer 6 - Bottom Layer w30: C10.1@2942.56,1842.24 C9.1@2992.56,1842.24
  other v2: 2623.65,1795.57
VDDCSI_1V1_RADAR: C69.1 C70.1 C71.1 C72.1 C73.1 L12.2 U2.21 U2.33 | length 734.5
  Layer 1 - Top Layer w15: U2.33@2511.64,4222.23 2512,4222.59 v4(2512,4249) 2512,4271.62 C72.1@2511.64,4271.98 ; U2.21@2537.23,3980.09 v4(2562.91,3980.09) C73.1@2593.29,3980.09
  Layer 1 - Top Layer w30: L12.2@2600.38,3920.13 C73.1@2600.38,3973
  Layer 4 - Signal w15: v4(2512,4249) 2512,4183.72 2511.64,4183.36 2562.91,4132.09 v4(2562.91,3980.09) ; v4@2563,3980 2571,3988 v4(2689,3988)
  Layer 6 - Bottom Layer w10: C71.1@2593.29,3980.09 C71.1@2600.38,3973
  Layer 6 - Bottom Layer w15: v4(2562.91,3980.09) C71.1@2593.29,3980.09 ; v4(2689,3988) 2705,3988 C69.1@2740,3953
  Layer 6 - Bottom Layer w30: C70.1@2600.38,3923 C71.1@2600.38,3973
VDDFPD18_CAM: C28.1 C29.1 C30.1 C31.1 C32.1 C33.1 C34.1 L5.2 U1.49 U1.55 U1.58 U1.64 | length 1098.1
  Layer 1 - Top Layer w10: v4(2692.44,1380.98) U1.49@2692.44,1440.08 ; v4(2810.58,1382.84) U1.55@2810.58,1440.08 ; v4(2869.65,1382.96) U1.58@2869.65,1440.08 ; v4(2987.79,1381.1) U1.64@2987.79,1440.08
  Layer 1 - Top Layer w20: v4(2987.79,1381.1) 2987.79,1349.14 L5.2@3021.06,1315.87
  Layer 4 - Signal w30: v4(2692.44,1380.98) 2727.56,1345.87 2773.61,1345.87 v4(2810.58,1382.84) v4@2869.53,1382.84 ; v4(2869.65,1382.96) 2906.75,1345.87 2952.56,1345.87 v4(2987.79,1381.1)
  Layer 6 - Bottom Layer w10: C34.1@2962.56,1422.24 2987.79,1397.01 v4(2987.79,1381.1) 2997,1381.1 3012.56,1396.65 3012.56,1405.87 C30.1@3012.56,1422.24
  Layer 6 - Bottom Layer w20: C29.1@2987.79,1342.01 v4(2987.79,1381.1)
  Layer 6 - Bottom Layer w30: C31.1@2662.56,1422.24 2662.56,1410.87 v4(2692.44,1380.98) ; v4(2810.58,1382.84) 2812.56,1384.82 C32.1@2812.56,1422.24 ; C33.1@2862.56,1422.24 2862.56,1390.05 v4(2869.65,1382.96) ; C34.1@2962.56,1422.24 2962.56,1406.33 v4(2987.79,1381.1) 3012.56,1405.87 ; C28.1@2993.94,1274.49 C29.1@2993.94,1335.87
VDDFPD18_RADAR: C88.1 C89.1 C90.1 C91.1 C92.1 C93.1 C94.1 L15.2 U2.49 U2.55 U2.58 U2.64 | length 1270.1
  Layer 1 - Top Layer w10: v2(2119.47,4019.47) U2.58@2190.77,4019.47 ; v2(2119.54,4078.54) U2.55@2190.77,4078.54 ; v2(2125,3901) 2190.45,3901 U2.64@2190.77,3901.33 ; v2(2128,4197) 2128.32,4196.68 U2.49@2190.77,4196.68
  Layer 1 - Top Layer w30: L15.2@2055.84,3882.7 2106.7,3882.7 v2@2124.64,3900.64
  Layer 4 - Signal w30: v2(2119.47,4019.47) 2152.53,4019.47 2197,3975 2197,3929.5 2168.83,3901.33 2125.33,3901.33 v2(2125,3901) ; v2(2119.47,4019.47) v2(2119.54,4078.54) 2155.54,4078.54 2203.81,4126.81 2203.81,4161.72 2168.86,4196.68 2128.32,4196.68 v2(2128,4197)
  Layer 6 - Bottom Layer w30: C88.1@2059.97,3811.97 C89.1@2059.97,3889.7 2113.7,3889.7 v2(2125,3901) ; v2(2119.47,4019.47) 2125.5,4025.5 C93.1@2168.38,4025.5 ; v2(2119.54,4078.54) 2122.57,4075.5 C92.1@2168.38,4075.5 ; v2(2128,4197) 2156.5,4225.5 C94.1@2168.38,4225.5 ; C90.1@2168.38,3875.5 2150.5,3875.5 v2(2125,3901) ; C91.1@2168.38,3925.5 2149.5,3925.5 v2(2125,3901)
VDDFPD_1V1_CAM: C14.1 C15.1 C16.1 C17.1 C18.1 L3.2 U1.52 U1.61 | length 649.6
  Layer 1 - Top Layer w10: v4(2751.51,1381.91) U1.52@2751.51,1440.08 ; v4(2928.72,1382.03) U1.61@2928.72,1440.08
  Layer 4 - Signal w30: v4(2751.51,1381.91) 2791.84,1422.24 2888.51,1422.24 v4(2928.72,1382.03)
  Layer 6 - Bottom Layer w30: C16.1@2712.56,1422.24 C17.1@2762.56,1422.24 2762.56,1394.34 2746.18,1377.96 C15.1@2746.18,1340.87 L3.2@2746.18,1288.74 ; L3.2@2754.05,1280.87 2767.56,1267.36 C14.1@2767.56,1200.87 ; C18.1@2912.56,1422.24 2912.56,1398.19 v4(2928.72,1382.03)
VDDFPD_1V1_RADAR: C75.1 C76.1 C77.1 C78.1 C79.1 L13.2 U2.52 U2.61 | length 702
  Layer 1 - Top Layer w10: v2(2118.39,4137.61) U2.52@2190.77,4137.61 ; v2(2127.4,3960.4) U2.61@2190.77,3960.4
  Layer 4 - Signal w30: v2(2118.39,4137.61) 2065.65,4084.87 2065.65,3993.35 2098.6,3960.4 v2(2127.4,3960.4)
  Layer 6 - Bottom Layer w30: L13.2@2074.62,4191.13 C76.1@2074.62,4137 v2@2117.79,4137 ; L13.2@2079.5,4196 C75.1@2079.5,4255.5 ; v2(2127.4,3960.4) 2142.5,3975.5 C79.1@2168.38,3975.5 ; C78.1@2168.38,4125.5 2130.5,4125.5 v2(2118.39,4137.61) 2156.29,4175.5 C77.1@2168.38,4175.5
VDDIO_CAM: C58.1 C59.1 C60.1 C61.1 L10.2 U1.16 | length 355.7
  Layer 1 - Top Layer w15: U1.16@3013.35,1760.94 C61.1@3068.86,1760.94
  Layer 1 - Top Layer w30: C61.1@3073.94,1755.87 L10.2@3073.94,1808.74
  Layer 4 - Signal w15: v4@3039.56,1761.87 3137.46,1761.87 3144.46,1768.87 v2(3161.56,1768.87)
  Layer 6 - Bottom Layer w15: v4@3039.56,1761.87 C60.1@3067.94,1761.87
  Layer 6 - Bottom Layer w20: v2(3161.56,1768.87) C58.1@3205.56,1768.87
  Layer 6 - Bottom Layer w30: C60.1@3073.94,1755.87 C59.1@3073.94,1805.87
  other v4: 3038.56,1761.87
VDDIO_RADAR: C119.1 C120.1 C121.1 C122.1 L20.2 U2.16 | length 386.8
  Layer 1 - Top Layer w15: C122.1@2511.64,3812.26 U2.16@2511.64,3875.77
  Layer 1 - Top Layer w30: C122.1@2508,3808.62 L20.2@2559.87,3808.62
  Layer 4 - Signal w15: v4@2511.64,3850.36 2511.64,3791.64 2530,3773.28 2530,3734 2525,3729 v4(2525,3718)
  Layer 6 - Bottom Layer w15: C121.1@2511.64,3812.26 v4@2511.64,3850.36 ; C119.1@2517,3679 2525,3687 v4(2525,3718)
  Layer 6 - Bottom Layer w30: C121.1@2508,3808.62 C120.1@2557,3808.62
  other v4: 2512,3849
VDDL_1V1_CAM: C2.1 C3.1 C4.1 C5.1 C6.1 L1.2 U1.13 U1.44 | length 991.9
  Layer 1 - Top Layer w10: U1.44@2666.89,1544.41 2667.43,1543.87 v4(2701.56,1543.87)
  Layer 1 - Top Layer w15: U1.13@3013.35,1701.89 C6.1@3069.96,1701.89
  Layer 1 - Top Layer w30: L1.2@3073.94,1652.99 C6.1@3073.94,1705.87
  Layer 4 - Signal w15: v4(2701.56,1543.87) 2701.56,1709.87 2762.56,1770.87 2917.56,1770.87 2987.56,1700.87 v4(3038.56,1700.87) 3137.56,1700.87 3145.56,1692.87 v2(3161.56,1692.87)
  Layer 6 - Bottom Layer w15: v4@3039.56,1700.87 C4.1@3068.94,1700.87
  Layer 6 - Bottom Layer w20: v2(3161.56,1692.87) C2.1@3205.56,1692.87
  Layer 6 - Bottom Layer w30: 2682.56,1561.49 C5.1@2682.56,1580.87 ; 2686.55,1558.87 v4(2701.56,1543.87) ; C3.1@3073.94,1655.87 C4.1@3073.94,1705.87
VDDL_1V1_RADAR: C63.1 C64.1 C65.1 C66.1 C67.1 L11.2 U2.13 U2.44 | length 988.7
  Layer 1 - Top Layer w6: U2.44@2295.1,4222.23 v4(2295.1,4191.9) 2296.2,4193 2482,4193 2507,4168 2507,3930 2488,3911 2464,3911 2452.58,3899.58 U2.13@2452.58,3875.77
  Layer 1 - Top Layer w10: v4(2451,3848) 2452.58,3849.58 U2.13@2452.58,3875.77
  Layer 1 - Top Layer w15: C67.1@2451,3815.62 v4(2451,3848)
  Layer 1 - Top Layer w30: L11.2@2406.13,3808.62 C67.1@2458,3808.62
  Layer 4 - Signal w15: v4(2447,3721) 2435,3733 2435,3765 2451,3781 v4(2451,3848)
  Layer 6 - Bottom Layer w10: v4(2295.1,4191.9) C66.1@2326.28,4191.9
  Layer 6 - Bottom Layer w15: C63.1@2447,3678 v4(2447,3721) ; C65.1@2451,3815.62 v4(2451,3848)
  Layer 6 - Bottom Layer w30: C64.1@2409,3808.62 C65.1@2458,3808.62
VEVM_1v8: J1.38 J1.40 | length 101
  Layer 6 - Bottom Layer w10: J1.38@6340.14,992.46 6340.14,1031.08 6344.49,1035.43 6356.3,1035.43 6359.82,1031.91 J1.40@6359.82,992.46
VEVM_3v3: J1.30 J1.32 J1.34 J1.36 | length 254
  Layer 6 - Bottom Layer w10: J1.30@6222.03,992.46 6222.03,1031.09 6229.33,1038.39 6241.71,1038.39 ; J1.32@6241.71,992.46 6241.71,1038.39 ; J1.34@6281.08,992.46 6281.08,1037.81 ; J1.36@6300.77,992.46 6300.77,1029.94 6292.32,1038.39 6281.08,1038.39 ; 6241.71,1038.39 6280.51,1038.39 ; 6280.51,1038.39 6281.08,1037.81 ; 6280.51,1038.39 6281.08,1038.39 ; 6281.08,1037.81 6281.08,1038.39
VEVM_12v0: D14.2 J40.2 | length 194
  Layer 6 - Bottom Layer w60: J40.2@6244.88,345 6289.16,300.72 D14.2@6289.16,169.29
VIN_IC: C179.2 R116.1 U10.15 U10.23 | length 315.9
  Layer 1 - Top Layer w10: v4(3390,5787) 3390.15,5786.85 U10.23@3416.57,5786.85 ; U10.15@3501.22,5891.18 3501.22,5921.22 3501.38,5921.38 R116.1@3501.38,5953.82
  Layer 3 - PWR w10: v4(3390,5787) 3391.85,5788.85 3391.85,5806.85 3501.22,5916.22 v4@3501.22,5921.22
  Layer 6 - Bottom Layer w5: v4@3501.23,5921.23 v4@3501.38,5921.38
  Layer 6 - Bottom Layer w20: v4@3501.22,5917 3501.23,5921.23 C179.2@3501.38,5963.05
  other v4: 3501,5917
VIN_PROTECT: C172.1 C173.1 C174.1 C175.1 J13.2 Q6.5 Q7.5 R116.2 R172.2 TP51.1 | length 825.2
  Layer 1 - Top Layer w20: R116.2@3501.38,6008.94 3501.38,6037.05 3565,6100.67 3565,6320 3630,6320
  Layer 1 - Top Layer w60: 2770.71,5932.64 2942.64,5932.64 3120,6110
  other v5: 4370,6355 4735,6355 4370,6440 4715,6440 4060,6505 3945,6520 4370,6525 4620,6530 4220,6545 4935,6545
  other v7: 4140,6325 4190,6325 4240,6325 4515,6325 4565,6325 4615,6325 4140,6375 4190,6375 4240,6375 4515,6375 4565,6375 4615,6375 4140,6425 4190,6425 4240,6425 4515,6425 4565,6425 4615,6425
VO_IC: C191.1 R119.1 U10.17 | length 142.3
  Layer 1 - Top Layer w10: R119.1@3400.59,6001.26 C191.1@3400.59,5956.38 3400.59,5955.39 3434.99,5921 3446.76,5921 3461.85,5905.91 U10.17@3461.85,5891.18
pads on no net: FID1.1 FID2.1 FID3.1 FID4.1 FID5.1 FID6.1 H5.0 H6.0 H7.0 H8.0 J1.1 J1.3 J1.6 J1.8 J1.10 J1.14 J1.MH1 J1.MH2 J10.1 J10.6 J15.4 J15.5 J15.6 J15.7 J15.8 J15.9 Q5.9@4326.61,4353.74 Q5.9@4338.92,4373.86 Q5.9@4338.92,4408.35 Q5.9@4352.2,4353.74 Q5.9@4365,4387.11 Q5.9@4377.8,4353.74 Q5.9@4391.08,4373.86 Q5.9@4391.08,4408.35 Q5.9@4403.39,4353.74 U1.7 U1.8 U1.18 U1.19 U1.20 U1.34 U1.35 U1.36 U1.37 U1.38 U1.39 U1.40 U1.41 U1.42 U1.43 U2.7 U2.8 U2.18 U2.19 U2.20 U2.34 U2.35 U2.36 U2.37 U2.38 U2.39 U2.40 U2.41 U2.42 U2.43 U3.33 U3.34 U3.35 U3.36 U3.37 U3.38 U5.1 U5.2 U6.1 U6.2 U7.3 U7.5 U9.1 U9.31 U9.32 U11.2 U11.21@900.98,915.87 U11.21@954.13,915.87 U12.2 U12.21@1895.98,910.87 U12.21@1949.13,910.87 U13.2 U13.21@2880.98,925.87 U13.21@2934.13,925.87 U14.2 U14.21@3890.98,910.87 U14.21@3944.13,910.87 U15.2 U15.21@1555,5615.43 U15.21@1555,5668.58 U16.2 U17.2 U17.21@1555,4373.43 U17.21@1555,4426.58 U18.2 U19.2 U19.21@1555,3131.43 U19.21@1555,3184.57 U20.2 U21.2 U21.21@1555,1889.43 U21.21@1555,1942.57 U22.2
copper on no net:
  other v3: 6064.55,1198.82

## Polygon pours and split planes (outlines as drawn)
GND on Layer 4 - Signal "Layer4GND" (solid, pour order 485): 541,20 541,787 731,977 4093,977 4536.32,533.68 4536.32,20
V_BAT on Layer 4 - Signal "Top Layer-No Net 1" (solid, pour order 335): 2743.02,6527.71 2744.69,6526.04 2928.03,6526.04 2928.03,5402.7 2934.69,5396.04 2741.36,5396.04 2741.36,6526.04
GND on Layer 2 - GND "LAYER_2_-_GND_GND_P000" (solid, remove dead copper, pour order 149): 6670,6670 20,6670 20,20 6670,20
VIN_PROTECT on Layer 2 - GND "LAYER_2_-_GND_VIN_PROTECT_P164" (solid, remove dead copper, pour order 213): 4765,6285 4765,6620 3600,6620 3600,6285
no net on Layer 2 - GND "Top Layer-No Net 1" (solid, pour order 337): 5913.11,416.69 6664.18,416.69 6664.18,27.5 6666.91,24.77 5911.75,24.77 5911.75,418.05
V_CAM3 on Layer 1 - Top Layer "LAYER_1_-_TOP_LAYER_V_CAM3_P060" (solid, remove dead copper, pour order 166): 4137.2,951.1 4032.2,951.1 4032.2,920.98 3967.38,920.98 3967.38,885.98 3912.38,885.98 3912.38,831.1 3902.2,831.1 3902.2,790.87 4002.2,790.87 4002.2,541.1 3732.2,541.1 3732.2,461.1 4217.2,461.1 4217.2,951.1
GND on Layer 1 - Top Layer "LAYER_1_-_TOP_LAYER_GND_P305" (solid, remove dead copper, pour order 266): 1174.08,50.84 1499.08,50.84 1499.08,400.84 1174.08,400.84
no net on Layer 1 - Top Layer "Top Layer-No Net 1" (solid, pour order 439): 1416,5279 1416,5459 1542,5459 1541,5458 1541,5279
no net on Layer 1 - Top Layer "Top Layer-No Net 1" (solid, pour order 437): 1685,5312 1685,5640 1563,5640 1563,5313 1562,5312
no net on Layer 1 - Top Layer "Top Layer-No Net 1" (solid, pour order 435): 1538,5636 1538,5482 1275,5482 1275,5635 1276,5636
V_RADAR0 on Layer 1 - Top Layer "Top Layer-No Net 1" (solid, pour order 433): 1070,6000.5 1070,6180.5 1196,6180.5 1195,6179.5 1195,6000.5
GND on Layer 1 - Top Layer "Top Layer-No Net 1" (solid, pour order 431): 1339,6033.5 1339,6361.5 1217,6361.5 1217,6034.5 1216,6033.5
GND on Layer 1 - Top Layer "LAYER_1_-_TOP_LAYER_GND_P108" (solid, remove dead copper, pour order 189): 50,6270 50,5945 50,5835 400,5835 400,6270
V_RADAR2 on Layer 1 - Top Layer "Top Layer-No Net 1" (solid, pour order 417): 1069.38,3503.62 1069.38,3683.62 1195.38,3683.62 1194.38,3682.62 1194.38,3503.62
NetC266_1 on Layer 1 - Top Layer "Top Layer-No Net 1" (solid, pour order 421): 1191.38,3860.62 1191.38,3706.62 928.38,3706.62 928.38,3859.62 929.38,3860.62
NetC236_1 on Layer 1 - Top Layer "Top Layer-No Net 1" (solid, pour order 429): 1192,6357.5 1192,6203.5 929,6203.5 929,6356.5 930,6357.5
GND on Layer 1 - Top Layer "Top Layer-No Net 1" (solid, pour order 425): 1339,4789.5 1339,5117.5 1217,5117.5 1217,4790.5 1216,4789.5
NetC251_1 on Layer 1 - Top Layer "Top Layer-No Net 1" (solid, pour order 423): 1192,5113.5 1192,4959.5 929,4959.5 929,5112.5 930,5113.5
GND on Layer 1 - Top Layer "Top Layer-No Net 1" (solid, pour order 419): 1338.38,3536.62 1338.38,3864.62 1216.38,3864.62 1216.38,3537.62 1215.38,3536.62
no net on Layer 1 - Top Layer "Top Layer-No Net 1" (solid, pour order 415): 617,1353 617,1199 354,1199 354,1352 355,1353
no net on Layer 1 - Top Layer "Top Layer-No Net 1" (solid, pour order 413): 764,1029 764,1357 642,1357 642,1030 641,1029
no net on Layer 1 - Top Layer "Top Layer-No Net 1" (solid, pour order 411): 495,996 495,1176 621,1176 620,1175 620,996
V_RADAR1 on Layer 1 - Top Layer "LAYER_1_-_TOP_LAYER_V_RADAR1_P128" (solid, remove dead copper, pour order 197): 1555,4290 1555,4343 1515,4343 1515,4353 1515,4393 1484,4393 1484,4353 1315,4353 1315,4408 1315,4757 1070,4757 1070,4360 905,4360 905,4140 990,4140 990,4290
V_RADAR2 on Layer 1 - Top Layer "LAYER_1_-_TOP_LAYER_V_RADAR2_P138" (solid, remove dead copper, pour order 202): 1555,3058 1555,3101 1515,3101 1515,3156 1487,3156 1487,3113 1315,3113 1315,3166 1315,3505 1070,3505 1070,3101 905,3101 905,2900 957,2900 957,3058
V_RADAR0 on Layer 1 - Top Layer "LAYER_1_-_TOP_LAYER_V_RADAR0_P098" (solid, remove dead copper, pour order 184): 1555,5500 1555,5585 1515,5585 1515,5599 1515,5640 1485,5640 1485,5599 1315,5599 1315,5650 1315,6002 1070,6002 1070,5570 905,5570 905,5350 990,5350 990,5500
V_RADAR3 on Layer 1 - Top Layer "Top Layer-No Net 1" (solid, pour order 405): 1070,2262 1070,2442 1196,2442 1195,2441 1195,2262
GND on Layer 1 - Top Layer "Top Layer-No Net 1" (solid, pour order 403): 1339,2295 1339,2623 1217,2623 1217,2296 1216,2295
NetC281_1 on Layer 1 - Top Layer "Top Layer-No Net 1" (solid, pour order 401): 1192,2619 1192,2465 929,2465 929,2618 930,2619
V_RADAR3 on Layer 1 - Top Layer "LAYER_1_-_TOP_LAYER_V_RADAR3_P140" (solid, remove dead copper, pour order 203): 1545,1819 1545,1841.2 1507.56,1841.2 1507.56,1875 1315,1875 1315,1924 1315,2268 1070,2268 1070,1854 905,1854 905,1656 950,1656 950,1819
GND on Layer 1 - Top Layer "LAYER_1_-_TOP_LAYER_GND_P311" (solid, remove dead copper, pour order 269): 4174.08,50.84 4499.08,50.84 4499.08,400.84 4174.08,400.84
GND on Layer 1 - Top Layer "LAYER_1_-_TOP_LAYER_GND_P309" (solid, remove dead copper, pour order 268): 3174.08,50.84 3499.08,50.84 3499.08,400.84 3174.08,400.84
GND on Layer 1 - Top Layer "LAYER_1_-_TOP_LAYER_GND_P307" (solid, remove dead copper, pour order 267): 2174.08,50.84 2499.08,50.84 2499.08,400.84 2174.08,400.84
NetC165_1 on Layer 1 - Top Layer "LAYER_1_-_TOP_LAYER_NETC165_1_P024" (solid, remove dead copper, pour order 152): 6180,4450 6180,4220 6500,4220 6500,4450
NetC132_1 on Layer 1 - Top Layer "LAYER_1_-_TOP_LAYER_NETC132_1_P269" (solid, remove dead copper, pour order 251): 2605,6615.97 1981.98,6615.97 1981.98,6313.46 2605,6313.46
GND on Layer 1 - Top Layer "LAYER_1_-_TOP_LAYER_GND_P241" (solid, remove dead copper, pour order 239): 2315,5985 2315,5800 2715,5800 2715,5985
GND on Layer 1 - Top Layer "LAYER_1_-_TOP_LAYER_GND_P040" (solid, remove dead copper, pour order 159): 6030,4585 5960,4585 5960,4375 5945,4375 5945,4325 6000,4325 6000,4545 6030,4545
NetC133_1 on Layer 1 - Top Layer "LAYER_1_-_TOP_LAYER_NETC133_1_P273" (solid, remove dead copper, pour order 253): 2300,5995 2056.15,5995 2056.15,6095 2955,6095 2955,5995
V_BAT on Layer 1 - Top Layer "LAYER_1_-_TOP_LAYER_V_BAT_P267" (solid, remove dead copper, pour order 250): 2625,6617.06 2625,6305 2925,6305 2925,6515 2925,6617.06
NetJ27_2 on Layer 1 - Top Layer "LAYER_1_-_TOP_LAYER_NETJ27_2_P253" (solid, remove dead copper, pour order 245): 3950,3540 3950,3220 4010,3220 4010,3315 4130,3315 4130,3430 4010,3430 4010,3540
5V on Layer 1 - Top Layer "LAYER_1_-_TOP_LAYER_5V_P245" (solid, remove dead copper, pour order 241): 5910,5811 5910,5570 5540,5570 5540,5811
12V on Layer 1 - Top Layer "LAYER_1_-_TOP_LAYER_12V_P223" (solid, remove dead copper, pour order 230): 4140,3995 4140,3725 4355,3725 4355,3360 3940,3360 3940,3630 3480,3630 3480,3995
GND on Layer 1 - Top Layer "LAYER_1_-_TOP_LAYER_GND_P221" (solid, remove dead copper, pour order 229): 3765,5355 3765,4275 3039.45,4275 3039.45,5355
NetC142_1 on Layer 1 - Top Layer "LAYER_1_-_TOP_LAYER_NETC142_1_P213" (solid, remove dead copper, pour order 227): 4160,5005 4160,4000 3480,4000 3480,4275 3735,4275 3735,5005
5V on Layer 1 - Top Layer "LAYER_1_-_TOP_LAYER_5V_P205" (solid, remove dead copper, pour order 223): 4995,5075 4995,4645 5030,4645 5030,4320 5500,4320 5500,5075
5V on Layer 1 - Top Layer "LAYER_1_-_TOP_LAYER_5V_P193" (solid, remove dead copper, pour order 218): 5545,5960 5545,5030 5150,5030 5000,5030 5000,5245 5150,5245 5150,5960
5V_OUT on Layer 1 - Top Layer "LAYER_1_-_TOP_LAYER_5V_OUT_P188" (solid, remove dead copper, pour order 216): 5110,6295 6225,6295 6225,5905 5768,5905 5768,5990 5110,5990
VIN_PROTECT on Layer 1 - Top Layer "LAYER_1_-_TOP_LAYER_VIN_PROTECT_P168" (solid, remove dead copper, pour order 215): 5025,6285 5025,6620 3600,6620 3600,6505 3279.53,6505 3065,6085 2965,6085 2965,5970 2720,5970 2720,5875 3080,5875 3080,5920 3141.73,5920 3370.15,6285
GND on Layer 1 - Top Layer "LAYER_1_-_TOP_LAYER_GND_P275" (solid, remove dead copper, pour order 254): 3122.05,6271.65 2950,6271.65 2950,6670 3122.05,6670
GND on Layer 1 - Top Layer "LAYER_1_-_TOP_LAYER_GND_P243" (solid, remove dead copper, pour order 240): 3060,6275 2650,6275 2650,6110 3060,6110
GND on Layer 1 - Top Layer "LAYER_1_-_TOP_LAYER_GND_P239" (solid, remove dead copper, pour order 238): 5120,6646 5120,6310 6245,6310 6245,5870 6645,5870 6645,6646
BOOST_SW on Layer 1 - Top Layer "LAYER_1_-_TOP_LAYER_BOOST_SW_P211" (solid, remove dead copper, pour order 226): 4490,4430 4490,3755 4165,3755 4165,3985 4165,4430
SW on Layer 1 - Top Layer "Top Layer-SW2" (solid, remove dead copper, pour order 212): 4597.68,6265 4325,6265 4325,6205 4240,6205 4240,6265 4100.71,6265 4091.57,6274.13 4091.57,5210 4597.65,5210
V_CAM1 on Layer 1 - Top Layer "LAYER_1_-_TOP_LAYER_V_CAM1_P050" (solid, remove dead copper, pour order 163): 2137.56,950.87 2032.56,950.87 2032.56,915.87 1987.56,915.87 1987.56,875.87 1927.56,875.87 1927.56,830.87 1902.56,830.87 1902.56,790.87 2002.56,790.87 2002.56,540.87 1732.56,540.87 1732.56,460.87 2217.56,460.87 2217.56,950.87
V_CAM3_UNPROT on Layer 1 - Top Layer "LAYER_1_-_TOP_LAYER_V_CAM3_UNPROT_P056" (solid, remove dead copper, pour order 164): 4012.56,910.87 3977.56,910.87 3977.56,950.87 3917.56,950.87 3917.56,985.87 3952.56,985.87 3952.56,1075.87 3977.56,1075.87 3977.56,1115.87 4077.56,1115.87 4077.56,1035.87 4012.56,1035.87
V_CAM2 on Layer 1 - Top Layer "LAYER_1_-_TOP_LAYER_V_CAM2_P058" (solid, remove dead copper, pour order 165): 3137.38,950.98 3032.38,950.98 3032.38,920.87 2967.56,920.87 2967.56,885.87 2912.56,885.87 2912.56,830.98 2902.38,830.98 2902.38,793.87 3002.38,793.87 3002.38,540.98 2732.38,540.98 2732.38,460.98 3217.38,460.98 3217.38,950.98
GND on Layer 1 - Top Layer "LAYER_1_-_TOP_LAYER_GND_P110" (solid, remove dead copper, pour order 190): 50,5029 50,4704 50,4594 400,4594 400,5029
GND on Layer 1 - Top Layer "LAYER_1_-_TOP_LAYER_GND_P112" (solid, remove dead copper, pour order 191): 50,3787 50,3462 50,3352 400,3352 400,3787
GND on Layer 1 - Top Layer "LAYER_1_-_TOP_LAYER_GND_P114" (solid, remove dead copper, pour order 192): 49.97,2545.48 49.97,2220.48 49.97,2110.48 399.97,2110.48 399.97,2545.48
V_RADAR1_UNPROT on Layer 1 - Top Layer "LAYER_1_-_TOP_LAYER_V_RADAR1_UNPROT_P136" (solid, remove dead copper, pour order 201): 1555,4343 1555,4270 1625,4270 1625,4398 1555,4398
V_RADAR2_UNPROT on Layer 1 - Top Layer "LAYER_1_-_TOP_LAYER_V_RADAR2_UNPROT_P142" (solid, remove dead copper, pour order 204): 1555,3101 1555,3028 1619.96,3028 1619.96,3156 1555,3156
V_RADAR3_UNPROT on Layer 1 - Top Layer "LAYER_1_-_TOP_LAYER_V_RADAR3_UNPROT_P144" (solid, remove dead copper, pour order 205): 1555,1858 1555,1786 1619.96,1786 1619.96,1903.05 1555,1903.05
NetL25_2 on Layer 1 - Top Layer "LAYER_1_-_TOP_LAYER_NETL25_2_P190" (solid, remove dead copper, pour order 217): 5030,6280 4785,6280 4785,6185 4625,6185 4625,5370 5030,5370
GND on Layer 1 - Top Layer "LAYER_1_-_TOP_LAYER_GND_P042" (solid, remove dead copper, pour order 160): 6085,5320 6085,5355 6125,5355 6125,5620 6175,5620 6175,5320
GND on Layer 1 - Top Layer "LAYER_1_-_TOP_LAYER_GND_P038" (solid, remove dead copper, pour order 158): 6085,4590 6170,4590 6170,4324.45 6125,4324.45 6125,4545 6085,4545
NetC158_1 on Layer 1 - Top Layer "LAYER_1_-_TOP_LAYER_NETC158_1_P036" (solid, remove dead copper, pour order 157): 6065,4865 6065,4535 6110,4535 6110,4405 6000,4405 6000,4535 6045,4535 6045,4865
NetC158_1 on Layer 1 - Top Layer "LAYER_1_-_TOP_LAYER_NETC158_1_P034" (solid, remove dead copper, pour order 156): 6110,5365 6110,5510 6110,5811 5925,5811 5925,5515 5910,5515 5910,5295 6045,5295 6045,5035 6065,5035 6065,5365
NetC156_1 on Layer 1 - Top Layer "LAYER_1_-_TOP_LAYER_NETC156_1_P032" (solid, remove dead copper, pour order 155): 6180,5690 6180,5460 6500,5460 6500,5690
NetC155_2 on Layer 1 - Top Layer "LAYER_1_-_TOP_LAYER_NETC155_2_P028" (solid, remove dead copper, pour order 154): 6090,5044.49 6090,5300 6506.26,5300 6505,5298.74 6505,5170 6235,5170 6235,5155 6165,5155 6165,5044.49
NetC161_1 on Layer 1 - Top Layer "LAYER_1_-_TOP_LAYER_NETC161_1_P026" (solid, remove dead copper, pour order 153): 5615,4450 5615,4220 5935,4220 5935,4450
NetC164_2 on Layer 1 - Top Layer "LAYER_1_-_TOP_LAYER_NETC164_2_P020" (solid, remove dead copper, pour order 151): 6104.21,4605.79 6104.21,4780.79 6104.21,4855.51 6170,4855.51 6170,4757.76 6505,4757.76 6505,4605.79
NetC160_2 on Layer 1 - Top Layer "LAYER_1_-_TOP_LAYER_NETC160_2_P018" (solid, remove dead copper, pour order 150): 6005.79,4780 6005.79,4605 5603.74,4605 5605,4606.26 5605,4753 5945,4753 5945,4855.51 6005.79,4855.51
V_CAM2_UNPROT on Layer 1 - Top Layer "LAYER_1_-_TOP_LAYER_V_CAM2_UNPROT_P197" (solid, remove dead copper, pour order 220): 3001.85,925.87 2966.85,925.87 2966.85,965.87 2906.85,965.87 2906.85,1000.87 2941.85,1000.87 2941.85,1090.87 2966.85,1090.87 2966.85,1130.87 3066.85,1130.87 3066.85,1050.87 3001.85,1050.87
V_CAM1_UNPROT on Layer 1 - Top Layer "LAYER_1_-_TOP_LAYER_V_CAM1_UNPROT_P199" (solid, remove dead copper, pour order 221): 2016.85,910.87 1981.85,910.87 1981.85,950.87 1921.85,950.87 1921.85,985.87 1956.85,985.87 1956.85,1075.87 1981.85,1075.87 1981.85,1115.87 2081.85,1115.87 2081.85,1035.87 2016.85,1035.87
AGND on Layer 1 - Top Layer "LAYER_1_-_TOP_LAYER_AGND_P249" (solid, remove dead copper, pour order 243): 3800,5470 3800,5650 3767,5650 3767,5524 3320,5524 3320,5650 3169,5650 3169,5752 3169,5816.18 3320,5816.18 3320,5895 3100,5895 3100,5470
NetJ22_2 on Layer 1 - Top Layer "LAYER_1_-_TOP_LAYER_NETJ22_2_P255" (solid, remove dead copper, pour order 246): 4370,3445 4370,3340 4240,3340 4240,3266 4583.54,3266 4583.54,3340 4455,3340 4455,3445
NetD1_2 on Layer 1 - Top Layer "LAYER_1_-_TOP_LAYER_NETD1_2_P271" (solid, remove dead copper, pour order 252): 2615,6270 2615,6110 2330,6110 2330,6270
GND on Layer 1 - Top Layer "LAYER_1_-_TOP_LAYER_GND_P277" (solid, remove dead copper, pour order 255): 456,1549 20,1549 20,1551 20,1970 456,1970
GND on Layer 1 - Top Layer "LAYER_1_-_TOP_LAYER_GND_P279" (solid, remove dead copper, pour order 256): 456,2791 20,2791 20,2793 20,3212 456,3212
GND on Layer 1 - Top Layer "LAYER_1_-_TOP_LAYER_GND_P281" (solid, remove dead copper, pour order 257): 456,4033 20,4033 20,4035 20,4454 456,4454
GND on Layer 1 - Top Layer "LAYER_1_-_TOP_LAYER_GND_P283" (solid, remove dead copper, pour order 258): 456,5275 20,5275 20,5277 20,5696 456,5696
GND on Layer 1 - Top Layer "LAYER_1_-_TOP_LAYER_GND_P291" (solid, remove dead copper, pour order 261): 3252,6666 3252,6522 3369,6522 3374.63,6522 3382,6522 3382,6666
GND on Layer 1 - Top Layer "LAYER_1_-_TOP_LAYER_GND_P335" (solid, remove dead copper, pour order 277): 995,5485 995,5245 1410,5245 1410,5485
GND on Layer 1 - Top Layer "LAYER_1_-_TOP_LAYER_GND_P337" (solid, remove dead copper, pour order 278): 994.98,4242.98 994.98,4002.98 1409.98,4002.98 1409.98,4242.98
GND on Layer 1 - Top Layer "LAYER_1_-_TOP_LAYER_GND_P339" (solid, remove dead copper, pour order 279): 994.98,3000.98 994.98,2760.98 1409.98,2760.98 1409.98,3000.98
GND on Layer 1 - Top Layer "LAYER_1_-_TOP_LAYER_GND_P341" (solid, remove dead copper, pour order 280): 994.98,1758.98 994.98,1518.98 1409.98,1518.98 1409.98,1758.98
NetC180_1 on Layer 1 - Top Layer "LAYER_1_-_TOP_LAYER_NETC180_1_P359" (solid, remove dead copper, pour order 289): 3709,5858 3656,5858 3656,5855.68 3626.54,5826.22 3627,5825.76 3627,5786 3627,5785 3639,5773 3640,5772 3709,5772
V_RADAR0_UNPROT on Layer 1 - Top Layer "LAYER_1_-_TOP_LAYER_V_RADAR0_UNPROT_P100" (solid, remove dead copper, pour order 185): 1555,5585 1555,5500 1622.69,5500 1622.69,5640 1555,5640
GND on Layer 1 - Top Layer "LAYER_1_-_TOP_LAYER_GND_P361" (solid, remove dead copper, pour order 290): 2027.56,1024.57 2027.56,954.87 2160.56,954.87 2160.56,1024.57
GND on Layer 1 - Top Layer "LAYER_1_-_TOP_LAYER_GND_P363" (solid, remove dead copper, pour order 291): 1027.56,1029.57 1027.56,959.87 1160.56,959.87 1160.56,1029.57
GND on Layer 1 - Top Layer "LAYER_1_-_TOP_LAYER_GND_P365" (solid, remove dead copper, pour order 292): 3005.56,1046.87 3005.56,977.17 3138.56,977.17 3138.56,1046.87
GND on Layer 1 - Top Layer "LAYER_1_-_TOP_LAYER_GND_P367" (solid, remove dead copper, pour order 293): 4019.56,1026.57 4019.56,956.87 4152.56,956.87 4152.56,1026.57
NetQ4_2 on Layer 1 - Top Layer "LAYER_1_-_TOP_LAYER_NETQ4_2_P207" (solid, remove dead copper, pour order 224): 5520,3620 5020,3620 5020,4310 5520,4310
GND on Layer 1 - Top Layer "LAYER_1_-_TOP_LAYER_GND_P215" (solid, remove dead copper, pour order 228): 5025.19,4295 4510,4295 4510,4440 4175,4440 4175,5075 5025,5075
GND on Layer 1 - Top Layer "Top Layer-No Net 1" (solid, pour order 339): 6663.23,409.85 6663.23,27.24 6655.13,35.34 5949.63,35.34 5949.63,388.59 5970.89,409.85
NetD3_3 on Layer 1 - Top Layer "LAYER_1_-_TOP_LAYER_NETD3_3_P209" (solid, remove dead copper, pour order 225): 5005,3620 4495,3620 4495,4280 5005,4280
GND on Layer 1 - Top Layer "LAYER_1_-_TOP_LAYER_GND_P235" (solid, remove dead copper, pour order 236): 4080,5150 3840,5150 3840,5761.38 3730,5761.38 3730,5870 3840,5870 3840,6145 3645,6145 3645,6290 4080,6290
V_CAM0 on Layer 1 - Top Layer "LAYER_1_-_TOP_LAYER_V_CAM0_P046" (solid, remove dead copper, pour order 162): 1137.56,950.87 1032.56,950.87 1032.56,915.87 987.56,915.87 987.56,875.87 927.56,875.87 927.56,830.87 902.56,830.87 902.56,789.87 1002.56,789.87 1002.56,540.87 732.56,540.87 732.56,460.87 1217.56,460.87 1217.56,950.87
V_CAM0_UNPROT on Layer 1 - Top Layer "LAYER_1_-_TOP_LAYER_V_CAM0_UNPROT_P201" (solid, remove dead copper, pour order 222): 1021.14,915.87 986.14,915.87 986.14,955.87 926.14,955.87 926.14,990.87 961.14,990.87 961.14,1080.87 986.14,1080.87 986.14,1120.87 1086.14,1120.87 1086.14,1040.87 1021.14,1040.87
V_RADAR1 on Layer 1 - Top Layer "Top Layer-No Net 1" (solid, pour order 427): 1070,4756.5 1070,4936.5 1196,4936.5 1195,4935.5 1195,4756.5
GND on Layer 6 - Bottom Layer "LAYER_6_-_BOTTOM_LAYER_GND_P351" (solid, remove dead copper, pour order 491): 1105,969 1819,969 1819,6425 1472,6425 1472,6652 1470,6654 36,6654 36,6257 55,6238 535,6238 535,6264 584,6313 1105,6313 1105,6166 20,6166 20,5015 1105,5015 1105,4929 20,4929 20,3770 1105,3770 1105,3684 20,3684 20,2521 1105,2521 1105,2442 20,2442 36,0 726,969
NetL51_2 on Layer 6 - Bottom Layer "Top Layer-No Net 1" (solid, pour order 481): 978,6071.98 978,6189 763,6189 758,6194 758,6276 577,6276 576,6275 576,6240 720,6240 724,6236 724,6148 772,6148 801,6119 801,6069.98
NetL51_1 on Layer 6 - Bottom Layer "Top Layer-No Net 1" (solid, pour order 479): 761,6082 640,6082 635,6087 635,6154 681,6154 682,6155 708,6129 754,6129 760,6123
NetL55_1 on Layer 6 - Bottom Layer "Top Layer-No Net 1" (solid, pour order 477): 501,6103 558,6103 574,6087 613,6087 613,6123 605,6131 501,6131
NetC251_1 on Layer 6 - Bottom Layer "Top Layer-No Net 1" (solid, pour order 473): 724,5094.97 725,5093.97 975,5093.97 975,4975.97 974,4976.97 802,4976.97 793,4985.97 793,5049.97 795,5051.97 792,5054.97 724,5054.97
NetL62_2 on Layer 6 - Bottom Layer "Top Layer-No Net 1" (solid, pour order 471): 980,4836 980,4946.97 765,4946.97 760,4951.97 760,5033.97 579,5033.97 578,5032.97 578,4997.97 722,4997.97 726,4993.97 726,4905.97 774,4905.97 803,4876.97 803,4834
NetL62_1 on Layer 6 - Bottom Layer "Top Layer-No Net 1" (solid, pour order 469): 763,4839.97 642,4839.97 637,4844.97 637,4911.97 683,4911.97 684,4912.97 710,4886.97 756,4886.97 762,4880.97
NetL64_1 on Layer 6 - Bottom Layer "Top Layer-No Net 1" (solid, pour order 467): 503,4861.97 560,4861.97 576,4845.97 615,4845.97 615,4881.97 607,4889.97 503,4889.97
NetL65_1 on Layer 6 - Bottom Layer "Top Layer-No Net 1" (solid, pour order 465): 423,4963.97 423,4924.97 540,4924.97 540,4963.97
NetC266_1 on Layer 6 - Bottom Layer "Top Layer-No Net 1" (solid, pour order 463): 718.5,3853 719.5,3852 969.5,3852 969.5,3734 968.5,3735 796.5,3735 787.5,3744 787.5,3808 789.5,3810 786.5,3813 718.5,3813
NetL70_2 on Layer 6 - Bottom Layer "Top Layer-No Net 1" (solid, pour order 461): 974.5,3588.98 974.5,3705 759.5,3705 754.5,3710 754.5,3792 573.5,3792 572.5,3791 572.5,3756 716.5,3756 720.5,3752 720.5,3664 768.5,3664 797.5,3635 797.5,3586.98
NetL70_1 on Layer 6 - Bottom Layer "Top Layer-No Net 1" (solid, pour order 459): 757.5,3598 636.5,3598 631.5,3603 631.5,3670 677.5,3670 678.5,3671 704.5,3645 750.5,3645 756.5,3639
NetL71_1 on Layer 6 - Bottom Layer "Top Layer-No Net 1" (solid, pour order 457): 497.5,3620 554.5,3620 570.5,3604 609.5,3604 609.5,3640 601.5,3648 497.5,3648
NetL72_1 on Layer 6 - Bottom Layer "Top Layer-No Net 1" (solid, pour order 455): 417.5,3722 417.5,3683 534.5,3683 534.5,3722
NetL76_1 on Layer 6 - Bottom Layer "Top Layer-No Net 1" (solid, pour order 399): 423,2480 423,2441 540,2441 540,2480
NetL75_1 on Layer 6 - Bottom Layer "Top Layer-No Net 1" (solid, pour order 397): 503,2378 560,2378 576,2362 615,2362 615,2398 607,2406 503,2406
NetL74_1 on Layer 6 - Bottom Layer "Top Layer-No Net 1" (solid, pour order 395): 763,2356 642,2356 637,2361 637,2428 683,2428 684,2429 710,2403 756,2403 762,2397
NetL74_2 on Layer 6 - Bottom Layer "Top Layer-No Net 1" (solid, pour order 393): 980,2325 980,2463 765,2463 760,2468 760,2550 579,2550 578,2549 578,2514 722,2514 726,2510 726,2422 774,2422 803,2393 803,2323
NetC281_1 on Layer 6 - Bottom Layer "Top Layer-No Net 1" (solid, pour order 391): 724,2611 725,2610 975,2610 975,2492 974,2493 802,2493 793,2502 793,2566 795,2568 792,2571 724,2571
NetC236_1 on Layer 6 - Bottom Layer "Top Layer-No Net 1" (solid, pour order 483): 722,6337 723,6336 973,6336 973,6218 972,6219 800,6219 791,6228 791,6292 793,6294 790,6297 722,6297
NetL57_1 on Layer 6 - Bottom Layer "Top Layer-No Net 1" (solid, pour order 475): 421,6206 421,6167 538,6167 538,6206
GND on Layer 6 - Bottom Layer "LAYER_6_-_BOTTOM_LAYER_GND_P124" (solid, remove dead copper, pour order 196): 50,2545 50,2220 50,2110 398.36,2110 398.36,2545
GND on Layer 6 - Bottom Layer "Top Layer-No Net 1" (solid, pour order 363): 1715.09,519.49 1715.09,46.09 1716.18,45 1600,45 1600,519.49
GND on Layer 6 - Bottom Layer "Top Layer-No Net 1" (solid, pour order 383): 3725.09,525 3725.09,51.6 3726.18,50.51 3610,50.51 3610,525
NetL39_2 on Layer 6 - Bottom Layer "Top Layer-No Net 1" (solid, pour order 379): 3861.93,601.92 3861.93,276.92 4191.93,276.92 4191.93,296.92 4126.93,361.92 4126.93,376.92 3906.93,376.92 3901.93,381.92 3901.93,601.92
NetL39_1 on Layer 6 - Bottom Layer "Top Layer-No Net 1" (solid, pour order 377): 3986.93,601.92 3986.93,411.92 3951.93,411.92 3951.93,601.92
V_CAM3 on Layer 6 - Bottom Layer "Top Layer-No Net 1" (solid, pour order 375): 3821.93,551.92 3752.93,551.92 3752.93,303.92 3821.93,303.92
GND on Layer 6 - Bottom Layer "Top Layer-No Net 1" (solid, pour order 373): 2725.09,520 2725.09,46.6 2726.18,45.51 2610,45.51 2610,520
NetL38_2 on Layer 6 - Bottom Layer "Top Layer-No Net 1" (solid, pour order 369): 2861.93,596.92 2861.93,271.92 3191.93,271.92 3191.93,291.92 3126.93,356.92 3126.93,371.92 2906.93,371.92 2901.93,376.92 2901.93,596.92
NetL38_1 on Layer 6 - Bottom Layer "Top Layer-No Net 1" (solid, pour order 367): 2986.93,596.92 2986.93,406.92 2951.93,406.92 2951.93,596.92
V_CAM2 on Layer 6 - Bottom Layer "Top Layer-No Net 1" (solid, pour order 365): 2821.93,546.92 2752.93,546.92 2752.93,298.92 2821.93,298.92
NetL29_2 on Layer 6 - Bottom Layer "Top Layer-No Net 1" (solid, pour order 359): 1851.93,596.41 1851.93,271.41 2181.93,271.41 2181.93,291.41 2116.93,356.41 2116.93,371.41 1896.93,371.41 1891.93,376.41 1891.93,596.41
NetL29_1 on Layer 6 - Bottom Layer "Top Layer-No Net 1" (solid, pour order 357): 1976.93,596.41 1976.93,406.41 1941.93,406.41 1941.93,596.41
V_CAM1 on Layer 6 - Bottom Layer "Top Layer-No Net 1" (solid, pour order 355): 1811.93,546.41 1742.93,546.41 1742.93,298.41 1811.93,298.41
NetC216_1 on Layer 6 - Bottom Layer "Top Layer-No Net 1" (solid, pour order 371): 2756.93,281.92 2756.93,86.92 3126.93,86.92 3126.93,186.92 3161.93,186.92 3161.93,201.92 3196.93,201.92 3196.93,221.92 2811.93,221.92 2811.93,281.92
NetC220_1 on Layer 6 - Bottom Layer "Top Layer-No Net 1" (solid, pour order 381): 3756.93,286.92 3756.93,91.92 4126.93,91.92 4126.93,191.92 4161.93,191.92 4161.93,206.92 4196.93,206.92 4196.93,226.92 3811.93,226.92 3811.93,286.92
NetC200_1 on Layer 6 - Bottom Layer "Top Layer-No Net 1" (solid, pour order 361): 1746.93,281.41 1746.93,86.41 2116.93,86.41 2116.93,186.41 2151.93,186.41 2151.93,201.41 2186.93,201.41 2186.93,221.41 1801.93,221.41 1801.93,281.41
V_CAM0 on Layer 6 - Bottom Layer "Top Layer-No Net 1" (solid, pour order 351): 820,550 751,550 751,302 820,302
NetL28_1 on Layer 6 - Bottom Layer "Top Layer-No Net 1" (solid, pour order 349): 985,600 985,410 950,410 950,600
NetL28_2 on Layer 6 - Bottom Layer "Top Layer-No Net 1" (solid, pour order 347): 860,600 860,275 1190,275 1190,295 1125,360 1125,375 905,375 900,380 900,600
NetC196_1 on Layer 6 - Bottom Layer "Top Layer-No Net 1" (solid, pour order 343): 755,285 755,90 1125,90 1125,190 1160,190 1160,205 1195,205 1195,225 810,225 810,285
GND on Layer 6 - Bottom Layer "Top Layer-No Net 1" (solid, pour order 341): 723.16,523.08 723.16,49.68 724.25,48.59 608.07,48.59 608.07,523.08
V_BAT on Layer 6 - Bottom Layer "Top Layer-No Net 1" (solid, pour order 294): 2980.31,6523.62 2984.25,6523.62 2984.25,6259.84 2980.31,6255.91 2625,6255.91 2625,6523.62
NetC142_1 on Layer 6 - Bottom Layer "LAYER_6_-_BOTTOM_LAYER_NETC142_1_P233" (solid, remove dead copper, pour order 235): 4160,5005 4160,4000 3480,4000 3480,4275 3735,4275 3735,5005
GND on Layer 6 - Bottom Layer "Top Layer-No Net 1" (solid, pour order 296): 3366.14,6658.38 3045.31,6658.38 3030,6643.07 3030,6203.23 3015.75,6188.98 2700.79,6188.98 2700.79,6094.49 3216.54,6094.49 3216.54,6295.28 3279.53,6358.27 3366.14,6358.27
GND on Layer 6 - Bottom Layer "LAYER_6_-_BOTTOM_LAYER_GND_P237" (solid, remove dead copper, pour order 237): 4080,5150 3840,5150 3840,6000 3275,6000 3275,6290 4080,6290
BOOST_SW on Layer 6 - Bottom Layer "LAYER_6_-_BOTTOM_LAYER_BOOST_SW_P231" (solid, remove dead copper, pour order 234): 4490,4430 4490,3620 3955,3620 3955,3985 4165,3985 4165,4430
GND on Layer 6 - Bottom Layer "LAYER_6_-_BOTTOM_LAYER_GND_P229" (solid, remove dead copper, pour order 233): 5025.2,4285 4510,4285 4510,4440 4175,4440 4175,5075 5025,5075
NetQ4_2 on Layer 6 - Bottom Layer "LAYER_6_-_BOTTOM_LAYER_NETQ4_2_P227" (solid, remove dead copper, pour order 232): 5510,3620 5020,3620 5020,4310 5510,4310
NetD3_3 on Layer 6 - Bottom Layer "LAYER_6_-_BOTTOM_LAYER_NETD3_3_P225" (solid, remove dead copper, pour order 231): 5010,3620 4495,3620 4495,4280 5010,4280
SW on Layer 6 - Bottom Layer "Bottom Layer-SW2" (solid, remove dead copper, pour order 214): 4100,5241.22 4100,5665 4100,6175 4590,6175 4590,5241.22
GND on Layer 6 - Bottom Layer "LAYER_6_-_BOTTOM_LAYER_GND_P259" (solid, remove dead copper, pour order 247): 2095.1,1951.58 1960,1951.58 1960,1866.58 2095.1,1866.58
VIN_PROTECT on Layer 6 - Bottom Layer "LAYER_6_-_BOTTOM_LAYER_VIN_PROTECT_P287" (solid, remove dead copper, pour order 259): 5025,6620 5025,6310 3665,6310 3665,6620
NetL25_2 on Layer 6 - Bottom Layer "LAYER_6_-_BOTTOM_LAYER_NETL25_2_P289" (solid, remove dead copper, pour order 260): 5030,6270 4785,6270 4785,6185 4625,6185 4625,5370 5030,5370
GND on Layer 6 - Bottom Layer "LAYER_6_-_BOTTOM_LAYER_GND_P293" (solid, remove dead copper, pour order 262): 5120,6646 5120,6310 6245,6310 6245,5870 6645,5870 6645,6646
NetR252_1 on Layer 6 - Bottom Layer "LAYER_6_-_BOTTOM_LAYER_NETR252_1_P299" (solid, remove dead copper, pour order 264): 2032.79,1984.09 2092.79,1984.09 2092.79,2119.09 2032.79,2119.09
NetR32_1 on Layer 6 - Bottom Layer "LAYER_6_-_BOTTOM_LAYER_NETR32_1_P303" (solid, remove dead copper, pour order 265): 2102.79,2069.09 2102.79,2139.09 2007.79,2139.09 2007.79,2199.09 2212.79,2199.09 2212.79,2139.09 2152.79,2139.09 2152.79,2069.09
AGND2 on Layer 6 - Bottom Layer "LAYER_6_-_BOTTOM_LAYER_AGND2_P251" (solid, remove dead copper, pour order 244): 3216,5179.48 3038.84,5179.48 3038.84,4472.24 3270.5,4472.24 3270.5,4734.48 3216,4734.48
GND on Layer 6 - Bottom Layer "LAYER_6_-_BOTTOM_LAYER_GND_P321" (solid, remove dead copper, pour order 274): 2654.09,1799.33 2654.09,1427.28 3026.14,1427.28 3026.14,1799.33
GND on Layer 6 - Bottom Layer "LAYER_6_-_BOTTOM_LAYER_GND_P323" (solid, remove dead copper, pour order 275): 2178.22,4233.86 2178.22,3861.81 2550.27,3861.81 2550.27,4233.86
